VERSION 5.8 ;
BUSBITCHARS "[]" ;
DIVIDERCHAR "/" ;
UNITS
    DATABASE MICRONS 1000 ;
END UNITS

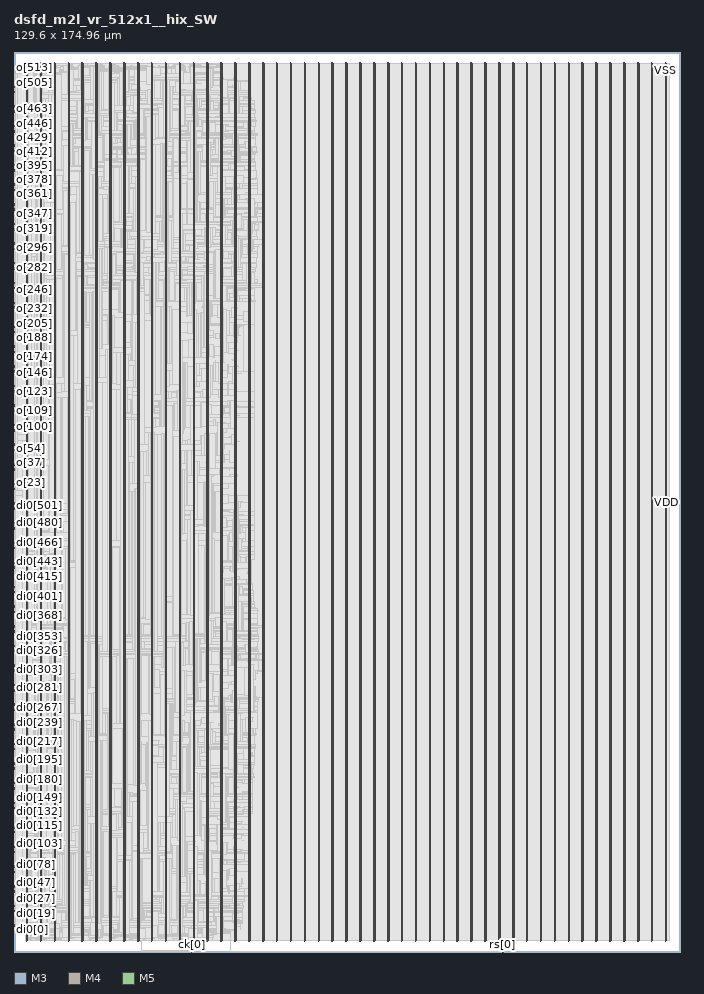
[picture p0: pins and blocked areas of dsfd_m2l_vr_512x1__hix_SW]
MACRO dsfd_m2l_vr_512x1__hix_SW
  FOREIGN dsfd_m2l_vr_512x1__hix_SW 0 0 ;
  CLASS BLOCK ;
  SIZE 129.6 BY 174.96 ;
  PIN ck[0]
    DIRECTION INPUT ;
    USE SIGNAL ;
    PORT
      LAYER M3 ;
        RECT  34.56 0 34.578 0.144 ;
    END
    PORT
      LAYER M3 ;
        RECT  34.56 0.108 34.578 0.221 ;
    END
  END ck[0]
  PIN di0[0]
    DIRECTION INPUT ;
    USE SIGNAL ;
    PORT
      LAYER M4 ;
        RECT  0 4.416 0.192 4.44 ;
    END
  END di0[0]
  PIN di0[100]
    DIRECTION INPUT ;
    USE SIGNAL ;
    PORT
      LAYER M4 ;
        RECT  0 20.544 0.192 20.568 ;
    END
  END di0[100]
  PIN di0[101]
    DIRECTION INPUT ;
    USE SIGNAL ;
    PORT
      LAYER M4 ;
        RECT  0 20.736 0.192 20.76 ;
    END
  END di0[101]
  PIN di0[102]
    DIRECTION INPUT ;
    USE SIGNAL ;
    PORT
      LAYER M4 ;
        RECT  0 20.88 0.192 20.904 ;
    END
  END di0[102]
  PIN di0[103]
    DIRECTION INPUT ;
    USE SIGNAL ;
    PORT
      LAYER M4 ;
        RECT  0 21.024 0.192 21.048 ;
    END
  END di0[103]
  PIN di0[104]
    DIRECTION INPUT ;
    USE SIGNAL ;
    PORT
      LAYER M4 ;
        RECT  0 21.216 0.192 21.24 ;
    END
  END di0[104]
  PIN di0[105]
    DIRECTION INPUT ;
    USE SIGNAL ;
    PORT
      LAYER M4 ;
        RECT  0 21.36 0.192 21.384 ;
    END
  END di0[105]
  PIN di0[106]
    DIRECTION INPUT ;
    USE SIGNAL ;
    PORT
      LAYER M4 ;
        RECT  0 21.552 0.192 21.576 ;
    END
  END di0[106]
  PIN di0[107]
    DIRECTION INPUT ;
    USE SIGNAL ;
    PORT
      LAYER M4 ;
        RECT  0 21.696 0.192 21.72 ;
    END
  END di0[107]
  PIN di0[108]
    DIRECTION INPUT ;
    USE SIGNAL ;
    PORT
      LAYER M4 ;
        RECT  0 21.84 0.192 21.864 ;
    END
  END di0[108]
  PIN di0[109]
    DIRECTION INPUT ;
    USE SIGNAL ;
    PORT
      LAYER M4 ;
        RECT  0 22.032 0.192 22.056 ;
    END
  END di0[109]
  PIN di0[10]
    DIRECTION INPUT ;
    USE SIGNAL ;
    PORT
      LAYER M4 ;
        RECT  0 6.048 0.192 6.072 ;
    END
  END di0[10]
  PIN di0[110]
    DIRECTION INPUT ;
    USE SIGNAL ;
    PORT
      LAYER M4 ;
        RECT  0 22.176 0.192 22.2 ;
    END
  END di0[110]
  PIN di0[111]
    DIRECTION INPUT ;
    USE SIGNAL ;
    PORT
      LAYER M4 ;
        RECT  0 22.32 0.192 22.344 ;
    END
  END di0[111]
  PIN di0[112]
    DIRECTION INPUT ;
    USE SIGNAL ;
    PORT
      LAYER M4 ;
        RECT  0 22.512 0.192 22.536 ;
    END
  END di0[112]
  PIN di0[113]
    DIRECTION INPUT ;
    USE SIGNAL ;
    PORT
      LAYER M4 ;
        RECT  0 22.656 0.192 22.68 ;
    END
  END di0[113]
  PIN di0[114]
    DIRECTION INPUT ;
    USE SIGNAL ;
    PORT
      LAYER M4 ;
        RECT  0 22.8 0.192 22.824 ;
    END
  END di0[114]
  PIN di0[115]
    DIRECTION INPUT ;
    USE SIGNAL ;
    PORT
      LAYER M4 ;
        RECT  0 22.992 0.192 23.016 ;
    END
  END di0[115]
  PIN di0[116]
    DIRECTION INPUT ;
    USE SIGNAL ;
    PORT
      LAYER M4 ;
        RECT  0 23.136 0.192 23.16 ;
    END
  END di0[116]
  PIN di0[117]
    DIRECTION INPUT ;
    USE SIGNAL ;
    PORT
      LAYER M4 ;
        RECT  0 23.328 0.192 23.352 ;
    END
  END di0[117]
  PIN di0[118]
    DIRECTION INPUT ;
    USE SIGNAL ;
    PORT
      LAYER M4 ;
        RECT  0 23.472 0.192 23.496 ;
    END
  END di0[118]
  PIN di0[119]
    DIRECTION INPUT ;
    USE SIGNAL ;
    PORT
      LAYER M4 ;
        RECT  0 23.616 0.192 23.64 ;
    END
  END di0[119]
  PIN di0[11]
    DIRECTION INPUT ;
    USE SIGNAL ;
    PORT
      LAYER M4 ;
        RECT  0 6.192 0.192 6.216 ;
    END
  END di0[11]
  PIN di0[120]
    DIRECTION INPUT ;
    USE SIGNAL ;
    PORT
      LAYER M4 ;
        RECT  0 23.808 0.192 23.832 ;
    END
  END di0[120]
  PIN di0[121]
    DIRECTION INPUT ;
    USE SIGNAL ;
    PORT
      LAYER M4 ;
        RECT  0 23.952 0.192 23.976 ;
    END
  END di0[121]
  PIN di0[122]
    DIRECTION INPUT ;
    USE SIGNAL ;
    PORT
      LAYER M4 ;
        RECT  0 24.096 0.192 24.12 ;
    END
  END di0[122]
  PIN di0[123]
    DIRECTION INPUT ;
    USE SIGNAL ;
    PORT
      LAYER M4 ;
        RECT  0 24.288 0.192 24.312 ;
    END
  END di0[123]
  PIN di0[124]
    DIRECTION INPUT ;
    USE SIGNAL ;
    PORT
      LAYER M4 ;
        RECT  0 24.432 0.192 24.456 ;
    END
  END di0[124]
  PIN di0[125]
    DIRECTION INPUT ;
    USE SIGNAL ;
    PORT
      LAYER M4 ;
        RECT  0 24.576 0.192 24.6 ;
    END
  END di0[125]
  PIN di0[126]
    DIRECTION INPUT ;
    USE SIGNAL ;
    PORT
      LAYER M4 ;
        RECT  0 24.768 0.192 24.792 ;
    END
  END di0[126]
  PIN di0[127]
    DIRECTION INPUT ;
    USE SIGNAL ;
    PORT
      LAYER M4 ;
        RECT  0 24.912 0.192 24.936 ;
    END
  END di0[127]
  PIN di0[128]
    DIRECTION INPUT ;
    USE SIGNAL ;
    PORT
      LAYER M4 ;
        RECT  0 25.104 0.192 25.128 ;
    END
  END di0[128]
  PIN di0[129]
    DIRECTION INPUT ;
    USE SIGNAL ;
    PORT
      LAYER M4 ;
        RECT  0 25.248 0.192 25.272 ;
    END
  END di0[129]
  PIN di0[12]
    DIRECTION INPUT ;
    USE SIGNAL ;
    PORT
      LAYER M4 ;
        RECT  0 6.336 0.192 6.36 ;
    END
  END di0[12]
  PIN di0[130]
    DIRECTION INPUT ;
    USE SIGNAL ;
    PORT
      LAYER M4 ;
        RECT  0 25.392 0.192 25.416 ;
    END
  END di0[130]
  PIN di0[131]
    DIRECTION INPUT ;
    USE SIGNAL ;
    PORT
      LAYER M4 ;
        RECT  0 25.584 0.192 25.608 ;
    END
  END di0[131]
  PIN di0[132]
    DIRECTION INPUT ;
    USE SIGNAL ;
    PORT
      LAYER M4 ;
        RECT  0 25.728 0.192 25.752 ;
    END
  END di0[132]
  PIN di0[133]
    DIRECTION INPUT ;
    USE SIGNAL ;
    PORT
      LAYER M4 ;
        RECT  0 25.872 0.192 25.896 ;
    END
  END di0[133]
  PIN di0[134]
    DIRECTION INPUT ;
    USE SIGNAL ;
    PORT
      LAYER M4 ;
        RECT  0 26.064 0.192 26.088 ;
    END
  END di0[134]
  PIN di0[135]
    DIRECTION INPUT ;
    USE SIGNAL ;
    PORT
      LAYER M4 ;
        RECT  0 26.208 0.192 26.232 ;
    END
  END di0[135]
  PIN di0[136]
    DIRECTION INPUT ;
    USE SIGNAL ;
    PORT
      LAYER M4 ;
        RECT  0 26.352 0.192 26.376 ;
    END
  END di0[136]
  PIN di0[137]
    DIRECTION INPUT ;
    USE SIGNAL ;
    PORT
      LAYER M4 ;
        RECT  0 26.544 0.192 26.568 ;
    END
  END di0[137]
  PIN di0[138]
    DIRECTION INPUT ;
    USE SIGNAL ;
    PORT
      LAYER M4 ;
        RECT  0 26.688 0.192 26.712 ;
    END
  END di0[138]
  PIN di0[139]
    DIRECTION INPUT ;
    USE SIGNAL ;
    PORT
      LAYER M4 ;
        RECT  0 26.88 0.192 26.904 ;
    END
  END di0[139]
  PIN di0[13]
    DIRECTION INPUT ;
    USE SIGNAL ;
    PORT
      LAYER M4 ;
        RECT  0 6.528 0.192 6.552 ;
    END
  END di0[13]
  PIN di0[140]
    DIRECTION INPUT ;
    USE SIGNAL ;
    PORT
      LAYER M4 ;
        RECT  0 27.024 0.192 27.048 ;
    END
  END di0[140]
  PIN di0[141]
    DIRECTION INPUT ;
    USE SIGNAL ;
    PORT
      LAYER M4 ;
        RECT  0 27.168 0.192 27.192 ;
    END
  END di0[141]
  PIN di0[142]
    DIRECTION INPUT ;
    USE SIGNAL ;
    PORT
      LAYER M4 ;
        RECT  0 27.36 0.192 27.384 ;
    END
  END di0[142]
  PIN di0[143]
    DIRECTION INPUT ;
    USE SIGNAL ;
    PORT
      LAYER M4 ;
        RECT  0 27.504 0.192 27.528 ;
    END
  END di0[143]
  PIN di0[144]
    DIRECTION INPUT ;
    USE SIGNAL ;
    PORT
      LAYER M4 ;
        RECT  0 27.648 0.192 27.672 ;
    END
  END di0[144]
  PIN di0[145]
    DIRECTION INPUT ;
    USE SIGNAL ;
    PORT
      LAYER M4 ;
        RECT  0 27.84 0.192 27.864 ;
    END
  END di0[145]
  PIN di0[146]
    DIRECTION INPUT ;
    USE SIGNAL ;
    PORT
      LAYER M4 ;
        RECT  0 27.984 0.192 28.008 ;
    END
  END di0[146]
  PIN di0[147]
    DIRECTION INPUT ;
    USE SIGNAL ;
    PORT
      LAYER M4 ;
        RECT  0 28.128 0.192 28.152 ;
    END
  END di0[147]
  PIN di0[148]
    DIRECTION INPUT ;
    USE SIGNAL ;
    PORT
      LAYER M4 ;
        RECT  0 28.32 0.192 28.344 ;
    END
  END di0[148]
  PIN di0[149]
    DIRECTION INPUT ;
    USE SIGNAL ;
    PORT
      LAYER M4 ;
        RECT  0 28.464 0.192 28.488 ;
    END
  END di0[149]
  PIN di0[14]
    DIRECTION INPUT ;
    USE SIGNAL ;
    PORT
      LAYER M4 ;
        RECT  0 6.672 0.192 6.696 ;
    END
  END di0[14]
  PIN di0[150]
    DIRECTION INPUT ;
    USE SIGNAL ;
    PORT
      LAYER M4 ;
        RECT  0 28.656 0.192 28.68 ;
    END
  END di0[150]
  PIN di0[151]
    DIRECTION INPUT ;
    USE SIGNAL ;
    PORT
      LAYER M4 ;
        RECT  0 28.8 0.192 28.824 ;
    END
  END di0[151]
  PIN di0[152]
    DIRECTION INPUT ;
    USE SIGNAL ;
    PORT
      LAYER M4 ;
        RECT  0 28.944 0.192 28.968 ;
    END
  END di0[152]
  PIN di0[153]
    DIRECTION INPUT ;
    USE SIGNAL ;
    PORT
      LAYER M4 ;
        RECT  0 29.136 0.192 29.16 ;
    END
  END di0[153]
  PIN di0[154]
    DIRECTION INPUT ;
    USE SIGNAL ;
    PORT
      LAYER M4 ;
        RECT  0 29.28 0.192 29.304 ;
    END
  END di0[154]
  PIN di0[155]
    DIRECTION INPUT ;
    USE SIGNAL ;
    PORT
      LAYER M4 ;
        RECT  0 29.424 0.192 29.448 ;
    END
  END di0[155]
  PIN di0[156]
    DIRECTION INPUT ;
    USE SIGNAL ;
    PORT
      LAYER M4 ;
        RECT  0 29.616 0.192 29.64 ;
    END
  END di0[156]
  PIN di0[157]
    DIRECTION INPUT ;
    USE SIGNAL ;
    PORT
      LAYER M4 ;
        RECT  0 29.76 0.192 29.784 ;
    END
  END di0[157]
  PIN di0[158]
    DIRECTION INPUT ;
    USE SIGNAL ;
    PORT
      LAYER M4 ;
        RECT  0 29.904 0.192 29.928 ;
    END
  END di0[158]
  PIN di0[159]
    DIRECTION INPUT ;
    USE SIGNAL ;
    PORT
      LAYER M4 ;
        RECT  0 30.096 0.192 30.12 ;
    END
  END di0[159]
  PIN di0[15]
    DIRECTION INPUT ;
    USE SIGNAL ;
    PORT
      LAYER M4 ;
        RECT  0 6.816 0.192 6.84 ;
    END
  END di0[15]
  PIN di0[160]
    DIRECTION INPUT ;
    USE SIGNAL ;
    PORT
      LAYER M4 ;
        RECT  0 30.24 0.192 30.264 ;
    END
  END di0[160]
  PIN di0[161]
    DIRECTION INPUT ;
    USE SIGNAL ;
    PORT
      LAYER M4 ;
        RECT  0 30.432 0.192 30.456 ;
    END
  END di0[161]
  PIN di0[162]
    DIRECTION INPUT ;
    USE SIGNAL ;
    PORT
      LAYER M4 ;
        RECT  0 30.576 0.192 30.6 ;
    END
  END di0[162]
  PIN di0[163]
    DIRECTION INPUT ;
    USE SIGNAL ;
    PORT
      LAYER M4 ;
        RECT  0 30.72 0.192 30.744 ;
    END
  END di0[163]
  PIN di0[164]
    DIRECTION INPUT ;
    USE SIGNAL ;
    PORT
      LAYER M4 ;
        RECT  0 30.912 0.192 30.936 ;
    END
  END di0[164]
  PIN di0[165]
    DIRECTION INPUT ;
    USE SIGNAL ;
    PORT
      LAYER M4 ;
        RECT  0 31.056 0.192 31.08 ;
    END
  END di0[165]
  PIN di0[166]
    DIRECTION INPUT ;
    USE SIGNAL ;
    PORT
      LAYER M4 ;
        RECT  0 31.2 0.192 31.224 ;
    END
  END di0[166]
  PIN di0[167]
    DIRECTION INPUT ;
    USE SIGNAL ;
    PORT
      LAYER M4 ;
        RECT  0 31.392 0.192 31.416 ;
    END
  END di0[167]
  PIN di0[168]
    DIRECTION INPUT ;
    USE SIGNAL ;
    PORT
      LAYER M4 ;
        RECT  0 31.536 0.192 31.56 ;
    END
  END di0[168]
  PIN di0[169]
    DIRECTION INPUT ;
    USE SIGNAL ;
    PORT
      LAYER M4 ;
        RECT  0 31.68 0.192 31.704 ;
    END
  END di0[169]
  PIN di0[16]
    DIRECTION INPUT ;
    USE SIGNAL ;
    PORT
      LAYER M4 ;
        RECT  0 7.008 0.192 7.032 ;
    END
  END di0[16]
  PIN di0[170]
    DIRECTION INPUT ;
    USE SIGNAL ;
    PORT
      LAYER M4 ;
        RECT  0 31.872 0.192 31.896 ;
    END
  END di0[170]
  PIN di0[171]
    DIRECTION INPUT ;
    USE SIGNAL ;
    PORT
      LAYER M4 ;
        RECT  0 32.016 0.192 32.04 ;
    END
  END di0[171]
  PIN di0[172]
    DIRECTION INPUT ;
    USE SIGNAL ;
    PORT
      LAYER M4 ;
        RECT  0 32.208 0.192 32.232 ;
    END
  END di0[172]
  PIN di0[173]
    DIRECTION INPUT ;
    USE SIGNAL ;
    PORT
      LAYER M4 ;
        RECT  0 32.352 0.192 32.376 ;
    END
  END di0[173]
  PIN di0[174]
    DIRECTION INPUT ;
    USE SIGNAL ;
    PORT
      LAYER M4 ;
        RECT  0 32.496 0.192 32.52 ;
    END
  END di0[174]
  PIN di0[175]
    DIRECTION INPUT ;
    USE SIGNAL ;
    PORT
      LAYER M4 ;
        RECT  0 32.688 0.192 32.712 ;
    END
  END di0[175]
  PIN di0[176]
    DIRECTION INPUT ;
    USE SIGNAL ;
    PORT
      LAYER M4 ;
        RECT  0 32.832 0.192 32.856 ;
    END
  END di0[176]
  PIN di0[177]
    DIRECTION INPUT ;
    USE SIGNAL ;
    PORT
      LAYER M4 ;
        RECT  0 32.976 0.192 33 ;
    END
  END di0[177]
  PIN di0[178]
    DIRECTION INPUT ;
    USE SIGNAL ;
    PORT
      LAYER M4 ;
        RECT  0 33.168 0.192 33.192 ;
    END
  END di0[178]
  PIN di0[179]
    DIRECTION INPUT ;
    USE SIGNAL ;
    PORT
      LAYER M4 ;
        RECT  0 33.312 0.192 33.336 ;
    END
  END di0[179]
  PIN di0[17]
    DIRECTION INPUT ;
    USE SIGNAL ;
    PORT
      LAYER M4 ;
        RECT  0 7.152 0.192 7.176 ;
    END
  END di0[17]
  PIN di0[180]
    DIRECTION INPUT ;
    USE SIGNAL ;
    PORT
      LAYER M4 ;
        RECT  0 33.456 0.192 33.48 ;
    END
  END di0[180]
  PIN di0[181]
    DIRECTION INPUT ;
    USE SIGNAL ;
    PORT
      LAYER M4 ;
        RECT  0 33.648 0.192 33.672 ;
    END
  END di0[181]
  PIN di0[182]
    DIRECTION INPUT ;
    USE SIGNAL ;
    PORT
      LAYER M4 ;
        RECT  0 33.792 0.192 33.816 ;
    END
  END di0[182]
  PIN di0[183]
    DIRECTION INPUT ;
    USE SIGNAL ;
    PORT
      LAYER M4 ;
        RECT  0 33.984 0.192 34.008 ;
    END
  END di0[183]
  PIN di0[184]
    DIRECTION INPUT ;
    USE SIGNAL ;
    PORT
      LAYER M4 ;
        RECT  0 34.128 0.192 34.152 ;
    END
  END di0[184]
  PIN di0[185]
    DIRECTION INPUT ;
    USE SIGNAL ;
    PORT
      LAYER M4 ;
        RECT  0 34.272 0.192 34.296 ;
    END
  END di0[185]
  PIN di0[186]
    DIRECTION INPUT ;
    USE SIGNAL ;
    PORT
      LAYER M4 ;
        RECT  0 34.464 0.192 34.488 ;
    END
  END di0[186]
  PIN di0[187]
    DIRECTION INPUT ;
    USE SIGNAL ;
    PORT
      LAYER M4 ;
        RECT  0 34.608 0.192 34.632 ;
    END
  END di0[187]
  PIN di0[188]
    DIRECTION INPUT ;
    USE SIGNAL ;
    PORT
      LAYER M4 ;
        RECT  0 34.752 0.192 34.776 ;
    END
  END di0[188]
  PIN di0[189]
    DIRECTION INPUT ;
    USE SIGNAL ;
    PORT
      LAYER M4 ;
        RECT  0 34.944 0.192 34.968 ;
    END
  END di0[189]
  PIN di0[18]
    DIRECTION INPUT ;
    USE SIGNAL ;
    PORT
      LAYER M4 ;
        RECT  0 7.296 0.192 7.32 ;
    END
  END di0[18]
  PIN di0[190]
    DIRECTION INPUT ;
    USE SIGNAL ;
    PORT
      LAYER M4 ;
        RECT  0 35.088 0.192 35.112 ;
    END
  END di0[190]
  PIN di0[191]
    DIRECTION INPUT ;
    USE SIGNAL ;
    PORT
      LAYER M4 ;
        RECT  0 35.232 0.192 35.256 ;
    END
  END di0[191]
  PIN di0[192]
    DIRECTION INPUT ;
    USE SIGNAL ;
    PORT
      LAYER M4 ;
        RECT  0 35.424 0.192 35.448 ;
    END
  END di0[192]
  PIN di0[193]
    DIRECTION INPUT ;
    USE SIGNAL ;
    PORT
      LAYER M4 ;
        RECT  0 35.568 0.192 35.592 ;
    END
  END di0[193]
  PIN di0[194]
    DIRECTION INPUT ;
    USE SIGNAL ;
    PORT
      LAYER M4 ;
        RECT  0 35.76 0.192 35.784 ;
    END
  END di0[194]
  PIN di0[195]
    DIRECTION INPUT ;
    USE SIGNAL ;
    PORT
      LAYER M4 ;
        RECT  0 35.904 0.192 35.928 ;
    END
  END di0[195]
  PIN di0[196]
    DIRECTION INPUT ;
    USE SIGNAL ;
    PORT
      LAYER M4 ;
        RECT  0 36.048 0.192 36.072 ;
    END
  END di0[196]
  PIN di0[197]
    DIRECTION INPUT ;
    USE SIGNAL ;
    PORT
      LAYER M4 ;
        RECT  0 36.24 0.192 36.264 ;
    END
  END di0[197]
  PIN di0[198]
    DIRECTION INPUT ;
    USE SIGNAL ;
    PORT
      LAYER M4 ;
        RECT  0 36.384 0.192 36.408 ;
    END
  END di0[198]
  PIN di0[199]
    DIRECTION INPUT ;
    USE SIGNAL ;
    PORT
      LAYER M4 ;
        RECT  0 36.528 0.192 36.552 ;
    END
  END di0[199]
  PIN di0[19]
    DIRECTION INPUT ;
    USE SIGNAL ;
    PORT
      LAYER M4 ;
        RECT  0 7.488 0.192 7.512 ;
    END
  END di0[19]
  PIN di0[1]
    DIRECTION INPUT ;
    USE SIGNAL ;
    PORT
      LAYER M4 ;
        RECT  0 4.56 0.192 4.584 ;
    END
  END di0[1]
  PIN di0[200]
    DIRECTION INPUT ;
    USE SIGNAL ;
    PORT
      LAYER M4 ;
        RECT  0 36.72 0.192 36.744 ;
    END
  END di0[200]
  PIN di0[201]
    DIRECTION INPUT ;
    USE SIGNAL ;
    PORT
      LAYER M4 ;
        RECT  0 36.864 0.192 36.888 ;
    END
  END di0[201]
  PIN di0[202]
    DIRECTION INPUT ;
    USE SIGNAL ;
    PORT
      LAYER M4 ;
        RECT  0 37.008 0.192 37.032 ;
    END
  END di0[202]
  PIN di0[203]
    DIRECTION INPUT ;
    USE SIGNAL ;
    PORT
      LAYER M4 ;
        RECT  0 37.2 0.192 37.224 ;
    END
  END di0[203]
  PIN di0[204]
    DIRECTION INPUT ;
    USE SIGNAL ;
    PORT
      LAYER M4 ;
        RECT  0 37.344 0.192 37.368 ;
    END
  END di0[204]
  PIN di0[205]
    DIRECTION INPUT ;
    USE SIGNAL ;
    PORT
      LAYER M4 ;
        RECT  0 37.536 0.192 37.56 ;
    END
  END di0[205]
  PIN di0[206]
    DIRECTION INPUT ;
    USE SIGNAL ;
    PORT
      LAYER M4 ;
        RECT  0 37.68 0.192 37.704 ;
    END
  END di0[206]
  PIN di0[207]
    DIRECTION INPUT ;
    USE SIGNAL ;
    PORT
      LAYER M4 ;
        RECT  0 37.824 0.192 37.848 ;
    END
  END di0[207]
  PIN di0[208]
    DIRECTION INPUT ;
    USE SIGNAL ;
    PORT
      LAYER M4 ;
        RECT  0 38.016 0.192 38.04 ;
    END
  END di0[208]
  PIN di0[209]
    DIRECTION INPUT ;
    USE SIGNAL ;
    PORT
      LAYER M4 ;
        RECT  0 38.16 0.192 38.184 ;
    END
  END di0[209]
  PIN di0[20]
    DIRECTION INPUT ;
    USE SIGNAL ;
    PORT
      LAYER M4 ;
        RECT  0 7.632 0.192 7.656 ;
    END
  END di0[20]
  PIN di0[210]
    DIRECTION INPUT ;
    USE SIGNAL ;
    PORT
      LAYER M4 ;
        RECT  0 38.304 0.192 38.328 ;
    END
  END di0[210]
  PIN di0[211]
    DIRECTION INPUT ;
    USE SIGNAL ;
    PORT
      LAYER M4 ;
        RECT  0 38.496 0.192 38.52 ;
    END
  END di0[211]
  PIN di0[212]
    DIRECTION INPUT ;
    USE SIGNAL ;
    PORT
      LAYER M4 ;
        RECT  0 38.64 0.192 38.664 ;
    END
  END di0[212]
  PIN di0[213]
    DIRECTION INPUT ;
    USE SIGNAL ;
    PORT
      LAYER M4 ;
        RECT  0 38.784 0.192 38.808 ;
    END
  END di0[213]
  PIN di0[214]
    DIRECTION INPUT ;
    USE SIGNAL ;
    PORT
      LAYER M4 ;
        RECT  0 38.976 0.192 39 ;
    END
  END di0[214]
  PIN di0[215]
    DIRECTION INPUT ;
    USE SIGNAL ;
    PORT
      LAYER M4 ;
        RECT  0 39.12 0.192 39.144 ;
    END
  END di0[215]
  PIN di0[216]
    DIRECTION INPUT ;
    USE SIGNAL ;
    PORT
      LAYER M4 ;
        RECT  0 39.312 0.192 39.336 ;
    END
  END di0[216]
  PIN di0[217]
    DIRECTION INPUT ;
    USE SIGNAL ;
    PORT
      LAYER M4 ;
        RECT  0 39.456 0.192 39.48 ;
    END
  END di0[217]
  PIN di0[218]
    DIRECTION INPUT ;
    USE SIGNAL ;
    PORT
      LAYER M4 ;
        RECT  0 39.6 0.192 39.624 ;
    END
  END di0[218]
  PIN di0[219]
    DIRECTION INPUT ;
    USE SIGNAL ;
    PORT
      LAYER M4 ;
        RECT  0 39.792 0.192 39.816 ;
    END
  END di0[219]
  PIN di0[21]
    DIRECTION INPUT ;
    USE SIGNAL ;
    PORT
      LAYER M4 ;
        RECT  0 7.824 0.192 7.848 ;
    END
  END di0[21]
  PIN di0[220]
    DIRECTION INPUT ;
    USE SIGNAL ;
    PORT
      LAYER M4 ;
        RECT  0 39.936 0.192 39.96 ;
    END
  END di0[220]
  PIN di0[221]
    DIRECTION INPUT ;
    USE SIGNAL ;
    PORT
      LAYER M4 ;
        RECT  0 40.08 0.192 40.104 ;
    END
  END di0[221]
  PIN di0[222]
    DIRECTION INPUT ;
    USE SIGNAL ;
    PORT
      LAYER M4 ;
        RECT  0 40.272 0.192 40.296 ;
    END
  END di0[222]
  PIN di0[223]
    DIRECTION INPUT ;
    USE SIGNAL ;
    PORT
      LAYER M4 ;
        RECT  0 40.416 0.192 40.44 ;
    END
  END di0[223]
  PIN di0[224]
    DIRECTION INPUT ;
    USE SIGNAL ;
    PORT
      LAYER M4 ;
        RECT  0 40.56 0.192 40.584 ;
    END
  END di0[224]
  PIN di0[225]
    DIRECTION INPUT ;
    USE SIGNAL ;
    PORT
      LAYER M4 ;
        RECT  0 40.752 0.192 40.776 ;
    END
  END di0[225]
  PIN di0[226]
    DIRECTION INPUT ;
    USE SIGNAL ;
    PORT
      LAYER M4 ;
        RECT  0 40.896 0.192 40.92 ;
    END
  END di0[226]
  PIN di0[227]
    DIRECTION INPUT ;
    USE SIGNAL ;
    PORT
      LAYER M4 ;
        RECT  0 41.088 0.192 41.112 ;
    END
  END di0[227]
  PIN di0[228]
    DIRECTION INPUT ;
    USE SIGNAL ;
    PORT
      LAYER M4 ;
        RECT  0 41.232 0.192 41.256 ;
    END
  END di0[228]
  PIN di0[229]
    DIRECTION INPUT ;
    USE SIGNAL ;
    PORT
      LAYER M4 ;
        RECT  0 41.376 0.192 41.4 ;
    END
  END di0[229]
  PIN di0[22]
    DIRECTION INPUT ;
    USE SIGNAL ;
    PORT
      LAYER M4 ;
        RECT  0 7.968 0.192 7.992 ;
    END
  END di0[22]
  PIN di0[230]
    DIRECTION INPUT ;
    USE SIGNAL ;
    PORT
      LAYER M4 ;
        RECT  0 41.568 0.192 41.592 ;
    END
  END di0[230]
  PIN di0[231]
    DIRECTION INPUT ;
    USE SIGNAL ;
    PORT
      LAYER M4 ;
        RECT  0 41.712 0.192 41.736 ;
    END
  END di0[231]
  PIN di0[232]
    DIRECTION INPUT ;
    USE SIGNAL ;
    PORT
      LAYER M4 ;
        RECT  0 41.856 0.192 41.88 ;
    END
  END di0[232]
  PIN di0[233]
    DIRECTION INPUT ;
    USE SIGNAL ;
    PORT
      LAYER M4 ;
        RECT  0 42.048 0.192 42.072 ;
    END
  END di0[233]
  PIN di0[234]
    DIRECTION INPUT ;
    USE SIGNAL ;
    PORT
      LAYER M4 ;
        RECT  0 42.192 0.192 42.216 ;
    END
  END di0[234]
  PIN di0[235]
    DIRECTION INPUT ;
    USE SIGNAL ;
    PORT
      LAYER M4 ;
        RECT  0 42.336 0.192 42.36 ;
    END
  END di0[235]
  PIN di0[236]
    DIRECTION INPUT ;
    USE SIGNAL ;
    PORT
      LAYER M4 ;
        RECT  0 42.528 0.192 42.552 ;
    END
  END di0[236]
  PIN di0[237]
    DIRECTION INPUT ;
    USE SIGNAL ;
    PORT
      LAYER M4 ;
        RECT  0 42.672 0.192 42.696 ;
    END
  END di0[237]
  PIN di0[238]
    DIRECTION INPUT ;
    USE SIGNAL ;
    PORT
      LAYER M4 ;
        RECT  0 42.864 0.192 42.888 ;
    END
  END di0[238]
  PIN di0[239]
    DIRECTION INPUT ;
    USE SIGNAL ;
    PORT
      LAYER M4 ;
        RECT  0 43.008 0.192 43.032 ;
    END
  END di0[239]
  PIN di0[23]
    DIRECTION INPUT ;
    USE SIGNAL ;
    PORT
      LAYER M4 ;
        RECT  0 8.112 0.192 8.136 ;
    END
  END di0[23]
  PIN di0[240]
    DIRECTION INPUT ;
    USE SIGNAL ;
    PORT
      LAYER M4 ;
        RECT  0 43.152 0.192 43.176 ;
    END
  END di0[240]
  PIN di0[241]
    DIRECTION INPUT ;
    USE SIGNAL ;
    PORT
      LAYER M4 ;
        RECT  0 43.344 0.192 43.368 ;
    END
  END di0[241]
  PIN di0[242]
    DIRECTION INPUT ;
    USE SIGNAL ;
    PORT
      LAYER M4 ;
        RECT  0 43.488 0.192 43.512 ;
    END
  END di0[242]
  PIN di0[243]
    DIRECTION INPUT ;
    USE SIGNAL ;
    PORT
      LAYER M4 ;
        RECT  0 43.632 0.192 43.656 ;
    END
  END di0[243]
  PIN di0[244]
    DIRECTION INPUT ;
    USE SIGNAL ;
    PORT
      LAYER M4 ;
        RECT  0 43.824 0.192 43.848 ;
    END
  END di0[244]
  PIN di0[245]
    DIRECTION INPUT ;
    USE SIGNAL ;
    PORT
      LAYER M4 ;
        RECT  0 43.968 0.192 43.992 ;
    END
  END di0[245]
  PIN di0[246]
    DIRECTION INPUT ;
    USE SIGNAL ;
    PORT
      LAYER M4 ;
        RECT  0 44.112 0.192 44.136 ;
    END
  END di0[246]
  PIN di0[247]
    DIRECTION INPUT ;
    USE SIGNAL ;
    PORT
      LAYER M4 ;
        RECT  0 44.304 0.192 44.328 ;
    END
  END di0[247]
  PIN di0[248]
    DIRECTION INPUT ;
    USE SIGNAL ;
    PORT
      LAYER M4 ;
        RECT  0 44.448 0.192 44.472 ;
    END
  END di0[248]
  PIN di0[249]
    DIRECTION INPUT ;
    USE SIGNAL ;
    PORT
      LAYER M4 ;
        RECT  0 44.64 0.192 44.664 ;
    END
  END di0[249]
  PIN di0[24]
    DIRECTION INPUT ;
    USE SIGNAL ;
    PORT
      LAYER M4 ;
        RECT  0 8.304 0.192 8.328 ;
    END
  END di0[24]
  PIN di0[250]
    DIRECTION INPUT ;
    USE SIGNAL ;
    PORT
      LAYER M4 ;
        RECT  0 44.784 0.192 44.808 ;
    END
  END di0[250]
  PIN di0[251]
    DIRECTION INPUT ;
    USE SIGNAL ;
    PORT
      LAYER M4 ;
        RECT  0 44.928 0.192 44.952 ;
    END
  END di0[251]
  PIN di0[252]
    DIRECTION INPUT ;
    USE SIGNAL ;
    PORT
      LAYER M4 ;
        RECT  0 45.12 0.192 45.144 ;
    END
  END di0[252]
  PIN di0[253]
    DIRECTION INPUT ;
    USE SIGNAL ;
    PORT
      LAYER M4 ;
        RECT  0 45.264 0.192 45.288 ;
    END
  END di0[253]
  PIN di0[254]
    DIRECTION INPUT ;
    USE SIGNAL ;
    PORT
      LAYER M4 ;
        RECT  0 45.408 0.192 45.432 ;
    END
  END di0[254]
  PIN di0[255]
    DIRECTION INPUT ;
    USE SIGNAL ;
    PORT
      LAYER M4 ;
        RECT  0 45.6 0.192 45.624 ;
    END
  END di0[255]
  PIN di0[256]
    DIRECTION INPUT ;
    USE SIGNAL ;
    PORT
      LAYER M4 ;
        RECT  0 45.744 0.192 45.768 ;
    END
  END di0[256]
  PIN di0[257]
    DIRECTION INPUT ;
    USE SIGNAL ;
    PORT
      LAYER M4 ;
        RECT  0 45.888 0.192 45.912 ;
    END
  END di0[257]
  PIN di0[258]
    DIRECTION INPUT ;
    USE SIGNAL ;
    PORT
      LAYER M4 ;
        RECT  0 46.08 0.192 46.104 ;
    END
  END di0[258]
  PIN di0[259]
    DIRECTION INPUT ;
    USE SIGNAL ;
    PORT
      LAYER M4 ;
        RECT  0 46.224 0.192 46.248 ;
    END
  END di0[259]
  PIN di0[25]
    DIRECTION INPUT ;
    USE SIGNAL ;
    PORT
      LAYER M4 ;
        RECT  0 8.448 0.192 8.472 ;
    END
  END di0[25]
  PIN di0[260]
    DIRECTION INPUT ;
    USE SIGNAL ;
    PORT
      LAYER M4 ;
        RECT  0 46.416 0.192 46.44 ;
    END
  END di0[260]
  PIN di0[261]
    DIRECTION INPUT ;
    USE SIGNAL ;
    PORT
      LAYER M4 ;
        RECT  0 46.56 0.192 46.584 ;
    END
  END di0[261]
  PIN di0[262]
    DIRECTION INPUT ;
    USE SIGNAL ;
    PORT
      LAYER M4 ;
        RECT  0 46.704 0.192 46.728 ;
    END
  END di0[262]
  PIN di0[263]
    DIRECTION INPUT ;
    USE SIGNAL ;
    PORT
      LAYER M4 ;
        RECT  0 46.896 0.192 46.92 ;
    END
  END di0[263]
  PIN di0[264]
    DIRECTION INPUT ;
    USE SIGNAL ;
    PORT
      LAYER M4 ;
        RECT  0 47.04 0.192 47.064 ;
    END
  END di0[264]
  PIN di0[265]
    DIRECTION INPUT ;
    USE SIGNAL ;
    PORT
      LAYER M4 ;
        RECT  0 47.184 0.192 47.208 ;
    END
  END di0[265]
  PIN di0[266]
    DIRECTION INPUT ;
    USE SIGNAL ;
    PORT
      LAYER M4 ;
        RECT  0 47.376 0.192 47.4 ;
    END
  END di0[266]
  PIN di0[267]
    DIRECTION INPUT ;
    USE SIGNAL ;
    PORT
      LAYER M4 ;
        RECT  0 47.52 0.192 47.544 ;
    END
  END di0[267]
  PIN di0[268]
    DIRECTION INPUT ;
    USE SIGNAL ;
    PORT
      LAYER M4 ;
        RECT  0 47.712 0.192 47.736 ;
    END
  END di0[268]
  PIN di0[269]
    DIRECTION INPUT ;
    USE SIGNAL ;
    PORT
      LAYER M4 ;
        RECT  0 47.856 0.192 47.88 ;
    END
  END di0[269]
  PIN di0[26]
    DIRECTION INPUT ;
    USE SIGNAL ;
    PORT
      LAYER M4 ;
        RECT  0 8.592 0.192 8.616 ;
    END
  END di0[26]
  PIN di0[270]
    DIRECTION INPUT ;
    USE SIGNAL ;
    PORT
      LAYER M4 ;
        RECT  0 48 0.192 48.024 ;
    END
  END di0[270]
  PIN di0[271]
    DIRECTION INPUT ;
    USE SIGNAL ;
    PORT
      LAYER M4 ;
        RECT  0 48.192 0.192 48.216 ;
    END
  END di0[271]
  PIN di0[272]
    DIRECTION INPUT ;
    USE SIGNAL ;
    PORT
      LAYER M4 ;
        RECT  0 48.336 0.192 48.36 ;
    END
  END di0[272]
  PIN di0[273]
    DIRECTION INPUT ;
    USE SIGNAL ;
    PORT
      LAYER M4 ;
        RECT  0 48.48 0.192 48.504 ;
    END
  END di0[273]
  PIN di0[274]
    DIRECTION INPUT ;
    USE SIGNAL ;
    PORT
      LAYER M4 ;
        RECT  0 48.672 0.192 48.696 ;
    END
  END di0[274]
  PIN di0[275]
    DIRECTION INPUT ;
    USE SIGNAL ;
    PORT
      LAYER M4 ;
        RECT  0 48.816 0.192 48.84 ;
    END
  END di0[275]
  PIN di0[276]
    DIRECTION INPUT ;
    USE SIGNAL ;
    PORT
      LAYER M4 ;
        RECT  0 48.96 0.192 48.984 ;
    END
  END di0[276]
  PIN di0[277]
    DIRECTION INPUT ;
    USE SIGNAL ;
    PORT
      LAYER M4 ;
        RECT  0 49.152 0.192 49.176 ;
    END
  END di0[277]
  PIN di0[278]
    DIRECTION INPUT ;
    USE SIGNAL ;
    PORT
      LAYER M4 ;
        RECT  0 49.296 0.192 49.32 ;
    END
  END di0[278]
  PIN di0[279]
    DIRECTION INPUT ;
    USE SIGNAL ;
    PORT
      LAYER M4 ;
        RECT  0 49.488 0.192 49.512 ;
    END
  END di0[279]
  PIN di0[27]
    DIRECTION INPUT ;
    USE SIGNAL ;
    PORT
      LAYER M4 ;
        RECT  0 8.784 0.192 8.808 ;
    END
  END di0[27]
  PIN di0[280]
    DIRECTION INPUT ;
    USE SIGNAL ;
    PORT
      LAYER M4 ;
        RECT  0 49.632 0.192 49.656 ;
    END
  END di0[280]
  PIN di0[281]
    DIRECTION INPUT ;
    USE SIGNAL ;
    PORT
      LAYER M4 ;
        RECT  0 49.776 0.192 49.8 ;
    END
  END di0[281]
  PIN di0[282]
    DIRECTION INPUT ;
    USE SIGNAL ;
    PORT
      LAYER M4 ;
        RECT  0 49.968 0.192 49.992 ;
    END
  END di0[282]
  PIN di0[283]
    DIRECTION INPUT ;
    USE SIGNAL ;
    PORT
      LAYER M4 ;
        RECT  0 50.112 0.192 50.136 ;
    END
  END di0[283]
  PIN di0[284]
    DIRECTION INPUT ;
    USE SIGNAL ;
    PORT
      LAYER M4 ;
        RECT  0 50.256 0.192 50.28 ;
    END
  END di0[284]
  PIN di0[285]
    DIRECTION INPUT ;
    USE SIGNAL ;
    PORT
      LAYER M4 ;
        RECT  0 50.448 0.192 50.472 ;
    END
  END di0[285]
  PIN di0[286]
    DIRECTION INPUT ;
    USE SIGNAL ;
    PORT
      LAYER M4 ;
        RECT  0 50.592 0.192 50.616 ;
    END
  END di0[286]
  PIN di0[287]
    DIRECTION INPUT ;
    USE SIGNAL ;
    PORT
      LAYER M4 ;
        RECT  0 50.736 0.192 50.76 ;
    END
  END di0[287]
  PIN di0[288]
    DIRECTION INPUT ;
    USE SIGNAL ;
    PORT
      LAYER M4 ;
        RECT  0 50.928 0.192 50.952 ;
    END
  END di0[288]
  PIN di0[289]
    DIRECTION INPUT ;
    USE SIGNAL ;
    PORT
      LAYER M4 ;
        RECT  0 51.072 0.192 51.096 ;
    END
  END di0[289]
  PIN di0[28]
    DIRECTION INPUT ;
    USE SIGNAL ;
    PORT
      LAYER M4 ;
        RECT  0 8.928 0.192 8.952 ;
    END
  END di0[28]
  PIN di0[290]
    DIRECTION INPUT ;
    USE SIGNAL ;
    PORT
      LAYER M4 ;
        RECT  0 51.264 0.192 51.288 ;
    END
  END di0[290]
  PIN di0[291]
    DIRECTION INPUT ;
    USE SIGNAL ;
    PORT
      LAYER M4 ;
        RECT  0 51.408 0.192 51.432 ;
    END
  END di0[291]
  PIN di0[292]
    DIRECTION INPUT ;
    USE SIGNAL ;
    PORT
      LAYER M4 ;
        RECT  0 51.552 0.192 51.576 ;
    END
  END di0[292]
  PIN di0[293]
    DIRECTION INPUT ;
    USE SIGNAL ;
    PORT
      LAYER M4 ;
        RECT  0 51.744 0.192 51.768 ;
    END
  END di0[293]
  PIN di0[294]
    DIRECTION INPUT ;
    USE SIGNAL ;
    PORT
      LAYER M4 ;
        RECT  0 51.888 0.192 51.912 ;
    END
  END di0[294]
  PIN di0[295]
    DIRECTION INPUT ;
    USE SIGNAL ;
    PORT
      LAYER M4 ;
        RECT  0 52.032 0.192 52.056 ;
    END
  END di0[295]
  PIN di0[296]
    DIRECTION INPUT ;
    USE SIGNAL ;
    PORT
      LAYER M4 ;
        RECT  0 52.224 0.192 52.248 ;
    END
  END di0[296]
  PIN di0[297]
    DIRECTION INPUT ;
    USE SIGNAL ;
    PORT
      LAYER M4 ;
        RECT  0 52.368 0.192 52.392 ;
    END
  END di0[297]
  PIN di0[298]
    DIRECTION INPUT ;
    USE SIGNAL ;
    PORT
      LAYER M4 ;
        RECT  0 52.512 0.192 52.536 ;
    END
  END di0[298]
  PIN di0[299]
    DIRECTION INPUT ;
    USE SIGNAL ;
    PORT
      LAYER M4 ;
        RECT  0 52.704 0.192 52.728 ;
    END
  END di0[299]
  PIN di0[29]
    DIRECTION INPUT ;
    USE SIGNAL ;
    PORT
      LAYER M4 ;
        RECT  0 9.072 0.192 9.096 ;
    END
  END di0[29]
  PIN di0[2]
    DIRECTION INPUT ;
    USE SIGNAL ;
    PORT
      LAYER M4 ;
        RECT  0 4.752 0.192 4.776 ;
    END
  END di0[2]
  PIN di0[300]
    DIRECTION INPUT ;
    USE SIGNAL ;
    PORT
      LAYER M4 ;
        RECT  0 52.848 0.192 52.872 ;
    END
  END di0[300]
  PIN di0[301]
    DIRECTION INPUT ;
    USE SIGNAL ;
    PORT
      LAYER M4 ;
        RECT  0 53.04 0.192 53.064 ;
    END
  END di0[301]
  PIN di0[302]
    DIRECTION INPUT ;
    USE SIGNAL ;
    PORT
      LAYER M4 ;
        RECT  0 53.184 0.192 53.208 ;
    END
  END di0[302]
  PIN di0[303]
    DIRECTION INPUT ;
    USE SIGNAL ;
    PORT
      LAYER M4 ;
        RECT  0 53.328 0.192 53.352 ;
    END
  END di0[303]
  PIN di0[304]
    DIRECTION INPUT ;
    USE SIGNAL ;
    PORT
      LAYER M4 ;
        RECT  0 53.52 0.192 53.544 ;
    END
  END di0[304]
  PIN di0[305]
    DIRECTION INPUT ;
    USE SIGNAL ;
    PORT
      LAYER M4 ;
        RECT  0 53.664 0.192 53.688 ;
    END
  END di0[305]
  PIN di0[306]
    DIRECTION INPUT ;
    USE SIGNAL ;
    PORT
      LAYER M4 ;
        RECT  0 53.808 0.192 53.832 ;
    END
  END di0[306]
  PIN di0[307]
    DIRECTION INPUT ;
    USE SIGNAL ;
    PORT
      LAYER M4 ;
        RECT  0 54 0.192 54.024 ;
    END
  END di0[307]
  PIN di0[308]
    DIRECTION INPUT ;
    USE SIGNAL ;
    PORT
      LAYER M4 ;
        RECT  0 54.144 0.192 54.168 ;
    END
  END di0[308]
  PIN di0[309]
    DIRECTION INPUT ;
    USE SIGNAL ;
    PORT
      LAYER M4 ;
        RECT  0 54.288 0.192 54.312 ;
    END
  END di0[309]
  PIN di0[30]
    DIRECTION INPUT ;
    USE SIGNAL ;
    PORT
      LAYER M4 ;
        RECT  0 9.264 0.192 9.288 ;
    END
  END di0[30]
  PIN di0[310]
    DIRECTION INPUT ;
    USE SIGNAL ;
    PORT
      LAYER M4 ;
        RECT  0 54.48 0.192 54.504 ;
    END
  END di0[310]
  PIN di0[311]
    DIRECTION INPUT ;
    USE SIGNAL ;
    PORT
      LAYER M4 ;
        RECT  0 54.624 0.192 54.648 ;
    END
  END di0[311]
  PIN di0[312]
    DIRECTION INPUT ;
    USE SIGNAL ;
    PORT
      LAYER M4 ;
        RECT  0 54.816 0.192 54.84 ;
    END
  END di0[312]
  PIN di0[313]
    DIRECTION INPUT ;
    USE SIGNAL ;
    PORT
      LAYER M4 ;
        RECT  0 54.96 0.192 54.984 ;
    END
  END di0[313]
  PIN di0[314]
    DIRECTION INPUT ;
    USE SIGNAL ;
    PORT
      LAYER M4 ;
        RECT  0 55.104 0.192 55.128 ;
    END
  END di0[314]
  PIN di0[315]
    DIRECTION INPUT ;
    USE SIGNAL ;
    PORT
      LAYER M4 ;
        RECT  0 55.296 0.192 55.32 ;
    END
  END di0[315]
  PIN di0[316]
    DIRECTION INPUT ;
    USE SIGNAL ;
    PORT
      LAYER M4 ;
        RECT  0 55.44 0.192 55.464 ;
    END
  END di0[316]
  PIN di0[317]
    DIRECTION INPUT ;
    USE SIGNAL ;
    PORT
      LAYER M4 ;
        RECT  0 55.584 0.192 55.608 ;
    END
  END di0[317]
  PIN di0[318]
    DIRECTION INPUT ;
    USE SIGNAL ;
    PORT
      LAYER M4 ;
        RECT  0 55.776 0.192 55.8 ;
    END
  END di0[318]
  PIN di0[319]
    DIRECTION INPUT ;
    USE SIGNAL ;
    PORT
      LAYER M4 ;
        RECT  0 55.92 0.192 55.944 ;
    END
  END di0[319]
  PIN di0[31]
    DIRECTION INPUT ;
    USE SIGNAL ;
    PORT
      LAYER M4 ;
        RECT  0 9.408 0.192 9.432 ;
    END
  END di0[31]
  PIN di0[320]
    DIRECTION INPUT ;
    USE SIGNAL ;
    PORT
      LAYER M4 ;
        RECT  0 56.064 0.192 56.088 ;
    END
  END di0[320]
  PIN di0[321]
    DIRECTION INPUT ;
    USE SIGNAL ;
    PORT
      LAYER M4 ;
        RECT  0 56.256 0.192 56.28 ;
    END
  END di0[321]
  PIN di0[322]
    DIRECTION INPUT ;
    USE SIGNAL ;
    PORT
      LAYER M4 ;
        RECT  0 56.4 0.192 56.424 ;
    END
  END di0[322]
  PIN di0[323]
    DIRECTION INPUT ;
    USE SIGNAL ;
    PORT
      LAYER M4 ;
        RECT  0 56.592 0.192 56.616 ;
    END
  END di0[323]
  PIN di0[324]
    DIRECTION INPUT ;
    USE SIGNAL ;
    PORT
      LAYER M4 ;
        RECT  0 56.736 0.192 56.76 ;
    END
  END di0[324]
  PIN di0[325]
    DIRECTION INPUT ;
    USE SIGNAL ;
    PORT
      LAYER M4 ;
        RECT  0 56.88 0.192 56.904 ;
    END
  END di0[325]
  PIN di0[326]
    DIRECTION INPUT ;
    USE SIGNAL ;
    PORT
      LAYER M4 ;
        RECT  0 57.072 0.192 57.096 ;
    END
  END di0[326]
  PIN di0[327]
    DIRECTION INPUT ;
    USE SIGNAL ;
    PORT
      LAYER M4 ;
        RECT  0 57.216 0.192 57.24 ;
    END
  END di0[327]
  PIN di0[328]
    DIRECTION INPUT ;
    USE SIGNAL ;
    PORT
      LAYER M4 ;
        RECT  0 57.36 0.192 57.384 ;
    END
  END di0[328]
  PIN di0[329]
    DIRECTION INPUT ;
    USE SIGNAL ;
    PORT
      LAYER M4 ;
        RECT  0 57.552 0.192 57.576 ;
    END
  END di0[329]
  PIN di0[32]
    DIRECTION INPUT ;
    USE SIGNAL ;
    PORT
      LAYER M4 ;
        RECT  0 9.6 0.192 9.624 ;
    END
  END di0[32]
  PIN di0[330]
    DIRECTION INPUT ;
    USE SIGNAL ;
    PORT
      LAYER M4 ;
        RECT  0 57.696 0.192 57.72 ;
    END
  END di0[330]
  PIN di0[331]
    DIRECTION INPUT ;
    USE SIGNAL ;
    PORT
      LAYER M4 ;
        RECT  0 57.84 0.192 57.864 ;
    END
  END di0[331]
  PIN di0[332]
    DIRECTION INPUT ;
    USE SIGNAL ;
    PORT
      LAYER M4 ;
        RECT  0 58.032 0.192 58.056 ;
    END
  END di0[332]
  PIN di0[333]
    DIRECTION INPUT ;
    USE SIGNAL ;
    PORT
      LAYER M4 ;
        RECT  0 58.176 0.192 58.2 ;
    END
  END di0[333]
  PIN di0[334]
    DIRECTION INPUT ;
    USE SIGNAL ;
    PORT
      LAYER M4 ;
        RECT  0 58.368 0.192 58.392 ;
    END
  END di0[334]
  PIN di0[335]
    DIRECTION INPUT ;
    USE SIGNAL ;
    PORT
      LAYER M4 ;
        RECT  0 58.512 0.192 58.536 ;
    END
  END di0[335]
  PIN di0[336]
    DIRECTION INPUT ;
    USE SIGNAL ;
    PORT
      LAYER M4 ;
        RECT  0 58.656 0.192 58.68 ;
    END
  END di0[336]
  PIN di0[337]
    DIRECTION INPUT ;
    USE SIGNAL ;
    PORT
      LAYER M4 ;
        RECT  0 58.848 0.192 58.872 ;
    END
  END di0[337]
  PIN di0[338]
    DIRECTION INPUT ;
    USE SIGNAL ;
    PORT
      LAYER M4 ;
        RECT  0 58.992 0.192 59.016 ;
    END
  END di0[338]
  PIN di0[339]
    DIRECTION INPUT ;
    USE SIGNAL ;
    PORT
      LAYER M4 ;
        RECT  0 59.136 0.192 59.16 ;
    END
  END di0[339]
  PIN di0[33]
    DIRECTION INPUT ;
    USE SIGNAL ;
    PORT
      LAYER M4 ;
        RECT  0 9.744 0.192 9.768 ;
    END
  END di0[33]
  PIN di0[340]
    DIRECTION INPUT ;
    USE SIGNAL ;
    PORT
      LAYER M4 ;
        RECT  0 59.328 0.192 59.352 ;
    END
  END di0[340]
  PIN di0[341]
    DIRECTION INPUT ;
    USE SIGNAL ;
    PORT
      LAYER M4 ;
        RECT  0 59.472 0.192 59.496 ;
    END
  END di0[341]
  PIN di0[342]
    DIRECTION INPUT ;
    USE SIGNAL ;
    PORT
      LAYER M4 ;
        RECT  0 59.616 0.192 59.64 ;
    END
  END di0[342]
  PIN di0[343]
    DIRECTION INPUT ;
    USE SIGNAL ;
    PORT
      LAYER M4 ;
        RECT  0 59.808 0.192 59.832 ;
    END
  END di0[343]
  PIN di0[344]
    DIRECTION INPUT ;
    USE SIGNAL ;
    PORT
      LAYER M4 ;
        RECT  0 59.952 0.192 59.976 ;
    END
  END di0[344]
  PIN di0[345]
    DIRECTION INPUT ;
    USE SIGNAL ;
    PORT
      LAYER M4 ;
        RECT  0 60.144 0.192 60.168 ;
    END
  END di0[345]
  PIN di0[346]
    DIRECTION INPUT ;
    USE SIGNAL ;
    PORT
      LAYER M4 ;
        RECT  0 60.288 0.192 60.312 ;
    END
  END di0[346]
  PIN di0[347]
    DIRECTION INPUT ;
    USE SIGNAL ;
    PORT
      LAYER M4 ;
        RECT  0 60.432 0.192 60.456 ;
    END
  END di0[347]
  PIN di0[348]
    DIRECTION INPUT ;
    USE SIGNAL ;
    PORT
      LAYER M4 ;
        RECT  0 60.624 0.192 60.648 ;
    END
  END di0[348]
  PIN di0[349]
    DIRECTION INPUT ;
    USE SIGNAL ;
    PORT
      LAYER M4 ;
        RECT  0 60.768 0.192 60.792 ;
    END
  END di0[349]
  PIN di0[34]
    DIRECTION INPUT ;
    USE SIGNAL ;
    PORT
      LAYER M4 ;
        RECT  0 9.888 0.192 9.912 ;
    END
  END di0[34]
  PIN di0[350]
    DIRECTION INPUT ;
    USE SIGNAL ;
    PORT
      LAYER M4 ;
        RECT  0 60.912 0.192 60.936 ;
    END
  END di0[350]
  PIN di0[351]
    DIRECTION INPUT ;
    USE SIGNAL ;
    PORT
      LAYER M4 ;
        RECT  0 61.104 0.192 61.128 ;
    END
  END di0[351]
  PIN di0[352]
    DIRECTION INPUT ;
    USE SIGNAL ;
    PORT
      LAYER M4 ;
        RECT  0 61.248 0.192 61.272 ;
    END
  END di0[352]
  PIN di0[353]
    DIRECTION INPUT ;
    USE SIGNAL ;
    PORT
      LAYER M4 ;
        RECT  0 61.392 0.192 61.416 ;
    END
  END di0[353]
  PIN di0[354]
    DIRECTION INPUT ;
    USE SIGNAL ;
    PORT
      LAYER M4 ;
        RECT  0 61.584 0.192 61.608 ;
    END
  END di0[354]
  PIN di0[355]
    DIRECTION INPUT ;
    USE SIGNAL ;
    PORT
      LAYER M4 ;
        RECT  0 61.728 0.192 61.752 ;
    END
  END di0[355]
  PIN di0[356]
    DIRECTION INPUT ;
    USE SIGNAL ;
    PORT
      LAYER M4 ;
        RECT  0 61.92 0.192 61.944 ;
    END
  END di0[356]
  PIN di0[357]
    DIRECTION INPUT ;
    USE SIGNAL ;
    PORT
      LAYER M4 ;
        RECT  0 62.064 0.192 62.088 ;
    END
  END di0[357]
  PIN di0[358]
    DIRECTION INPUT ;
    USE SIGNAL ;
    PORT
      LAYER M4 ;
        RECT  0 62.208 0.192 62.232 ;
    END
  END di0[358]
  PIN di0[359]
    DIRECTION INPUT ;
    USE SIGNAL ;
    PORT
      LAYER M4 ;
        RECT  0 62.4 0.192 62.424 ;
    END
  END di0[359]
  PIN di0[35]
    DIRECTION INPUT ;
    USE SIGNAL ;
    PORT
      LAYER M4 ;
        RECT  0 10.08 0.192 10.104 ;
    END
  END di0[35]
  PIN di0[360]
    DIRECTION INPUT ;
    USE SIGNAL ;
    PORT
      LAYER M4 ;
        RECT  0 62.544 0.192 62.568 ;
    END
  END di0[360]
  PIN di0[361]
    DIRECTION INPUT ;
    USE SIGNAL ;
    PORT
      LAYER M4 ;
        RECT  0 62.688 0.192 62.712 ;
    END
  END di0[361]
  PIN di0[362]
    DIRECTION INPUT ;
    USE SIGNAL ;
    PORT
      LAYER M4 ;
        RECT  0 62.88 0.192 62.904 ;
    END
  END di0[362]
  PIN di0[363]
    DIRECTION INPUT ;
    USE SIGNAL ;
    PORT
      LAYER M4 ;
        RECT  0 63.024 0.192 63.048 ;
    END
  END di0[363]
  PIN di0[364]
    DIRECTION INPUT ;
    USE SIGNAL ;
    PORT
      LAYER M4 ;
        RECT  0 63.168 0.192 63.192 ;
    END
  END di0[364]
  PIN di0[365]
    DIRECTION INPUT ;
    USE SIGNAL ;
    PORT
      LAYER M4 ;
        RECT  0 63.36 0.192 63.384 ;
    END
  END di0[365]
  PIN di0[366]
    DIRECTION INPUT ;
    USE SIGNAL ;
    PORT
      LAYER M4 ;
        RECT  0 63.504 0.192 63.528 ;
    END
  END di0[366]
  PIN di0[367]
    DIRECTION INPUT ;
    USE SIGNAL ;
    PORT
      LAYER M4 ;
        RECT  0 63.696 0.192 63.72 ;
    END
  END di0[367]
  PIN di0[368]
    DIRECTION INPUT ;
    USE SIGNAL ;
    PORT
      LAYER M4 ;
        RECT  0 63.84 0.192 63.864 ;
    END
  END di0[368]
  PIN di0[369]
    DIRECTION INPUT ;
    USE SIGNAL ;
    PORT
      LAYER M4 ;
        RECT  0 63.984 0.192 64.008 ;
    END
  END di0[369]
  PIN di0[36]
    DIRECTION INPUT ;
    USE SIGNAL ;
    PORT
      LAYER M4 ;
        RECT  0 10.224 0.192 10.248 ;
    END
  END di0[36]
  PIN di0[370]
    DIRECTION INPUT ;
    USE SIGNAL ;
    PORT
      LAYER M4 ;
        RECT  0 64.176 0.192 64.2 ;
    END
  END di0[370]
  PIN di0[371]
    DIRECTION INPUT ;
    USE SIGNAL ;
    PORT
      LAYER M4 ;
        RECT  0 64.32 0.192 64.344 ;
    END
  END di0[371]
  PIN di0[372]
    DIRECTION INPUT ;
    USE SIGNAL ;
    PORT
      LAYER M4 ;
        RECT  0 64.464 0.192 64.488 ;
    END
  END di0[372]
  PIN di0[373]
    DIRECTION INPUT ;
    USE SIGNAL ;
    PORT
      LAYER M4 ;
        RECT  0 64.656 0.192 64.68 ;
    END
  END di0[373]
  PIN di0[374]
    DIRECTION INPUT ;
    USE SIGNAL ;
    PORT
      LAYER M4 ;
        RECT  0 64.8 0.192 64.824 ;
    END
  END di0[374]
  PIN di0[375]
    DIRECTION INPUT ;
    USE SIGNAL ;
    PORT
      LAYER M4 ;
        RECT  0 64.944 0.192 64.968 ;
    END
  END di0[375]
  PIN di0[376]
    DIRECTION INPUT ;
    USE SIGNAL ;
    PORT
      LAYER M4 ;
        RECT  0 65.136 0.192 65.16 ;
    END
  END di0[376]
  PIN di0[377]
    DIRECTION INPUT ;
    USE SIGNAL ;
    PORT
      LAYER M4 ;
        RECT  0 65.28 0.192 65.304 ;
    END
  END di0[377]
  PIN di0[378]
    DIRECTION INPUT ;
    USE SIGNAL ;
    PORT
      LAYER M4 ;
        RECT  0 65.472 0.192 65.496 ;
    END
  END di0[378]
  PIN di0[379]
    DIRECTION INPUT ;
    USE SIGNAL ;
    PORT
      LAYER M4 ;
        RECT  0 65.616 0.192 65.64 ;
    END
  END di0[379]
  PIN di0[37]
    DIRECTION INPUT ;
    USE SIGNAL ;
    PORT
      LAYER M4 ;
        RECT  0 10.368 0.192 10.392 ;
    END
  END di0[37]
  PIN di0[380]
    DIRECTION INPUT ;
    USE SIGNAL ;
    PORT
      LAYER M4 ;
        RECT  0 65.76 0.192 65.784 ;
    END
  END di0[380]
  PIN di0[381]
    DIRECTION INPUT ;
    USE SIGNAL ;
    PORT
      LAYER M4 ;
        RECT  0 65.952 0.192 65.976 ;
    END
  END di0[381]
  PIN di0[382]
    DIRECTION INPUT ;
    USE SIGNAL ;
    PORT
      LAYER M4 ;
        RECT  0 66.096 0.192 66.12 ;
    END
  END di0[382]
  PIN di0[383]
    DIRECTION INPUT ;
    USE SIGNAL ;
    PORT
      LAYER M4 ;
        RECT  0 66.24 0.192 66.264 ;
    END
  END di0[383]
  PIN di0[384]
    DIRECTION INPUT ;
    USE SIGNAL ;
    PORT
      LAYER M4 ;
        RECT  0 66.432 0.192 66.456 ;
    END
  END di0[384]
  PIN di0[385]
    DIRECTION INPUT ;
    USE SIGNAL ;
    PORT
      LAYER M4 ;
        RECT  0 66.576 0.192 66.6 ;
    END
  END di0[385]
  PIN di0[386]
    DIRECTION INPUT ;
    USE SIGNAL ;
    PORT
      LAYER M4 ;
        RECT  0 66.72 0.192 66.744 ;
    END
  END di0[386]
  PIN di0[387]
    DIRECTION INPUT ;
    USE SIGNAL ;
    PORT
      LAYER M4 ;
        RECT  0 66.912 0.192 66.936 ;
    END
  END di0[387]
  PIN di0[388]
    DIRECTION INPUT ;
    USE SIGNAL ;
    PORT
      LAYER M4 ;
        RECT  0 67.056 0.192 67.08 ;
    END
  END di0[388]
  PIN di0[389]
    DIRECTION INPUT ;
    USE SIGNAL ;
    PORT
      LAYER M4 ;
        RECT  0 67.248 0.192 67.272 ;
    END
  END di0[389]
  PIN di0[38]
    DIRECTION INPUT ;
    USE SIGNAL ;
    PORT
      LAYER M4 ;
        RECT  0 10.56 0.192 10.584 ;
    END
  END di0[38]
  PIN di0[390]
    DIRECTION INPUT ;
    USE SIGNAL ;
    PORT
      LAYER M4 ;
        RECT  0 67.392 0.192 67.416 ;
    END
  END di0[390]
  PIN di0[391]
    DIRECTION INPUT ;
    USE SIGNAL ;
    PORT
      LAYER M4 ;
        RECT  0 67.536 0.192 67.56 ;
    END
  END di0[391]
  PIN di0[392]
    DIRECTION INPUT ;
    USE SIGNAL ;
    PORT
      LAYER M4 ;
        RECT  0 67.728 0.192 67.752 ;
    END
  END di0[392]
  PIN di0[393]
    DIRECTION INPUT ;
    USE SIGNAL ;
    PORT
      LAYER M4 ;
        RECT  0 67.872 0.192 67.896 ;
    END
  END di0[393]
  PIN di0[394]
    DIRECTION INPUT ;
    USE SIGNAL ;
    PORT
      LAYER M4 ;
        RECT  0 68.016 0.192 68.04 ;
    END
  END di0[394]
  PIN di0[395]
    DIRECTION INPUT ;
    USE SIGNAL ;
    PORT
      LAYER M4 ;
        RECT  0 68.208 0.192 68.232 ;
    END
  END di0[395]
  PIN di0[396]
    DIRECTION INPUT ;
    USE SIGNAL ;
    PORT
      LAYER M4 ;
        RECT  0 68.352 0.192 68.376 ;
    END
  END di0[396]
  PIN di0[397]
    DIRECTION INPUT ;
    USE SIGNAL ;
    PORT
      LAYER M4 ;
        RECT  0 68.496 0.192 68.52 ;
    END
  END di0[397]
  PIN di0[398]
    DIRECTION INPUT ;
    USE SIGNAL ;
    PORT
      LAYER M4 ;
        RECT  0 68.688 0.192 68.712 ;
    END
  END di0[398]
  PIN di0[399]
    DIRECTION INPUT ;
    USE SIGNAL ;
    PORT
      LAYER M4 ;
        RECT  0 68.832 0.192 68.856 ;
    END
  END di0[399]
  PIN di0[39]
    DIRECTION INPUT ;
    USE SIGNAL ;
    PORT
      LAYER M4 ;
        RECT  0 10.704 0.192 10.728 ;
    END
  END di0[39]
  PIN di0[3]
    DIRECTION INPUT ;
    USE SIGNAL ;
    PORT
      LAYER M4 ;
        RECT  0 4.896 0.192 4.92 ;
    END
  END di0[3]
  PIN di0[400]
    DIRECTION INPUT ;
    USE SIGNAL ;
    PORT
      LAYER M4 ;
        RECT  0 69.024 0.192 69.048 ;
    END
  END di0[400]
  PIN di0[401]
    DIRECTION INPUT ;
    USE SIGNAL ;
    PORT
      LAYER M4 ;
        RECT  0 69.168 0.192 69.192 ;
    END
  END di0[401]
  PIN di0[402]
    DIRECTION INPUT ;
    USE SIGNAL ;
    PORT
      LAYER M4 ;
        RECT  0 69.312 0.192 69.336 ;
    END
  END di0[402]
  PIN di0[403]
    DIRECTION INPUT ;
    USE SIGNAL ;
    PORT
      LAYER M4 ;
        RECT  0 69.504 0.192 69.528 ;
    END
  END di0[403]
  PIN di0[404]
    DIRECTION INPUT ;
    USE SIGNAL ;
    PORT
      LAYER M4 ;
        RECT  0 69.648 0.192 69.672 ;
    END
  END di0[404]
  PIN di0[405]
    DIRECTION INPUT ;
    USE SIGNAL ;
    PORT
      LAYER M4 ;
        RECT  0 69.792 0.192 69.816 ;
    END
  END di0[405]
  PIN di0[406]
    DIRECTION INPUT ;
    USE SIGNAL ;
    PORT
      LAYER M4 ;
        RECT  0 69.984 0.192 70.008 ;
    END
  END di0[406]
  PIN di0[407]
    DIRECTION INPUT ;
    USE SIGNAL ;
    PORT
      LAYER M4 ;
        RECT  0 70.128 0.192 70.152 ;
    END
  END di0[407]
  PIN di0[408]
    DIRECTION INPUT ;
    USE SIGNAL ;
    PORT
      LAYER M4 ;
        RECT  0 70.272 0.192 70.296 ;
    END
  END di0[408]
  PIN di0[409]
    DIRECTION INPUT ;
    USE SIGNAL ;
    PORT
      LAYER M4 ;
        RECT  0 70.464 0.192 70.488 ;
    END
  END di0[409]
  PIN di0[40]
    DIRECTION INPUT ;
    USE SIGNAL ;
    PORT
      LAYER M4 ;
        RECT  0 10.848 0.192 10.872 ;
    END
  END di0[40]
  PIN di0[410]
    DIRECTION INPUT ;
    USE SIGNAL ;
    PORT
      LAYER M4 ;
        RECT  0 70.608 0.192 70.632 ;
    END
  END di0[410]
  PIN di0[411]
    DIRECTION INPUT ;
    USE SIGNAL ;
    PORT
      LAYER M4 ;
        RECT  0 70.8 0.192 70.824 ;
    END
  END di0[411]
  PIN di0[412]
    DIRECTION INPUT ;
    USE SIGNAL ;
    PORT
      LAYER M4 ;
        RECT  0 70.944 0.192 70.968 ;
    END
  END di0[412]
  PIN di0[413]
    DIRECTION INPUT ;
    USE SIGNAL ;
    PORT
      LAYER M4 ;
        RECT  0 71.088 0.192 71.112 ;
    END
  END di0[413]
  PIN di0[414]
    DIRECTION INPUT ;
    USE SIGNAL ;
    PORT
      LAYER M4 ;
        RECT  0 71.28 0.192 71.304 ;
    END
  END di0[414]
  PIN di0[415]
    DIRECTION INPUT ;
    USE SIGNAL ;
    PORT
      LAYER M4 ;
        RECT  0 71.424 0.192 71.448 ;
    END
  END di0[415]
  PIN di0[416]
    DIRECTION INPUT ;
    USE SIGNAL ;
    PORT
      LAYER M4 ;
        RECT  0 71.568 0.192 71.592 ;
    END
  END di0[416]
  PIN di0[417]
    DIRECTION INPUT ;
    USE SIGNAL ;
    PORT
      LAYER M4 ;
        RECT  0 71.76 0.192 71.784 ;
    END
  END di0[417]
  PIN di0[418]
    DIRECTION INPUT ;
    USE SIGNAL ;
    PORT
      LAYER M4 ;
        RECT  0 71.904 0.192 71.928 ;
    END
  END di0[418]
  PIN di0[419]
    DIRECTION INPUT ;
    USE SIGNAL ;
    PORT
      LAYER M4 ;
        RECT  0 72.048 0.192 72.072 ;
    END
  END di0[419]
  PIN di0[41]
    DIRECTION INPUT ;
    USE SIGNAL ;
    PORT
      LAYER M4 ;
        RECT  0 11.04 0.192 11.064 ;
    END
  END di0[41]
  PIN di0[420]
    DIRECTION INPUT ;
    USE SIGNAL ;
    PORT
      LAYER M4 ;
        RECT  0 72.24 0.192 72.264 ;
    END
  END di0[420]
  PIN di0[421]
    DIRECTION INPUT ;
    USE SIGNAL ;
    PORT
      LAYER M4 ;
        RECT  0 72.384 0.192 72.408 ;
    END
  END di0[421]
  PIN di0[422]
    DIRECTION INPUT ;
    USE SIGNAL ;
    PORT
      LAYER M4 ;
        RECT  0 72.576 0.192 72.6 ;
    END
  END di0[422]
  PIN di0[423]
    DIRECTION INPUT ;
    USE SIGNAL ;
    PORT
      LAYER M4 ;
        RECT  0 72.72 0.192 72.744 ;
    END
  END di0[423]
  PIN di0[424]
    DIRECTION INPUT ;
    USE SIGNAL ;
    PORT
      LAYER M4 ;
        RECT  0 72.864 0.192 72.888 ;
    END
  END di0[424]
  PIN di0[425]
    DIRECTION INPUT ;
    USE SIGNAL ;
    PORT
      LAYER M4 ;
        RECT  0 73.056 0.192 73.08 ;
    END
  END di0[425]
  PIN di0[426]
    DIRECTION INPUT ;
    USE SIGNAL ;
    PORT
      LAYER M4 ;
        RECT  0 73.2 0.192 73.224 ;
    END
  END di0[426]
  PIN di0[427]
    DIRECTION INPUT ;
    USE SIGNAL ;
    PORT
      LAYER M4 ;
        RECT  0 73.344 0.192 73.368 ;
    END
  END di0[427]
  PIN di0[428]
    DIRECTION INPUT ;
    USE SIGNAL ;
    PORT
      LAYER M4 ;
        RECT  0 73.536 0.192 73.56 ;
    END
  END di0[428]
  PIN di0[429]
    DIRECTION INPUT ;
    USE SIGNAL ;
    PORT
      LAYER M4 ;
        RECT  0 73.68 0.192 73.704 ;
    END
  END di0[429]
  PIN di0[42]
    DIRECTION INPUT ;
    USE SIGNAL ;
    PORT
      LAYER M4 ;
        RECT  0 11.184 0.192 11.208 ;
    END
  END di0[42]
  PIN di0[430]
    DIRECTION INPUT ;
    USE SIGNAL ;
    PORT
      LAYER M4 ;
        RECT  0 73.824 0.192 73.848 ;
    END
  END di0[430]
  PIN di0[431]
    DIRECTION INPUT ;
    USE SIGNAL ;
    PORT
      LAYER M4 ;
        RECT  0 74.016 0.192 74.04 ;
    END
  END di0[431]
  PIN di0[432]
    DIRECTION INPUT ;
    USE SIGNAL ;
    PORT
      LAYER M4 ;
        RECT  0 74.16 0.192 74.184 ;
    END
  END di0[432]
  PIN di0[433]
    DIRECTION INPUT ;
    USE SIGNAL ;
    PORT
      LAYER M4 ;
        RECT  0 74.352 0.192 74.376 ;
    END
  END di0[433]
  PIN di0[434]
    DIRECTION INPUT ;
    USE SIGNAL ;
    PORT
      LAYER M4 ;
        RECT  0 74.496 0.192 74.52 ;
    END
  END di0[434]
  PIN di0[435]
    DIRECTION INPUT ;
    USE SIGNAL ;
    PORT
      LAYER M4 ;
        RECT  0 74.64 0.192 74.664 ;
    END
  END di0[435]
  PIN di0[436]
    DIRECTION INPUT ;
    USE SIGNAL ;
    PORT
      LAYER M4 ;
        RECT  0 74.832 0.192 74.856 ;
    END
  END di0[436]
  PIN di0[437]
    DIRECTION INPUT ;
    USE SIGNAL ;
    PORT
      LAYER M4 ;
        RECT  0 74.976 0.192 75 ;
    END
  END di0[437]
  PIN di0[438]
    DIRECTION INPUT ;
    USE SIGNAL ;
    PORT
      LAYER M4 ;
        RECT  0 75.12 0.192 75.144 ;
    END
  END di0[438]
  PIN di0[439]
    DIRECTION INPUT ;
    USE SIGNAL ;
    PORT
      LAYER M4 ;
        RECT  0 75.312 0.192 75.336 ;
    END
  END di0[439]
  PIN di0[43]
    DIRECTION INPUT ;
    USE SIGNAL ;
    PORT
      LAYER M4 ;
        RECT  0 11.376 0.192 11.4 ;
    END
  END di0[43]
  PIN di0[440]
    DIRECTION INPUT ;
    USE SIGNAL ;
    PORT
      LAYER M4 ;
        RECT  0 75.456 0.192 75.48 ;
    END
  END di0[440]
  PIN di0[441]
    DIRECTION INPUT ;
    USE SIGNAL ;
    PORT
      LAYER M4 ;
        RECT  0 75.6 0.192 75.624 ;
    END
  END di0[441]
  PIN di0[442]
    DIRECTION INPUT ;
    USE SIGNAL ;
    PORT
      LAYER M4 ;
        RECT  0 75.792 0.192 75.816 ;
    END
  END di0[442]
  PIN di0[443]
    DIRECTION INPUT ;
    USE SIGNAL ;
    PORT
      LAYER M4 ;
        RECT  0 75.936 0.192 75.96 ;
    END
  END di0[443]
  PIN di0[444]
    DIRECTION INPUT ;
    USE SIGNAL ;
    PORT
      LAYER M4 ;
        RECT  0 76.128 0.192 76.152 ;
    END
  END di0[444]
  PIN di0[445]
    DIRECTION INPUT ;
    USE SIGNAL ;
    PORT
      LAYER M4 ;
        RECT  0 76.272 0.192 76.296 ;
    END
  END di0[445]
  PIN di0[446]
    DIRECTION INPUT ;
    USE SIGNAL ;
    PORT
      LAYER M4 ;
        RECT  0 76.416 0.192 76.44 ;
    END
  END di0[446]
  PIN di0[447]
    DIRECTION INPUT ;
    USE SIGNAL ;
    PORT
      LAYER M4 ;
        RECT  0 76.608 0.192 76.632 ;
    END
  END di0[447]
  PIN di0[448]
    DIRECTION INPUT ;
    USE SIGNAL ;
    PORT
      LAYER M4 ;
        RECT  0 76.752 0.192 76.776 ;
    END
  END di0[448]
  PIN di0[449]
    DIRECTION INPUT ;
    USE SIGNAL ;
    PORT
      LAYER M4 ;
        RECT  0 76.896 0.192 76.92 ;
    END
  END di0[449]
  PIN di0[44]
    DIRECTION INPUT ;
    USE SIGNAL ;
    PORT
      LAYER M4 ;
        RECT  0 11.52 0.192 11.544 ;
    END
  END di0[44]
  PIN di0[450]
    DIRECTION INPUT ;
    USE SIGNAL ;
    PORT
      LAYER M4 ;
        RECT  0 77.088 0.192 77.112 ;
    END
  END di0[450]
  PIN di0[451]
    DIRECTION INPUT ;
    USE SIGNAL ;
    PORT
      LAYER M4 ;
        RECT  0 77.232 0.192 77.256 ;
    END
  END di0[451]
  PIN di0[452]
    DIRECTION INPUT ;
    USE SIGNAL ;
    PORT
      LAYER M4 ;
        RECT  0 77.376 0.192 77.4 ;
    END
  END di0[452]
  PIN di0[453]
    DIRECTION INPUT ;
    USE SIGNAL ;
    PORT
      LAYER M4 ;
        RECT  0 77.568 0.192 77.592 ;
    END
  END di0[453]
  PIN di0[454]
    DIRECTION INPUT ;
    USE SIGNAL ;
    PORT
      LAYER M4 ;
        RECT  0 77.712 0.192 77.736 ;
    END
  END di0[454]
  PIN di0[455]
    DIRECTION INPUT ;
    USE SIGNAL ;
    PORT
      LAYER M4 ;
        RECT  0 77.904 0.192 77.928 ;
    END
  END di0[455]
  PIN di0[456]
    DIRECTION INPUT ;
    USE SIGNAL ;
    PORT
      LAYER M4 ;
        RECT  0 78.048 0.192 78.072 ;
    END
  END di0[456]
  PIN di0[457]
    DIRECTION INPUT ;
    USE SIGNAL ;
    PORT
      LAYER M4 ;
        RECT  0 78.192 0.192 78.216 ;
    END
  END di0[457]
  PIN di0[458]
    DIRECTION INPUT ;
    USE SIGNAL ;
    PORT
      LAYER M4 ;
        RECT  0 78.384 0.192 78.408 ;
    END
  END di0[458]
  PIN di0[459]
    DIRECTION INPUT ;
    USE SIGNAL ;
    PORT
      LAYER M4 ;
        RECT  0 78.528 0.192 78.552 ;
    END
  END di0[459]
  PIN di0[45]
    DIRECTION INPUT ;
    USE SIGNAL ;
    PORT
      LAYER M4 ;
        RECT  0 11.664 0.192 11.688 ;
    END
  END di0[45]
  PIN di0[460]
    DIRECTION INPUT ;
    USE SIGNAL ;
    PORT
      LAYER M4 ;
        RECT  0 78.672 0.192 78.696 ;
    END
  END di0[460]
  PIN di0[461]
    DIRECTION INPUT ;
    USE SIGNAL ;
    PORT
      LAYER M4 ;
        RECT  0 78.864 0.192 78.888 ;
    END
  END di0[461]
  PIN di0[462]
    DIRECTION INPUT ;
    USE SIGNAL ;
    PORT
      LAYER M4 ;
        RECT  0 79.008 0.192 79.032 ;
    END
  END di0[462]
  PIN di0[463]
    DIRECTION INPUT ;
    USE SIGNAL ;
    PORT
      LAYER M4 ;
        RECT  0 79.2 0.192 79.224 ;
    END
  END di0[463]
  PIN di0[464]
    DIRECTION INPUT ;
    USE SIGNAL ;
    PORT
      LAYER M4 ;
        RECT  0 79.344 0.192 79.368 ;
    END
  END di0[464]
  PIN di0[465]
    DIRECTION INPUT ;
    USE SIGNAL ;
    PORT
      LAYER M4 ;
        RECT  0 79.488 0.192 79.512 ;
    END
  END di0[465]
  PIN di0[466]
    DIRECTION INPUT ;
    USE SIGNAL ;
    PORT
      LAYER M4 ;
        RECT  0 79.68 0.192 79.704 ;
    END
  END di0[466]
  PIN di0[467]
    DIRECTION INPUT ;
    USE SIGNAL ;
    PORT
      LAYER M4 ;
        RECT  0 79.824 0.192 79.848 ;
    END
  END di0[467]
  PIN di0[468]
    DIRECTION INPUT ;
    USE SIGNAL ;
    PORT
      LAYER M4 ;
        RECT  0 79.968 0.192 79.992 ;
    END
  END di0[468]
  PIN di0[469]
    DIRECTION INPUT ;
    USE SIGNAL ;
    PORT
      LAYER M4 ;
        RECT  0 80.16 0.192 80.184 ;
    END
  END di0[469]
  PIN di0[46]
    DIRECTION INPUT ;
    USE SIGNAL ;
    PORT
      LAYER M4 ;
        RECT  0 11.856 0.192 11.88 ;
    END
  END di0[46]
  PIN di0[470]
    DIRECTION INPUT ;
    USE SIGNAL ;
    PORT
      LAYER M4 ;
        RECT  0 80.304 0.192 80.328 ;
    END
  END di0[470]
  PIN di0[471]
    DIRECTION INPUT ;
    USE SIGNAL ;
    PORT
      LAYER M4 ;
        RECT  0 80.448 0.192 80.472 ;
    END
  END di0[471]
  PIN di0[472]
    DIRECTION INPUT ;
    USE SIGNAL ;
    PORT
      LAYER M4 ;
        RECT  0 80.64 0.192 80.664 ;
    END
  END di0[472]
  PIN di0[473]
    DIRECTION INPUT ;
    USE SIGNAL ;
    PORT
      LAYER M4 ;
        RECT  0 80.784 0.192 80.808 ;
    END
  END di0[473]
  PIN di0[474]
    DIRECTION INPUT ;
    USE SIGNAL ;
    PORT
      LAYER M4 ;
        RECT  0 80.976 0.192 81 ;
    END
  END di0[474]
  PIN di0[475]
    DIRECTION INPUT ;
    USE SIGNAL ;
    PORT
      LAYER M4 ;
        RECT  0 81.12 0.192 81.144 ;
    END
  END di0[475]
  PIN di0[476]
    DIRECTION INPUT ;
    USE SIGNAL ;
    PORT
      LAYER M4 ;
        RECT  0 81.264 0.192 81.288 ;
    END
  END di0[476]
  PIN di0[477]
    DIRECTION INPUT ;
    USE SIGNAL ;
    PORT
      LAYER M4 ;
        RECT  0 81.456 0.192 81.48 ;
    END
  END di0[477]
  PIN di0[478]
    DIRECTION INPUT ;
    USE SIGNAL ;
    PORT
      LAYER M4 ;
        RECT  0 81.6 0.192 81.624 ;
    END
  END di0[478]
  PIN di0[479]
    DIRECTION INPUT ;
    USE SIGNAL ;
    PORT
      LAYER M4 ;
        RECT  0 81.744 0.192 81.768 ;
    END
  END di0[479]
  PIN di0[47]
    DIRECTION INPUT ;
    USE SIGNAL ;
    PORT
      LAYER M4 ;
        RECT  0 12 0.192 12.024 ;
    END
  END di0[47]
  PIN di0[480]
    DIRECTION INPUT ;
    USE SIGNAL ;
    PORT
      LAYER M4 ;
        RECT  0 81.936 0.192 81.96 ;
    END
  END di0[480]
  PIN di0[481]
    DIRECTION INPUT ;
    USE SIGNAL ;
    PORT
      LAYER M4 ;
        RECT  0 82.08 0.192 82.104 ;
    END
  END di0[481]
  PIN di0[482]
    DIRECTION INPUT ;
    USE SIGNAL ;
    PORT
      LAYER M4 ;
        RECT  0 82.224 0.192 82.248 ;
    END
  END di0[482]
  PIN di0[483]
    DIRECTION INPUT ;
    USE SIGNAL ;
    PORT
      LAYER M4 ;
        RECT  0 82.416 0.192 82.44 ;
    END
  END di0[483]
  PIN di0[484]
    DIRECTION INPUT ;
    USE SIGNAL ;
    PORT
      LAYER M4 ;
        RECT  0 82.56 0.192 82.584 ;
    END
  END di0[484]
  PIN di0[485]
    DIRECTION INPUT ;
    USE SIGNAL ;
    PORT
      LAYER M4 ;
        RECT  0 82.752 0.192 82.776 ;
    END
  END di0[485]
  PIN di0[486]
    DIRECTION INPUT ;
    USE SIGNAL ;
    PORT
      LAYER M4 ;
        RECT  0 82.896 0.192 82.92 ;
    END
  END di0[486]
  PIN di0[487]
    DIRECTION INPUT ;
    USE SIGNAL ;
    PORT
      LAYER M4 ;
        RECT  0 83.04 0.192 83.064 ;
    END
  END di0[487]
  PIN di0[488]
    DIRECTION INPUT ;
    USE SIGNAL ;
    PORT
      LAYER M4 ;
        RECT  0 83.232 0.192 83.256 ;
    END
  END di0[488]
  PIN di0[489]
    DIRECTION INPUT ;
    USE SIGNAL ;
    PORT
      LAYER M4 ;
        RECT  0 83.376 0.192 83.4 ;
    END
  END di0[489]
  PIN di0[48]
    DIRECTION INPUT ;
    USE SIGNAL ;
    PORT
      LAYER M4 ;
        RECT  0 12.144 0.192 12.168 ;
    END
  END di0[48]
  PIN di0[490]
    DIRECTION INPUT ;
    USE SIGNAL ;
    PORT
      LAYER M4 ;
        RECT  0 83.52 0.192 83.544 ;
    END
  END di0[490]
  PIN di0[491]
    DIRECTION INPUT ;
    USE SIGNAL ;
    PORT
      LAYER M4 ;
        RECT  0 83.712 0.192 83.736 ;
    END
  END di0[491]
  PIN di0[492]
    DIRECTION INPUT ;
    USE SIGNAL ;
    PORT
      LAYER M4 ;
        RECT  0 83.856 0.192 83.88 ;
    END
  END di0[492]
  PIN di0[493]
    DIRECTION INPUT ;
    USE SIGNAL ;
    PORT
      LAYER M4 ;
        RECT  0 84 0.192 84.024 ;
    END
  END di0[493]
  PIN di0[494]
    DIRECTION INPUT ;
    USE SIGNAL ;
    PORT
      LAYER M4 ;
        RECT  0 84.192 0.192 84.216 ;
    END
  END di0[494]
  PIN di0[495]
    DIRECTION INPUT ;
    USE SIGNAL ;
    PORT
      LAYER M4 ;
        RECT  0 84.336 0.192 84.36 ;
    END
  END di0[495]
  PIN di0[496]
    DIRECTION INPUT ;
    USE SIGNAL ;
    PORT
      LAYER M4 ;
        RECT  0 84.528 0.192 84.552 ;
    END
  END di0[496]
  PIN di0[497]
    DIRECTION INPUT ;
    USE SIGNAL ;
    PORT
      LAYER M4 ;
        RECT  0 84.672 0.192 84.696 ;
    END
  END di0[497]
  PIN di0[498]
    DIRECTION INPUT ;
    USE SIGNAL ;
    PORT
      LAYER M4 ;
        RECT  0 84.816 0.192 84.84 ;
    END
  END di0[498]
  PIN di0[499]
    DIRECTION INPUT ;
    USE SIGNAL ;
    PORT
      LAYER M4 ;
        RECT  0 85.008 0.192 85.032 ;
    END
  END di0[499]
  PIN di0[49]
    DIRECTION INPUT ;
    USE SIGNAL ;
    PORT
      LAYER M4 ;
        RECT  0 12.336 0.192 12.36 ;
    END
  END di0[49]
  PIN di0[4]
    DIRECTION INPUT ;
    USE SIGNAL ;
    PORT
      LAYER M4 ;
        RECT  0 5.04 0.192 5.064 ;
    END
  END di0[4]
  PIN di0[500]
    DIRECTION INPUT ;
    USE SIGNAL ;
    PORT
      LAYER M4 ;
        RECT  0 85.152 0.192 85.176 ;
    END
  END di0[500]
  PIN di0[501]
    DIRECTION INPUT ;
    USE SIGNAL ;
    PORT
      LAYER M4 ;
        RECT  0 85.296 0.192 85.32 ;
    END
  END di0[501]
  PIN di0[502]
    DIRECTION INPUT ;
    USE SIGNAL ;
    PORT
      LAYER M4 ;
        RECT  0 85.488 0.192 85.512 ;
    END
  END di0[502]
  PIN di0[503]
    DIRECTION INPUT ;
    USE SIGNAL ;
    PORT
      LAYER M4 ;
        RECT  0 85.632 0.192 85.656 ;
    END
  END di0[503]
  PIN di0[504]
    DIRECTION INPUT ;
    USE SIGNAL ;
    PORT
      LAYER M4 ;
        RECT  0 85.776 0.192 85.8 ;
    END
  END di0[504]
  PIN di0[505]
    DIRECTION INPUT ;
    USE SIGNAL ;
    PORT
      LAYER M4 ;
        RECT  0 85.968 0.192 85.992 ;
    END
  END di0[505]
  PIN di0[506]
    DIRECTION INPUT ;
    USE SIGNAL ;
    PORT
      LAYER M4 ;
        RECT  0 86.112 0.192 86.136 ;
    END
  END di0[506]
  PIN di0[507]
    DIRECTION INPUT ;
    USE SIGNAL ;
    PORT
      LAYER M4 ;
        RECT  0 86.304 0.192 86.328 ;
    END
  END di0[507]
  PIN di0[508]
    DIRECTION INPUT ;
    USE SIGNAL ;
    PORT
      LAYER M4 ;
        RECT  0 86.448 0.192 86.472 ;
    END
  END di0[508]
  PIN di0[509]
    DIRECTION INPUT ;
    USE SIGNAL ;
    PORT
      LAYER M4 ;
        RECT  0 86.592 0.192 86.616 ;
    END
  END di0[509]
  PIN di0[50]
    DIRECTION INPUT ;
    USE SIGNAL ;
    PORT
      LAYER M4 ;
        RECT  0 12.48 0.192 12.504 ;
    END
  END di0[50]
  PIN di0[510]
    DIRECTION INPUT ;
    USE SIGNAL ;
    PORT
      LAYER M4 ;
        RECT  0 86.784 0.192 86.808 ;
    END
  END di0[510]
  PIN di0[511]
    DIRECTION INPUT ;
    USE SIGNAL ;
    PORT
      LAYER M4 ;
        RECT  0 86.928 0.192 86.952 ;
    END
  END di0[511]
  PIN di0[512]
    DIRECTION INPUT ;
    USE SIGNAL ;
    PORT
      LAYER M4 ;
        RECT  0 87.072 0.192 87.096 ;
    END
  END di0[512]
  PIN di0[513]
    DIRECTION INPUT ;
    USE SIGNAL ;
    PORT
      LAYER M4 ;
        RECT  0 87.264 0.192 87.288 ;
    END
  END di0[513]
  PIN di0[51]
    DIRECTION INPUT ;
    USE SIGNAL ;
    PORT
      LAYER M4 ;
        RECT  0 12.624 0.192 12.648 ;
    END
  END di0[51]
  PIN di0[52]
    DIRECTION INPUT ;
    USE SIGNAL ;
    PORT
      LAYER M4 ;
        RECT  0 12.816 0.192 12.84 ;
    END
  END di0[52]
  PIN di0[53]
    DIRECTION INPUT ;
    USE SIGNAL ;
    PORT
      LAYER M4 ;
        RECT  0 12.96 0.192 12.984 ;
    END
  END di0[53]
  PIN di0[54]
    DIRECTION INPUT ;
    USE SIGNAL ;
    PORT
      LAYER M4 ;
        RECT  0 13.152 0.192 13.176 ;
    END
  END di0[54]
  PIN di0[55]
    DIRECTION INPUT ;
    USE SIGNAL ;
    PORT
      LAYER M4 ;
        RECT  0 13.296 0.192 13.32 ;
    END
  END di0[55]
  PIN di0[56]
    DIRECTION INPUT ;
    USE SIGNAL ;
    PORT
      LAYER M4 ;
        RECT  0 13.44 0.192 13.464 ;
    END
  END di0[56]
  PIN di0[57]
    DIRECTION INPUT ;
    USE SIGNAL ;
    PORT
      LAYER M4 ;
        RECT  0 13.632 0.192 13.656 ;
    END
  END di0[57]
  PIN di0[58]
    DIRECTION INPUT ;
    USE SIGNAL ;
    PORT
      LAYER M4 ;
        RECT  0 13.776 0.192 13.8 ;
    END
  END di0[58]
  PIN di0[59]
    DIRECTION INPUT ;
    USE SIGNAL ;
    PORT
      LAYER M4 ;
        RECT  0 13.92 0.192 13.944 ;
    END
  END di0[59]
  PIN di0[5]
    DIRECTION INPUT ;
    USE SIGNAL ;
    PORT
      LAYER M4 ;
        RECT  0 5.232 0.192 5.256 ;
    END
  END di0[5]
  PIN di0[60]
    DIRECTION INPUT ;
    USE SIGNAL ;
    PORT
      LAYER M4 ;
        RECT  0 14.112 0.192 14.136 ;
    END
  END di0[60]
  PIN di0[61]
    DIRECTION INPUT ;
    USE SIGNAL ;
    PORT
      LAYER M4 ;
        RECT  0 14.256 0.192 14.28 ;
    END
  END di0[61]
  PIN di0[62]
    DIRECTION INPUT ;
    USE SIGNAL ;
    PORT
      LAYER M4 ;
        RECT  0 14.448 0.192 14.472 ;
    END
  END di0[62]
  PIN di0[63]
    DIRECTION INPUT ;
    USE SIGNAL ;
    PORT
      LAYER M4 ;
        RECT  0 14.592 0.192 14.616 ;
    END
  END di0[63]
  PIN di0[64]
    DIRECTION INPUT ;
    USE SIGNAL ;
    PORT
      LAYER M4 ;
        RECT  0 14.736 0.192 14.76 ;
    END
  END di0[64]
  PIN di0[65]
    DIRECTION INPUT ;
    USE SIGNAL ;
    PORT
      LAYER M4 ;
        RECT  0 14.928 0.192 14.952 ;
    END
  END di0[65]
  PIN di0[66]
    DIRECTION INPUT ;
    USE SIGNAL ;
    PORT
      LAYER M4 ;
        RECT  0 15.072 0.192 15.096 ;
    END
  END di0[66]
  PIN di0[67]
    DIRECTION INPUT ;
    USE SIGNAL ;
    PORT
      LAYER M4 ;
        RECT  0 15.216 0.192 15.24 ;
    END
  END di0[67]
  PIN di0[68]
    DIRECTION INPUT ;
    USE SIGNAL ;
    PORT
      LAYER M4 ;
        RECT  0 15.408 0.192 15.432 ;
    END
  END di0[68]
  PIN di0[69]
    DIRECTION INPUT ;
    USE SIGNAL ;
    PORT
      LAYER M4 ;
        RECT  0 15.552 0.192 15.576 ;
    END
  END di0[69]
  PIN di0[6]
    DIRECTION INPUT ;
    USE SIGNAL ;
    PORT
      LAYER M4 ;
        RECT  0 5.376 0.192 5.4 ;
    END
  END di0[6]
  PIN di0[70]
    DIRECTION INPUT ;
    USE SIGNAL ;
    PORT
      LAYER M4 ;
        RECT  0 15.696 0.192 15.72 ;
    END
  END di0[70]
  PIN di0[71]
    DIRECTION INPUT ;
    USE SIGNAL ;
    PORT
      LAYER M4 ;
        RECT  0 15.888 0.192 15.912 ;
    END
  END di0[71]
  PIN di0[72]
    DIRECTION INPUT ;
    USE SIGNAL ;
    PORT
      LAYER M4 ;
        RECT  0 16.032 0.192 16.056 ;
    END
  END di0[72]
  PIN di0[73]
    DIRECTION INPUT ;
    USE SIGNAL ;
    PORT
      LAYER M4 ;
        RECT  0 16.224 0.192 16.248 ;
    END
  END di0[73]
  PIN di0[74]
    DIRECTION INPUT ;
    USE SIGNAL ;
    PORT
      LAYER M4 ;
        RECT  0 16.368 0.192 16.392 ;
    END
  END di0[74]
  PIN di0[75]
    DIRECTION INPUT ;
    USE SIGNAL ;
    PORT
      LAYER M4 ;
        RECT  0 16.512 0.192 16.536 ;
    END
  END di0[75]
  PIN di0[76]
    DIRECTION INPUT ;
    USE SIGNAL ;
    PORT
      LAYER M4 ;
        RECT  0 16.704 0.192 16.728 ;
    END
  END di0[76]
  PIN di0[77]
    DIRECTION INPUT ;
    USE SIGNAL ;
    PORT
      LAYER M4 ;
        RECT  0 16.848 0.192 16.872 ;
    END
  END di0[77]
  PIN di0[78]
    DIRECTION INPUT ;
    USE SIGNAL ;
    PORT
      LAYER M4 ;
        RECT  0 16.992 0.192 17.016 ;
    END
  END di0[78]
  PIN di0[79]
    DIRECTION INPUT ;
    USE SIGNAL ;
    PORT
      LAYER M4 ;
        RECT  0 17.184 0.192 17.208 ;
    END
  END di0[79]
  PIN di0[7]
    DIRECTION INPUT ;
    USE SIGNAL ;
    PORT
      LAYER M4 ;
        RECT  0 5.52 0.192 5.544 ;
    END
  END di0[7]
  PIN di0[80]
    DIRECTION INPUT ;
    USE SIGNAL ;
    PORT
      LAYER M4 ;
        RECT  0 17.328 0.192 17.352 ;
    END
  END di0[80]
  PIN di0[81]
    DIRECTION INPUT ;
    USE SIGNAL ;
    PORT
      LAYER M4 ;
        RECT  0 17.472 0.192 17.496 ;
    END
  END di0[81]
  PIN di0[82]
    DIRECTION INPUT ;
    USE SIGNAL ;
    PORT
      LAYER M4 ;
        RECT  0 17.664 0.192 17.688 ;
    END
  END di0[82]
  PIN di0[83]
    DIRECTION INPUT ;
    USE SIGNAL ;
    PORT
      LAYER M4 ;
        RECT  0 17.808 0.192 17.832 ;
    END
  END di0[83]
  PIN di0[84]
    DIRECTION INPUT ;
    USE SIGNAL ;
    PORT
      LAYER M4 ;
        RECT  0 18 0.192 18.024 ;
    END
  END di0[84]
  PIN di0[85]
    DIRECTION INPUT ;
    USE SIGNAL ;
    PORT
      LAYER M4 ;
        RECT  0 18.144 0.192 18.168 ;
    END
  END di0[85]
  PIN di0[86]
    DIRECTION INPUT ;
    USE SIGNAL ;
    PORT
      LAYER M4 ;
        RECT  0 18.288 0.192 18.312 ;
    END
  END di0[86]
  PIN di0[87]
    DIRECTION INPUT ;
    USE SIGNAL ;
    PORT
      LAYER M4 ;
        RECT  0 18.48 0.192 18.504 ;
    END
  END di0[87]
  PIN di0[88]
    DIRECTION INPUT ;
    USE SIGNAL ;
    PORT
      LAYER M4 ;
        RECT  0 18.624 0.192 18.648 ;
    END
  END di0[88]
  PIN di0[89]
    DIRECTION INPUT ;
    USE SIGNAL ;
    PORT
      LAYER M4 ;
        RECT  0 18.768 0.192 18.792 ;
    END
  END di0[89]
  PIN di0[8]
    DIRECTION INPUT ;
    USE SIGNAL ;
    PORT
      LAYER M4 ;
        RECT  0 5.712 0.192 5.736 ;
    END
  END di0[8]
  PIN di0[90]
    DIRECTION INPUT ;
    USE SIGNAL ;
    PORT
      LAYER M4 ;
        RECT  0 18.96 0.192 18.984 ;
    END
  END di0[90]
  PIN di0[91]
    DIRECTION INPUT ;
    USE SIGNAL ;
    PORT
      LAYER M4 ;
        RECT  0 19.104 0.192 19.128 ;
    END
  END di0[91]
  PIN di0[92]
    DIRECTION INPUT ;
    USE SIGNAL ;
    PORT
      LAYER M4 ;
        RECT  0 19.248 0.192 19.272 ;
    END
  END di0[92]
  PIN di0[93]
    DIRECTION INPUT ;
    USE SIGNAL ;
    PORT
      LAYER M4 ;
        RECT  0 19.44 0.192 19.464 ;
    END
  END di0[93]
  PIN di0[94]
    DIRECTION INPUT ;
    USE SIGNAL ;
    PORT
      LAYER M4 ;
        RECT  0 19.584 0.192 19.608 ;
    END
  END di0[94]
  PIN di0[95]
    DIRECTION INPUT ;
    USE SIGNAL ;
    PORT
      LAYER M4 ;
        RECT  0 19.776 0.192 19.8 ;
    END
  END di0[95]
  PIN di0[96]
    DIRECTION INPUT ;
    USE SIGNAL ;
    PORT
      LAYER M4 ;
        RECT  0 19.92 0.192 19.944 ;
    END
  END di0[96]
  PIN di0[97]
    DIRECTION INPUT ;
    USE SIGNAL ;
    PORT
      LAYER M4 ;
        RECT  0 20.064 0.192 20.088 ;
    END
  END di0[97]
  PIN di0[98]
    DIRECTION INPUT ;
    USE SIGNAL ;
    PORT
      LAYER M4 ;
        RECT  0 20.256 0.192 20.28 ;
    END
  END di0[98]
  PIN di0[99]
    DIRECTION INPUT ;
    USE SIGNAL ;
    PORT
      LAYER M4 ;
        RECT  0 20.4 0.192 20.424 ;
    END
  END di0[99]
  PIN di0[9]
    DIRECTION INPUT ;
    USE SIGNAL ;
    PORT
      LAYER M4 ;
        RECT  0 5.856 0.192 5.88 ;
    END
  END di0[9]
  PIN fi0[0]
    DIRECTION INPUT ;
    USE SIGNAL ;
    PORT
      LAYER M4 ;
        RECT  0 87.408 0.192 87.432 ;
    END
  END fi0[0]
  PIN o[0]
    DIRECTION OUTPUT ;
    USE SIGNAL ;
    PORT
      LAYER M4 ;
        RECT  0 87.552 0.192 87.576 ;
    END
  END o[0]
  PIN o[100]
    DIRECTION OUTPUT ;
    USE SIGNAL ;
    PORT
      LAYER M4 ;
        RECT  0 103.728 0.192 103.752 ;
    END
  END o[100]
  PIN o[101]
    DIRECTION OUTPUT ;
    USE SIGNAL ;
    PORT
      LAYER M4 ;
        RECT  0 103.872 0.192 103.896 ;
    END
  END o[101]
  PIN o[102]
    DIRECTION OUTPUT ;
    USE SIGNAL ;
    PORT
      LAYER M4 ;
        RECT  0 104.064 0.192 104.088 ;
    END
  END o[102]
  PIN o[103]
    DIRECTION OUTPUT ;
    USE SIGNAL ;
    PORT
      LAYER M4 ;
        RECT  0 104.208 0.192 104.232 ;
    END
  END o[103]
  PIN o[104]
    DIRECTION OUTPUT ;
    USE SIGNAL ;
    PORT
      LAYER M4 ;
        RECT  0 104.352 0.192 104.376 ;
    END
  END o[104]
  PIN o[105]
    DIRECTION OUTPUT ;
    USE SIGNAL ;
    PORT
      LAYER M4 ;
        RECT  0 104.544 0.192 104.568 ;
    END
  END o[105]
  PIN o[106]
    DIRECTION OUTPUT ;
    USE SIGNAL ;
    PORT
      LAYER M4 ;
        RECT  0 104.688 0.192 104.712 ;
    END
  END o[106]
  PIN o[107]
    DIRECTION OUTPUT ;
    USE SIGNAL ;
    PORT
      LAYER M4 ;
        RECT  0 104.832 0.192 104.856 ;
    END
  END o[107]
  PIN o[108]
    DIRECTION OUTPUT ;
    USE SIGNAL ;
    PORT
      LAYER M4 ;
        RECT  0 105.024 0.192 105.048 ;
    END
  END o[108]
  PIN o[109]
    DIRECTION OUTPUT ;
    USE SIGNAL ;
    PORT
      LAYER M4 ;
        RECT  0 105.168 0.192 105.192 ;
    END
  END o[109]
  PIN o[10]
    DIRECTION OUTPUT ;
    USE SIGNAL ;
    PORT
      LAYER M4 ;
        RECT  0 89.184 0.192 89.208 ;
    END
  END o[10]
  PIN o[110]
    DIRECTION OUTPUT ;
    USE SIGNAL ;
    PORT
      LAYER M4 ;
        RECT  0 105.312 0.192 105.336 ;
    END
  END o[110]
  PIN o[111]
    DIRECTION OUTPUT ;
    USE SIGNAL ;
    PORT
      LAYER M4 ;
        RECT  0 105.504 0.192 105.528 ;
    END
  END o[111]
  PIN o[112]
    DIRECTION OUTPUT ;
    USE SIGNAL ;
    PORT
      LAYER M4 ;
        RECT  0 105.648 0.192 105.672 ;
    END
  END o[112]
  PIN o[113]
    DIRECTION OUTPUT ;
    USE SIGNAL ;
    PORT
      LAYER M4 ;
        RECT  0 105.84 0.192 105.864 ;
    END
  END o[113]
  PIN o[114]
    DIRECTION OUTPUT ;
    USE SIGNAL ;
    PORT
      LAYER M4 ;
        RECT  0 105.984 0.192 106.008 ;
    END
  END o[114]
  PIN o[115]
    DIRECTION OUTPUT ;
    USE SIGNAL ;
    PORT
      LAYER M4 ;
        RECT  0 106.128 0.192 106.152 ;
    END
  END o[115]
  PIN o[116]
    DIRECTION OUTPUT ;
    USE SIGNAL ;
    PORT
      LAYER M4 ;
        RECT  0 106.32 0.192 106.344 ;
    END
  END o[116]
  PIN o[117]
    DIRECTION OUTPUT ;
    USE SIGNAL ;
    PORT
      LAYER M4 ;
        RECT  0 106.464 0.192 106.488 ;
    END
  END o[117]
  PIN o[118]
    DIRECTION OUTPUT ;
    USE SIGNAL ;
    PORT
      LAYER M4 ;
        RECT  0 106.608 0.192 106.632 ;
    END
  END o[118]
  PIN o[119]
    DIRECTION OUTPUT ;
    USE SIGNAL ;
    PORT
      LAYER M4 ;
        RECT  0 106.8 0.192 106.824 ;
    END
  END o[119]
  PIN o[11]
    DIRECTION OUTPUT ;
    USE SIGNAL ;
    PORT
      LAYER M4 ;
        RECT  0 89.328 0.192 89.352 ;
    END
  END o[11]
  PIN o[120]
    DIRECTION OUTPUT ;
    USE SIGNAL ;
    PORT
      LAYER M4 ;
        RECT  0 106.944 0.192 106.968 ;
    END
  END o[120]
  PIN o[121]
    DIRECTION OUTPUT ;
    USE SIGNAL ;
    PORT
      LAYER M4 ;
        RECT  0 107.088 0.192 107.112 ;
    END
  END o[121]
  PIN o[122]
    DIRECTION OUTPUT ;
    USE SIGNAL ;
    PORT
      LAYER M4 ;
        RECT  0 107.28 0.192 107.304 ;
    END
  END o[122]
  PIN o[123]
    DIRECTION OUTPUT ;
    USE SIGNAL ;
    PORT
      LAYER M4 ;
        RECT  0 107.424 0.192 107.448 ;
    END
  END o[123]
  PIN o[124]
    DIRECTION OUTPUT ;
    USE SIGNAL ;
    PORT
      LAYER M4 ;
        RECT  0 107.616 0.192 107.64 ;
    END
  END o[124]
  PIN o[125]
    DIRECTION OUTPUT ;
    USE SIGNAL ;
    PORT
      LAYER M4 ;
        RECT  0 107.76 0.192 107.784 ;
    END
  END o[125]
  PIN o[126]
    DIRECTION OUTPUT ;
    USE SIGNAL ;
    PORT
      LAYER M4 ;
        RECT  0 107.904 0.192 107.928 ;
    END
  END o[126]
  PIN o[127]
    DIRECTION OUTPUT ;
    USE SIGNAL ;
    PORT
      LAYER M4 ;
        RECT  0 108.096 0.192 108.12 ;
    END
  END o[127]
  PIN o[128]
    DIRECTION OUTPUT ;
    USE SIGNAL ;
    PORT
      LAYER M4 ;
        RECT  0 108.24 0.192 108.264 ;
    END
  END o[128]
  PIN o[129]
    DIRECTION OUTPUT ;
    USE SIGNAL ;
    PORT
      LAYER M4 ;
        RECT  0 108.384 0.192 108.408 ;
    END
  END o[129]
  PIN o[12]
    DIRECTION OUTPUT ;
    USE SIGNAL ;
    PORT
      LAYER M4 ;
        RECT  0 89.52 0.192 89.544 ;
    END
  END o[12]
  PIN o[130]
    DIRECTION OUTPUT ;
    USE SIGNAL ;
    PORT
      LAYER M4 ;
        RECT  0 108.576 0.192 108.6 ;
    END
  END o[130]
  PIN o[131]
    DIRECTION OUTPUT ;
    USE SIGNAL ;
    PORT
      LAYER M4 ;
        RECT  0 108.72 0.192 108.744 ;
    END
  END o[131]
  PIN o[132]
    DIRECTION OUTPUT ;
    USE SIGNAL ;
    PORT
      LAYER M4 ;
        RECT  0 108.864 0.192 108.888 ;
    END
  END o[132]
  PIN o[133]
    DIRECTION OUTPUT ;
    USE SIGNAL ;
    PORT
      LAYER M4 ;
        RECT  0 109.056 0.192 109.08 ;
    END
  END o[133]
  PIN o[134]
    DIRECTION OUTPUT ;
    USE SIGNAL ;
    PORT
      LAYER M4 ;
        RECT  0 109.2 0.192 109.224 ;
    END
  END o[134]
  PIN o[135]
    DIRECTION OUTPUT ;
    USE SIGNAL ;
    PORT
      LAYER M4 ;
        RECT  0 109.392 0.192 109.416 ;
    END
  END o[135]
  PIN o[136]
    DIRECTION OUTPUT ;
    USE SIGNAL ;
    PORT
      LAYER M4 ;
        RECT  0 109.536 0.192 109.56 ;
    END
  END o[136]
  PIN o[137]
    DIRECTION OUTPUT ;
    USE SIGNAL ;
    PORT
      LAYER M4 ;
        RECT  0 109.68 0.192 109.704 ;
    END
  END o[137]
  PIN o[138]
    DIRECTION OUTPUT ;
    USE SIGNAL ;
    PORT
      LAYER M4 ;
        RECT  0 109.872 0.192 109.896 ;
    END
  END o[138]
  PIN o[139]
    DIRECTION OUTPUT ;
    USE SIGNAL ;
    PORT
      LAYER M4 ;
        RECT  0 110.016 0.192 110.04 ;
    END
  END o[139]
  PIN o[13]
    DIRECTION OUTPUT ;
    USE SIGNAL ;
    PORT
      LAYER M4 ;
        RECT  0 89.664 0.192 89.688 ;
    END
  END o[13]
  PIN o[140]
    DIRECTION OUTPUT ;
    USE SIGNAL ;
    PORT
      LAYER M4 ;
        RECT  0 110.16 0.192 110.184 ;
    END
  END o[140]
  PIN o[141]
    DIRECTION OUTPUT ;
    USE SIGNAL ;
    PORT
      LAYER M4 ;
        RECT  0 110.352 0.192 110.376 ;
    END
  END o[141]
  PIN o[142]
    DIRECTION OUTPUT ;
    USE SIGNAL ;
    PORT
      LAYER M4 ;
        RECT  0 110.496 0.192 110.52 ;
    END
  END o[142]
  PIN o[143]
    DIRECTION OUTPUT ;
    USE SIGNAL ;
    PORT
      LAYER M4 ;
        RECT  0 110.64 0.192 110.664 ;
    END
  END o[143]
  PIN o[144]
    DIRECTION OUTPUT ;
    USE SIGNAL ;
    PORT
      LAYER M4 ;
        RECT  0 110.832 0.192 110.856 ;
    END
  END o[144]
  PIN o[145]
    DIRECTION OUTPUT ;
    USE SIGNAL ;
    PORT
      LAYER M4 ;
        RECT  0 110.976 0.192 111 ;
    END
  END o[145]
  PIN o[146]
    DIRECTION OUTPUT ;
    USE SIGNAL ;
    PORT
      LAYER M4 ;
        RECT  0 111.168 0.192 111.192 ;
    END
  END o[146]
  PIN o[147]
    DIRECTION OUTPUT ;
    USE SIGNAL ;
    PORT
      LAYER M4 ;
        RECT  0 111.312 0.192 111.336 ;
    END
  END o[147]
  PIN o[148]
    DIRECTION OUTPUT ;
    USE SIGNAL ;
    PORT
      LAYER M4 ;
        RECT  0 111.456 0.192 111.48 ;
    END
  END o[148]
  PIN o[149]
    DIRECTION OUTPUT ;
    USE SIGNAL ;
    PORT
      LAYER M4 ;
        RECT  0 111.648 0.192 111.672 ;
    END
  END o[149]
  PIN o[14]
    DIRECTION OUTPUT ;
    USE SIGNAL ;
    PORT
      LAYER M4 ;
        RECT  0 89.856 0.192 89.88 ;
    END
  END o[14]
  PIN o[150]
    DIRECTION OUTPUT ;
    USE SIGNAL ;
    PORT
      LAYER M4 ;
        RECT  0 111.792 0.192 111.816 ;
    END
  END o[150]
  PIN o[151]
    DIRECTION OUTPUT ;
    USE SIGNAL ;
    PORT
      LAYER M4 ;
        RECT  0 111.936 0.192 111.96 ;
    END
  END o[151]
  PIN o[152]
    DIRECTION OUTPUT ;
    USE SIGNAL ;
    PORT
      LAYER M4 ;
        RECT  0 112.128 0.192 112.152 ;
    END
  END o[152]
  PIN o[153]
    DIRECTION OUTPUT ;
    USE SIGNAL ;
    PORT
      LAYER M4 ;
        RECT  0 112.272 0.192 112.296 ;
    END
  END o[153]
  PIN o[154]
    DIRECTION OUTPUT ;
    USE SIGNAL ;
    PORT
      LAYER M4 ;
        RECT  0 112.464 0.192 112.488 ;
    END
  END o[154]
  PIN o[155]
    DIRECTION OUTPUT ;
    USE SIGNAL ;
    PORT
      LAYER M4 ;
        RECT  0 112.608 0.192 112.632 ;
    END
  END o[155]
  PIN o[156]
    DIRECTION OUTPUT ;
    USE SIGNAL ;
    PORT
      LAYER M4 ;
        RECT  0 112.752 0.192 112.776 ;
    END
  END o[156]
  PIN o[157]
    DIRECTION OUTPUT ;
    USE SIGNAL ;
    PORT
      LAYER M4 ;
        RECT  0 112.944 0.192 112.968 ;
    END
  END o[157]
  PIN o[158]
    DIRECTION OUTPUT ;
    USE SIGNAL ;
    PORT
      LAYER M4 ;
        RECT  0 113.088 0.192 113.112 ;
    END
  END o[158]
  PIN o[159]
    DIRECTION OUTPUT ;
    USE SIGNAL ;
    PORT
      LAYER M4 ;
        RECT  0 113.232 0.192 113.256 ;
    END
  END o[159]
  PIN o[15]
    DIRECTION OUTPUT ;
    USE SIGNAL ;
    PORT
      LAYER M4 ;
        RECT  0 90 0.192 90.024 ;
    END
  END o[15]
  PIN o[160]
    DIRECTION OUTPUT ;
    USE SIGNAL ;
    PORT
      LAYER M4 ;
        RECT  0 113.424 0.192 113.448 ;
    END
  END o[160]
  PIN o[161]
    DIRECTION OUTPUT ;
    USE SIGNAL ;
    PORT
      LAYER M4 ;
        RECT  0 113.568 0.192 113.592 ;
    END
  END o[161]
  PIN o[162]
    DIRECTION OUTPUT ;
    USE SIGNAL ;
    PORT
      LAYER M4 ;
        RECT  0 113.712 0.192 113.736 ;
    END
  END o[162]
  PIN o[163]
    DIRECTION OUTPUT ;
    USE SIGNAL ;
    PORT
      LAYER M4 ;
        RECT  0 113.904 0.192 113.928 ;
    END
  END o[163]
  PIN o[164]
    DIRECTION OUTPUT ;
    USE SIGNAL ;
    PORT
      LAYER M4 ;
        RECT  0 114.048 0.192 114.072 ;
    END
  END o[164]
  PIN o[165]
    DIRECTION OUTPUT ;
    USE SIGNAL ;
    PORT
      LAYER M4 ;
        RECT  0 114.24 0.192 114.264 ;
    END
  END o[165]
  PIN o[166]
    DIRECTION OUTPUT ;
    USE SIGNAL ;
    PORT
      LAYER M4 ;
        RECT  0 114.384 0.192 114.408 ;
    END
  END o[166]
  PIN o[167]
    DIRECTION OUTPUT ;
    USE SIGNAL ;
    PORT
      LAYER M4 ;
        RECT  0 114.528 0.192 114.552 ;
    END
  END o[167]
  PIN o[168]
    DIRECTION OUTPUT ;
    USE SIGNAL ;
    PORT
      LAYER M4 ;
        RECT  0 114.72 0.192 114.744 ;
    END
  END o[168]
  PIN o[169]
    DIRECTION OUTPUT ;
    USE SIGNAL ;
    PORT
      LAYER M4 ;
        RECT  0 114.864 0.192 114.888 ;
    END
  END o[169]
  PIN o[16]
    DIRECTION OUTPUT ;
    USE SIGNAL ;
    PORT
      LAYER M4 ;
        RECT  0 90.144 0.192 90.168 ;
    END
  END o[16]
  PIN o[170]
    DIRECTION OUTPUT ;
    USE SIGNAL ;
    PORT
      LAYER M4 ;
        RECT  0 115.008 0.192 115.032 ;
    END
  END o[170]
  PIN o[171]
    DIRECTION OUTPUT ;
    USE SIGNAL ;
    PORT
      LAYER M4 ;
        RECT  0 115.2 0.192 115.224 ;
    END
  END o[171]
  PIN o[172]
    DIRECTION OUTPUT ;
    USE SIGNAL ;
    PORT
      LAYER M4 ;
        RECT  0 115.344 0.192 115.368 ;
    END
  END o[172]
  PIN o[173]
    DIRECTION OUTPUT ;
    USE SIGNAL ;
    PORT
      LAYER M4 ;
        RECT  0 115.488 0.192 115.512 ;
    END
  END o[173]
  PIN o[174]
    DIRECTION OUTPUT ;
    USE SIGNAL ;
    PORT
      LAYER M4 ;
        RECT  0 115.68 0.192 115.704 ;
    END
  END o[174]
  PIN o[175]
    DIRECTION OUTPUT ;
    USE SIGNAL ;
    PORT
      LAYER M4 ;
        RECT  0 115.824 0.192 115.848 ;
    END
  END o[175]
  PIN o[176]
    DIRECTION OUTPUT ;
    USE SIGNAL ;
    PORT
      LAYER M4 ;
        RECT  0 116.016 0.192 116.04 ;
    END
  END o[176]
  PIN o[177]
    DIRECTION OUTPUT ;
    USE SIGNAL ;
    PORT
      LAYER M4 ;
        RECT  0 116.16 0.192 116.184 ;
    END
  END o[177]
  PIN o[178]
    DIRECTION OUTPUT ;
    USE SIGNAL ;
    PORT
      LAYER M4 ;
        RECT  0 116.304 0.192 116.328 ;
    END
  END o[178]
  PIN o[179]
    DIRECTION OUTPUT ;
    USE SIGNAL ;
    PORT
      LAYER M4 ;
        RECT  0 116.496 0.192 116.52 ;
    END
  END o[179]
  PIN o[17]
    DIRECTION OUTPUT ;
    USE SIGNAL ;
    PORT
      LAYER M4 ;
        RECT  0 90.336 0.192 90.36 ;
    END
  END o[17]
  PIN o[180]
    DIRECTION OUTPUT ;
    USE SIGNAL ;
    PORT
      LAYER M4 ;
        RECT  0 116.64 0.192 116.664 ;
    END
  END o[180]
  PIN o[181]
    DIRECTION OUTPUT ;
    USE SIGNAL ;
    PORT
      LAYER M4 ;
        RECT  0 116.784 0.192 116.808 ;
    END
  END o[181]
  PIN o[182]
    DIRECTION OUTPUT ;
    USE SIGNAL ;
    PORT
      LAYER M4 ;
        RECT  0 116.976 0.192 117 ;
    END
  END o[182]
  PIN o[183]
    DIRECTION OUTPUT ;
    USE SIGNAL ;
    PORT
      LAYER M4 ;
        RECT  0 117.12 0.192 117.144 ;
    END
  END o[183]
  PIN o[184]
    DIRECTION OUTPUT ;
    USE SIGNAL ;
    PORT
      LAYER M4 ;
        RECT  0 117.264 0.192 117.288 ;
    END
  END o[184]
  PIN o[185]
    DIRECTION OUTPUT ;
    USE SIGNAL ;
    PORT
      LAYER M4 ;
        RECT  0 117.456 0.192 117.48 ;
    END
  END o[185]
  PIN o[186]
    DIRECTION OUTPUT ;
    USE SIGNAL ;
    PORT
      LAYER M4 ;
        RECT  0 117.6 0.192 117.624 ;
    END
  END o[186]
  PIN o[187]
    DIRECTION OUTPUT ;
    USE SIGNAL ;
    PORT
      LAYER M4 ;
        RECT  0 117.792 0.192 117.816 ;
    END
  END o[187]
  PIN o[188]
    DIRECTION OUTPUT ;
    USE SIGNAL ;
    PORT
      LAYER M4 ;
        RECT  0 117.936 0.192 117.96 ;
    END
  END o[188]
  PIN o[189]
    DIRECTION OUTPUT ;
    USE SIGNAL ;
    PORT
      LAYER M4 ;
        RECT  0 118.08 0.192 118.104 ;
    END
  END o[189]
  PIN o[18]
    DIRECTION OUTPUT ;
    USE SIGNAL ;
    PORT
      LAYER M4 ;
        RECT  0 90.48 0.192 90.504 ;
    END
  END o[18]
  PIN o[190]
    DIRECTION OUTPUT ;
    USE SIGNAL ;
    PORT
      LAYER M4 ;
        RECT  0 118.272 0.192 118.296 ;
    END
  END o[190]
  PIN o[191]
    DIRECTION OUTPUT ;
    USE SIGNAL ;
    PORT
      LAYER M4 ;
        RECT  0 118.416 0.192 118.44 ;
    END
  END o[191]
  PIN o[192]
    DIRECTION OUTPUT ;
    USE SIGNAL ;
    PORT
      LAYER M4 ;
        RECT  0 118.56 0.192 118.584 ;
    END
  END o[192]
  PIN o[193]
    DIRECTION OUTPUT ;
    USE SIGNAL ;
    PORT
      LAYER M4 ;
        RECT  0 118.752 0.192 118.776 ;
    END
  END o[193]
  PIN o[194]
    DIRECTION OUTPUT ;
    USE SIGNAL ;
    PORT
      LAYER M4 ;
        RECT  0 118.896 0.192 118.92 ;
    END
  END o[194]
  PIN o[195]
    DIRECTION OUTPUT ;
    USE SIGNAL ;
    PORT
      LAYER M4 ;
        RECT  0 119.04 0.192 119.064 ;
    END
  END o[195]
  PIN o[196]
    DIRECTION OUTPUT ;
    USE SIGNAL ;
    PORT
      LAYER M4 ;
        RECT  0 119.232 0.192 119.256 ;
    END
  END o[196]
  PIN o[197]
    DIRECTION OUTPUT ;
    USE SIGNAL ;
    PORT
      LAYER M4 ;
        RECT  0 119.376 0.192 119.4 ;
    END
  END o[197]
  PIN o[198]
    DIRECTION OUTPUT ;
    USE SIGNAL ;
    PORT
      LAYER M4 ;
        RECT  0 119.568 0.192 119.592 ;
    END
  END o[198]
  PIN o[199]
    DIRECTION OUTPUT ;
    USE SIGNAL ;
    PORT
      LAYER M4 ;
        RECT  0 119.712 0.192 119.736 ;
    END
  END o[199]
  PIN o[19]
    DIRECTION OUTPUT ;
    USE SIGNAL ;
    PORT
      LAYER M4 ;
        RECT  0 90.624 0.192 90.648 ;
    END
  END o[19]
  PIN o[1]
    DIRECTION OUTPUT ;
    USE SIGNAL ;
    PORT
      LAYER M4 ;
        RECT  0 87.744 0.192 87.768 ;
    END
  END o[1]
  PIN o[200]
    DIRECTION OUTPUT ;
    USE SIGNAL ;
    PORT
      LAYER M4 ;
        RECT  0 119.856 0.192 119.88 ;
    END
  END o[200]
  PIN o[201]
    DIRECTION OUTPUT ;
    USE SIGNAL ;
    PORT
      LAYER M4 ;
        RECT  0 120.048 0.192 120.072 ;
    END
  END o[201]
  PIN o[202]
    DIRECTION OUTPUT ;
    USE SIGNAL ;
    PORT
      LAYER M4 ;
        RECT  0 120.192 0.192 120.216 ;
    END
  END o[202]
  PIN o[203]
    DIRECTION OUTPUT ;
    USE SIGNAL ;
    PORT
      LAYER M4 ;
        RECT  0 120.336 0.192 120.36 ;
    END
  END o[203]
  PIN o[204]
    DIRECTION OUTPUT ;
    USE SIGNAL ;
    PORT
      LAYER M4 ;
        RECT  0 120.528 0.192 120.552 ;
    END
  END o[204]
  PIN o[205]
    DIRECTION OUTPUT ;
    USE SIGNAL ;
    PORT
      LAYER M4 ;
        RECT  0 120.672 0.192 120.696 ;
    END
  END o[205]
  PIN o[206]
    DIRECTION OUTPUT ;
    USE SIGNAL ;
    PORT
      LAYER M4 ;
        RECT  0 120.816 0.192 120.84 ;
    END
  END o[206]
  PIN o[207]
    DIRECTION OUTPUT ;
    USE SIGNAL ;
    PORT
      LAYER M4 ;
        RECT  0 121.008 0.192 121.032 ;
    END
  END o[207]
  PIN o[208]
    DIRECTION OUTPUT ;
    USE SIGNAL ;
    PORT
      LAYER M4 ;
        RECT  0 121.152 0.192 121.176 ;
    END
  END o[208]
  PIN o[209]
    DIRECTION OUTPUT ;
    USE SIGNAL ;
    PORT
      LAYER M4 ;
        RECT  0 121.344 0.192 121.368 ;
    END
  END o[209]
  PIN o[20]
    DIRECTION OUTPUT ;
    USE SIGNAL ;
    PORT
      LAYER M4 ;
        RECT  0 90.816 0.192 90.84 ;
    END
  END o[20]
  PIN o[210]
    DIRECTION OUTPUT ;
    USE SIGNAL ;
    PORT
      LAYER M4 ;
        RECT  0 121.488 0.192 121.512 ;
    END
  END o[210]
  PIN o[211]
    DIRECTION OUTPUT ;
    USE SIGNAL ;
    PORT
      LAYER M4 ;
        RECT  0 121.632 0.192 121.656 ;
    END
  END o[211]
  PIN o[212]
    DIRECTION OUTPUT ;
    USE SIGNAL ;
    PORT
      LAYER M4 ;
        RECT  0 121.824 0.192 121.848 ;
    END
  END o[212]
  PIN o[213]
    DIRECTION OUTPUT ;
    USE SIGNAL ;
    PORT
      LAYER M4 ;
        RECT  0 121.968 0.192 121.992 ;
    END
  END o[213]
  PIN o[214]
    DIRECTION OUTPUT ;
    USE SIGNAL ;
    PORT
      LAYER M4 ;
        RECT  0 122.112 0.192 122.136 ;
    END
  END o[214]
  PIN o[215]
    DIRECTION OUTPUT ;
    USE SIGNAL ;
    PORT
      LAYER M4 ;
        RECT  0 122.304 0.192 122.328 ;
    END
  END o[215]
  PIN o[216]
    DIRECTION OUTPUT ;
    USE SIGNAL ;
    PORT
      LAYER M4 ;
        RECT  0 122.448 0.192 122.472 ;
    END
  END o[216]
  PIN o[217]
    DIRECTION OUTPUT ;
    USE SIGNAL ;
    PORT
      LAYER M4 ;
        RECT  0 122.592 0.192 122.616 ;
    END
  END o[217]
  PIN o[218]
    DIRECTION OUTPUT ;
    USE SIGNAL ;
    PORT
      LAYER M4 ;
        RECT  0 122.784 0.192 122.808 ;
    END
  END o[218]
  PIN o[219]
    DIRECTION OUTPUT ;
    USE SIGNAL ;
    PORT
      LAYER M4 ;
        RECT  0 122.928 0.192 122.952 ;
    END
  END o[219]
  PIN o[21]
    DIRECTION OUTPUT ;
    USE SIGNAL ;
    PORT
      LAYER M4 ;
        RECT  0 90.96 0.192 90.984 ;
    END
  END o[21]
  PIN o[220]
    DIRECTION OUTPUT ;
    USE SIGNAL ;
    PORT
      LAYER M4 ;
        RECT  0 123.12 0.192 123.144 ;
    END
  END o[220]
  PIN o[221]
    DIRECTION OUTPUT ;
    USE SIGNAL ;
    PORT
      LAYER M4 ;
        RECT  0 123.264 0.192 123.288 ;
    END
  END o[221]
  PIN o[222]
    DIRECTION OUTPUT ;
    USE SIGNAL ;
    PORT
      LAYER M4 ;
        RECT  0 123.408 0.192 123.432 ;
    END
  END o[222]
  PIN o[223]
    DIRECTION OUTPUT ;
    USE SIGNAL ;
    PORT
      LAYER M4 ;
        RECT  0 123.6 0.192 123.624 ;
    END
  END o[223]
  PIN o[224]
    DIRECTION OUTPUT ;
    USE SIGNAL ;
    PORT
      LAYER M4 ;
        RECT  0 123.744 0.192 123.768 ;
    END
  END o[224]
  PIN o[225]
    DIRECTION OUTPUT ;
    USE SIGNAL ;
    PORT
      LAYER M4 ;
        RECT  0 123.888 0.192 123.912 ;
    END
  END o[225]
  PIN o[226]
    DIRECTION OUTPUT ;
    USE SIGNAL ;
    PORT
      LAYER M4 ;
        RECT  0 124.08 0.192 124.104 ;
    END
  END o[226]
  PIN o[227]
    DIRECTION OUTPUT ;
    USE SIGNAL ;
    PORT
      LAYER M4 ;
        RECT  0 124.224 0.192 124.248 ;
    END
  END o[227]
  PIN o[228]
    DIRECTION OUTPUT ;
    USE SIGNAL ;
    PORT
      LAYER M4 ;
        RECT  0 124.368 0.192 124.392 ;
    END
  END o[228]
  PIN o[229]
    DIRECTION OUTPUT ;
    USE SIGNAL ;
    PORT
      LAYER M4 ;
        RECT  0 124.56 0.192 124.584 ;
    END
  END o[229]
  PIN o[22]
    DIRECTION OUTPUT ;
    USE SIGNAL ;
    PORT
      LAYER M4 ;
        RECT  0 91.104 0.192 91.128 ;
    END
  END o[22]
  PIN o[230]
    DIRECTION OUTPUT ;
    USE SIGNAL ;
    PORT
      LAYER M4 ;
        RECT  0 124.704 0.192 124.728 ;
    END
  END o[230]
  PIN o[231]
    DIRECTION OUTPUT ;
    USE SIGNAL ;
    PORT
      LAYER M4 ;
        RECT  0 124.896 0.192 124.92 ;
    END
  END o[231]
  PIN o[232]
    DIRECTION OUTPUT ;
    USE SIGNAL ;
    PORT
      LAYER M4 ;
        RECT  0 125.04 0.192 125.064 ;
    END
  END o[232]
  PIN o[233]
    DIRECTION OUTPUT ;
    USE SIGNAL ;
    PORT
      LAYER M4 ;
        RECT  0 125.184 0.192 125.208 ;
    END
  END o[233]
  PIN o[234]
    DIRECTION OUTPUT ;
    USE SIGNAL ;
    PORT
      LAYER M4 ;
        RECT  0 125.376 0.192 125.4 ;
    END
  END o[234]
  PIN o[235]
    DIRECTION OUTPUT ;
    USE SIGNAL ;
    PORT
      LAYER M4 ;
        RECT  0 125.52 0.192 125.544 ;
    END
  END o[235]
  PIN o[236]
    DIRECTION OUTPUT ;
    USE SIGNAL ;
    PORT
      LAYER M4 ;
        RECT  0 125.664 0.192 125.688 ;
    END
  END o[236]
  PIN o[237]
    DIRECTION OUTPUT ;
    USE SIGNAL ;
    PORT
      LAYER M4 ;
        RECT  0 125.856 0.192 125.88 ;
    END
  END o[237]
  PIN o[238]
    DIRECTION OUTPUT ;
    USE SIGNAL ;
    PORT
      LAYER M4 ;
        RECT  0 126 0.192 126.024 ;
    END
  END o[238]
  PIN o[239]
    DIRECTION OUTPUT ;
    USE SIGNAL ;
    PORT
      LAYER M4 ;
        RECT  0 126.144 0.192 126.168 ;
    END
  END o[239]
  PIN o[23]
    DIRECTION OUTPUT ;
    USE SIGNAL ;
    PORT
      LAYER M4 ;
        RECT  0 91.296 0.192 91.32 ;
    END
  END o[23]
  PIN o[240]
    DIRECTION OUTPUT ;
    USE SIGNAL ;
    PORT
      LAYER M4 ;
        RECT  0 126.336 0.192 126.36 ;
    END
  END o[240]
  PIN o[241]
    DIRECTION OUTPUT ;
    USE SIGNAL ;
    PORT
      LAYER M4 ;
        RECT  0 126.48 0.192 126.504 ;
    END
  END o[241]
  PIN o[242]
    DIRECTION OUTPUT ;
    USE SIGNAL ;
    PORT
      LAYER M4 ;
        RECT  0 126.672 0.192 126.696 ;
    END
  END o[242]
  PIN o[243]
    DIRECTION OUTPUT ;
    USE SIGNAL ;
    PORT
      LAYER M4 ;
        RECT  0 126.816 0.192 126.84 ;
    END
  END o[243]
  PIN o[244]
    DIRECTION OUTPUT ;
    USE SIGNAL ;
    PORT
      LAYER M4 ;
        RECT  0 126.96 0.192 126.984 ;
    END
  END o[244]
  PIN o[245]
    DIRECTION OUTPUT ;
    USE SIGNAL ;
    PORT
      LAYER M4 ;
        RECT  0 127.152 0.192 127.176 ;
    END
  END o[245]
  PIN o[246]
    DIRECTION OUTPUT ;
    USE SIGNAL ;
    PORT
      LAYER M4 ;
        RECT  0 127.296 0.192 127.32 ;
    END
  END o[246]
  PIN o[247]
    DIRECTION OUTPUT ;
    USE SIGNAL ;
    PORT
      LAYER M4 ;
        RECT  0 127.44 0.192 127.464 ;
    END
  END o[247]
  PIN o[248]
    DIRECTION OUTPUT ;
    USE SIGNAL ;
    PORT
      LAYER M4 ;
        RECT  0 127.632 0.192 127.656 ;
    END
  END o[248]
  PIN o[249]
    DIRECTION OUTPUT ;
    USE SIGNAL ;
    PORT
      LAYER M4 ;
        RECT  0 127.776 0.192 127.8 ;
    END
  END o[249]
  PIN o[24]
    DIRECTION OUTPUT ;
    USE SIGNAL ;
    PORT
      LAYER M4 ;
        RECT  0 91.44 0.192 91.464 ;
    END
  END o[24]
  PIN o[250]
    DIRECTION OUTPUT ;
    USE SIGNAL ;
    PORT
      LAYER M4 ;
        RECT  0 127.92 0.192 127.944 ;
    END
  END o[250]
  PIN o[251]
    DIRECTION OUTPUT ;
    USE SIGNAL ;
    PORT
      LAYER M4 ;
        RECT  0 128.112 0.192 128.136 ;
    END
  END o[251]
  PIN o[252]
    DIRECTION OUTPUT ;
    USE SIGNAL ;
    PORT
      LAYER M4 ;
        RECT  0 128.256 0.192 128.28 ;
    END
  END o[252]
  PIN o[253]
    DIRECTION OUTPUT ;
    USE SIGNAL ;
    PORT
      LAYER M4 ;
        RECT  0 128.448 0.192 128.472 ;
    END
  END o[253]
  PIN o[254]
    DIRECTION OUTPUT ;
    USE SIGNAL ;
    PORT
      LAYER M4 ;
        RECT  0 128.592 0.192 128.616 ;
    END
  END o[254]
  PIN o[255]
    DIRECTION OUTPUT ;
    USE SIGNAL ;
    PORT
      LAYER M4 ;
        RECT  0 128.736 0.192 128.76 ;
    END
  END o[255]
  PIN o[256]
    DIRECTION OUTPUT ;
    USE SIGNAL ;
    PORT
      LAYER M4 ;
        RECT  0 128.928 0.192 128.952 ;
    END
  END o[256]
  PIN o[257]
    DIRECTION OUTPUT ;
    USE SIGNAL ;
    PORT
      LAYER M4 ;
        RECT  0 129.072 0.192 129.096 ;
    END
  END o[257]
  PIN o[258]
    DIRECTION OUTPUT ;
    USE SIGNAL ;
    PORT
      LAYER M4 ;
        RECT  0 129.216 0.192 129.24 ;
    END
  END o[258]
  PIN o[259]
    DIRECTION OUTPUT ;
    USE SIGNAL ;
    PORT
      LAYER M4 ;
        RECT  0 129.408 0.192 129.432 ;
    END
  END o[259]
  PIN o[25]
    DIRECTION OUTPUT ;
    USE SIGNAL ;
    PORT
      LAYER M4 ;
        RECT  0 91.632 0.192 91.656 ;
    END
  END o[25]
  PIN o[260]
    DIRECTION OUTPUT ;
    USE SIGNAL ;
    PORT
      LAYER M4 ;
        RECT  0 129.552 0.192 129.576 ;
    END
  END o[260]
  PIN o[261]
    DIRECTION OUTPUT ;
    USE SIGNAL ;
    PORT
      LAYER M4 ;
        RECT  0 129.696 0.192 129.72 ;
    END
  END o[261]
  PIN o[262]
    DIRECTION OUTPUT ;
    USE SIGNAL ;
    PORT
      LAYER M4 ;
        RECT  0 129.888 0.192 129.912 ;
    END
  END o[262]
  PIN o[263]
    DIRECTION OUTPUT ;
    USE SIGNAL ;
    PORT
      LAYER M4 ;
        RECT  0 130.032 0.192 130.056 ;
    END
  END o[263]
  PIN o[264]
    DIRECTION OUTPUT ;
    USE SIGNAL ;
    PORT
      LAYER M4 ;
        RECT  0 130.224 0.192 130.248 ;
    END
  END o[264]
  PIN o[265]
    DIRECTION OUTPUT ;
    USE SIGNAL ;
    PORT
      LAYER M4 ;
        RECT  0 130.368 0.192 130.392 ;
    END
  END o[265]
  PIN o[266]
    DIRECTION OUTPUT ;
    USE SIGNAL ;
    PORT
      LAYER M4 ;
        RECT  0 130.512 0.192 130.536 ;
    END
  END o[266]
  PIN o[267]
    DIRECTION OUTPUT ;
    USE SIGNAL ;
    PORT
      LAYER M4 ;
        RECT  0 130.704 0.192 130.728 ;
    END
  END o[267]
  PIN o[268]
    DIRECTION OUTPUT ;
    USE SIGNAL ;
    PORT
      LAYER M4 ;
        RECT  0 130.848 0.192 130.872 ;
    END
  END o[268]
  PIN o[269]
    DIRECTION OUTPUT ;
    USE SIGNAL ;
    PORT
      LAYER M4 ;
        RECT  0 130.992 0.192 131.016 ;
    END
  END o[269]
  PIN o[26]
    DIRECTION OUTPUT ;
    USE SIGNAL ;
    PORT
      LAYER M4 ;
        RECT  0 91.776 0.192 91.8 ;
    END
  END o[26]
  PIN o[270]
    DIRECTION OUTPUT ;
    USE SIGNAL ;
    PORT
      LAYER M4 ;
        RECT  0 131.184 0.192 131.208 ;
    END
  END o[270]
  PIN o[271]
    DIRECTION OUTPUT ;
    USE SIGNAL ;
    PORT
      LAYER M4 ;
        RECT  0 131.328 0.192 131.352 ;
    END
  END o[271]
  PIN o[272]
    DIRECTION OUTPUT ;
    USE SIGNAL ;
    PORT
      LAYER M4 ;
        RECT  0 131.472 0.192 131.496 ;
    END
  END o[272]
  PIN o[273]
    DIRECTION OUTPUT ;
    USE SIGNAL ;
    PORT
      LAYER M4 ;
        RECT  0 131.664 0.192 131.688 ;
    END
  END o[273]
  PIN o[274]
    DIRECTION OUTPUT ;
    USE SIGNAL ;
    PORT
      LAYER M4 ;
        RECT  0 131.808 0.192 131.832 ;
    END
  END o[274]
  PIN o[275]
    DIRECTION OUTPUT ;
    USE SIGNAL ;
    PORT
      LAYER M4 ;
        RECT  0 132 0.192 132.024 ;
    END
  END o[275]
  PIN o[276]
    DIRECTION OUTPUT ;
    USE SIGNAL ;
    PORT
      LAYER M4 ;
        RECT  0 132.144 0.192 132.168 ;
    END
  END o[276]
  PIN o[277]
    DIRECTION OUTPUT ;
    USE SIGNAL ;
    PORT
      LAYER M4 ;
        RECT  0 132.288 0.192 132.312 ;
    END
  END o[277]
  PIN o[278]
    DIRECTION OUTPUT ;
    USE SIGNAL ;
    PORT
      LAYER M4 ;
        RECT  0 132.48 0.192 132.504 ;
    END
  END o[278]
  PIN o[279]
    DIRECTION OUTPUT ;
    USE SIGNAL ;
    PORT
      LAYER M4 ;
        RECT  0 132.624 0.192 132.648 ;
    END
  END o[279]
  PIN o[27]
    DIRECTION OUTPUT ;
    USE SIGNAL ;
    PORT
      LAYER M4 ;
        RECT  0 91.92 0.192 91.944 ;
    END
  END o[27]
  PIN o[280]
    DIRECTION OUTPUT ;
    USE SIGNAL ;
    PORT
      LAYER M4 ;
        RECT  0 132.768 0.192 132.792 ;
    END
  END o[280]
  PIN o[281]
    DIRECTION OUTPUT ;
    USE SIGNAL ;
    PORT
      LAYER M4 ;
        RECT  0 132.96 0.192 132.984 ;
    END
  END o[281]
  PIN o[282]
    DIRECTION OUTPUT ;
    USE SIGNAL ;
    PORT
      LAYER M4 ;
        RECT  0 133.104 0.192 133.128 ;
    END
  END o[282]
  PIN o[283]
    DIRECTION OUTPUT ;
    USE SIGNAL ;
    PORT
      LAYER M4 ;
        RECT  0 133.248 0.192 133.272 ;
    END
  END o[283]
  PIN o[284]
    DIRECTION OUTPUT ;
    USE SIGNAL ;
    PORT
      LAYER M4 ;
        RECT  0 133.44 0.192 133.464 ;
    END
  END o[284]
  PIN o[285]
    DIRECTION OUTPUT ;
    USE SIGNAL ;
    PORT
      LAYER M4 ;
        RECT  0 133.584 0.192 133.608 ;
    END
  END o[285]
  PIN o[286]
    DIRECTION OUTPUT ;
    USE SIGNAL ;
    PORT
      LAYER M4 ;
        RECT  0 133.776 0.192 133.8 ;
    END
  END o[286]
  PIN o[287]
    DIRECTION OUTPUT ;
    USE SIGNAL ;
    PORT
      LAYER M4 ;
        RECT  0 133.92 0.192 133.944 ;
    END
  END o[287]
  PIN o[288]
    DIRECTION OUTPUT ;
    USE SIGNAL ;
    PORT
      LAYER M4 ;
        RECT  0 134.064 0.192 134.088 ;
    END
  END o[288]
  PIN o[289]
    DIRECTION OUTPUT ;
    USE SIGNAL ;
    PORT
      LAYER M4 ;
        RECT  0 134.256 0.192 134.28 ;
    END
  END o[289]
  PIN o[28]
    DIRECTION OUTPUT ;
    USE SIGNAL ;
    PORT
      LAYER M4 ;
        RECT  0 92.112 0.192 92.136 ;
    END
  END o[28]
  PIN o[290]
    DIRECTION OUTPUT ;
    USE SIGNAL ;
    PORT
      LAYER M4 ;
        RECT  0 134.4 0.192 134.424 ;
    END
  END o[290]
  PIN o[291]
    DIRECTION OUTPUT ;
    USE SIGNAL ;
    PORT
      LAYER M4 ;
        RECT  0 134.544 0.192 134.568 ;
    END
  END o[291]
  PIN o[292]
    DIRECTION OUTPUT ;
    USE SIGNAL ;
    PORT
      LAYER M4 ;
        RECT  0 134.736 0.192 134.76 ;
    END
  END o[292]
  PIN o[293]
    DIRECTION OUTPUT ;
    USE SIGNAL ;
    PORT
      LAYER M4 ;
        RECT  0 134.88 0.192 134.904 ;
    END
  END o[293]
  PIN o[294]
    DIRECTION OUTPUT ;
    USE SIGNAL ;
    PORT
      LAYER M4 ;
        RECT  0 135.024 0.192 135.048 ;
    END
  END o[294]
  PIN o[295]
    DIRECTION OUTPUT ;
    USE SIGNAL ;
    PORT
      LAYER M4 ;
        RECT  0 135.216 0.192 135.24 ;
    END
  END o[295]
  PIN o[296]
    DIRECTION OUTPUT ;
    USE SIGNAL ;
    PORT
      LAYER M4 ;
        RECT  0 135.36 0.192 135.384 ;
    END
  END o[296]
  PIN o[297]
    DIRECTION OUTPUT ;
    USE SIGNAL ;
    PORT
      LAYER M4 ;
        RECT  0 135.552 0.192 135.576 ;
    END
  END o[297]
  PIN o[298]
    DIRECTION OUTPUT ;
    USE SIGNAL ;
    PORT
      LAYER M4 ;
        RECT  0 135.696 0.192 135.72 ;
    END
  END o[298]
  PIN o[299]
    DIRECTION OUTPUT ;
    USE SIGNAL ;
    PORT
      LAYER M4 ;
        RECT  0 135.84 0.192 135.864 ;
    END
  END o[299]
  PIN o[29]
    DIRECTION OUTPUT ;
    USE SIGNAL ;
    PORT
      LAYER M4 ;
        RECT  0 92.256 0.192 92.28 ;
    END
  END o[29]
  PIN o[2]
    DIRECTION OUTPUT ;
    USE SIGNAL ;
    PORT
      LAYER M4 ;
        RECT  0 87.888 0.192 87.912 ;
    END
  END o[2]
  PIN o[300]
    DIRECTION OUTPUT ;
    USE SIGNAL ;
    PORT
      LAYER M4 ;
        RECT  0 136.032 0.192 136.056 ;
    END
  END o[300]
  PIN o[301]
    DIRECTION OUTPUT ;
    USE SIGNAL ;
    PORT
      LAYER M4 ;
        RECT  0 136.176 0.192 136.2 ;
    END
  END o[301]
  PIN o[302]
    DIRECTION OUTPUT ;
    USE SIGNAL ;
    PORT
      LAYER M4 ;
        RECT  0 136.32 0.192 136.344 ;
    END
  END o[302]
  PIN o[303]
    DIRECTION OUTPUT ;
    USE SIGNAL ;
    PORT
      LAYER M4 ;
        RECT  0 136.512 0.192 136.536 ;
    END
  END o[303]
  PIN o[304]
    DIRECTION OUTPUT ;
    USE SIGNAL ;
    PORT
      LAYER M4 ;
        RECT  0 136.656 0.192 136.68 ;
    END
  END o[304]
  PIN o[305]
    DIRECTION OUTPUT ;
    USE SIGNAL ;
    PORT
      LAYER M4 ;
        RECT  0 136.8 0.192 136.824 ;
    END
  END o[305]
  PIN o[306]
    DIRECTION OUTPUT ;
    USE SIGNAL ;
    PORT
      LAYER M4 ;
        RECT  0 136.992 0.192 137.016 ;
    END
  END o[306]
  PIN o[307]
    DIRECTION OUTPUT ;
    USE SIGNAL ;
    PORT
      LAYER M4 ;
        RECT  0 137.136 0.192 137.16 ;
    END
  END o[307]
  PIN o[308]
    DIRECTION OUTPUT ;
    USE SIGNAL ;
    PORT
      LAYER M4 ;
        RECT  0 137.328 0.192 137.352 ;
    END
  END o[308]
  PIN o[309]
    DIRECTION OUTPUT ;
    USE SIGNAL ;
    PORT
      LAYER M4 ;
        RECT  0 137.472 0.192 137.496 ;
    END
  END o[309]
  PIN o[30]
    DIRECTION OUTPUT ;
    USE SIGNAL ;
    PORT
      LAYER M4 ;
        RECT  0 92.4 0.192 92.424 ;
    END
  END o[30]
  PIN o[310]
    DIRECTION OUTPUT ;
    USE SIGNAL ;
    PORT
      LAYER M4 ;
        RECT  0 137.616 0.192 137.64 ;
    END
  END o[310]
  PIN o[311]
    DIRECTION OUTPUT ;
    USE SIGNAL ;
    PORT
      LAYER M4 ;
        RECT  0 137.808 0.192 137.832 ;
    END
  END o[311]
  PIN o[312]
    DIRECTION OUTPUT ;
    USE SIGNAL ;
    PORT
      LAYER M4 ;
        RECT  0 137.952 0.192 137.976 ;
    END
  END o[312]
  PIN o[313]
    DIRECTION OUTPUT ;
    USE SIGNAL ;
    PORT
      LAYER M4 ;
        RECT  0 138.096 0.192 138.12 ;
    END
  END o[313]
  PIN o[314]
    DIRECTION OUTPUT ;
    USE SIGNAL ;
    PORT
      LAYER M4 ;
        RECT  0 138.288 0.192 138.312 ;
    END
  END o[314]
  PIN o[315]
    DIRECTION OUTPUT ;
    USE SIGNAL ;
    PORT
      LAYER M4 ;
        RECT  0 138.432 0.192 138.456 ;
    END
  END o[315]
  PIN o[316]
    DIRECTION OUTPUT ;
    USE SIGNAL ;
    PORT
      LAYER M4 ;
        RECT  0 138.576 0.192 138.6 ;
    END
  END o[316]
  PIN o[317]
    DIRECTION OUTPUT ;
    USE SIGNAL ;
    PORT
      LAYER M4 ;
        RECT  0 138.768 0.192 138.792 ;
    END
  END o[317]
  PIN o[318]
    DIRECTION OUTPUT ;
    USE SIGNAL ;
    PORT
      LAYER M4 ;
        RECT  0 138.912 0.192 138.936 ;
    END
  END o[318]
  PIN o[319]
    DIRECTION OUTPUT ;
    USE SIGNAL ;
    PORT
      LAYER M4 ;
        RECT  0 139.104 0.192 139.128 ;
    END
  END o[319]
  PIN o[31]
    DIRECTION OUTPUT ;
    USE SIGNAL ;
    PORT
      LAYER M4 ;
        RECT  0 92.592 0.192 92.616 ;
    END
  END o[31]
  PIN o[320]
    DIRECTION OUTPUT ;
    USE SIGNAL ;
    PORT
      LAYER M4 ;
        RECT  0 139.248 0.192 139.272 ;
    END
  END o[320]
  PIN o[321]
    DIRECTION OUTPUT ;
    USE SIGNAL ;
    PORT
      LAYER M4 ;
        RECT  0 139.392 0.192 139.416 ;
    END
  END o[321]
  PIN o[322]
    DIRECTION OUTPUT ;
    USE SIGNAL ;
    PORT
      LAYER M4 ;
        RECT  0 139.584 0.192 139.608 ;
    END
  END o[322]
  PIN o[323]
    DIRECTION OUTPUT ;
    USE SIGNAL ;
    PORT
      LAYER M4 ;
        RECT  0 139.728 0.192 139.752 ;
    END
  END o[323]
  PIN o[324]
    DIRECTION OUTPUT ;
    USE SIGNAL ;
    PORT
      LAYER M4 ;
        RECT  0 139.872 0.192 139.896 ;
    END
  END o[324]
  PIN o[325]
    DIRECTION OUTPUT ;
    USE SIGNAL ;
    PORT
      LAYER M4 ;
        RECT  0 140.064 0.192 140.088 ;
    END
  END o[325]
  PIN o[326]
    DIRECTION OUTPUT ;
    USE SIGNAL ;
    PORT
      LAYER M4 ;
        RECT  0 140.208 0.192 140.232 ;
    END
  END o[326]
  PIN o[327]
    DIRECTION OUTPUT ;
    USE SIGNAL ;
    PORT
      LAYER M4 ;
        RECT  0 140.352 0.192 140.376 ;
    END
  END o[327]
  PIN o[328]
    DIRECTION OUTPUT ;
    USE SIGNAL ;
    PORT
      LAYER M4 ;
        RECT  0 140.544 0.192 140.568 ;
    END
  END o[328]
  PIN o[329]
    DIRECTION OUTPUT ;
    USE SIGNAL ;
    PORT
      LAYER M4 ;
        RECT  0 140.688 0.192 140.712 ;
    END
  END o[329]
  PIN o[32]
    DIRECTION OUTPUT ;
    USE SIGNAL ;
    PORT
      LAYER M4 ;
        RECT  0 92.736 0.192 92.76 ;
    END
  END o[32]
  PIN o[330]
    DIRECTION OUTPUT ;
    USE SIGNAL ;
    PORT
      LAYER M4 ;
        RECT  0 140.88 0.192 140.904 ;
    END
  END o[330]
  PIN o[331]
    DIRECTION OUTPUT ;
    USE SIGNAL ;
    PORT
      LAYER M4 ;
        RECT  0 141.024 0.192 141.048 ;
    END
  END o[331]
  PIN o[332]
    DIRECTION OUTPUT ;
    USE SIGNAL ;
    PORT
      LAYER M4 ;
        RECT  0 141.168 0.192 141.192 ;
    END
  END o[332]
  PIN o[333]
    DIRECTION OUTPUT ;
    USE SIGNAL ;
    PORT
      LAYER M4 ;
        RECT  0 141.36 0.192 141.384 ;
    END
  END o[333]
  PIN o[334]
    DIRECTION OUTPUT ;
    USE SIGNAL ;
    PORT
      LAYER M4 ;
        RECT  0 141.504 0.192 141.528 ;
    END
  END o[334]
  PIN o[335]
    DIRECTION OUTPUT ;
    USE SIGNAL ;
    PORT
      LAYER M4 ;
        RECT  0 141.648 0.192 141.672 ;
    END
  END o[335]
  PIN o[336]
    DIRECTION OUTPUT ;
    USE SIGNAL ;
    PORT
      LAYER M4 ;
        RECT  0 141.84 0.192 141.864 ;
    END
  END o[336]
  PIN o[337]
    DIRECTION OUTPUT ;
    USE SIGNAL ;
    PORT
      LAYER M4 ;
        RECT  0 141.984 0.192 142.008 ;
    END
  END o[337]
  PIN o[338]
    DIRECTION OUTPUT ;
    USE SIGNAL ;
    PORT
      LAYER M4 ;
        RECT  0 142.128 0.192 142.152 ;
    END
  END o[338]
  PIN o[339]
    DIRECTION OUTPUT ;
    USE SIGNAL ;
    PORT
      LAYER M4 ;
        RECT  0 142.32 0.192 142.344 ;
    END
  END o[339]
  PIN o[33]
    DIRECTION OUTPUT ;
    USE SIGNAL ;
    PORT
      LAYER M4 ;
        RECT  0 92.88 0.192 92.904 ;
    END
  END o[33]
  PIN o[340]
    DIRECTION OUTPUT ;
    USE SIGNAL ;
    PORT
      LAYER M4 ;
        RECT  0 142.464 0.192 142.488 ;
    END
  END o[340]
  PIN o[341]
    DIRECTION OUTPUT ;
    USE SIGNAL ;
    PORT
      LAYER M4 ;
        RECT  0 142.656 0.192 142.68 ;
    END
  END o[341]
  PIN o[342]
    DIRECTION OUTPUT ;
    USE SIGNAL ;
    PORT
      LAYER M4 ;
        RECT  0 142.8 0.192 142.824 ;
    END
  END o[342]
  PIN o[343]
    DIRECTION OUTPUT ;
    USE SIGNAL ;
    PORT
      LAYER M4 ;
        RECT  0 142.944 0.192 142.968 ;
    END
  END o[343]
  PIN o[344]
    DIRECTION OUTPUT ;
    USE SIGNAL ;
    PORT
      LAYER M4 ;
        RECT  0 143.136 0.192 143.16 ;
    END
  END o[344]
  PIN o[345]
    DIRECTION OUTPUT ;
    USE SIGNAL ;
    PORT
      LAYER M4 ;
        RECT  0 143.28 0.192 143.304 ;
    END
  END o[345]
  PIN o[346]
    DIRECTION OUTPUT ;
    USE SIGNAL ;
    PORT
      LAYER M4 ;
        RECT  0 143.424 0.192 143.448 ;
    END
  END o[346]
  PIN o[347]
    DIRECTION OUTPUT ;
    USE SIGNAL ;
    PORT
      LAYER M4 ;
        RECT  0 143.616 0.192 143.64 ;
    END
  END o[347]
  PIN o[348]
    DIRECTION OUTPUT ;
    USE SIGNAL ;
    PORT
      LAYER M4 ;
        RECT  0 143.76 0.192 143.784 ;
    END
  END o[348]
  PIN o[349]
    DIRECTION OUTPUT ;
    USE SIGNAL ;
    PORT
      LAYER M4 ;
        RECT  0 143.904 0.192 143.928 ;
    END
  END o[349]
  PIN o[34]
    DIRECTION OUTPUT ;
    USE SIGNAL ;
    PORT
      LAYER M4 ;
        RECT  0 93.072 0.192 93.096 ;
    END
  END o[34]
  PIN o[350]
    DIRECTION OUTPUT ;
    USE SIGNAL ;
    PORT
      LAYER M4 ;
        RECT  0 144.096 0.192 144.12 ;
    END
  END o[350]
  PIN o[351]
    DIRECTION OUTPUT ;
    USE SIGNAL ;
    PORT
      LAYER M4 ;
        RECT  0 144.24 0.192 144.264 ;
    END
  END o[351]
  PIN o[352]
    DIRECTION OUTPUT ;
    USE SIGNAL ;
    PORT
      LAYER M4 ;
        RECT  0 144.432 0.192 144.456 ;
    END
  END o[352]
  PIN o[353]
    DIRECTION OUTPUT ;
    USE SIGNAL ;
    PORT
      LAYER M4 ;
        RECT  0 144.576 0.192 144.6 ;
    END
  END o[353]
  PIN o[354]
    DIRECTION OUTPUT ;
    USE SIGNAL ;
    PORT
      LAYER M4 ;
        RECT  0 144.72 0.192 144.744 ;
    END
  END o[354]
  PIN o[355]
    DIRECTION OUTPUT ;
    USE SIGNAL ;
    PORT
      LAYER M4 ;
        RECT  0 144.912 0.192 144.936 ;
    END
  END o[355]
  PIN o[356]
    DIRECTION OUTPUT ;
    USE SIGNAL ;
    PORT
      LAYER M4 ;
        RECT  0 145.056 0.192 145.08 ;
    END
  END o[356]
  PIN o[357]
    DIRECTION OUTPUT ;
    USE SIGNAL ;
    PORT
      LAYER M4 ;
        RECT  0 145.2 0.192 145.224 ;
    END
  END o[357]
  PIN o[358]
    DIRECTION OUTPUT ;
    USE SIGNAL ;
    PORT
      LAYER M4 ;
        RECT  0 145.392 0.192 145.416 ;
    END
  END o[358]
  PIN o[359]
    DIRECTION OUTPUT ;
    USE SIGNAL ;
    PORT
      LAYER M4 ;
        RECT  0 145.536 0.192 145.56 ;
    END
  END o[359]
  PIN o[35]
    DIRECTION OUTPUT ;
    USE SIGNAL ;
    PORT
      LAYER M4 ;
        RECT  0 93.216 0.192 93.24 ;
    END
  END o[35]
  PIN o[360]
    DIRECTION OUTPUT ;
    USE SIGNAL ;
    PORT
      LAYER M4 ;
        RECT  0 145.68 0.192 145.704 ;
    END
  END o[360]
  PIN o[361]
    DIRECTION OUTPUT ;
    USE SIGNAL ;
    PORT
      LAYER M4 ;
        RECT  0 145.872 0.192 145.896 ;
    END
  END o[361]
  PIN o[362]
    DIRECTION OUTPUT ;
    USE SIGNAL ;
    PORT
      LAYER M4 ;
        RECT  0 146.016 0.192 146.04 ;
    END
  END o[362]
  PIN o[363]
    DIRECTION OUTPUT ;
    USE SIGNAL ;
    PORT
      LAYER M4 ;
        RECT  0 146.208 0.192 146.232 ;
    END
  END o[363]
  PIN o[364]
    DIRECTION OUTPUT ;
    USE SIGNAL ;
    PORT
      LAYER M4 ;
        RECT  0 146.352 0.192 146.376 ;
    END
  END o[364]
  PIN o[365]
    DIRECTION OUTPUT ;
    USE SIGNAL ;
    PORT
      LAYER M4 ;
        RECT  0 146.496 0.192 146.52 ;
    END
  END o[365]
  PIN o[366]
    DIRECTION OUTPUT ;
    USE SIGNAL ;
    PORT
      LAYER M4 ;
        RECT  0 146.688 0.192 146.712 ;
    END
  END o[366]
  PIN o[367]
    DIRECTION OUTPUT ;
    USE SIGNAL ;
    PORT
      LAYER M4 ;
        RECT  0 146.832 0.192 146.856 ;
    END
  END o[367]
  PIN o[368]
    DIRECTION OUTPUT ;
    USE SIGNAL ;
    PORT
      LAYER M4 ;
        RECT  0 146.976 0.192 147 ;
    END
  END o[368]
  PIN o[369]
    DIRECTION OUTPUT ;
    USE SIGNAL ;
    PORT
      LAYER M4 ;
        RECT  0 147.168 0.192 147.192 ;
    END
  END o[369]
  PIN o[36]
    DIRECTION OUTPUT ;
    USE SIGNAL ;
    PORT
      LAYER M4 ;
        RECT  0 93.408 0.192 93.432 ;
    END
  END o[36]
  PIN o[370]
    DIRECTION OUTPUT ;
    USE SIGNAL ;
    PORT
      LAYER M4 ;
        RECT  0 147.312 0.192 147.336 ;
    END
  END o[370]
  PIN o[371]
    DIRECTION OUTPUT ;
    USE SIGNAL ;
    PORT
      LAYER M4 ;
        RECT  0 147.504 0.192 147.528 ;
    END
  END o[371]
  PIN o[372]
    DIRECTION OUTPUT ;
    USE SIGNAL ;
    PORT
      LAYER M4 ;
        RECT  0 147.648 0.192 147.672 ;
    END
  END o[372]
  PIN o[373]
    DIRECTION OUTPUT ;
    USE SIGNAL ;
    PORT
      LAYER M4 ;
        RECT  0 147.792 0.192 147.816 ;
    END
  END o[373]
  PIN o[374]
    DIRECTION OUTPUT ;
    USE SIGNAL ;
    PORT
      LAYER M4 ;
        RECT  0 147.984 0.192 148.008 ;
    END
  END o[374]
  PIN o[375]
    DIRECTION OUTPUT ;
    USE SIGNAL ;
    PORT
      LAYER M4 ;
        RECT  0 148.128 0.192 148.152 ;
    END
  END o[375]
  PIN o[376]
    DIRECTION OUTPUT ;
    USE SIGNAL ;
    PORT
      LAYER M4 ;
        RECT  0 148.272 0.192 148.296 ;
    END
  END o[376]
  PIN o[377]
    DIRECTION OUTPUT ;
    USE SIGNAL ;
    PORT
      LAYER M4 ;
        RECT  0 148.464 0.192 148.488 ;
    END
  END o[377]
  PIN o[378]
    DIRECTION OUTPUT ;
    USE SIGNAL ;
    PORT
      LAYER M4 ;
        RECT  0 148.608 0.192 148.632 ;
    END
  END o[378]
  PIN o[379]
    DIRECTION OUTPUT ;
    USE SIGNAL ;
    PORT
      LAYER M4 ;
        RECT  0 148.752 0.192 148.776 ;
    END
  END o[379]
  PIN o[37]
    DIRECTION OUTPUT ;
    USE SIGNAL ;
    PORT
      LAYER M4 ;
        RECT  0 93.552 0.192 93.576 ;
    END
  END o[37]
  PIN o[380]
    DIRECTION OUTPUT ;
    USE SIGNAL ;
    PORT
      LAYER M4 ;
        RECT  0 148.944 0.192 148.968 ;
    END
  END o[380]
  PIN o[381]
    DIRECTION OUTPUT ;
    USE SIGNAL ;
    PORT
      LAYER M4 ;
        RECT  0 149.088 0.192 149.112 ;
    END
  END o[381]
  PIN o[382]
    DIRECTION OUTPUT ;
    USE SIGNAL ;
    PORT
      LAYER M4 ;
        RECT  0 149.28 0.192 149.304 ;
    END
  END o[382]
  PIN o[383]
    DIRECTION OUTPUT ;
    USE SIGNAL ;
    PORT
      LAYER M4 ;
        RECT  0 149.424 0.192 149.448 ;
    END
  END o[383]
  PIN o[384]
    DIRECTION OUTPUT ;
    USE SIGNAL ;
    PORT
      LAYER M4 ;
        RECT  0 149.568 0.192 149.592 ;
    END
  END o[384]
  PIN o[385]
    DIRECTION OUTPUT ;
    USE SIGNAL ;
    PORT
      LAYER M4 ;
        RECT  0 149.76 0.192 149.784 ;
    END
  END o[385]
  PIN o[386]
    DIRECTION OUTPUT ;
    USE SIGNAL ;
    PORT
      LAYER M4 ;
        RECT  0 149.904 0.192 149.928 ;
    END
  END o[386]
  PIN o[387]
    DIRECTION OUTPUT ;
    USE SIGNAL ;
    PORT
      LAYER M4 ;
        RECT  0 150.048 0.192 150.072 ;
    END
  END o[387]
  PIN o[388]
    DIRECTION OUTPUT ;
    USE SIGNAL ;
    PORT
      LAYER M4 ;
        RECT  0 150.24 0.192 150.264 ;
    END
  END o[388]
  PIN o[389]
    DIRECTION OUTPUT ;
    USE SIGNAL ;
    PORT
      LAYER M4 ;
        RECT  0 150.384 0.192 150.408 ;
    END
  END o[389]
  PIN o[38]
    DIRECTION OUTPUT ;
    USE SIGNAL ;
    PORT
      LAYER M4 ;
        RECT  0 93.696 0.192 93.72 ;
    END
  END o[38]
  PIN o[390]
    DIRECTION OUTPUT ;
    USE SIGNAL ;
    PORT
      LAYER M4 ;
        RECT  0 150.528 0.192 150.552 ;
    END
  END o[390]
  PIN o[391]
    DIRECTION OUTPUT ;
    USE SIGNAL ;
    PORT
      LAYER M4 ;
        RECT  0 150.72 0.192 150.744 ;
    END
  END o[391]
  PIN o[392]
    DIRECTION OUTPUT ;
    USE SIGNAL ;
    PORT
      LAYER M4 ;
        RECT  0 150.864 0.192 150.888 ;
    END
  END o[392]
  PIN o[393]
    DIRECTION OUTPUT ;
    USE SIGNAL ;
    PORT
      LAYER M4 ;
        RECT  0 151.056 0.192 151.08 ;
    END
  END o[393]
  PIN o[394]
    DIRECTION OUTPUT ;
    USE SIGNAL ;
    PORT
      LAYER M4 ;
        RECT  0 151.2 0.192 151.224 ;
    END
  END o[394]
  PIN o[395]
    DIRECTION OUTPUT ;
    USE SIGNAL ;
    PORT
      LAYER M4 ;
        RECT  0 151.344 0.192 151.368 ;
    END
  END o[395]
  PIN o[396]
    DIRECTION OUTPUT ;
    USE SIGNAL ;
    PORT
      LAYER M4 ;
        RECT  0 151.536 0.192 151.56 ;
    END
  END o[396]
  PIN o[397]
    DIRECTION OUTPUT ;
    USE SIGNAL ;
    PORT
      LAYER M4 ;
        RECT  0 151.68 0.192 151.704 ;
    END
  END o[397]
  PIN o[398]
    DIRECTION OUTPUT ;
    USE SIGNAL ;
    PORT
      LAYER M4 ;
        RECT  0 151.824 0.192 151.848 ;
    END
  END o[398]
  PIN o[399]
    DIRECTION OUTPUT ;
    USE SIGNAL ;
    PORT
      LAYER M4 ;
        RECT  0 152.016 0.192 152.04 ;
    END
  END o[399]
  PIN o[39]
    DIRECTION OUTPUT ;
    USE SIGNAL ;
    PORT
      LAYER M4 ;
        RECT  0 93.888 0.192 93.912 ;
    END
  END o[39]
  PIN o[3]
    DIRECTION OUTPUT ;
    USE SIGNAL ;
    PORT
      LAYER M4 ;
        RECT  0 88.08 0.192 88.104 ;
    END
  END o[3]
  PIN o[400]
    DIRECTION OUTPUT ;
    USE SIGNAL ;
    PORT
      LAYER M4 ;
        RECT  0 152.16 0.192 152.184 ;
    END
  END o[400]
  PIN o[401]
    DIRECTION OUTPUT ;
    USE SIGNAL ;
    PORT
      LAYER M4 ;
        RECT  0 152.304 0.192 152.328 ;
    END
  END o[401]
  PIN o[402]
    DIRECTION OUTPUT ;
    USE SIGNAL ;
    PORT
      LAYER M4 ;
        RECT  0 152.496 0.192 152.52 ;
    END
  END o[402]
  PIN o[403]
    DIRECTION OUTPUT ;
    USE SIGNAL ;
    PORT
      LAYER M4 ;
        RECT  0 152.64 0.192 152.664 ;
    END
  END o[403]
  PIN o[404]
    DIRECTION OUTPUT ;
    USE SIGNAL ;
    PORT
      LAYER M4 ;
        RECT  0 152.832 0.192 152.856 ;
    END
  END o[404]
  PIN o[405]
    DIRECTION OUTPUT ;
    USE SIGNAL ;
    PORT
      LAYER M4 ;
        RECT  0 152.976 0.192 153 ;
    END
  END o[405]
  PIN o[406]
    DIRECTION OUTPUT ;
    USE SIGNAL ;
    PORT
      LAYER M4 ;
        RECT  0 153.12 0.192 153.144 ;
    END
  END o[406]
  PIN o[407]
    DIRECTION OUTPUT ;
    USE SIGNAL ;
    PORT
      LAYER M4 ;
        RECT  0 153.312 0.192 153.336 ;
    END
  END o[407]
  PIN o[408]
    DIRECTION OUTPUT ;
    USE SIGNAL ;
    PORT
      LAYER M4 ;
        RECT  0 153.456 0.192 153.48 ;
    END
  END o[408]
  PIN o[409]
    DIRECTION OUTPUT ;
    USE SIGNAL ;
    PORT
      LAYER M4 ;
        RECT  0 153.6 0.192 153.624 ;
    END
  END o[409]
  PIN o[40]
    DIRECTION OUTPUT ;
    USE SIGNAL ;
    PORT
      LAYER M4 ;
        RECT  0 94.032 0.192 94.056 ;
    END
  END o[40]
  PIN o[410]
    DIRECTION OUTPUT ;
    USE SIGNAL ;
    PORT
      LAYER M4 ;
        RECT  0 153.792 0.192 153.816 ;
    END
  END o[410]
  PIN o[411]
    DIRECTION OUTPUT ;
    USE SIGNAL ;
    PORT
      LAYER M4 ;
        RECT  0 153.936 0.192 153.96 ;
    END
  END o[411]
  PIN o[412]
    DIRECTION OUTPUT ;
    USE SIGNAL ;
    PORT
      LAYER M4 ;
        RECT  0 154.08 0.192 154.104 ;
    END
  END o[412]
  PIN o[413]
    DIRECTION OUTPUT ;
    USE SIGNAL ;
    PORT
      LAYER M4 ;
        RECT  0 154.272 0.192 154.296 ;
    END
  END o[413]
  PIN o[414]
    DIRECTION OUTPUT ;
    USE SIGNAL ;
    PORT
      LAYER M4 ;
        RECT  0 154.416 0.192 154.44 ;
    END
  END o[414]
  PIN o[415]
    DIRECTION OUTPUT ;
    USE SIGNAL ;
    PORT
      LAYER M4 ;
        RECT  0 154.608 0.192 154.632 ;
    END
  END o[415]
  PIN o[416]
    DIRECTION OUTPUT ;
    USE SIGNAL ;
    PORT
      LAYER M4 ;
        RECT  0 154.752 0.192 154.776 ;
    END
  END o[416]
  PIN o[417]
    DIRECTION OUTPUT ;
    USE SIGNAL ;
    PORT
      LAYER M4 ;
        RECT  0 154.896 0.192 154.92 ;
    END
  END o[417]
  PIN o[418]
    DIRECTION OUTPUT ;
    USE SIGNAL ;
    PORT
      LAYER M4 ;
        RECT  0 155.088 0.192 155.112 ;
    END
  END o[418]
  PIN o[419]
    DIRECTION OUTPUT ;
    USE SIGNAL ;
    PORT
      LAYER M4 ;
        RECT  0 155.232 0.192 155.256 ;
    END
  END o[419]
  PIN o[41]
    DIRECTION OUTPUT ;
    USE SIGNAL ;
    PORT
      LAYER M4 ;
        RECT  0 94.176 0.192 94.2 ;
    END
  END o[41]
  PIN o[420]
    DIRECTION OUTPUT ;
    USE SIGNAL ;
    PORT
      LAYER M4 ;
        RECT  0 155.376 0.192 155.4 ;
    END
  END o[420]
  PIN o[421]
    DIRECTION OUTPUT ;
    USE SIGNAL ;
    PORT
      LAYER M4 ;
        RECT  0 155.568 0.192 155.592 ;
    END
  END o[421]
  PIN o[422]
    DIRECTION OUTPUT ;
    USE SIGNAL ;
    PORT
      LAYER M4 ;
        RECT  0 155.712 0.192 155.736 ;
    END
  END o[422]
  PIN o[423]
    DIRECTION OUTPUT ;
    USE SIGNAL ;
    PORT
      LAYER M4 ;
        RECT  0 155.856 0.192 155.88 ;
    END
  END o[423]
  PIN o[424]
    DIRECTION OUTPUT ;
    USE SIGNAL ;
    PORT
      LAYER M4 ;
        RECT  0 156.048 0.192 156.072 ;
    END
  END o[424]
  PIN o[425]
    DIRECTION OUTPUT ;
    USE SIGNAL ;
    PORT
      LAYER M4 ;
        RECT  0 156.192 0.192 156.216 ;
    END
  END o[425]
  PIN o[426]
    DIRECTION OUTPUT ;
    USE SIGNAL ;
    PORT
      LAYER M4 ;
        RECT  0 156.384 0.192 156.408 ;
    END
  END o[426]
  PIN o[427]
    DIRECTION OUTPUT ;
    USE SIGNAL ;
    PORT
      LAYER M4 ;
        RECT  0 156.528 0.192 156.552 ;
    END
  END o[427]
  PIN o[428]
    DIRECTION OUTPUT ;
    USE SIGNAL ;
    PORT
      LAYER M4 ;
        RECT  0 156.672 0.192 156.696 ;
    END
  END o[428]
  PIN o[429]
    DIRECTION OUTPUT ;
    USE SIGNAL ;
    PORT
      LAYER M4 ;
        RECT  0 156.864 0.192 156.888 ;
    END
  END o[429]
  PIN o[42]
    DIRECTION OUTPUT ;
    USE SIGNAL ;
    PORT
      LAYER M4 ;
        RECT  0 94.368 0.192 94.392 ;
    END
  END o[42]
  PIN o[430]
    DIRECTION OUTPUT ;
    USE SIGNAL ;
    PORT
      LAYER M4 ;
        RECT  0 157.008 0.192 157.032 ;
    END
  END o[430]
  PIN o[431]
    DIRECTION OUTPUT ;
    USE SIGNAL ;
    PORT
      LAYER M4 ;
        RECT  0 157.152 0.192 157.176 ;
    END
  END o[431]
  PIN o[432]
    DIRECTION OUTPUT ;
    USE SIGNAL ;
    PORT
      LAYER M4 ;
        RECT  0 157.344 0.192 157.368 ;
    END
  END o[432]
  PIN o[433]
    DIRECTION OUTPUT ;
    USE SIGNAL ;
    PORT
      LAYER M4 ;
        RECT  0 157.488 0.192 157.512 ;
    END
  END o[433]
  PIN o[434]
    DIRECTION OUTPUT ;
    USE SIGNAL ;
    PORT
      LAYER M4 ;
        RECT  0 157.632 0.192 157.656 ;
    END
  END o[434]
  PIN o[435]
    DIRECTION OUTPUT ;
    USE SIGNAL ;
    PORT
      LAYER M4 ;
        RECT  0 157.824 0.192 157.848 ;
    END
  END o[435]
  PIN o[436]
    DIRECTION OUTPUT ;
    USE SIGNAL ;
    PORT
      LAYER M4 ;
        RECT  0 157.968 0.192 157.992 ;
    END
  END o[436]
  PIN o[437]
    DIRECTION OUTPUT ;
    USE SIGNAL ;
    PORT
      LAYER M4 ;
        RECT  0 158.16 0.192 158.184 ;
    END
  END o[437]
  PIN o[438]
    DIRECTION OUTPUT ;
    USE SIGNAL ;
    PORT
      LAYER M4 ;
        RECT  0 158.304 0.192 158.328 ;
    END
  END o[438]
  PIN o[439]
    DIRECTION OUTPUT ;
    USE SIGNAL ;
    PORT
      LAYER M4 ;
        RECT  0 158.448 0.192 158.472 ;
    END
  END o[439]
  PIN o[43]
    DIRECTION OUTPUT ;
    USE SIGNAL ;
    PORT
      LAYER M4 ;
        RECT  0 94.512 0.192 94.536 ;
    END
  END o[43]
  PIN o[440]
    DIRECTION OUTPUT ;
    USE SIGNAL ;
    PORT
      LAYER M4 ;
        RECT  0 158.64 0.192 158.664 ;
    END
  END o[440]
  PIN o[441]
    DIRECTION OUTPUT ;
    USE SIGNAL ;
    PORT
      LAYER M4 ;
        RECT  0 158.784 0.192 158.808 ;
    END
  END o[441]
  PIN o[442]
    DIRECTION OUTPUT ;
    USE SIGNAL ;
    PORT
      LAYER M4 ;
        RECT  0 158.928 0.192 158.952 ;
    END
  END o[442]
  PIN o[443]
    DIRECTION OUTPUT ;
    USE SIGNAL ;
    PORT
      LAYER M4 ;
        RECT  0 159.12 0.192 159.144 ;
    END
  END o[443]
  PIN o[444]
    DIRECTION OUTPUT ;
    USE SIGNAL ;
    PORT
      LAYER M4 ;
        RECT  0 159.264 0.192 159.288 ;
    END
  END o[444]
  PIN o[445]
    DIRECTION OUTPUT ;
    USE SIGNAL ;
    PORT
      LAYER M4 ;
        RECT  0 159.408 0.192 159.432 ;
    END
  END o[445]
  PIN o[446]
    DIRECTION OUTPUT ;
    USE SIGNAL ;
    PORT
      LAYER M4 ;
        RECT  0 159.6 0.192 159.624 ;
    END
  END o[446]
  PIN o[447]
    DIRECTION OUTPUT ;
    USE SIGNAL ;
    PORT
      LAYER M4 ;
        RECT  0 159.744 0.192 159.768 ;
    END
  END o[447]
  PIN o[448]
    DIRECTION OUTPUT ;
    USE SIGNAL ;
    PORT
      LAYER M4 ;
        RECT  0 159.936 0.192 159.96 ;
    END
  END o[448]
  PIN o[449]
    DIRECTION OUTPUT ;
    USE SIGNAL ;
    PORT
      LAYER M4 ;
        RECT  0 160.08 0.192 160.104 ;
    END
  END o[449]
  PIN o[44]
    DIRECTION OUTPUT ;
    USE SIGNAL ;
    PORT
      LAYER M4 ;
        RECT  0 94.656 0.192 94.68 ;
    END
  END o[44]
  PIN o[450]
    DIRECTION OUTPUT ;
    USE SIGNAL ;
    PORT
      LAYER M4 ;
        RECT  0 160.224 0.192 160.248 ;
    END
  END o[450]
  PIN o[451]
    DIRECTION OUTPUT ;
    USE SIGNAL ;
    PORT
      LAYER M4 ;
        RECT  0 160.416 0.192 160.44 ;
    END
  END o[451]
  PIN o[452]
    DIRECTION OUTPUT ;
    USE SIGNAL ;
    PORT
      LAYER M4 ;
        RECT  0 160.56 0.192 160.584 ;
    END
  END o[452]
  PIN o[453]
    DIRECTION OUTPUT ;
    USE SIGNAL ;
    PORT
      LAYER M4 ;
        RECT  0 160.704 0.192 160.728 ;
    END
  END o[453]
  PIN o[454]
    DIRECTION OUTPUT ;
    USE SIGNAL ;
    PORT
      LAYER M4 ;
        RECT  0 160.896 0.192 160.92 ;
    END
  END o[454]
  PIN o[455]
    DIRECTION OUTPUT ;
    USE SIGNAL ;
    PORT
      LAYER M4 ;
        RECT  0 161.04 0.192 161.064 ;
    END
  END o[455]
  PIN o[456]
    DIRECTION OUTPUT ;
    USE SIGNAL ;
    PORT
      LAYER M4 ;
        RECT  0 161.184 0.192 161.208 ;
    END
  END o[456]
  PIN o[457]
    DIRECTION OUTPUT ;
    USE SIGNAL ;
    PORT
      LAYER M4 ;
        RECT  0 161.376 0.192 161.4 ;
    END
  END o[457]
  PIN o[458]
    DIRECTION OUTPUT ;
    USE SIGNAL ;
    PORT
      LAYER M4 ;
        RECT  0 161.52 0.192 161.544 ;
    END
  END o[458]
  PIN o[459]
    DIRECTION OUTPUT ;
    USE SIGNAL ;
    PORT
      LAYER M4 ;
        RECT  0 161.712 0.192 161.736 ;
    END
  END o[459]
  PIN o[45]
    DIRECTION OUTPUT ;
    USE SIGNAL ;
    PORT
      LAYER M4 ;
        RECT  0 94.848 0.192 94.872 ;
    END
  END o[45]
  PIN o[460]
    DIRECTION OUTPUT ;
    USE SIGNAL ;
    PORT
      LAYER M4 ;
        RECT  0 161.856 0.192 161.88 ;
    END
  END o[460]
  PIN o[461]
    DIRECTION OUTPUT ;
    USE SIGNAL ;
    PORT
      LAYER M4 ;
        RECT  0 162 0.192 162.024 ;
    END
  END o[461]
  PIN o[462]
    DIRECTION OUTPUT ;
    USE SIGNAL ;
    PORT
      LAYER M4 ;
        RECT  0 162.192 0.192 162.216 ;
    END
  END o[462]
  PIN o[463]
    DIRECTION OUTPUT ;
    USE SIGNAL ;
    PORT
      LAYER M4 ;
        RECT  0 162.336 0.192 162.36 ;
    END
  END o[463]
  PIN o[464]
    DIRECTION OUTPUT ;
    USE SIGNAL ;
    PORT
      LAYER M4 ;
        RECT  0 162.48 0.192 162.504 ;
    END
  END o[464]
  PIN o[465]
    DIRECTION OUTPUT ;
    USE SIGNAL ;
    PORT
      LAYER M4 ;
        RECT  0 162.672 0.192 162.696 ;
    END
  END o[465]
  PIN o[466]
    DIRECTION OUTPUT ;
    USE SIGNAL ;
    PORT
      LAYER M4 ;
        RECT  0 162.816 0.192 162.84 ;
    END
  END o[466]
  PIN o[467]
    DIRECTION OUTPUT ;
    USE SIGNAL ;
    PORT
      LAYER M4 ;
        RECT  0 162.96 0.192 162.984 ;
    END
  END o[467]
  PIN o[468]
    DIRECTION OUTPUT ;
    USE SIGNAL ;
    PORT
      LAYER M4 ;
        RECT  0 163.152 0.192 163.176 ;
    END
  END o[468]
  PIN o[469]
    DIRECTION OUTPUT ;
    USE SIGNAL ;
    PORT
      LAYER M4 ;
        RECT  0 163.296 0.192 163.32 ;
    END
  END o[469]
  PIN o[46]
    DIRECTION OUTPUT ;
    USE SIGNAL ;
    PORT
      LAYER M4 ;
        RECT  0 94.992 0.192 95.016 ;
    END
  END o[46]
  PIN o[470]
    DIRECTION OUTPUT ;
    USE SIGNAL ;
    PORT
      LAYER M4 ;
        RECT  0 163.488 0.192 163.512 ;
    END
  END o[470]
  PIN o[471]
    DIRECTION OUTPUT ;
    USE SIGNAL ;
    PORT
      LAYER M4 ;
        RECT  0 163.632 0.192 163.656 ;
    END
  END o[471]
  PIN o[472]
    DIRECTION OUTPUT ;
    USE SIGNAL ;
    PORT
      LAYER M4 ;
        RECT  0 163.776 0.192 163.8 ;
    END
  END o[472]
  PIN o[473]
    DIRECTION OUTPUT ;
    USE SIGNAL ;
    PORT
      LAYER M4 ;
        RECT  0 163.968 0.192 163.992 ;
    END
  END o[473]
  PIN o[474]
    DIRECTION OUTPUT ;
    USE SIGNAL ;
    PORT
      LAYER M4 ;
        RECT  0 164.112 0.192 164.136 ;
    END
  END o[474]
  PIN o[475]
    DIRECTION OUTPUT ;
    USE SIGNAL ;
    PORT
      LAYER M4 ;
        RECT  0 164.256 0.192 164.28 ;
    END
  END o[475]
  PIN o[476]
    DIRECTION OUTPUT ;
    USE SIGNAL ;
    PORT
      LAYER M4 ;
        RECT  0 164.448 0.192 164.472 ;
    END
  END o[476]
  PIN o[477]
    DIRECTION OUTPUT ;
    USE SIGNAL ;
    PORT
      LAYER M4 ;
        RECT  0 164.592 0.192 164.616 ;
    END
  END o[477]
  PIN o[478]
    DIRECTION OUTPUT ;
    USE SIGNAL ;
    PORT
      LAYER M4 ;
        RECT  0 164.736 0.192 164.76 ;
    END
  END o[478]
  PIN o[479]
    DIRECTION OUTPUT ;
    USE SIGNAL ;
    PORT
      LAYER M4 ;
        RECT  0 164.928 0.192 164.952 ;
    END
  END o[479]
  PIN o[47]
    DIRECTION OUTPUT ;
    USE SIGNAL ;
    PORT
      LAYER M4 ;
        RECT  0 95.184 0.192 95.208 ;
    END
  END o[47]
  PIN o[480]
    DIRECTION OUTPUT ;
    USE SIGNAL ;
    PORT
      LAYER M4 ;
        RECT  0 165.072 0.192 165.096 ;
    END
  END o[480]
  PIN o[481]
    DIRECTION OUTPUT ;
    USE SIGNAL ;
    PORT
      LAYER M4 ;
        RECT  0 165.264 0.192 165.288 ;
    END
  END o[481]
  PIN o[482]
    DIRECTION OUTPUT ;
    USE SIGNAL ;
    PORT
      LAYER M4 ;
        RECT  0 165.408 0.192 165.432 ;
    END
  END o[482]
  PIN o[483]
    DIRECTION OUTPUT ;
    USE SIGNAL ;
    PORT
      LAYER M4 ;
        RECT  0 165.552 0.192 165.576 ;
    END
  END o[483]
  PIN o[484]
    DIRECTION OUTPUT ;
    USE SIGNAL ;
    PORT
      LAYER M4 ;
        RECT  0 165.744 0.192 165.768 ;
    END
  END o[484]
  PIN o[485]
    DIRECTION OUTPUT ;
    USE SIGNAL ;
    PORT
      LAYER M4 ;
        RECT  0 165.888 0.192 165.912 ;
    END
  END o[485]
  PIN o[486]
    DIRECTION OUTPUT ;
    USE SIGNAL ;
    PORT
      LAYER M4 ;
        RECT  0 166.032 0.192 166.056 ;
    END
  END o[486]
  PIN o[487]
    DIRECTION OUTPUT ;
    USE SIGNAL ;
    PORT
      LAYER M4 ;
        RECT  0 166.224 0.192 166.248 ;
    END
  END o[487]
  PIN o[488]
    DIRECTION OUTPUT ;
    USE SIGNAL ;
    PORT
      LAYER M4 ;
        RECT  0 166.368 0.192 166.392 ;
    END
  END o[488]
  PIN o[489]
    DIRECTION OUTPUT ;
    USE SIGNAL ;
    PORT
      LAYER M4 ;
        RECT  0 166.512 0.192 166.536 ;
    END
  END o[489]
  PIN o[48]
    DIRECTION OUTPUT ;
    USE SIGNAL ;
    PORT
      LAYER M4 ;
        RECT  0 95.328 0.192 95.352 ;
    END
  END o[48]
  PIN o[490]
    DIRECTION OUTPUT ;
    USE SIGNAL ;
    PORT
      LAYER M4 ;
        RECT  0 166.704 0.192 166.728 ;
    END
  END o[490]
  PIN o[491]
    DIRECTION OUTPUT ;
    USE SIGNAL ;
    PORT
      LAYER M4 ;
        RECT  0 166.848 0.192 166.872 ;
    END
  END o[491]
  PIN o[492]
    DIRECTION OUTPUT ;
    USE SIGNAL ;
    PORT
      LAYER M4 ;
        RECT  0 167.04 0.192 167.064 ;
    END
  END o[492]
  PIN o[493]
    DIRECTION OUTPUT ;
    USE SIGNAL ;
    PORT
      LAYER M4 ;
        RECT  0 167.184 0.192 167.208 ;
    END
  END o[493]
  PIN o[494]
    DIRECTION OUTPUT ;
    USE SIGNAL ;
    PORT
      LAYER M4 ;
        RECT  0 167.328 0.192 167.352 ;
    END
  END o[494]
  PIN o[495]
    DIRECTION OUTPUT ;
    USE SIGNAL ;
    PORT
      LAYER M4 ;
        RECT  0 167.52 0.192 167.544 ;
    END
  END o[495]
  PIN o[496]
    DIRECTION OUTPUT ;
    USE SIGNAL ;
    PORT
      LAYER M4 ;
        RECT  0 167.664 0.192 167.688 ;
    END
  END o[496]
  PIN o[497]
    DIRECTION OUTPUT ;
    USE SIGNAL ;
    PORT
      LAYER M4 ;
        RECT  0 167.808 0.192 167.832 ;
    END
  END o[497]
  PIN o[498]
    DIRECTION OUTPUT ;
    USE SIGNAL ;
    PORT
      LAYER M4 ;
        RECT  0 168 0.192 168.024 ;
    END
  END o[498]
  PIN o[499]
    DIRECTION OUTPUT ;
    USE SIGNAL ;
    PORT
      LAYER M4 ;
        RECT  0 168.144 0.192 168.168 ;
    END
  END o[499]
  PIN o[49]
    DIRECTION OUTPUT ;
    USE SIGNAL ;
    PORT
      LAYER M4 ;
        RECT  0 95.472 0.192 95.496 ;
    END
  END o[49]
  PIN o[4]
    DIRECTION OUTPUT ;
    USE SIGNAL ;
    PORT
      LAYER M4 ;
        RECT  0 88.224 0.192 88.248 ;
    END
  END o[4]
  PIN o[500]
    DIRECTION OUTPUT ;
    USE SIGNAL ;
    PORT
      LAYER M4 ;
        RECT  0 168.288 0.192 168.312 ;
    END
  END o[500]
  PIN o[501]
    DIRECTION OUTPUT ;
    USE SIGNAL ;
    PORT
      LAYER M4 ;
        RECT  0 168.48 0.192 168.504 ;
    END
  END o[501]
  PIN o[502]
    DIRECTION OUTPUT ;
    USE SIGNAL ;
    PORT
      LAYER M4 ;
        RECT  0 168.624 0.192 168.648 ;
    END
  END o[502]
  PIN o[503]
    DIRECTION OUTPUT ;
    USE SIGNAL ;
    PORT
      LAYER M4 ;
        RECT  0 168.816 0.192 168.84 ;
    END
  END o[503]
  PIN o[504]
    DIRECTION OUTPUT ;
    USE SIGNAL ;
    PORT
      LAYER M4 ;
        RECT  0 168.96 0.192 168.984 ;
    END
  END o[504]
  PIN o[505]
    DIRECTION OUTPUT ;
    USE SIGNAL ;
    PORT
      LAYER M4 ;
        RECT  0 169.104 0.192 169.128 ;
    END
  END o[505]
  PIN o[506]
    DIRECTION OUTPUT ;
    USE SIGNAL ;
    PORT
      LAYER M4 ;
        RECT  0 169.296 0.192 169.32 ;
    END
  END o[506]
  PIN o[507]
    DIRECTION OUTPUT ;
    USE SIGNAL ;
    PORT
      LAYER M4 ;
        RECT  0 169.44 0.192 169.464 ;
    END
  END o[507]
  PIN o[508]
    DIRECTION OUTPUT ;
    USE SIGNAL ;
    PORT
      LAYER M4 ;
        RECT  0 169.584 0.192 169.608 ;
    END
  END o[508]
  PIN o[509]
    DIRECTION OUTPUT ;
    USE SIGNAL ;
    PORT
      LAYER M4 ;
        RECT  0 169.776 0.192 169.8 ;
    END
  END o[509]
  PIN o[50]
    DIRECTION OUTPUT ;
    USE SIGNAL ;
    PORT
      LAYER M4 ;
        RECT  0 95.664 0.192 95.688 ;
    END
  END o[50]
  PIN o[510]
    DIRECTION OUTPUT ;
    USE SIGNAL ;
    PORT
      LAYER M4 ;
        RECT  0 169.92 0.192 169.944 ;
    END
  END o[510]
  PIN o[511]
    DIRECTION OUTPUT ;
    USE SIGNAL ;
    PORT
      LAYER M4 ;
        RECT  0 170.064 0.192 170.088 ;
    END
  END o[511]
  PIN o[512]
    DIRECTION OUTPUT ;
    USE SIGNAL ;
    PORT
      LAYER M4 ;
        RECT  0 170.256 0.192 170.28 ;
    END
  END o[512]
  PIN o[513]
    DIRECTION OUTPUT ;
    USE SIGNAL ;
    PORT
      LAYER M4 ;
        RECT  0 170.4 0.192 170.424 ;
    END
  END o[513]
  PIN o[514]
    DIRECTION OUTPUT ;
    USE SIGNAL ;
    PORT
      LAYER M4 ;
        RECT  0 170.592 0.192 170.616 ;
    END
  END o[514]
  PIN o[51]
    DIRECTION OUTPUT ;
    USE SIGNAL ;
    PORT
      LAYER M4 ;
        RECT  0 95.808 0.192 95.832 ;
    END
  END o[51]
  PIN o[52]
    DIRECTION OUTPUT ;
    USE SIGNAL ;
    PORT
      LAYER M4 ;
        RECT  0 95.952 0.192 95.976 ;
    END
  END o[52]
  PIN o[53]
    DIRECTION OUTPUT ;
    USE SIGNAL ;
    PORT
      LAYER M4 ;
        RECT  0 96.144 0.192 96.168 ;
    END
  END o[53]
  PIN o[54]
    DIRECTION OUTPUT ;
    USE SIGNAL ;
    PORT
      LAYER M4 ;
        RECT  0 96.288 0.192 96.312 ;
    END
  END o[54]
  PIN o[55]
    DIRECTION OUTPUT ;
    USE SIGNAL ;
    PORT
      LAYER M4 ;
        RECT  0 96.432 0.192 96.456 ;
    END
  END o[55]
  PIN o[56]
    DIRECTION OUTPUT ;
    USE SIGNAL ;
    PORT
      LAYER M4 ;
        RECT  0 96.624 0.192 96.648 ;
    END
  END o[56]
  PIN o[57]
    DIRECTION OUTPUT ;
    USE SIGNAL ;
    PORT
      LAYER M4 ;
        RECT  0 96.768 0.192 96.792 ;
    END
  END o[57]
  PIN o[58]
    DIRECTION OUTPUT ;
    USE SIGNAL ;
    PORT
      LAYER M4 ;
        RECT  0 96.96 0.192 96.984 ;
    END
  END o[58]
  PIN o[59]
    DIRECTION OUTPUT ;
    USE SIGNAL ;
    PORT
      LAYER M4 ;
        RECT  0 97.104 0.192 97.128 ;
    END
  END o[59]
  PIN o[5]
    DIRECTION OUTPUT ;
    USE SIGNAL ;
    PORT
      LAYER M4 ;
        RECT  0 88.368 0.192 88.392 ;
    END
  END o[5]
  PIN o[60]
    DIRECTION OUTPUT ;
    USE SIGNAL ;
    PORT
      LAYER M4 ;
        RECT  0 97.248 0.192 97.272 ;
    END
  END o[60]
  PIN o[61]
    DIRECTION OUTPUT ;
    USE SIGNAL ;
    PORT
      LAYER M4 ;
        RECT  0 97.44 0.192 97.464 ;
    END
  END o[61]
  PIN o[62]
    DIRECTION OUTPUT ;
    USE SIGNAL ;
    PORT
      LAYER M4 ;
        RECT  0 97.584 0.192 97.608 ;
    END
  END o[62]
  PIN o[63]
    DIRECTION OUTPUT ;
    USE SIGNAL ;
    PORT
      LAYER M4 ;
        RECT  0 97.728 0.192 97.752 ;
    END
  END o[63]
  PIN o[64]
    DIRECTION OUTPUT ;
    USE SIGNAL ;
    PORT
      LAYER M4 ;
        RECT  0 97.92 0.192 97.944 ;
    END
  END o[64]
  PIN o[65]
    DIRECTION OUTPUT ;
    USE SIGNAL ;
    PORT
      LAYER M4 ;
        RECT  0 98.064 0.192 98.088 ;
    END
  END o[65]
  PIN o[66]
    DIRECTION OUTPUT ;
    USE SIGNAL ;
    PORT
      LAYER M4 ;
        RECT  0 98.208 0.192 98.232 ;
    END
  END o[66]
  PIN o[67]
    DIRECTION OUTPUT ;
    USE SIGNAL ;
    PORT
      LAYER M4 ;
        RECT  0 98.4 0.192 98.424 ;
    END
  END o[67]
  PIN o[68]
    DIRECTION OUTPUT ;
    USE SIGNAL ;
    PORT
      LAYER M4 ;
        RECT  0 98.544 0.192 98.568 ;
    END
  END o[68]
  PIN o[69]
    DIRECTION OUTPUT ;
    USE SIGNAL ;
    PORT
      LAYER M4 ;
        RECT  0 98.736 0.192 98.76 ;
    END
  END o[69]
  PIN o[6]
    DIRECTION OUTPUT ;
    USE SIGNAL ;
    PORT
      LAYER M4 ;
        RECT  0 88.56 0.192 88.584 ;
    END
  END o[6]
  PIN o[70]
    DIRECTION OUTPUT ;
    USE SIGNAL ;
    PORT
      LAYER M4 ;
        RECT  0 98.88 0.192 98.904 ;
    END
  END o[70]
  PIN o[71]
    DIRECTION OUTPUT ;
    USE SIGNAL ;
    PORT
      LAYER M4 ;
        RECT  0 99.024 0.192 99.048 ;
    END
  END o[71]
  PIN o[72]
    DIRECTION OUTPUT ;
    USE SIGNAL ;
    PORT
      LAYER M4 ;
        RECT  0 99.216 0.192 99.24 ;
    END
  END o[72]
  PIN o[73]
    DIRECTION OUTPUT ;
    USE SIGNAL ;
    PORT
      LAYER M4 ;
        RECT  0 99.36 0.192 99.384 ;
    END
  END o[73]
  PIN o[74]
    DIRECTION OUTPUT ;
    USE SIGNAL ;
    PORT
      LAYER M4 ;
        RECT  0 99.504 0.192 99.528 ;
    END
  END o[74]
  PIN o[75]
    DIRECTION OUTPUT ;
    USE SIGNAL ;
    PORT
      LAYER M4 ;
        RECT  0 99.696 0.192 99.72 ;
    END
  END o[75]
  PIN o[76]
    DIRECTION OUTPUT ;
    USE SIGNAL ;
    PORT
      LAYER M4 ;
        RECT  0 99.84 0.192 99.864 ;
    END
  END o[76]
  PIN o[77]
    DIRECTION OUTPUT ;
    USE SIGNAL ;
    PORT
      LAYER M4 ;
        RECT  0 99.984 0.192 100.008 ;
    END
  END o[77]
  PIN o[78]
    DIRECTION OUTPUT ;
    USE SIGNAL ;
    PORT
      LAYER M4 ;
        RECT  0 100.176 0.192 100.2 ;
    END
  END o[78]
  PIN o[79]
    DIRECTION OUTPUT ;
    USE SIGNAL ;
    PORT
      LAYER M4 ;
        RECT  0 100.32 0.192 100.344 ;
    END
  END o[79]
  PIN o[7]
    DIRECTION OUTPUT ;
    USE SIGNAL ;
    PORT
      LAYER M4 ;
        RECT  0 88.704 0.192 88.728 ;
    END
  END o[7]
  PIN o[80]
    DIRECTION OUTPUT ;
    USE SIGNAL ;
    PORT
      LAYER M4 ;
        RECT  0 100.512 0.192 100.536 ;
    END
  END o[80]
  PIN o[81]
    DIRECTION OUTPUT ;
    USE SIGNAL ;
    PORT
      LAYER M4 ;
        RECT  0 100.656 0.192 100.68 ;
    END
  END o[81]
  PIN o[82]
    DIRECTION OUTPUT ;
    USE SIGNAL ;
    PORT
      LAYER M4 ;
        RECT  0 100.8 0.192 100.824 ;
    END
  END o[82]
  PIN o[83]
    DIRECTION OUTPUT ;
    USE SIGNAL ;
    PORT
      LAYER M4 ;
        RECT  0 100.992 0.192 101.016 ;
    END
  END o[83]
  PIN o[84]
    DIRECTION OUTPUT ;
    USE SIGNAL ;
    PORT
      LAYER M4 ;
        RECT  0 101.136 0.192 101.16 ;
    END
  END o[84]
  PIN o[85]
    DIRECTION OUTPUT ;
    USE SIGNAL ;
    PORT
      LAYER M4 ;
        RECT  0 101.28 0.192 101.304 ;
    END
  END o[85]
  PIN o[86]
    DIRECTION OUTPUT ;
    USE SIGNAL ;
    PORT
      LAYER M4 ;
        RECT  0 101.472 0.192 101.496 ;
    END
  END o[86]
  PIN o[87]
    DIRECTION OUTPUT ;
    USE SIGNAL ;
    PORT
      LAYER M4 ;
        RECT  0 101.616 0.192 101.64 ;
    END
  END o[87]
  PIN o[88]
    DIRECTION OUTPUT ;
    USE SIGNAL ;
    PORT
      LAYER M4 ;
        RECT  0 101.76 0.192 101.784 ;
    END
  END o[88]
  PIN o[89]
    DIRECTION OUTPUT ;
    USE SIGNAL ;
    PORT
      LAYER M4 ;
        RECT  0 101.952 0.192 101.976 ;
    END
  END o[89]
  PIN o[8]
    DIRECTION OUTPUT ;
    USE SIGNAL ;
    PORT
      LAYER M4 ;
        RECT  0 88.848 0.192 88.872 ;
    END
  END o[8]
  PIN o[90]
    DIRECTION OUTPUT ;
    USE SIGNAL ;
    PORT
      LAYER M4 ;
        RECT  0 102.096 0.192 102.12 ;
    END
  END o[90]
  PIN o[91]
    DIRECTION OUTPUT ;
    USE SIGNAL ;
    PORT
      LAYER M4 ;
        RECT  0 102.288 0.192 102.312 ;
    END
  END o[91]
  PIN o[92]
    DIRECTION OUTPUT ;
    USE SIGNAL ;
    PORT
      LAYER M4 ;
        RECT  0 102.432 0.192 102.456 ;
    END
  END o[92]
  PIN o[93]
    DIRECTION OUTPUT ;
    USE SIGNAL ;
    PORT
      LAYER M4 ;
        RECT  0 102.576 0.192 102.6 ;
    END
  END o[93]
  PIN o[94]
    DIRECTION OUTPUT ;
    USE SIGNAL ;
    PORT
      LAYER M4 ;
        RECT  0 102.768 0.192 102.792 ;
    END
  END o[94]
  PIN o[95]
    DIRECTION OUTPUT ;
    USE SIGNAL ;
    PORT
      LAYER M4 ;
        RECT  0 102.912 0.192 102.936 ;
    END
  END o[95]
  PIN o[96]
    DIRECTION OUTPUT ;
    USE SIGNAL ;
    PORT
      LAYER M4 ;
        RECT  0 103.056 0.192 103.08 ;
    END
  END o[96]
  PIN o[97]
    DIRECTION OUTPUT ;
    USE SIGNAL ;
    PORT
      LAYER M4 ;
        RECT  0 103.248 0.192 103.272 ;
    END
  END o[97]
  PIN o[98]
    DIRECTION OUTPUT ;
    USE SIGNAL ;
    PORT
      LAYER M4 ;
        RECT  0 103.392 0.192 103.416 ;
    END
  END o[98]
  PIN o[99]
    DIRECTION OUTPUT ;
    USE SIGNAL ;
    PORT
      LAYER M4 ;
        RECT  0 103.536 0.192 103.56 ;
    END
  END o[99]
  PIN o[9]
    DIRECTION OUTPUT ;
    USE SIGNAL ;
    PORT
      LAYER M4 ;
        RECT  0 89.04 0.192 89.064 ;
    END
  END o[9]
  PIN rs[0]
    DIRECTION INPUT ;
    USE SIGNAL ;
    PORT
      LAYER M5 ;
        RECT  95.04 0 95.064 0.192 ;
    END
    PORT
      LAYER M5 ;
        RECT  94.8 0.144 95.064 0.227 ;
    END
  END rs[0]
  PIN VDD
    DIRECTION INOUT ;
    USE POWER ;
    PORT
      LAYER M5 ;
        RECT  126.792 2.151 126.912 172.809 ;
        RECT  124.092 2.151 124.212 172.809 ;
        RECT  121.392 2.151 121.512 172.809 ;
        RECT  118.692 2.151 118.812 172.809 ;
        RECT  115.992 2.151 116.112 172.809 ;
        RECT  113.292 2.151 113.412 172.809 ;
        RECT  110.592 2.151 110.712 172.809 ;
        RECT  107.892 2.151 108.012 172.809 ;
        RECT  105.192 2.151 105.312 172.809 ;
        RECT  102.492 2.151 102.612 172.809 ;
        RECT  99.792 2.151 99.912 172.809 ;
        RECT  97.092 2.151 97.212 172.809 ;
        RECT  94.392 2.151 94.512 172.809 ;
        RECT  91.692 2.151 91.812 172.809 ;
        RECT  88.992 2.151 89.112 172.809 ;
        RECT  86.292 2.151 86.412 172.809 ;
        RECT  83.592 2.151 83.712 172.809 ;
        RECT  80.892 2.151 81.012 172.809 ;
        RECT  78.192 2.151 78.312 172.809 ;
        RECT  75.492 2.151 75.612 172.809 ;
        RECT  72.792 2.151 72.912 172.809 ;
        RECT  70.092 2.151 70.212 172.809 ;
        RECT  67.392 2.151 67.512 172.809 ;
        RECT  64.692 2.151 64.812 172.809 ;
        RECT  61.992 2.151 62.112 172.809 ;
        RECT  59.292 2.151 59.412 172.809 ;
        RECT  56.592 2.151 56.712 172.809 ;
        RECT  53.892 2.151 54.012 172.809 ;
        RECT  51.192 2.151 51.312 172.809 ;
        RECT  48.492 2.151 48.612 172.809 ;
        RECT  45.792 2.151 45.912 172.809 ;
        RECT  43.092 2.151 43.212 172.809 ;
        RECT  40.392 2.151 40.512 172.809 ;
        RECT  37.692 2.151 37.812 172.809 ;
        RECT  34.992 2.151 35.112 172.809 ;
        RECT  32.292 2.151 32.412 172.809 ;
        RECT  29.592 2.151 29.712 172.809 ;
        RECT  26.892 2.151 27.012 172.809 ;
        RECT  24.192 2.151 24.312 172.809 ;
        RECT  21.492 2.151 21.612 172.809 ;
        RECT  18.792 2.151 18.912 172.809 ;
        RECT  16.092 2.151 16.212 172.809 ;
        RECT  13.392 2.151 13.512 172.809 ;
        RECT  10.692 2.151 10.812 172.809 ;
        RECT  7.992 2.151 8.112 172.809 ;
        RECT  5.292 2.151 5.412 172.809 ;
        RECT  2.592 2.151 2.712 172.809 ;
    END
  END VDD
  PIN VSS
    DIRECTION INOUT ;
    USE GROUND ;
    PORT
      LAYER M5 ;
        RECT  126.6 2.137 126.72 172.823 ;
        RECT  123.9 2.137 124.02 172.823 ;
        RECT  121.2 2.137 121.32 172.823 ;
        RECT  118.5 2.137 118.62 172.823 ;
        RECT  115.8 2.137 115.92 172.823 ;
        RECT  113.1 2.137 113.22 172.823 ;
        RECT  110.4 2.137 110.52 172.823 ;
        RECT  107.7 2.137 107.82 172.823 ;
        RECT  105 2.137 105.12 172.823 ;
        RECT  102.3 2.137 102.42 172.823 ;
        RECT  99.6 2.137 99.72 172.823 ;
        RECT  96.9 2.137 97.02 172.823 ;
        RECT  94.2 2.137 94.32 172.823 ;
        RECT  91.5 2.137 91.62 172.823 ;
        RECT  88.8 2.137 88.92 172.823 ;
        RECT  86.1 2.137 86.22 172.823 ;
        RECT  83.4 2.137 83.52 172.823 ;
        RECT  80.7 2.137 80.82 172.823 ;
        RECT  78 2.137 78.12 172.823 ;
        RECT  75.3 2.137 75.42 172.823 ;
        RECT  72.6 2.137 72.72 172.823 ;
        RECT  69.9 2.137 70.02 172.823 ;
        RECT  67.2 2.137 67.32 172.823 ;
        RECT  64.5 2.137 64.62 172.823 ;
        RECT  61.8 2.137 61.92 172.823 ;
        RECT  59.1 2.137 59.22 172.823 ;
        RECT  56.4 2.137 56.52 172.823 ;
        RECT  53.7 2.137 53.82 172.823 ;
        RECT  51 2.137 51.12 172.823 ;
        RECT  48.3 2.137 48.42 172.823 ;
        RECT  45.6 2.137 45.72 172.823 ;
        RECT  42.9 2.137 43.02 172.823 ;
        RECT  40.2 2.137 40.32 172.823 ;
        RECT  37.5 2.137 37.62 172.823 ;
        RECT  34.8 2.137 34.92 172.823 ;
        RECT  32.1 2.137 32.22 172.823 ;
        RECT  29.4 2.137 29.52 172.823 ;
        RECT  26.7 2.137 26.82 172.823 ;
        RECT  24 2.137 24.12 172.823 ;
        RECT  21.3 2.137 21.42 172.823 ;
        RECT  18.6 2.137 18.72 172.823 ;
        RECT  15.9 2.137 16.02 172.823 ;
        RECT  13.2 2.137 13.32 172.823 ;
        RECT  10.5 2.137 10.62 172.823 ;
        RECT  7.8 2.137 7.92 172.823 ;
        RECT  5.1 2.137 5.22 172.823 ;
        RECT  2.4 2.137 2.52 172.823 ;
    END
  END VSS
  # OT_OBS_CLOSED layer=M5 d_um=1.536 added=448
  OBS
    LAYER RVTN ;
     RECT  2.16 2.16 127.44 2.295 ;
     RECT  2.16 2.565 127.44 2.835 ;
     RECT  2.16 3.105 127.44 3.375 ;
     RECT  2.16 3.645 127.44 3.915 ;
     RECT  2.16 4.185 127.44 4.455 ;
     RECT  2.16 4.725 127.44 4.995 ;
     RECT  2.16 5.265 127.44 5.535 ;
     RECT  2.16 5.805 127.44 6.075 ;
     RECT  2.16 6.345 127.44 6.615 ;
     RECT  2.16 6.885 127.44 7.155 ;
     RECT  2.16 7.425 127.44 7.695 ;
     RECT  2.16 7.965 127.44 8.235 ;
     RECT  2.16 8.505 127.44 8.775 ;
     RECT  2.16 9.045 127.44 9.315 ;
     RECT  2.16 9.585 127.44 9.855 ;
     RECT  2.16 10.125 127.44 10.395 ;
     RECT  2.16 10.665 127.44 10.935 ;
     RECT  2.16 11.205 127.44 11.475 ;
     RECT  2.16 11.745 127.44 12.015 ;
     RECT  2.16 12.285 127.44 12.555 ;
     RECT  2.16 12.825 127.44 13.095 ;
     RECT  2.16 13.365 127.44 13.635 ;
     RECT  2.16 13.905 127.44 14.175 ;
     RECT  2.16 14.445 127.44 14.715 ;
     RECT  2.16 14.985 127.44 15.255 ;
     RECT  2.16 15.525 127.44 15.795 ;
     RECT  2.16 16.065 127.44 16.335 ;
     RECT  2.16 16.605 127.44 16.875 ;
     RECT  2.16 17.145 127.44 17.415 ;
     RECT  2.16 17.685 127.44 17.955 ;
     RECT  2.16 18.225 127.44 18.495 ;
     RECT  2.16 18.765 127.44 19.035 ;
     RECT  2.16 19.305 127.44 19.575 ;
     RECT  2.16 19.845 127.44 20.115 ;
     RECT  2.16 20.385 127.44 20.655 ;
     RECT  2.16 20.925 127.44 21.195 ;
     RECT  2.16 21.465 127.44 21.735 ;
     RECT  2.16 22.005 127.44 22.275 ;
     RECT  2.16 22.545 127.44 22.815 ;
     RECT  2.16 23.085 127.44 23.355 ;
     RECT  2.16 23.625 127.44 23.895 ;
     RECT  2.16 24.165 127.44 24.435 ;
     RECT  2.16 24.705 127.44 24.975 ;
     RECT  2.16 25.245 127.44 25.515 ;
     RECT  2.16 25.785 127.44 26.055 ;
     RECT  2.16 26.325 127.44 26.595 ;
     RECT  2.16 26.865 127.44 27.135 ;
     RECT  2.16 27.405 127.44 27.675 ;
     RECT  2.16 27.945 127.44 28.215 ;
     RECT  2.16 28.485 127.44 28.755 ;
     RECT  2.16 29.025 127.44 29.295 ;
     RECT  2.16 29.565 127.44 29.835 ;
     RECT  2.16 30.105 127.44 30.375 ;
     RECT  2.16 30.645 127.44 30.915 ;
     RECT  2.16 31.185 127.44 31.455 ;
     RECT  2.16 31.725 127.44 31.995 ;
     RECT  2.16 32.265 127.44 32.535 ;
     RECT  2.16 32.805 127.44 33.075 ;
     RECT  2.16 33.345 127.44 33.615 ;
     RECT  2.16 33.885 127.44 34.155 ;
     RECT  2.16 34.425 127.44 34.695 ;
     RECT  2.16 34.965 127.44 35.235 ;
     RECT  2.16 35.505 127.44 35.775 ;
     RECT  2.16 36.045 127.44 36.315 ;
     RECT  2.16 36.585 127.44 36.855 ;
     RECT  2.16 37.125 127.44 37.395 ;
     RECT  2.16 37.665 127.44 37.935 ;
     RECT  2.16 38.205 127.44 38.475 ;
     RECT  2.16 38.745 127.44 39.015 ;
     RECT  2.16 39.285 127.44 39.555 ;
     RECT  2.16 39.825 127.44 40.095 ;
     RECT  2.16 40.365 127.44 40.635 ;
     RECT  2.16 40.905 127.44 41.175 ;
     RECT  2.16 41.445 127.44 41.715 ;
     RECT  2.16 41.985 127.44 42.255 ;
     RECT  2.16 42.525 127.44 42.795 ;
     RECT  2.16 43.065 127.44 43.335 ;
     RECT  2.16 43.605 127.44 43.875 ;
     RECT  2.16 44.145 127.44 44.415 ;
     RECT  2.16 44.685 127.44 44.955 ;
     RECT  2.16 45.225 127.44 45.495 ;
     RECT  2.16 45.765 127.44 46.035 ;
     RECT  2.16 46.305 127.44 46.575 ;
     RECT  2.16 46.845 127.44 47.115 ;
     RECT  2.16 47.385 127.44 47.655 ;
     RECT  2.16 47.925 127.44 48.195 ;
     RECT  2.16 48.465 127.44 48.735 ;
     RECT  2.16 49.005 127.44 49.275 ;
     RECT  2.16 49.545 127.44 49.815 ;
     RECT  2.16 50.085 127.44 50.355 ;
     RECT  2.16 50.625 127.44 50.895 ;
     RECT  2.16 51.165 127.44 51.435 ;
     RECT  2.16 51.705 127.44 51.975 ;
     RECT  2.16 52.245 127.44 52.515 ;
     RECT  2.16 52.785 127.44 53.055 ;
     RECT  2.16 53.325 127.44 53.595 ;
     RECT  2.16 53.865 127.44 54.135 ;
     RECT  2.16 54.405 127.44 54.675 ;
     RECT  2.16 54.945 127.44 55.215 ;
     RECT  2.16 55.485 127.44 55.755 ;
     RECT  2.16 56.025 127.44 56.295 ;
     RECT  2.16 56.565 127.44 56.835 ;
     RECT  2.16 57.105 127.44 57.375 ;
     RECT  2.16 57.645 127.44 57.915 ;
     RECT  2.16 58.185 127.44 58.455 ;
     RECT  2.16 58.725 127.44 58.995 ;
     RECT  2.16 59.265 127.44 59.535 ;
     RECT  2.16 59.805 127.44 60.075 ;
     RECT  2.16 60.345 127.44 60.615 ;
     RECT  2.16 60.885 127.44 61.155 ;
     RECT  2.16 61.425 127.44 61.695 ;
     RECT  2.16 61.965 127.44 62.235 ;
     RECT  2.16 62.505 127.44 62.775 ;
     RECT  2.16 63.045 127.44 63.315 ;
     RECT  2.16 63.585 127.44 63.855 ;
     RECT  2.16 64.125 127.44 64.395 ;
     RECT  2.16 64.665 127.44 64.935 ;
     RECT  2.16 65.205 127.44 65.475 ;
     RECT  2.16 65.745 127.44 66.015 ;
     RECT  2.16 66.285 127.44 66.555 ;
     RECT  2.16 66.825 127.44 67.095 ;
     RECT  2.16 67.365 127.44 67.635 ;
     RECT  2.16 67.905 127.44 68.175 ;
     RECT  2.16 68.445 127.44 68.715 ;
     RECT  2.16 68.985 127.44 69.255 ;
     RECT  2.16 69.525 127.44 69.795 ;
     RECT  2.16 70.065 127.44 70.335 ;
     RECT  2.16 70.605 127.44 70.875 ;
     RECT  2.16 71.145 127.44 71.415 ;
     RECT  2.16 71.685 127.44 71.955 ;
     RECT  2.16 72.225 127.44 72.495 ;
     RECT  2.16 72.765 127.44 73.035 ;
     RECT  2.16 73.305 127.44 73.575 ;
     RECT  2.16 73.845 127.44 74.115 ;
     RECT  2.16 74.385 127.44 74.655 ;
     RECT  2.16 74.925 127.44 75.195 ;
     RECT  2.16 75.465 127.44 75.735 ;
     RECT  2.16 76.005 127.44 76.275 ;
     RECT  2.16 76.545 127.44 76.815 ;
     RECT  2.16 77.085 127.44 77.355 ;
     RECT  2.16 77.625 127.44 77.895 ;
     RECT  2.16 78.165 127.44 78.435 ;
     RECT  2.16 78.705 127.44 78.975 ;
     RECT  2.16 79.245 127.44 79.515 ;
     RECT  2.16 79.785 127.44 80.055 ;
     RECT  2.16 80.325 127.44 80.595 ;
     RECT  2.16 80.865 127.44 81.135 ;
     RECT  2.16 81.405 127.44 81.675 ;
     RECT  2.16 81.945 127.44 82.215 ;
     RECT  2.16 82.485 127.44 82.755 ;
     RECT  2.16 83.025 127.44 83.295 ;
     RECT  2.16 83.565 127.44 83.835 ;
     RECT  2.16 84.105 127.44 84.375 ;
     RECT  2.16 84.645 127.44 84.915 ;
     RECT  2.16 85.185 127.44 85.455 ;
     RECT  2.16 85.725 127.44 85.995 ;
     RECT  2.16 86.265 127.44 86.535 ;
     RECT  2.16 86.805 127.44 87.075 ;
     RECT  2.16 87.345 127.44 87.615 ;
     RECT  2.16 87.885 127.44 88.155 ;
     RECT  2.16 88.425 127.44 88.695 ;
     RECT  2.16 88.965 127.44 89.235 ;
     RECT  2.16 89.505 127.44 89.775 ;
     RECT  2.16 90.045 127.44 90.315 ;
     RECT  2.16 90.585 127.44 90.855 ;
     RECT  2.16 91.125 127.44 91.395 ;
     RECT  2.16 91.665 127.44 91.935 ;
     RECT  2.16 92.205 127.44 92.475 ;
     RECT  2.16 92.745 127.44 93.015 ;
     RECT  2.16 93.285 127.44 93.555 ;
     RECT  2.16 93.825 127.44 94.095 ;
     RECT  2.16 94.365 127.44 94.635 ;
     RECT  2.16 94.905 127.44 95.175 ;
     RECT  2.16 95.445 127.44 95.715 ;
     RECT  2.16 95.985 127.44 96.255 ;
     RECT  2.16 96.525 127.44 96.795 ;
     RECT  2.16 97.065 127.44 97.335 ;
     RECT  2.16 97.605 127.44 97.875 ;
     RECT  2.16 98.145 127.44 98.415 ;
     RECT  2.16 98.685 127.44 98.955 ;
     RECT  2.16 99.225 127.44 99.495 ;
     RECT  2.16 99.765 127.44 100.035 ;
     RECT  2.16 100.305 127.44 100.575 ;
     RECT  2.16 100.845 127.44 101.115 ;
     RECT  2.16 101.385 127.44 101.655 ;
     RECT  2.16 101.925 127.44 102.195 ;
     RECT  2.16 102.465 127.44 102.735 ;
     RECT  2.16 103.005 127.44 103.275 ;
     RECT  2.16 103.545 127.44 103.815 ;
     RECT  2.16 104.085 127.44 104.355 ;
     RECT  2.16 104.625 127.44 104.895 ;
     RECT  2.16 105.165 127.44 105.435 ;
     RECT  2.16 105.705 127.44 105.975 ;
     RECT  2.16 106.245 127.44 106.515 ;
     RECT  2.16 106.785 127.44 107.055 ;
     RECT  2.16 107.325 127.44 107.595 ;
     RECT  2.16 107.865 127.44 108.135 ;
     RECT  2.16 108.405 127.44 108.675 ;
     RECT  2.16 108.945 127.44 109.215 ;
     RECT  2.16 109.485 127.44 109.755 ;
     RECT  2.16 110.025 127.44 110.295 ;
     RECT  2.16 110.565 127.44 110.835 ;
     RECT  2.16 111.105 127.44 111.375 ;
     RECT  2.16 111.645 127.44 111.915 ;
     RECT  2.16 112.185 127.44 112.455 ;
     RECT  2.16 112.725 127.44 112.995 ;
     RECT  2.16 113.265 127.44 113.535 ;
     RECT  2.16 113.805 127.44 114.075 ;
     RECT  2.16 114.345 127.44 114.615 ;
     RECT  2.16 114.885 127.44 115.155 ;
     RECT  2.16 115.425 127.44 115.695 ;
     RECT  2.16 115.965 127.44 116.235 ;
     RECT  2.16 116.505 127.44 116.775 ;
     RECT  2.16 117.045 127.44 117.315 ;
     RECT  2.16 117.585 127.44 117.855 ;
     RECT  2.16 118.125 127.44 118.395 ;
     RECT  2.16 118.665 127.44 118.935 ;
     RECT  2.16 119.205 127.44 119.475 ;
     RECT  2.16 119.745 127.44 120.015 ;
     RECT  2.16 120.285 127.44 120.555 ;
     RECT  2.16 120.825 127.44 121.095 ;
     RECT  2.16 121.365 127.44 121.635 ;
     RECT  2.16 121.905 127.44 122.175 ;
     RECT  2.16 122.445 127.44 122.715 ;
     RECT  2.16 122.985 127.44 123.255 ;
     RECT  2.16 123.525 127.44 123.795 ;
     RECT  2.16 124.065 127.44 124.335 ;
     RECT  2.16 124.605 127.44 124.875 ;
     RECT  2.16 125.145 127.44 125.415 ;
     RECT  2.16 125.685 127.44 125.955 ;
     RECT  2.16 126.225 127.44 126.495 ;
     RECT  2.16 126.765 127.44 127.035 ;
     RECT  2.16 127.305 127.44 127.575 ;
     RECT  2.16 127.845 127.44 128.115 ;
     RECT  2.16 128.385 127.44 128.655 ;
     RECT  2.16 128.925 127.44 129.195 ;
     RECT  2.16 129.465 127.44 129.735 ;
     RECT  2.16 130.005 127.44 130.275 ;
     RECT  2.16 130.545 127.44 130.815 ;
     RECT  2.16 131.085 127.44 131.355 ;
     RECT  2.16 131.625 127.44 131.895 ;
     RECT  2.16 132.165 127.44 132.435 ;
     RECT  2.16 132.705 127.44 132.975 ;
     RECT  2.16 133.245 127.44 133.515 ;
     RECT  2.16 133.785 127.44 134.055 ;
     RECT  2.16 134.325 127.44 134.595 ;
     RECT  2.16 134.865 127.44 135.135 ;
     RECT  2.16 135.405 127.44 135.675 ;
     RECT  2.16 135.945 127.44 136.215 ;
     RECT  2.16 136.485 127.44 136.755 ;
     RECT  2.16 137.025 127.44 137.295 ;
     RECT  2.16 137.565 127.44 137.835 ;
     RECT  2.16 138.105 127.44 138.375 ;
     RECT  2.16 138.645 127.44 138.915 ;
     RECT  2.16 139.185 127.44 139.455 ;
     RECT  2.16 139.725 127.44 139.995 ;
     RECT  2.16 140.265 127.44 140.535 ;
     RECT  2.16 140.805 127.44 141.075 ;
     RECT  2.16 141.345 127.44 141.615 ;
     RECT  2.16 141.885 127.44 142.155 ;
     RECT  2.16 142.425 127.44 142.695 ;
     RECT  2.16 142.965 127.44 143.235 ;
     RECT  2.16 143.505 127.44 143.775 ;
     RECT  2.16 144.045 127.44 144.315 ;
     RECT  2.16 144.585 127.44 144.855 ;
     RECT  2.16 145.125 127.44 145.395 ;
     RECT  2.16 145.665 127.44 145.935 ;
     RECT  2.16 146.205 127.44 146.475 ;
     RECT  2.16 146.745 127.44 147.015 ;
     RECT  2.16 147.285 127.44 147.555 ;
     RECT  2.16 147.825 127.44 148.095 ;
     RECT  2.16 148.365 127.44 148.635 ;
     RECT  2.16 148.905 127.44 149.175 ;
     RECT  2.16 149.445 127.44 149.715 ;
     RECT  2.16 149.985 127.44 150.255 ;
     RECT  2.16 150.525 127.44 150.795 ;
     RECT  2.16 151.065 127.44 151.335 ;
     RECT  2.16 151.605 127.44 151.875 ;
     RECT  2.16 152.145 127.44 152.415 ;
     RECT  2.16 152.685 127.44 152.955 ;
     RECT  2.16 153.225 127.44 153.495 ;
     RECT  2.16 153.765 127.44 154.035 ;
     RECT  2.16 154.305 127.44 154.575 ;
     RECT  2.16 154.845 127.44 155.115 ;
     RECT  2.16 155.385 127.44 155.655 ;
     RECT  2.16 155.925 127.44 156.195 ;
     RECT  2.16 156.465 127.44 156.735 ;
     RECT  2.16 157.005 127.44 157.275 ;
     RECT  2.16 157.545 127.44 157.815 ;
     RECT  2.16 158.085 127.44 158.355 ;
     RECT  2.16 158.625 127.44 158.895 ;
     RECT  2.16 159.165 127.44 159.435 ;
     RECT  2.16 159.705 127.44 159.975 ;
     RECT  2.16 160.245 127.44 160.515 ;
     RECT  2.16 160.785 127.44 161.055 ;
     RECT  2.16 161.325 127.44 161.595 ;
     RECT  2.16 161.865 127.44 162.135 ;
     RECT  2.16 162.405 127.44 162.675 ;
     RECT  2.16 162.945 127.44 163.215 ;
     RECT  2.16 163.485 127.44 163.755 ;
     RECT  2.16 164.025 127.44 164.295 ;
     RECT  2.16 164.565 127.44 164.835 ;
     RECT  2.16 165.105 127.44 165.375 ;
     RECT  2.16 165.645 127.44 165.915 ;
     RECT  2.16 166.185 127.44 166.455 ;
     RECT  2.16 166.725 127.44 166.995 ;
     RECT  2.16 167.265 127.44 167.535 ;
     RECT  2.16 167.805 127.44 168.075 ;
     RECT  2.16 168.345 127.44 168.615 ;
     RECT  2.16 168.885 127.44 169.155 ;
     RECT  2.16 169.425 127.44 169.695 ;
     RECT  2.16 169.965 127.44 170.235 ;
     RECT  2.16 170.505 127.44 170.775 ;
     RECT  2.16 171.045 127.44 171.315 ;
     RECT  2.16 171.585 127.44 171.855 ;
     RECT  2.16 172.125 127.44 172.395 ;
     RECT  2.16 172.665 127.44 172.8 ;
    LAYER RVTP ;
     RECT  2.16 2.295 127.44 2.565 ;
     RECT  2.16 2.835 127.44 3.105 ;
     RECT  2.16 3.375 127.44 3.645 ;
     RECT  2.16 3.915 127.44 4.185 ;
     RECT  2.16 4.455 127.44 4.725 ;
     RECT  2.16 4.995 127.44 5.265 ;
     RECT  2.16 5.535 127.44 5.805 ;
     RECT  2.16 6.075 127.44 6.345 ;
     RECT  2.16 6.615 127.44 6.885 ;
     RECT  2.16 7.155 127.44 7.425 ;
     RECT  2.16 7.695 127.44 7.965 ;
     RECT  2.16 8.235 127.44 8.505 ;
     RECT  2.16 8.775 127.44 9.045 ;
     RECT  2.16 9.315 127.44 9.585 ;
     RECT  2.16 9.855 127.44 10.125 ;
     RECT  2.16 10.395 127.44 10.665 ;
     RECT  2.16 10.935 127.44 11.205 ;
     RECT  2.16 11.475 127.44 11.745 ;
     RECT  2.16 12.015 127.44 12.285 ;
     RECT  2.16 12.555 127.44 12.825 ;
     RECT  2.16 13.095 127.44 13.365 ;
     RECT  2.16 13.635 127.44 13.905 ;
     RECT  2.16 14.175 127.44 14.445 ;
     RECT  2.16 14.715 127.44 14.985 ;
     RECT  2.16 15.255 127.44 15.525 ;
     RECT  2.16 15.795 127.44 16.065 ;
     RECT  2.16 16.335 127.44 16.605 ;
     RECT  2.16 16.875 127.44 17.145 ;
     RECT  2.16 17.415 127.44 17.685 ;
     RECT  2.16 17.955 127.44 18.225 ;
     RECT  2.16 18.495 127.44 18.765 ;
     RECT  2.16 19.035 127.44 19.305 ;
     RECT  2.16 19.575 127.44 19.845 ;
     RECT  2.16 20.115 127.44 20.385 ;
     RECT  2.16 20.655 127.44 20.925 ;
     RECT  2.16 21.195 127.44 21.465 ;
     RECT  2.16 21.735 127.44 22.005 ;
     RECT  2.16 22.275 127.44 22.545 ;
     RECT  2.16 22.815 127.44 23.085 ;
     RECT  2.16 23.355 127.44 23.625 ;
     RECT  2.16 23.895 127.44 24.165 ;
     RECT  2.16 24.435 127.44 24.705 ;
     RECT  2.16 24.975 127.44 25.245 ;
     RECT  2.16 25.515 127.44 25.785 ;
     RECT  2.16 26.055 127.44 26.325 ;
     RECT  2.16 26.595 127.44 26.865 ;
     RECT  2.16 27.135 127.44 27.405 ;
     RECT  2.16 27.675 127.44 27.945 ;
     RECT  2.16 28.215 127.44 28.485 ;
     RECT  2.16 28.755 127.44 29.025 ;
     RECT  2.16 29.295 127.44 29.565 ;
     RECT  2.16 29.835 127.44 30.105 ;
     RECT  2.16 30.375 127.44 30.645 ;
     RECT  2.16 30.915 127.44 31.185 ;
     RECT  2.16 31.455 127.44 31.725 ;
     RECT  2.16 31.995 127.44 32.265 ;
     RECT  2.16 32.535 127.44 32.805 ;
     RECT  2.16 33.075 127.44 33.345 ;
     RECT  2.16 33.615 127.44 33.885 ;
     RECT  2.16 34.155 127.44 34.425 ;
     RECT  2.16 34.695 127.44 34.965 ;
     RECT  2.16 35.235 127.44 35.505 ;
     RECT  2.16 35.775 127.44 36.045 ;
     RECT  2.16 36.315 127.44 36.585 ;
     RECT  2.16 36.855 127.44 37.125 ;
     RECT  2.16 37.395 127.44 37.665 ;
     RECT  2.16 37.935 127.44 38.205 ;
     RECT  2.16 38.475 127.44 38.745 ;
     RECT  2.16 39.015 127.44 39.285 ;
     RECT  2.16 39.555 127.44 39.825 ;
     RECT  2.16 40.095 127.44 40.365 ;
     RECT  2.16 40.635 127.44 40.905 ;
     RECT  2.16 41.175 127.44 41.445 ;
     RECT  2.16 41.715 127.44 41.985 ;
     RECT  2.16 42.255 127.44 42.525 ;
     RECT  2.16 42.795 127.44 43.065 ;
     RECT  2.16 43.335 127.44 43.605 ;
     RECT  2.16 43.875 127.44 44.145 ;
     RECT  2.16 44.415 127.44 44.685 ;
     RECT  2.16 44.955 127.44 45.225 ;
     RECT  2.16 45.495 127.44 45.765 ;
     RECT  2.16 46.035 127.44 46.305 ;
     RECT  2.16 46.575 127.44 46.845 ;
     RECT  2.16 47.115 127.44 47.385 ;
     RECT  2.16 47.655 127.44 47.925 ;
     RECT  2.16 48.195 127.44 48.465 ;
     RECT  2.16 48.735 127.44 49.005 ;
     RECT  2.16 49.275 127.44 49.545 ;
     RECT  2.16 49.815 127.44 50.085 ;
     RECT  2.16 50.355 127.44 50.625 ;
     RECT  2.16 50.895 127.44 51.165 ;
     RECT  2.16 51.435 127.44 51.705 ;
     RECT  2.16 51.975 127.44 52.245 ;
     RECT  2.16 52.515 127.44 52.785 ;
     RECT  2.16 53.055 127.44 53.325 ;
     RECT  2.16 53.595 127.44 53.865 ;
     RECT  2.16 54.135 127.44 54.405 ;
     RECT  2.16 54.675 127.44 54.945 ;
     RECT  2.16 55.215 127.44 55.485 ;
     RECT  2.16 55.755 127.44 56.025 ;
     RECT  2.16 56.295 127.44 56.565 ;
     RECT  2.16 56.835 127.44 57.105 ;
     RECT  2.16 57.375 127.44 57.645 ;
     RECT  2.16 57.915 127.44 58.185 ;
     RECT  2.16 58.455 127.44 58.725 ;
     RECT  2.16 58.995 127.44 59.265 ;
     RECT  2.16 59.535 127.44 59.805 ;
     RECT  2.16 60.075 127.44 60.345 ;
     RECT  2.16 60.615 127.44 60.885 ;
     RECT  2.16 61.155 127.44 61.425 ;
     RECT  2.16 61.695 127.44 61.965 ;
     RECT  2.16 62.235 127.44 62.505 ;
     RECT  2.16 62.775 127.44 63.045 ;
     RECT  2.16 63.315 127.44 63.585 ;
     RECT  2.16 63.855 127.44 64.125 ;
     RECT  2.16 64.395 127.44 64.665 ;
     RECT  2.16 64.935 127.44 65.205 ;
     RECT  2.16 65.475 127.44 65.745 ;
     RECT  2.16 66.015 127.44 66.285 ;
     RECT  2.16 66.555 127.44 66.825 ;
     RECT  2.16 67.095 127.44 67.365 ;
     RECT  2.16 67.635 127.44 67.905 ;
     RECT  2.16 68.175 127.44 68.445 ;
     RECT  2.16 68.715 127.44 68.985 ;
     RECT  2.16 69.255 127.44 69.525 ;
     RECT  2.16 69.795 127.44 70.065 ;
     RECT  2.16 70.335 127.44 70.605 ;
     RECT  2.16 70.875 127.44 71.145 ;
     RECT  2.16 71.415 127.44 71.685 ;
     RECT  2.16 71.955 127.44 72.225 ;
     RECT  2.16 72.495 127.44 72.765 ;
     RECT  2.16 73.035 127.44 73.305 ;
     RECT  2.16 73.575 127.44 73.845 ;
     RECT  2.16 74.115 127.44 74.385 ;
     RECT  2.16 74.655 127.44 74.925 ;
     RECT  2.16 75.195 127.44 75.465 ;
     RECT  2.16 75.735 127.44 76.005 ;
     RECT  2.16 76.275 127.44 76.545 ;
     RECT  2.16 76.815 127.44 77.085 ;
     RECT  2.16 77.355 127.44 77.625 ;
     RECT  2.16 77.895 127.44 78.165 ;
     RECT  2.16 78.435 127.44 78.705 ;
     RECT  2.16 78.975 127.44 79.245 ;
     RECT  2.16 79.515 127.44 79.785 ;
     RECT  2.16 80.055 127.44 80.325 ;
     RECT  2.16 80.595 127.44 80.865 ;
     RECT  2.16 81.135 127.44 81.405 ;
     RECT  2.16 81.675 127.44 81.945 ;
     RECT  2.16 82.215 127.44 82.485 ;
     RECT  2.16 82.755 127.44 83.025 ;
     RECT  2.16 83.295 127.44 83.565 ;
     RECT  2.16 83.835 127.44 84.105 ;
     RECT  2.16 84.375 127.44 84.645 ;
     RECT  2.16 84.915 127.44 85.185 ;
     RECT  2.16 85.455 127.44 85.725 ;
     RECT  2.16 85.995 127.44 86.265 ;
     RECT  2.16 86.535 127.44 86.805 ;
     RECT  2.16 87.075 127.44 87.345 ;
     RECT  2.16 87.615 127.44 87.885 ;
     RECT  2.16 88.155 127.44 88.425 ;
     RECT  2.16 88.695 127.44 88.965 ;
     RECT  2.16 89.235 127.44 89.505 ;
     RECT  2.16 89.775 127.44 90.045 ;
     RECT  2.16 90.315 127.44 90.585 ;
     RECT  2.16 90.855 127.44 91.125 ;
     RECT  2.16 91.395 127.44 91.665 ;
     RECT  2.16 91.935 127.44 92.205 ;
     RECT  2.16 92.475 127.44 92.745 ;
     RECT  2.16 93.015 127.44 93.285 ;
     RECT  2.16 93.555 127.44 93.825 ;
     RECT  2.16 94.095 127.44 94.365 ;
     RECT  2.16 94.635 127.44 94.905 ;
     RECT  2.16 95.175 127.44 95.445 ;
     RECT  2.16 95.715 127.44 95.985 ;
     RECT  2.16 96.255 127.44 96.525 ;
     RECT  2.16 96.795 127.44 97.065 ;
     RECT  2.16 97.335 127.44 97.605 ;
     RECT  2.16 97.875 127.44 98.145 ;
     RECT  2.16 98.415 127.44 98.685 ;
     RECT  2.16 98.955 127.44 99.225 ;
     RECT  2.16 99.495 127.44 99.765 ;
     RECT  2.16 100.035 127.44 100.305 ;
     RECT  2.16 100.575 127.44 100.845 ;
     RECT  2.16 101.115 127.44 101.385 ;
     RECT  2.16 101.655 127.44 101.925 ;
     RECT  2.16 102.195 127.44 102.465 ;
     RECT  2.16 102.735 127.44 103.005 ;
     RECT  2.16 103.275 127.44 103.545 ;
     RECT  2.16 103.815 127.44 104.085 ;
     RECT  2.16 104.355 127.44 104.625 ;
     RECT  2.16 104.895 127.44 105.165 ;
     RECT  2.16 105.435 127.44 105.705 ;
     RECT  2.16 105.975 127.44 106.245 ;
     RECT  2.16 106.515 127.44 106.785 ;
     RECT  2.16 107.055 127.44 107.325 ;
     RECT  2.16 107.595 127.44 107.865 ;
     RECT  2.16 108.135 127.44 108.405 ;
     RECT  2.16 108.675 127.44 108.945 ;
     RECT  2.16 109.215 127.44 109.485 ;
     RECT  2.16 109.755 127.44 110.025 ;
     RECT  2.16 110.295 127.44 110.565 ;
     RECT  2.16 110.835 127.44 111.105 ;
     RECT  2.16 111.375 127.44 111.645 ;
     RECT  2.16 111.915 127.44 112.185 ;
     RECT  2.16 112.455 127.44 112.725 ;
     RECT  2.16 112.995 127.44 113.265 ;
     RECT  2.16 113.535 127.44 113.805 ;
     RECT  2.16 114.075 127.44 114.345 ;
     RECT  2.16 114.615 127.44 114.885 ;
     RECT  2.16 115.155 127.44 115.425 ;
     RECT  2.16 115.695 127.44 115.965 ;
     RECT  2.16 116.235 127.44 116.505 ;
     RECT  2.16 116.775 127.44 117.045 ;
     RECT  2.16 117.315 127.44 117.585 ;
     RECT  2.16 117.855 127.44 118.125 ;
     RECT  2.16 118.395 127.44 118.665 ;
     RECT  2.16 118.935 127.44 119.205 ;
     RECT  2.16 119.475 127.44 119.745 ;
     RECT  2.16 120.015 127.44 120.285 ;
     RECT  2.16 120.555 127.44 120.825 ;
     RECT  2.16 121.095 127.44 121.365 ;
     RECT  2.16 121.635 127.44 121.905 ;
     RECT  2.16 122.175 127.44 122.445 ;
     RECT  2.16 122.715 127.44 122.985 ;
     RECT  2.16 123.255 127.44 123.525 ;
     RECT  2.16 123.795 127.44 124.065 ;
     RECT  2.16 124.335 127.44 124.605 ;
     RECT  2.16 124.875 127.44 125.145 ;
     RECT  2.16 125.415 127.44 125.685 ;
     RECT  2.16 125.955 127.44 126.225 ;
     RECT  2.16 126.495 127.44 126.765 ;
     RECT  2.16 127.035 127.44 127.305 ;
     RECT  2.16 127.575 127.44 127.845 ;
     RECT  2.16 128.115 127.44 128.385 ;
     RECT  2.16 128.655 127.44 128.925 ;
     RECT  2.16 129.195 127.44 129.465 ;
     RECT  2.16 129.735 127.44 130.005 ;
     RECT  2.16 130.275 127.44 130.545 ;
     RECT  2.16 130.815 127.44 131.085 ;
     RECT  2.16 131.355 127.44 131.625 ;
     RECT  2.16 131.895 127.44 132.165 ;
     RECT  2.16 132.435 127.44 132.705 ;
     RECT  2.16 132.975 127.44 133.245 ;
     RECT  2.16 133.515 127.44 133.785 ;
     RECT  2.16 134.055 127.44 134.325 ;
     RECT  2.16 134.595 127.44 134.865 ;
     RECT  2.16 135.135 127.44 135.405 ;
     RECT  2.16 135.675 127.44 135.945 ;
     RECT  2.16 136.215 127.44 136.485 ;
     RECT  2.16 136.755 127.44 137.025 ;
     RECT  2.16 137.295 127.44 137.565 ;
     RECT  2.16 137.835 127.44 138.105 ;
     RECT  2.16 138.375 127.44 138.645 ;
     RECT  2.16 138.915 127.44 139.185 ;
     RECT  2.16 139.455 127.44 139.725 ;
     RECT  2.16 139.995 127.44 140.265 ;
     RECT  2.16 140.535 127.44 140.805 ;
     RECT  2.16 141.075 127.44 141.345 ;
     RECT  2.16 141.615 127.44 141.885 ;
     RECT  2.16 142.155 127.44 142.425 ;
     RECT  2.16 142.695 127.44 142.965 ;
     RECT  2.16 143.235 127.44 143.505 ;
     RECT  2.16 143.775 127.44 144.045 ;
     RECT  2.16 144.315 127.44 144.585 ;
     RECT  2.16 144.855 127.44 145.125 ;
     RECT  2.16 145.395 127.44 145.665 ;
     RECT  2.16 145.935 127.44 146.205 ;
     RECT  2.16 146.475 127.44 146.745 ;
     RECT  2.16 147.015 127.44 147.285 ;
     RECT  2.16 147.555 127.44 147.825 ;
     RECT  2.16 148.095 127.44 148.365 ;
     RECT  2.16 148.635 127.44 148.905 ;
     RECT  2.16 149.175 127.44 149.445 ;
     RECT  2.16 149.715 127.44 149.985 ;
     RECT  2.16 150.255 127.44 150.525 ;
     RECT  2.16 150.795 127.44 151.065 ;
     RECT  2.16 151.335 127.44 151.605 ;
     RECT  2.16 151.875 127.44 152.145 ;
     RECT  2.16 152.415 127.44 152.685 ;
     RECT  2.16 152.955 127.44 153.225 ;
     RECT  2.16 153.495 127.44 153.765 ;
     RECT  2.16 154.035 127.44 154.305 ;
     RECT  2.16 154.575 127.44 154.845 ;
     RECT  2.16 155.115 127.44 155.385 ;
     RECT  2.16 155.655 127.44 155.925 ;
     RECT  2.16 156.195 127.44 156.465 ;
     RECT  2.16 156.735 127.44 157.005 ;
     RECT  2.16 157.275 127.44 157.545 ;
     RECT  2.16 157.815 127.44 158.085 ;
     RECT  2.16 158.355 127.44 158.625 ;
     RECT  2.16 158.895 127.44 159.165 ;
     RECT  2.16 159.435 127.44 159.705 ;
     RECT  2.16 159.975 127.44 160.245 ;
     RECT  2.16 160.515 127.44 160.785 ;
     RECT  2.16 161.055 127.44 161.325 ;
     RECT  2.16 161.595 127.44 161.865 ;
     RECT  2.16 162.135 127.44 162.405 ;
     RECT  2.16 162.675 127.44 162.945 ;
     RECT  2.16 163.215 127.44 163.485 ;
     RECT  2.16 163.755 127.44 164.025 ;
     RECT  2.16 164.295 127.44 164.565 ;
     RECT  2.16 164.835 127.44 165.105 ;
     RECT  2.16 165.375 127.44 165.645 ;
     RECT  2.16 165.915 127.44 166.185 ;
     RECT  2.16 166.455 127.44 166.725 ;
     RECT  2.16 166.995 127.44 167.265 ;
     RECT  2.16 167.535 127.44 167.805 ;
     RECT  2.16 168.075 127.44 168.345 ;
     RECT  2.16 168.615 127.44 168.885 ;
     RECT  2.16 169.155 127.44 169.425 ;
     RECT  2.16 169.695 127.44 169.965 ;
     RECT  2.16 170.235 127.44 170.505 ;
     RECT  2.16 170.775 127.44 171.045 ;
     RECT  2.16 171.315 127.44 171.585 ;
     RECT  2.16 171.855 127.44 172.125 ;
     RECT  2.16 172.395 127.44 172.665 ;
    LAYER M1 ;
     RECT  2.16 2.151 127.44 172.809 ;
    LAYER M2 ;
     RECT  0.211 88.74 0.247 88.884 ;
     RECT  0.211 115.056 0.247 116.154 ;
     RECT  0.211 121.302 0.247 121.32 ;
     RECT  0.211 122.076 0.247 122.094 ;
     RECT  0.211 122.958 0.247 122.976 ;
     RECT  0.211 126.468 0.247 127.026 ;
     RECT  0.211 128.196 0.247 128.34 ;
     RECT  0.211 135.342 0.247 135.504 ;
     RECT  0.211 150.426 0.247 151.524 ;
     RECT  0.211 109.386 0.283 109.404 ;
     RECT  0.211 134.496 0.283 134.514 ;
     RECT  0.247 135.342 0.283 136.206 ;
     RECT  0.175 85.662 0.319 85.68 ;
     RECT  0.283 109.386 0.319 109.818 ;
     RECT  0.211 119.106 0.319 119.7 ;
     RECT  0.247 122.886 0.319 122.976 ;
     RECT  0.211 132.408 0.319 132.426 ;
     RECT  0.319 85.662 0.347 85.752 ;
     RECT  0.247 90.594 0.347 90.612 ;
     RECT  0.211 145.296 0.347 147.042 ;
     RECT  0.211 99.234 0.355 99.954 ;
     RECT  0.211 100.746 0.355 100.764 ;
     RECT  0.319 109.296 0.355 109.818 ;
     RECT  0.211 113.166 0.355 113.184 ;
     RECT  0.247 114.858 0.355 116.154 ;
     RECT  0.211 117.324 0.355 117.342 ;
     RECT  0.211 118.206 0.355 118.224 ;
     RECT  0.247 121.302 0.355 122.094 ;
     RECT  0.319 122.886 0.355 123.516 ;
     RECT  0.211 125.388 0.355 125.406 ;
     RECT  0.211 144.216 0.355 144.234 ;
     RECT  0.211 149.616 0.355 149.634 ;
     RECT  0.211 142.668 0.391 142.686 ;
     RECT  0.355 144.018 0.391 144.234 ;
     RECT  0.347 145.296 0.391 146.394 ;
     RECT  0.211 154.314 0.391 155.574 ;
     RECT  0.355 148.914 0.427 149.634 ;
     RECT  0.247 150.426 0.427 151.794 ;
     RECT  0.391 154.314 0.427 155.754 ;
     RECT  0.211 87.516 0.463 87.534 ;
     RECT  0.211 80.64 0.499 80.658 ;
     RECT  0.247 161.226 0.499 161.244 ;
     RECT  0.499 80.334 0.535 80.658 ;
     RECT  0.211 163.386 0.535 163.404 ;
     RECT  0.463 165.996 0.535 166.014 ;
     RECT  0.211 166.968 0.535 167.454 ;
     RECT  0.463 86.616 0.563 86.634 ;
     RECT  0.463 87.516 0.563 87.714 ;
     RECT  0.355 114.858 0.571 118.224 ;
     RECT  0.175 103.788 0.859 103.806 ;
     RECT  0.391 70.344 0.931 70.362 ;
     RECT  0.571 114.624 0.931 118.224 ;
     RECT  0.319 119.106 0.931 120.276 ;
     RECT  0.931 114.624 0.967 120.276 ;
     RECT  0.355 124.812 1.003 125.406 ;
     RECT  0.247 104.598 1.039 104.616 ;
     RECT  0.247 88.632 1.075 89.46 ;
     RECT  0.823 106.866 1.075 106.884 ;
     RECT  0.563 87.516 1.147 87.642 ;
     RECT  0.319 93.456 1.147 93.474 ;
     RECT  0.355 94.41 1.147 94.428 ;
     RECT  0.355 95.418 1.147 95.436 ;
     RECT  0.895 102.276 1.147 102.294 ;
     RECT  0.859 103.356 1.147 103.806 ;
     RECT  1.039 104.598 1.147 104.652 ;
     RECT  1.075 106.866 1.147 107.316 ;
     RECT  0.355 108.216 1.147 110.016 ;
     RECT  0.391 142.668 1.147 142.956 ;
     RECT  0.427 154.314 1.147 155.952 ;
     RECT  1.147 93.456 1.175 94.428 ;
     RECT  1.147 95.22 1.175 95.436 ;
     RECT  1.147 102.276 1.175 104.652 ;
     RECT  0.347 85.734 1.183 85.752 ;
     RECT  1.175 102.51 1.183 104.652 ;
     RECT  0.247 126.396 1.183 128.34 ;
     RECT  1.183 85.734 1.211 85.824 ;
     RECT  1.003 124.812 1.211 125.514 ;
     RECT  1.003 76.014 1.579 76.032 ;
     RECT  1.175 95.22 1.579 95.238 ;
     RECT  1.147 87.282 1.615 87.642 ;
     RECT  1.075 88.632 1.615 89.496 ;
     RECT  0.859 57.726 1.651 57.744 ;
     RECT  1.651 96.876 1.723 96.894 ;
     RECT  1.147 106.146 1.867 107.316 ;
     RECT  1.147 108.108 1.867 110.016 ;
     RECT  1.579 94.986 1.939 95.238 ;
     RECT  1.211 85.806 2.011 85.824 ;
     RECT  1.723 96.876 2.011 97.524 ;
     RECT  1.183 126.306 2.011 128.34 ;
     RECT  0.355 129.276 2.011 129.726 ;
     RECT  1.111 59.004 2.047 59.022 ;
     RECT  0.823 68.256 2.083 68.274 ;
     RECT  1.211 124.812 2.155 125.442 ;
     RECT  2.011 126.306 2.155 129.726 ;
     RECT  0.535 5.31 2.16 5.328 ;
     RECT  0.211 35.82 2.16 35.838 ;
     RECT  2.011 36.9 2.16 36.918 ;
     RECT  0.211 42.57 2.16 42.588 ;
     RECT  1.867 49.356 2.16 49.374 ;
     RECT  1.975 51.786 2.16 51.804 ;
     RECT  0.283 52.758 2.16 52.776 ;
     RECT  1.039 53.946 2.16 53.964 ;
     RECT  0.895 55.296 2.16 55.314 ;
     RECT  0.355 56.646 2.16 56.664 ;
     RECT  1.651 57.726 2.16 58.014 ;
     RECT  2.047 59.004 2.16 59.562 ;
     RECT  1.687 61.434 2.16 61.452 ;
     RECT  2.155 66.834 2.16 66.852 ;
     RECT  2.083 68.256 2.16 68.976 ;
     RECT  0.931 69.804 2.16 70.362 ;
     RECT  0.967 71.694 2.16 71.712 ;
     RECT  1.939 72.774 2.16 72.792 ;
     RECT  0.319 74.7 2.16 74.718 ;
     RECT  1.579 75.546 2.16 76.032 ;
     RECT  0.427 77.094 2.16 77.112 ;
     RECT  0.211 77.94 2.16 77.958 ;
     RECT  1.939 78.984 2.16 79.002 ;
     RECT  0.535 80.334 2.16 80.694 ;
     RECT  2.011 85.266 2.16 85.824 ;
     RECT  1.615 87.282 2.16 89.496 ;
     RECT  0.211 91.746 2.16 91.764 ;
     RECT  1.175 93.456 2.16 94.194 ;
     RECT  1.939 94.986 2.16 95.544 ;
     RECT  2.011 96.498 2.16 97.794 ;
     RECT  0.355 99.234 2.16 100.764 ;
     RECT  1.183 102.51 2.16 104.724 ;
     RECT  1.867 106.146 2.16 110.016 ;
     RECT  0.355 112.266 2.16 112.284 ;
     RECT  0.355 113.166 2.16 113.832 ;
     RECT  0.967 114.624 2.16 120.384 ;
     RECT  0.355 121.302 2.16 123.588 ;
     RECT  2.155 124.812 2.16 129.726 ;
     RECT  0.355 131.13 2.16 131.148 ;
     RECT  0.319 131.976 2.16 132.426 ;
     RECT  0.283 134.496 2.16 136.206 ;
     RECT  0.391 137.376 2.16 137.394 ;
     RECT  0.211 138.276 2.16 138.294 ;
     RECT  0.391 139.392 2.16 139.41 ;
     RECT  0.211 140.166 2.16 140.724 ;
     RECT  0.319 141.66 2.16 141.678 ;
     RECT  1.147 142.596 2.16 142.956 ;
     RECT  0.391 143.946 2.16 146.394 ;
     RECT  0.427 148.914 2.16 151.794 ;
     RECT  1.147 154.314 2.16 156.024 ;
     RECT  0.427 157.086 2.16 157.104 ;
     RECT  0.427 160.056 2.16 160.074 ;
     RECT  0.499 160.866 2.16 161.244 ;
     RECT  0.211 162.036 2.16 162.054 ;
     RECT  0.535 162.99 2.16 163.404 ;
     RECT  0.535 165.042 2.16 165.06 ;
     RECT  0.535 165.816 2.16 166.014 ;
     RECT  0.535 166.968 2.16 168.336 ;
     RECT  2.16 2.151 127.44 172.809 ;
    LAYER M3 ;
     RECT  24.015 2.143 24.105 2.191 ;
     RECT  37.515 2.143 37.605 2.191 ;
     RECT  7.815 2.143 7.905 2.227 ;
     RECT  32.115 2.143 32.205 2.227 ;
     RECT  7.815 2.227 8.262 2.263 ;
     RECT  22.932 2.191 22.95 2.263 ;
     RECT  31.896 2.227 32.205 2.263 ;
     RECT  37.515 2.191 38.286 2.263 ;
     RECT  14.76 2.263 14.994 2.299 ;
     RECT  5.115 2.143 5.205 2.335 ;
     RECT  6.336 2.263 6.354 2.335 ;
     RECT  22.68 2.263 22.95 2.335 ;
     RECT  4.14 2.191 4.158 2.371 ;
     RECT  5.115 2.335 6.354 2.371 ;
     RECT  7.815 2.263 8.514 2.371 ;
     RECT  14.76 2.299 15.03 2.371 ;
     RECT  26.715 2.143 26.805 2.371 ;
     RECT  31.896 2.263 32.454 2.371 ;
     RECT  33.66 2.251 33.678 2.371 ;
     RECT  34.815 2.143 34.905 2.371 ;
     RECT  2.415 2.143 2.505 2.413 ;
     RECT  3.384 2.227 3.402 2.413 ;
     RECT  10.515 2.143 10.605 2.413 ;
     RECT  13.215 2.143 13.305 2.413 ;
     RECT  15.915 2.143 16.005 2.413 ;
     RECT  18.615 2.143 18.705 2.413 ;
     RECT  21.315 2.143 21.405 2.413 ;
     RECT  26.715 2.371 26.874 2.413 ;
     RECT  29.415 2.143 29.505 2.413 ;
     RECT  33.66 2.371 34.905 2.413 ;
     RECT  40.215 2.143 40.305 2.413 ;
     RECT  42.915 2.143 43.005 2.413 ;
     RECT  45.615 2.143 45.705 2.413 ;
     RECT  48.315 2.143 48.405 2.413 ;
     RECT  51.015 2.143 51.105 2.413 ;
     RECT  53.715 2.143 53.805 2.413 ;
     RECT  56.415 2.143 56.505 2.413 ;
     RECT  59.115 2.143 59.205 2.413 ;
     RECT  61.815 2.143 61.905 2.413 ;
     RECT  64.515 2.143 64.605 2.413 ;
     RECT  67.215 2.143 67.305 2.413 ;
     RECT  69.915 2.143 70.005 2.413 ;
     RECT  72.615 2.143 72.705 2.413 ;
     RECT  75.315 2.143 75.405 2.413 ;
     RECT  78.015 2.143 78.105 2.413 ;
     RECT  80.715 2.143 80.805 2.413 ;
     RECT  83.415 2.143 83.505 2.413 ;
     RECT  86.115 2.143 86.205 2.413 ;
     RECT  88.815 2.143 88.905 2.413 ;
     RECT  91.515 2.143 91.605 2.413 ;
     RECT  94.215 2.143 94.305 2.413 ;
     RECT  96.915 2.143 97.005 2.413 ;
     RECT  99.615 2.143 99.705 2.413 ;
     RECT  102.315 2.143 102.405 2.413 ;
     RECT  105.015 2.143 105.105 2.413 ;
     RECT  107.715 2.143 107.805 2.413 ;
     RECT  110.415 2.143 110.505 2.413 ;
     RECT  113.115 2.143 113.205 2.413 ;
     RECT  115.815 2.143 115.905 2.413 ;
     RECT  118.515 2.143 118.605 2.413 ;
     RECT  121.215 2.143 121.305 2.413 ;
     RECT  123.915 2.143 124.005 2.413 ;
     RECT  126.615 2.143 126.705 2.413 ;
     RECT  22.392 2.335 22.95 2.461 ;
     RECT  24.015 2.191 24.57 2.461 ;
     RECT  25.596 2.263 25.614 2.461 ;
     RECT  2.415 2.413 3.402 2.533 ;
     RECT  4.14 2.371 6.354 2.533 ;
     RECT  14.724 2.371 15.03 2.533 ;
     RECT  15.915 2.413 16.197 2.533 ;
     RECT  30.996 2.461 31.014 2.533 ;
     RECT  31.896 2.371 32.67 2.569 ;
     RECT  33.66 2.413 35.097 2.569 ;
     RECT  2.415 2.533 6.354 2.605 ;
     RECT  10.515 2.413 10.797 2.605 ;
     RECT  14.724 2.533 16.197 2.605 ;
     RECT  28.548 2.371 28.566 2.605 ;
     RECT  30.924 2.533 31.014 2.605 ;
     RECT  31.896 2.569 35.097 2.605 ;
     RECT  2.415 2.605 6.426 2.641 ;
     RECT  7.815 2.371 9.162 2.641 ;
     RECT  10.515 2.605 10.998 2.641 ;
     RECT  14.724 2.605 16.542 2.641 ;
     RECT  18.615 2.413 18.897 2.641 ;
     RECT  22.392 2.461 23.13 2.641 ;
     RECT  24.015 2.461 25.614 2.641 ;
     RECT  26.715 2.413 26.997 2.641 ;
     RECT  28.152 2.605 28.566 2.641 ;
     RECT  29.415 2.413 29.697 2.641 ;
     RECT  2.415 2.641 9.162 2.731 ;
     RECT  10.515 2.641 11.646 2.731 ;
     RECT  22.392 2.641 25.614 2.731 ;
     RECT  37.515 2.263 38.646 2.731 ;
     RECT  18.615 2.641 19.674 2.767 ;
     RECT  22.392 2.731 25.65 2.767 ;
     RECT  37.404 2.731 38.718 2.767 ;
     RECT  13.215 2.413 13.497 2.803 ;
     RECT  14.724 2.641 16.83 2.803 ;
     RECT  21.315 2.413 21.597 2.803 ;
     RECT  22.392 2.767 25.722 2.803 ;
     RECT  28.152 2.641 29.697 2.803 ;
     RECT  12.708 2.803 13.497 2.858 ;
     RECT  2.415 2.731 11.718 2.875 ;
     RECT  12.672 2.858 13.497 2.875 ;
     RECT  14.652 2.803 17.046 2.875 ;
     RECT  21.315 2.803 25.722 2.875 ;
     RECT  26.568 2.641 27.27 2.875 ;
     RECT  14.508 2.875 17.118 2.911 ;
     RECT  18.504 2.767 19.674 2.911 ;
     RECT  36.54 2.767 38.718 2.911 ;
     RECT  28.044 2.803 29.697 3.037 ;
     RECT  30.744 2.605 35.097 3.037 ;
     RECT  18.504 2.911 20.178 3.073 ;
     RECT  21.315 2.875 27.27 3.073 ;
     RECT  14.436 2.911 17.118 3.115 ;
     RECT  18.36 3.073 27.27 3.145 ;
     RECT  28.044 3.037 35.097 3.145 ;
     RECT  36.072 2.911 38.718 3.145 ;
     RECT  14.436 3.115 17.154 3.181 ;
     RECT  18.108 3.145 27.27 3.181 ;
     RECT  2.415 2.875 13.497 3.271 ;
     RECT  28.044 3.145 38.718 3.343 ;
     RECT  2.415 3.271 13.554 3.403 ;
     RECT  14.436 3.181 27.27 3.451 ;
     RECT  28.044 3.343 39.402 3.451 ;
     RECT  40.215 2.413 40.497 3.577 ;
     RECT  42.084 0.043 42.102 3.577 ;
     RECT  40.215 3.577 42.102 3.649 ;
     RECT  40.215 3.649 42.138 3.721 ;
     RECT  2.415 3.403 13.698 3.811 ;
     RECT  14.436 3.451 39.402 3.811 ;
     RECT  2.415 3.811 39.402 3.955 ;
     RECT  40.215 3.721 42.174 3.955 ;
     RECT  2.415 3.955 42.174 4.261 ;
     RECT  42.915 2.413 43.197 4.261 ;
     RECT  2.415 4.261 43.197 4.379 ;
     RECT  2.415 4.379 42.174 4.415 ;
     RECT  2.415 4.415 41.094 4.555 ;
     RECT  2.304 4.555 41.094 4.559 ;
     RECT  42.915 4.379 43.197 4.963 ;
     RECT  44.028 4.459 44.046 4.963 ;
     RECT  2.304 4.559 40.662 5.099 ;
     RECT  42.915 4.963 44.046 5.503 ;
     RECT  2.304 5.099 38.322 5.645 ;
     RECT  42.915 5.503 44.442 5.809 ;
     RECT  39.204 5.099 40.662 5.845 ;
     RECT  39.204 5.845 41.13 5.881 ;
     RECT  42.408 5.809 44.442 5.881 ;
     RECT  15.915 5.645 38.322 6.151 ;
     RECT  39.204 5.881 44.442 6.151 ;
     RECT  0.54 5.305 0.558 6.221 ;
     RECT  2.304 5.645 15.138 6.523 ;
     RECT  2.268 6.523 15.138 6.619 ;
     RECT  15.915 6.151 44.442 6.619 ;
     RECT  2.268 6.619 44.442 6.647 ;
     RECT  2.304 6.647 44.442 7.771 ;
     RECT  2.304 7.771 44.514 7.961 ;
     RECT  2.304 7.961 44.442 8.107 ;
     RECT  0.216 8.203 0.234 8.299 ;
     RECT  2.268 8.107 44.442 8.465 ;
     RECT  0.216 8.299 0.414 8.477 ;
     RECT  2.304 8.465 44.442 8.707 ;
     RECT  2.304 8.707 44.55 8.969 ;
     RECT  2.304 8.969 44.442 9.419 ;
     RECT  2.304 9.419 2.862 9.739 ;
     RECT  2.268 9.739 2.862 9.815 ;
     RECT  3.672 9.419 44.442 9.823 ;
     RECT  3.672 9.823 44.514 9.895 ;
     RECT  0.252 10.123 0.27 10.253 ;
     RECT  2.304 9.815 2.862 10.267 ;
     RECT  3.672 9.895 44.802 10.267 ;
     RECT  2.304 10.267 44.802 10.741 ;
     RECT  45.615 2.413 45.897 10.741 ;
     RECT  2.304 10.741 45.897 10.843 ;
     RECT  2.268 10.843 45.897 10.967 ;
     RECT  2.304 10.967 45.897 11.003 ;
     RECT  2.304 11.003 44.73 11.821 ;
     RECT  2.304 11.821 44.802 12.325 ;
     RECT  45.615 11.003 45.897 12.325 ;
     RECT  0.252 13.435 0.27 13.613 ;
     RECT  0.252 14.587 0.27 14.717 ;
     RECT  2.304 12.325 45.897 15.691 ;
     RECT  0.252 15.739 0.27 15.917 ;
     RECT  2.268 15.691 45.897 17.105 ;
     RECT  2.304 17.105 45.897 17.609 ;
     RECT  2.304 17.609 44.802 17.915 ;
     RECT  2.304 17.915 44.73 19.111 ;
     RECT  45.615 17.609 45.897 19.111 ;
     RECT  2.304 19.111 45.897 19.435 ;
     RECT  2.268 19.435 45.897 19.643 ;
     RECT  0.432 20.731 0.45 20.875 ;
     RECT  0.288 20.875 0.45 20.909 ;
     RECT  0.288 20.909 0.378 21.005 ;
     RECT  0.36 21.005 0.378 21.053 ;
     RECT  2.304 19.643 45.897 22.651 ;
     RECT  2.268 22.651 45.897 23.045 ;
     RECT  2.304 23.045 45.897 23.803 ;
     RECT  2.268 23.803 45.897 23.855 ;
     RECT  2.304 23.855 45.897 24.763 ;
     RECT  2.268 24.763 45.897 26.285 ;
     RECT  2.304 26.285 45.897 26.941 ;
     RECT  2.304 26.941 46.278 27.019 ;
     RECT  2.268 27.019 46.278 27.365 ;
     RECT  0.252 27.499 0.27 27.629 ;
     RECT  2.304 27.365 46.278 28.123 ;
     RECT  2.268 28.123 46.278 28.985 ;
     RECT  2.304 28.985 46.278 30.235 ;
     RECT  2.268 30.235 46.278 30.605 ;
     RECT  0.252 29.899 0.27 30.749 ;
     RECT  2.304 30.605 46.278 30.811 ;
     RECT  0.216 31.771 0.234 31.901 ;
     RECT  2.304 30.811 46.386 32.881 ;
     RECT  2.268 32.881 46.386 33.005 ;
     RECT  2.304 33.005 46.386 33.853 ;
     RECT  2.304 33.853 46.782 34.079 ;
     RECT  2.304 34.079 46.638 34.603 ;
     RECT  2.268 34.603 46.638 34.619 ;
     RECT  2.268 34.619 46.422 35.581 ;
     RECT  2.268 35.581 46.494 35.597 ;
     RECT  2.304 35.597 46.494 35.671 ;
     RECT  0.216 35.815 0.234 35.933 ;
     RECT  2.304 35.671 46.638 36.391 ;
     RECT  2.304 36.391 46.746 36.509 ;
     RECT  2.304 36.509 46.71 36.895 ;
     RECT  2.016 36.895 46.71 38.011 ;
     RECT  0.216 38.299 0.234 39.245 ;
     RECT  2.016 38.011 46.782 39.595 ;
     RECT  2.016 39.595 46.854 39.793 ;
     RECT  2.016 39.793 46.998 40.019 ;
     RECT  2.016 40.019 46.854 40.289 ;
     RECT  2.016 40.289 46.818 42.061 ;
     RECT  2.016 42.061 46.962 42.223 ;
     RECT  2.016 42.223 47.106 42.449 ;
     RECT  0.216 41.467 0.234 42.893 ;
     RECT  2.016 42.449 46.962 43.411 ;
     RECT  0.252 44.299 0.27 44.429 ;
     RECT  0.216 45.883 0.234 46.013 ;
     RECT  2.016 43.411 47.286 46.615 ;
     RECT  2.016 46.615 47.358 46.949 ;
     RECT  2.016 46.949 47.286 47.821 ;
     RECT  0.252 48.187 0.81 48.317 ;
     RECT  2.016 47.821 47.358 48.739 ;
     RECT  2.016 48.739 47.466 49.081 ;
     RECT  2.016 49.081 47.502 49.243 ;
     RECT  2.016 49.243 47.538 49.351 ;
     RECT  1.872 49.351 47.538 49.549 ;
     RECT  48.315 2.413 48.597 49.549 ;
     RECT  0.792 48.317 0.81 52.267 ;
     RECT  0.252 52.267 0.81 52.397 ;
     RECT  0.288 52.397 0.81 53.941 ;
     RECT  1.872 49.549 48.597 54.599 ;
     RECT  0.288 53.941 1.062 55.579 ;
     RECT  0.216 55.579 1.062 55.709 ;
     RECT  1.872 54.599 47.538 56.641 ;
     RECT  48.315 54.599 48.597 56.641 ;
     RECT  1.872 56.641 48.597 56.939 ;
     RECT  0.288 55.709 1.062 57.211 ;
     RECT  0.252 57.211 1.062 57.341 ;
     RECT  1.872 56.939 47.574 57.847 ;
     RECT  48.315 56.939 48.597 57.847 ;
     RECT  0.288 57.341 1.062 57.991 ;
     RECT  1.872 57.847 48.597 57.991 ;
     RECT  0.288 57.991 48.597 58.109 ;
     RECT  0.288 58.109 47.574 58.451 ;
     RECT  0.288 58.451 47.502 58.793 ;
     RECT  0.288 58.793 47.43 58.987 ;
     RECT  0.216 58.987 47.43 59.261 ;
     RECT  0.288 59.261 47.43 60.385 ;
     RECT  0.288 60.385 47.466 60.925 ;
     RECT  0.288 60.925 47.502 61.429 ;
     RECT  0.288 61.429 47.574 61.619 ;
     RECT  0.288 61.619 47.466 61.655 ;
     RECT  0.288 61.655 47.322 62.395 ;
     RECT  0.252 62.395 47.322 62.525 ;
     RECT  0.288 62.525 47.322 62.815 ;
     RECT  0.288 62.815 47.358 63.085 ;
     RECT  48.315 58.109 48.597 63.085 ;
     RECT  0.288 63.085 48.597 63.509 ;
     RECT  0.288 63.509 47.358 63.691 ;
     RECT  0.252 63.691 47.358 63.821 ;
     RECT  0.288 63.821 47.358 64.795 ;
     RECT  0.252 64.795 47.358 64.925 ;
     RECT  0.288 64.925 47.358 65.785 ;
     RECT  0.288 65.785 47.394 66.325 ;
     RECT  0.288 66.325 47.538 66.479 ;
     RECT  0.288 66.479 47.394 66.749 ;
     RECT  0.288 66.749 47.034 66.797 ;
     RECT  0.288 66.797 46.854 66.899 ;
     RECT  0.288 66.899 46.71 67.531 ;
     RECT  0.216 67.531 46.71 67.661 ;
     RECT  0.288 67.661 46.71 68.171 ;
     RECT  0.288 68.171 46.494 69.259 ;
     RECT  0.288 69.259 46.53 69.727 ;
     RECT  0.288 69.727 46.566 70.259 ;
     RECT  0.288 70.259 46.422 70.529 ;
     RECT  0.288 70.529 46.278 71.419 ;
     RECT  0.252 71.419 46.278 71.549 ;
     RECT  0.288 71.549 46.278 71.609 ;
     RECT  0.288 71.609 46.17 74.491 ;
     RECT  0.252 74.491 46.17 75.691 ;
     RECT  0.216 75.691 46.17 75.821 ;
     RECT  0.288 75.821 46.17 76.243 ;
     RECT  0.288 76.243 46.71 77.227 ;
     RECT  0.252 77.227 46.71 77.935 ;
     RECT  0.216 77.935 46.71 78.797 ;
     RECT  0.288 78.797 46.71 79.963 ;
     RECT  0.216 79.963 46.71 81.869 ;
     RECT  0.288 81.869 46.71 82.891 ;
     RECT  0.252 82.891 46.71 83.021 ;
     RECT  0.288 83.021 46.71 84.811 ;
     RECT  0.216 84.811 46.71 85.657 ;
     RECT  0.18 85.657 46.71 103.811 ;
     RECT  0.252 103.811 46.71 104.621 ;
     RECT  0.288 104.621 46.71 105.835 ;
     RECT  0.252 105.835 46.71 105.965 ;
     RECT  0.288 105.965 46.71 106.939 ;
     RECT  0.252 106.939 46.71 107.069 ;
     RECT  0.288 107.069 46.71 109.049 ;
     RECT  0.288 109.049 1.134 109.381 ;
     RECT  0.216 109.381 1.134 109.709 ;
     RECT  0.288 109.709 1.134 110.189 ;
     RECT  0.396 110.189 1.134 112.261 ;
     RECT  2.016 109.049 46.71 112.757 ;
     RECT  0.36 112.261 1.134 113.161 ;
     RECT  0.216 113.161 1.134 114.269 ;
     RECT  0.252 114.269 1.134 115.051 ;
     RECT  0.216 115.051 1.134 116.333 ;
     RECT  0.324 116.333 1.134 116.525 ;
     RECT  0.36 116.525 1.134 117.319 ;
     RECT  0.216 117.319 1.134 118.499 ;
     RECT  0.216 118.499 1.026 119.981 ;
     RECT  0.324 119.981 1.026 121.003 ;
     RECT  0.252 121.003 1.026 121.297 ;
     RECT  2.016 112.757 44.622 121.711 ;
     RECT  2.016 121.711 44.802 121.945 ;
     RECT  45.615 112.757 46.71 121.945 ;
     RECT  0.216 121.297 1.026 123.629 ;
     RECT  0.252 123.629 1.026 123.773 ;
     RECT  0.324 123.773 1.026 124.589 ;
     RECT  0.36 124.589 1.026 125.383 ;
     RECT  0.216 125.383 1.026 125.419 ;
     RECT  0.216 125.419 1.206 125.519 ;
     RECT  0.216 125.519 1.17 126.301 ;
     RECT  2.016 121.945 46.71 126.427 ;
     RECT  0.216 126.301 1.206 126.491 ;
     RECT  2.016 126.427 46.89 126.689 ;
     RECT  0.216 126.491 1.17 127.325 ;
     RECT  2.016 126.689 46.746 127.651 ;
     RECT  0.252 127.325 1.17 127.769 ;
     RECT  0.252 127.769 0.558 128.191 ;
     RECT  0.216 128.191 0.558 128.635 ;
     RECT  0.216 128.635 1.17 128.765 ;
     RECT  2.016 127.651 46.782 129.029 ;
     RECT  2.16 129.029 46.782 129.235 ;
     RECT  2.16 129.235 47.25 129.271 ;
     RECT  48.315 63.509 48.597 129.271 ;
     RECT  2.16 129.271 48.597 129.659 ;
     RECT  0.216 128.765 0.558 129.725 ;
     RECT  2.232 129.659 48.597 129.965 ;
     RECT  2.232 129.965 47.358 130.199 ;
     RECT  0.36 129.725 0.558 130.699 ;
     RECT  2.232 130.199 47.25 130.739 ;
     RECT  0.252 130.699 0.558 130.987 ;
     RECT  0.216 130.987 0.558 131.117 ;
     RECT  2.232 130.739 46.746 131.459 ;
     RECT  0.36 131.117 0.558 131.971 ;
     RECT  2.268 131.459 46.746 132.241 ;
     RECT  0.324 131.971 0.558 132.403 ;
     RECT  2.268 132.241 46.998 132.763 ;
     RECT  2.232 132.763 46.998 133.051 ;
     RECT  2.232 133.051 47.106 133.079 ;
     RECT  2.268 133.079 47.106 133.781 ;
     RECT  2.268 133.781 47.07 133.861 ;
     RECT  2.232 133.861 47.07 133.949 ;
     RECT  2.268 133.949 47.07 135.031 ;
     RECT  0.216 132.403 0.558 135.211 ;
     RECT  0.216 135.211 0.594 135.389 ;
     RECT  2.268 135.031 47.286 135.841 ;
     RECT  2.232 135.841 47.286 136.205 ;
     RECT  2.268 136.205 47.286 137.227 ;
     RECT  0.216 135.389 0.558 137.261 ;
     RECT  0.396 137.261 0.558 137.399 ;
     RECT  2.268 137.227 47.574 137.605 ;
     RECT  48.315 129.965 48.597 137.605 ;
     RECT  0.432 137.399 0.558 138.271 ;
     RECT  2.268 137.605 48.597 138.569 ;
     RECT  0.216 138.271 0.558 138.797 ;
     RECT  2.268 138.569 47.25 139.109 ;
     RECT  0.396 138.797 0.558 140.161 ;
     RECT  2.268 139.109 47.214 140.341 ;
     RECT  2.268 140.341 47.466 140.539 ;
     RECT  0.216 140.161 0.558 140.909 ;
     RECT  0.252 140.909 0.558 141.067 ;
     RECT  0.252 141.067 1.17 141.197 ;
     RECT  2.232 140.539 47.466 141.385 ;
     RECT  2.232 141.385 47.574 141.719 ;
     RECT  2.268 141.719 47.574 141.781 ;
     RECT  48.315 138.569 48.597 141.781 ;
     RECT  2.268 141.781 48.597 141.917 ;
     RECT  2.268 141.917 47.394 141.953 ;
     RECT  0.252 141.197 0.558 142.591 ;
     RECT  0.252 142.591 1.17 142.663 ;
     RECT  0.216 142.663 1.17 142.691 ;
     RECT  2.268 141.953 47.322 142.771 ;
     RECT  2.268 142.771 47.43 143.041 ;
     RECT  48.315 141.917 48.597 143.041 ;
     RECT  0.216 142.691 0.558 143.453 ;
     RECT  2.268 143.041 48.597 143.501 ;
     RECT  0.36 143.453 0.558 144.211 ;
     RECT  2.268 143.501 47.43 144.391 ;
     RECT  48.315 143.501 48.597 144.391 ;
     RECT  2.268 144.391 48.597 144.553 ;
     RECT  2.232 144.553 48.597 144.653 ;
     RECT  2.232 144.653 47.286 144.749 ;
     RECT  2.268 144.749 47.286 145.741 ;
     RECT  48.315 144.653 48.597 145.741 ;
     RECT  0.216 144.211 0.558 147.047 ;
     RECT  0.324 147.047 0.558 147.056 ;
     RECT  2.268 145.741 48.597 147.353 ;
     RECT  2.268 147.353 47.286 148.361 ;
     RECT  2.268 148.361 43.758 148.459 ;
     RECT  2.232 148.459 43.758 148.559 ;
     RECT  0.432 147.056 0.558 148.651 ;
     RECT  0.252 148.651 0.558 148.781 ;
     RECT  44.496 148.361 47.286 148.937 ;
     RECT  2.268 148.559 43.758 149.419 ;
     RECT  44.496 148.937 47.25 149.419 ;
     RECT  0.36 148.781 0.558 149.611 ;
     RECT  2.268 149.419 47.25 150.449 ;
     RECT  2.268 150.449 47.142 151.871 ;
     RECT  0.216 149.611 0.558 152.045 ;
     RECT  0.252 152.045 0.558 152.333 ;
     RECT  2.268 151.871 47.034 152.609 ;
     RECT  2.268 152.609 46.998 152.753 ;
     RECT  2.268 152.753 46.962 152.789 ;
     RECT  2.268 152.789 46.926 152.879 ;
     RECT  2.268 152.879 46.89 153.491 ;
     RECT  2.268 153.491 46.854 153.725 ;
     RECT  2.268 153.725 46.782 154.027 ;
     RECT  0.468 152.333 0.558 154.309 ;
     RECT  0.216 154.309 0.558 154.315 ;
     RECT  2.232 154.027 46.782 154.337 ;
     RECT  0.216 154.315 1.17 154.741 ;
     RECT  0.216 154.741 1.206 154.777 ;
     RECT  0.216 154.777 1.278 154.913 ;
     RECT  2.268 154.337 46.782 155.039 ;
     RECT  23.688 155.039 46.782 155.047 ;
     RECT  23.688 155.047 46.818 155.119 ;
     RECT  23.688 155.119 46.89 155.309 ;
     RECT  23.796 155.309 46.89 155.345 ;
     RECT  23.868 155.345 46.89 155.353 ;
     RECT  23.868 155.353 47.286 155.579 ;
     RECT  0.216 154.913 0.558 155.741 ;
     RECT  0.396 155.741 0.558 155.929 ;
     RECT  0.396 155.929 1.17 156.029 ;
     RECT  2.268 155.039 22.878 156.271 ;
     RECT  2.268 156.271 23.058 156.331 ;
     RECT  23.868 155.579 47.214 156.331 ;
     RECT  2.268 156.331 47.214 156.533 ;
     RECT  0.396 156.029 0.558 156.893 ;
     RECT  0.432 156.893 0.558 157.373 ;
     RECT  2.268 156.533 46.854 158.125 ;
     RECT  2.268 158.125 46.89 158.152 ;
     RECT  2.232 158.152 46.89 158.359 ;
     RECT  2.232 158.359 46.998 158.665 ;
     RECT  2.232 158.665 47.322 158.891 ;
     RECT  2.268 158.891 47.322 159.089 ;
     RECT  2.268 159.089 46.818 159.701 ;
     RECT  0.468 157.373 0.558 160.051 ;
     RECT  0.432 160.051 0.558 160.253 ;
     RECT  2.268 159.701 46.674 160.555 ;
     RECT  0.468 160.253 0.558 161.179 ;
     RECT  0.216 161.179 0.558 161.309 ;
     RECT  2.268 160.555 46.854 161.401 ;
     RECT  2.268 161.401 47.178 161.663 ;
     RECT  0.252 161.309 0.558 162.031 ;
     RECT  2.268 161.663 46.962 162.167 ;
     RECT  2.268 162.167 46.818 162.985 ;
     RECT  0.216 162.031 0.558 163.013 ;
     RECT  2.268 162.985 46.998 163.553 ;
     RECT  23.184 163.553 46.998 163.823 ;
     RECT  23.184 163.823 46.782 164.045 ;
     RECT  0.216 163.013 0.486 164.141 ;
     RECT  2.268 163.553 22.446 164.731 ;
     RECT  23.292 164.045 46.782 164.731 ;
     RECT  2.232 164.731 22.446 164.779 ;
     RECT  2.232 164.779 22.554 164.861 ;
     RECT  0.468 164.141 0.486 164.923 ;
     RECT  2.268 164.861 22.554 165.001 ;
     RECT  23.292 164.731 46.818 165.001 ;
     RECT  2.268 165.001 46.818 165.029 ;
     RECT  0.252 164.923 0.486 165.037 ;
     RECT  23.796 165.029 46.818 165.443 ;
     RECT  23.796 165.443 46.71 165.569 ;
     RECT  0.252 165.037 0.558 165.725 ;
     RECT  23.796 165.569 46.134 165.911 ;
     RECT  0.468 165.725 0.558 165.917 ;
     RECT  2.268 165.029 23.058 165.991 ;
     RECT  23.796 165.911 40.878 165.991 ;
     RECT  0.468 165.917 0.486 166.019 ;
     RECT  41.616 165.911 46.134 166.019 ;
     RECT  2.268 165.991 40.878 166.765 ;
     RECT  41.616 166.019 45.897 166.765 ;
     RECT  2.268 166.765 45.954 167.099 ;
     RECT  0.216 166.963 0.234 167.323 ;
     RECT  2.304 167.099 45.954 167.459 ;
     RECT  0.216 167.323 0.27 167.693 ;
     RECT  0.54 168.043 0.558 168.475 ;
     RECT  0.252 168.475 0.558 168.605 ;
     RECT  0.54 168.605 0.558 168.845 ;
     RECT  2.304 167.459 45.897 169.385 ;
     RECT  2.304 169.385 43.197 169.493 ;
     RECT  44.46 169.385 44.478 169.493 ;
     RECT  2.304 169.493 41.202 169.619 ;
     RECT  41.976 169.493 43.197 169.661 ;
     RECT  0.252 169.627 0.27 169.805 ;
     RECT  2.304 169.619 40.662 170.033 ;
     RECT  42.696 169.661 43.197 170.069 ;
     RECT  2.304 170.033 40.497 170.699 ;
     RECT  0.216 170.587 0.234 170.765 ;
     RECT  2.415 170.699 40.497 170.969 ;
     RECT  8.856 170.969 40.497 171.011 ;
     RECT  8.856 171.011 33.462 171.113 ;
     RECT  8.856 171.113 33.318 171.149 ;
     RECT  8.856 171.149 9.558 171.275 ;
     RECT  10.404 171.149 33.318 171.275 ;
     RECT  8.892 171.275 9.558 171.509 ;
     RECT  10.44 171.275 33.318 171.509 ;
     RECT  2.415 170.969 8.097 171.581 ;
     RECT  10.44 171.509 33.246 171.779 ;
     RECT  6.372 171.581 8.097 171.887 ;
     RECT  18.432 171.779 33.246 171.887 ;
     RECT  10.44 171.779 17.658 171.923 ;
     RECT  21.315 171.887 33.246 171.968 ;
     RECT  34.2 171.011 40.497 172.027 ;
     RECT  10.44 171.923 11.61 172.049 ;
     RECT  12.384 171.923 17.658 172.049 ;
     RECT  21.315 171.968 27.342 172.049 ;
     RECT  28.116 171.968 33.246 172.049 ;
     RECT  34.02 172.027 40.497 172.061 ;
     RECT  8.964 171.509 9.558 172.085 ;
     RECT  12.492 172.049 17.658 172.085 ;
     RECT  21.315 172.049 23.022 172.085 ;
     RECT  30.888 172.049 33.246 172.085 ;
     RECT  18.432 171.887 20.574 172.121 ;
     RECT  24.015 172.049 26.997 172.121 ;
     RECT  9.396 172.085 9.558 172.165 ;
     RECT  28.116 172.049 28.638 172.193 ;
     RECT  6.84 171.887 8.097 172.291 ;
     RECT  10.44 172.049 11.466 172.315 ;
     RECT  6.84 172.291 8.658 172.319 ;
     RECT  9.396 172.165 9.594 172.319 ;
     RECT  12.78 172.085 17.658 172.319 ;
     RECT  18.432 172.121 20.322 172.319 ;
     RECT  24.015 172.121 25.866 172.319 ;
     RECT  26.64 172.121 26.997 172.319 ;
     RECT  28.116 172.193 28.206 172.319 ;
     RECT  30.888 172.085 33.21 172.319 ;
     RECT  7.815 172.319 8.658 172.349 ;
     RECT  10.404 172.315 11.466 172.355 ;
     RECT  22.644 172.085 23.022 172.355 ;
     RECT  24.015 172.319 24.354 172.355 ;
     RECT  28.116 172.319 28.134 172.355 ;
     RECT  30.888 172.319 32.886 172.355 ;
     RECT  34.02 172.061 36.522 172.355 ;
     RECT  18.432 172.319 19.674 172.391 ;
     RECT  22.824 172.355 22.842 172.427 ;
     RECT  7.815 172.349 8.097 172.547 ;
     RECT  12.78 172.319 13.497 172.547 ;
     RECT  21.315 172.085 21.597 172.547 ;
     RECT  24.015 172.355 24.297 172.547 ;
     RECT  26.715 172.319 26.997 172.547 ;
     RECT  37.515 172.061 40.497 172.547 ;
     RECT  42.915 170.069 43.197 172.547 ;
     RECT  45.615 169.385 45.897 172.547 ;
     RECT  48.315 147.353 48.597 172.547 ;
     RECT  51.015 2.413 51.297 172.547 ;
     RECT  53.715 2.413 53.997 172.547 ;
     RECT  56.415 2.413 56.697 172.547 ;
     RECT  59.115 2.413 59.397 172.547 ;
     RECT  61.815 2.413 62.097 172.547 ;
     RECT  64.515 2.413 64.797 172.547 ;
     RECT  67.215 2.413 67.497 172.547 ;
     RECT  69.915 2.413 70.197 172.547 ;
     RECT  72.615 2.413 72.897 172.547 ;
     RECT  75.315 2.413 75.597 172.547 ;
     RECT  78.015 2.413 78.297 172.547 ;
     RECT  80.715 2.413 80.997 172.547 ;
     RECT  83.415 2.413 83.697 172.547 ;
     RECT  86.115 2.413 86.397 172.547 ;
     RECT  88.815 2.413 89.097 172.547 ;
     RECT  91.515 2.413 91.797 172.547 ;
     RECT  94.215 2.413 94.497 172.547 ;
     RECT  96.915 2.413 97.197 172.547 ;
     RECT  99.615 2.413 99.897 172.547 ;
     RECT  102.315 2.413 102.597 172.547 ;
     RECT  105.015 2.413 105.297 172.547 ;
     RECT  107.715 2.413 107.997 172.547 ;
     RECT  110.415 2.413 110.697 172.547 ;
     RECT  113.115 2.413 113.397 172.547 ;
     RECT  115.815 2.413 116.097 172.547 ;
     RECT  118.515 2.413 118.797 172.547 ;
     RECT  121.215 2.413 121.497 172.547 ;
     RECT  123.915 2.413 124.197 172.547 ;
     RECT  126.615 2.413 126.897 172.547 ;
     RECT  2.415 171.581 5.454 172.589 ;
     RECT  7.815 172.547 7.938 172.589 ;
     RECT  10.476 172.355 11.466 172.589 ;
     RECT  12.78 172.547 13.374 172.589 ;
     RECT  14.22 172.319 14.238 172.589 ;
     RECT  18.615 172.391 19.674 172.589 ;
     RECT  29.415 172.049 30.078 172.589 ;
     RECT  31.032 172.355 32.886 172.589 ;
     RECT  34.02 172.355 36.162 172.589 ;
     RECT  38.412 172.547 40.305 172.589 ;
     RECT  3.348 172.589 5.205 172.625 ;
     RECT  10.476 172.589 10.605 172.625 ;
     RECT  15.915 172.319 17.154 172.625 ;
     RECT  18.615 172.589 18.738 172.625 ;
     RECT  29.415 172.589 29.97 172.625 ;
     RECT  31.032 172.589 31.05 172.625 ;
     RECT  32.115 172.589 32.814 172.625 ;
     RECT  34.815 172.589 36.162 172.625 ;
     RECT  38.952 172.589 39.366 172.625 ;
     RECT  3.42 172.625 3.438 172.661 ;
     RECT  4.176 172.625 5.205 172.661 ;
     RECT  17.136 172.625 17.154 172.661 ;
     RECT  38.952 172.625 38.97 172.661 ;
     RECT  2.415 172.589 2.505 172.817 ;
     RECT  5.115 172.661 5.205 172.817 ;
     RECT  7.815 172.589 7.905 172.817 ;
     RECT  10.515 172.625 10.605 172.817 ;
     RECT  13.215 172.589 13.305 172.817 ;
     RECT  15.915 172.625 16.005 172.817 ;
     RECT  18.615 172.625 18.705 172.817 ;
     RECT  21.315 172.547 21.405 172.817 ;
     RECT  24.015 172.547 24.105 172.817 ;
     RECT  26.715 172.547 26.805 172.817 ;
     RECT  29.415 172.625 29.505 172.817 ;
     RECT  32.115 172.625 32.205 172.817 ;
     RECT  34.815 172.625 34.905 172.817 ;
     RECT  37.515 172.547 37.605 172.817 ;
     RECT  40.215 172.589 40.305 172.817 ;
     RECT  42.915 172.547 43.005 172.817 ;
     RECT  45.615 172.547 45.705 172.817 ;
     RECT  48.315 172.547 48.405 172.817 ;
     RECT  51.015 172.547 51.105 172.817 ;
     RECT  53.715 172.547 53.805 172.817 ;
     RECT  56.415 172.547 56.505 172.817 ;
     RECT  59.115 172.547 59.205 172.817 ;
     RECT  61.815 172.547 61.905 172.817 ;
     RECT  64.515 172.547 64.605 172.817 ;
     RECT  67.215 172.547 67.305 172.817 ;
     RECT  69.915 172.547 70.005 172.817 ;
     RECT  72.615 172.547 72.705 172.817 ;
     RECT  75.315 172.547 75.405 172.817 ;
     RECT  78.015 172.547 78.105 172.817 ;
     RECT  80.715 172.547 80.805 172.817 ;
     RECT  83.415 172.547 83.505 172.817 ;
     RECT  86.115 172.547 86.205 172.817 ;
     RECT  88.815 172.547 88.905 172.817 ;
     RECT  91.515 172.547 91.605 172.817 ;
     RECT  94.215 172.547 94.305 172.817 ;
     RECT  96.915 172.547 97.005 172.817 ;
     RECT  99.615 172.547 99.705 172.817 ;
     RECT  102.315 172.547 102.405 172.817 ;
     RECT  105.015 172.547 105.105 172.817 ;
     RECT  107.715 172.547 107.805 172.817 ;
     RECT  110.415 172.547 110.505 172.817 ;
     RECT  113.115 172.547 113.205 172.817 ;
     RECT  115.815 172.547 115.905 172.817 ;
     RECT  118.515 172.547 118.605 172.817 ;
     RECT  121.215 172.547 121.305 172.817 ;
     RECT  123.915 172.547 124.005 172.817 ;
     RECT  126.615 172.547 126.705 172.817 ;
    LAYER M4 ;
     RECT  0.156 4.416 0.205 170.616 ;
     RECT  0.205 4.416 0.281 170.76 ;
     RECT  0.281 89.76 0.605 170.76 ;
     RECT  0.281 4.416 1.669 88.776 ;
     RECT  0.605 89.76 1.669 99.528 ;
     RECT  1.669 4.416 2.408 99.528 ;
     RECT  0.605 100.512 2.408 170.76 ;
     RECT  2.408 2.148 2.512 172.812 ;
     RECT  2.512 2.418 2.704 172.632 ;
     RECT  2.704 31.776 2.765 32.04 ;
     RECT  2.704 39.216 2.765 52.728 ;
     RECT  2.704 60.384 2.765 171 ;
     RECT  2.765 39.216 2.801 52.584 ;
     RECT  2.704 7.632 2.837 9.096 ;
     RECT  2.765 60.384 2.837 150.696 ;
     RECT  2.765 151.824 2.837 171 ;
     RECT  2.837 8.208 2.873 9.096 ;
     RECT  2.704 10.128 2.873 11.736 ;
     RECT  2.704 12.816 2.873 20.952 ;
     RECT  2.704 29.472 2.873 30.648 ;
     RECT  2.765 31.776 2.873 31.896 ;
     RECT  2.837 60.384 2.873 111.72 ;
     RECT  2.873 12.864 3.017 20.952 ;
     RECT  2.873 29.472 3.017 30.072 ;
     RECT  3.017 12.864 3.125 20.904 ;
     RECT  3.125 12.864 3.197 19.896 ;
     RECT  2.704 2.88 3.299 2.904 ;
     RECT  2.837 112.8 3.305 150.696 ;
     RECT  2.704 24.48 3.341 28.488 ;
     RECT  2.873 60.384 3.347 64.392 ;
     RECT  2.704 4.368 3.377 5.832 ;
     RECT  3.305 112.8 3.413 135.384 ;
     RECT  3.197 12.864 3.449 18.456 ;
     RECT  2.704 53.76 3.665 59.256 ;
     RECT  2.873 10.128 3.697 10.296 ;
     RECT  3.665 53.76 3.737 55.992 ;
     RECT  2.801 39.216 3.769 44.472 ;
     RECT  3.665 57.216 3.779 59.256 ;
     RECT  2.704 34.8 3.805 36.36 ;
     RECT  2.837 162.96 3.805 168.12 ;
     RECT  2.837 169.152 3.805 171 ;
     RECT  2.873 8.208 3.841 8.472 ;
     RECT  3.017 29.472 3.841 29.544 ;
     RECT  3.805 34.656 3.841 36.36 ;
     RECT  2.704 172.128 3.881 172.632 ;
     RECT  3.841 34.224 3.913 36.408 ;
     RECT  3.347 64.128 3.913 64.392 ;
     RECT  2.873 65.376 3.913 77.064 ;
     RECT  2.873 78.096 3.913 111.72 ;
     RECT  3.413 112.8 3.913 135.144 ;
     RECT  2.873 31.872 3.949 31.896 ;
     RECT  3.913 33.84 3.949 36.408 ;
     RECT  3.805 162.96 3.949 171 ;
     RECT  3.125 20.88 3.985 20.904 ;
     RECT  2.704 22.224 3.985 22.344 ;
     RECT  3.341 24.48 3.985 27.912 ;
     RECT  2.704 37.44 3.985 37.512 ;
     RECT  3.913 64.128 3.985 77.064 ;
     RECT  3.913 78.096 3.985 135.144 ;
     RECT  3.985 64.128 4.019 135.144 ;
     RECT  3.769 39.12 4.021 44.472 ;
     RECT  2.801 45.648 4.021 52.584 ;
     RECT  3.377 4.368 4.025 4.392 ;
     RECT  3.949 162.96 4.097 171.048 ;
     RECT  4.021 30.672 4.129 30.696 ;
     RECT  3.949 31.872 4.129 31.944 ;
     RECT  4.097 162.96 4.129 163.224 ;
     RECT  3.449 12.864 4.165 14.664 ;
     RECT  3.841 29.232 4.165 29.544 ;
     RECT  4.129 30.672 4.165 31.944 ;
     RECT  4.021 39.12 4.165 52.584 ;
     RECT  3.841 8.208 4.201 8.808 ;
     RECT  3.697 9.936 4.201 10.296 ;
     RECT  2.873 11.712 4.201 11.736 ;
     RECT  3.197 19.872 4.201 19.896 ;
     RECT  3.985 20.88 4.201 21.144 ;
     RECT  4.201 19.824 4.237 21.144 ;
     RECT  3.985 22.224 4.237 27.912 ;
     RECT  3.985 37.44 4.237 37.656 ;
     RECT  3.305 136.56 4.273 150.696 ;
     RECT  3.377 5.808 4.345 5.832 ;
     RECT  4.019 65.376 4.381 135.144 ;
     RECT  4.273 136.56 4.381 150.84 ;
     RECT  4.381 65.376 4.405 150.84 ;
     RECT  2.837 152.112 4.405 161.832 ;
     RECT  4.201 8.208 4.417 11.736 ;
     RECT  4.165 12.768 4.417 14.664 ;
     RECT  4.237 19.824 4.417 27.912 ;
     RECT  4.165 29.232 4.417 31.944 ;
     RECT  3.949 33.552 4.417 36.408 ;
     RECT  3.779 57.312 4.417 59.256 ;
     RECT  3.347 60.384 4.417 63.144 ;
     RECT  4.097 164.256 4.417 171.048 ;
     RECT  4.345 5.76 4.453 5.832 ;
     RECT  4.417 57.312 4.453 63.144 ;
     RECT  4.019 64.128 4.453 64.344 ;
     RECT  3.449 15.792 4.489 18.456 ;
     RECT  4.417 19.632 4.489 27.912 ;
     RECT  4.453 5.76 4.525 6.312 ;
     RECT  4.417 8.208 4.525 14.664 ;
     RECT  4.417 29.232 4.525 36.408 ;
     RECT  4.165 39.024 4.525 52.584 ;
     RECT  4.525 7.344 4.561 14.664 ;
     RECT  4.489 15.792 4.561 27.912 ;
     RECT  4.345 3.408 4.597 3.432 ;
     RECT  4.405 65.376 4.597 161.832 ;
     RECT  4.129 162.912 4.597 163.224 ;
     RECT  4.561 7.344 4.669 27.912 ;
     RECT  4.525 28.944 4.669 36.408 ;
     RECT  4.669 7.344 4.741 36.408 ;
     RECT  4.237 37.392 4.741 37.656 ;
     RECT  4.525 38.736 4.741 52.584 ;
     RECT  4.417 164.256 4.885 171.096 ;
     RECT  3.881 172.608 4.885 172.632 ;
     RECT  4.525 5.28 5.065 6.312 ;
     RECT  4.741 7.344 5.065 52.584 ;
     RECT  4.597 3.024 5.108 3.432 ;
     RECT  5.065 5.28 5.108 52.584 ;
     RECT  3.737 53.76 5.108 55.272 ;
     RECT  4.7 56.304 5.108 56.328 ;
     RECT  4.453 57.312 5.108 64.344 ;
     RECT  4.597 65.376 5.108 163.224 ;
     RECT  4.885 164.256 5.108 172.632 ;
     RECT  5.108 2.148 5.212 172.812 ;
     RECT  5.212 2.418 5.404 172.542 ;
     RECT  5.404 166.944 5.465 171.432 ;
     RECT  5.465 166.944 5.501 170.424 ;
     RECT  5.404 74.688 5.537 80.376 ;
     RECT  5.404 4.752 5.555 18.456 ;
     RECT  5.404 53.904 5.555 62.184 ;
     RECT  5.555 53.904 5.573 61.944 ;
     RECT  5.404 2.832 5.603 3.288 ;
     RECT  5.404 153.312 5.609 165.96 ;
     RECT  5.404 82.656 5.717 152.328 ;
     RECT  5.537 74.688 5.753 80.088 ;
     RECT  5.717 82.656 5.753 112.2 ;
     RECT  5.753 95.712 5.789 112.2 ;
     RECT  5.717 113.424 5.795 152.328 ;
     RECT  5.555 8.736 5.969 18.456 ;
     RECT  5.795 113.424 6.005 145.752 ;
     RECT  5.603 2.832 6.041 2.856 ;
     RECT  5.969 8.832 6.041 18.456 ;
     RECT  5.753 74.688 6.077 77.352 ;
     RECT  5.609 153.408 6.077 165.96 ;
     RECT  6.041 8.832 6.113 18.024 ;
     RECT  6.077 153.408 6.113 158.04 ;
     RECT  6.113 10.752 6.149 18.024 ;
     RECT  5.555 4.752 6.221 7.752 ;
     RECT  6.149 14.688 6.257 18.024 ;
     RECT  5.404 19.824 6.293 52.632 ;
     RECT  6.005 113.424 6.329 131.016 ;
     RECT  6.293 21.936 6.365 52.632 ;
     RECT  5.404 63.6 6.433 73.512 ;
     RECT  6.077 74.688 6.433 76.392 ;
     RECT  5.753 78.912 6.437 80.088 ;
     RECT  6.221 4.752 6.577 7.704 ;
     RECT  6.365 28.272 6.581 52.632 ;
     RECT  5.795 147.072 6.611 152.328 ;
     RECT  6.581 39.744 6.613 52.632 ;
     RECT  5.404 81.648 6.613 81.672 ;
     RECT  5.753 82.656 6.613 94.632 ;
     RECT  6.293 19.824 6.649 20.952 ;
     RECT  6.113 8.832 6.653 9.144 ;
     RECT  5.501 167.04 6.653 170.424 ;
     RECT  6.077 159.072 6.685 165.96 ;
     RECT  6.611 147.216 6.689 152.328 ;
     RECT  5.789 95.712 6.748 112.152 ;
     RECT  6.257 14.736 6.797 18.024 ;
     RECT  6.748 105.36 6.803 112.152 ;
     RECT  5.573 54.048 6.829 61.944 ;
     RECT  6.653 168.048 6.829 170.424 ;
     RECT  5.465 171.408 6.829 171.432 ;
     RECT  6.149 10.752 6.833 13.704 ;
     RECT  6.803 105.456 6.833 112.152 ;
     RECT  6.613 81.648 6.853 94.632 ;
     RECT  6.748 95.712 6.853 103.896 ;
     RECT  6.793 77.472 6.865 77.496 ;
     RECT  6.437 78.912 6.865 79.224 ;
     RECT  6.833 111.648 6.973 112.152 ;
     RECT  6.329 113.424 6.973 130.776 ;
     RECT  6.829 53.904 7.081 61.944 ;
     RECT  6.005 132.144 7.1 145.752 ;
     RECT  6.433 63.6 7.117 76.392 ;
     RECT  6.829 168.048 7.117 171.864 ;
     RECT  6.613 39.744 7.196 52.728 ;
     RECT  7.081 53.904 7.196 62.136 ;
     RECT  6.577 4.656 7.225 7.704 ;
     RECT  6.113 153.552 7.333 158.04 ;
     RECT  6.685 159.072 7.333 166.728 ;
     RECT  6.797 14.976 7.405 18.024 ;
     RECT  6.649 19.344 7.405 20.952 ;
     RECT  7.196 39.744 7.669 62.136 ;
     RECT  7.117 63.6 7.669 76.488 ;
     RECT  7.405 14.976 7.693 20.952 ;
     RECT  6.365 21.936 7.693 27.192 ;
     RECT  7.225 4.512 7.729 7.704 ;
     RECT  6.653 8.928 7.729 9.144 ;
     RECT  7.729 4.512 7.808 9.144 ;
     RECT  7.189 10.128 7.808 10.152 ;
     RECT  6.833 11.712 7.808 13.704 ;
     RECT  7.693 14.976 7.808 27.192 ;
     RECT  6.581 28.272 7.808 38.616 ;
     RECT  7.669 39.744 7.808 76.488 ;
     RECT  6.865 77.472 7.808 79.224 ;
     RECT  6.853 81.648 7.808 103.896 ;
     RECT  6.833 105.456 7.808 110.376 ;
     RECT  6.973 111.648 7.808 130.776 ;
     RECT  7.1 132 7.808 145.752 ;
     RECT  6.689 147.216 7.808 151.032 ;
     RECT  6.937 152.352 7.808 152.376 ;
     RECT  7.333 153.552 7.808 166.728 ;
     RECT  7.117 168.048 7.808 171.912 ;
     RECT  7.808 2.148 7.912 172.812 ;
     RECT  7.912 2.256 8.104 172.542 ;
     RECT  8.104 2.256 8.201 9.144 ;
     RECT  8.104 81.648 8.243 110.52 ;
     RECT  8.104 111.648 8.243 131.16 ;
     RECT  8.104 132.624 8.243 151.032 ;
     RECT  8.104 171.744 8.243 172.344 ;
     RECT  8.201 2.256 8.291 7.704 ;
     RECT  8.243 81.648 8.291 110.472 ;
     RECT  8.291 2.256 8.317 3.72 ;
     RECT  8.104 10.128 8.381 54.984 ;
     RECT  8.201 8.688 8.387 9.144 ;
     RECT  8.381 20.064 8.579 54.984 ;
     RECT  8.104 58.608 8.723 62.76 ;
     RECT  8.579 20.064 8.741 45.288 ;
     RECT  8.381 10.128 8.777 19.032 ;
     RECT  8.723 58.608 8.777 61.464 ;
     RECT  8.291 81.648 8.957 107.784 ;
     RECT  8.243 171.888 9.065 172.344 ;
     RECT  8.104 56.544 9.097 57.384 ;
     RECT  8.579 46.272 9.133 54.984 ;
     RECT  9.097 56.016 9.133 57.384 ;
     RECT  8.104 152.16 9.155 170.568 ;
     RECT  9.155 157.728 9.165 170.568 ;
     RECT  8.243 132.624 9.173 143.304 ;
     RECT  9.155 152.16 9.173 156.744 ;
     RECT  8.104 64.992 9.205 78.648 ;
     RECT  8.291 4.752 9.209 7.704 ;
     RECT  9.165 160.512 9.241 170.568 ;
     RECT  8.741 20.064 9.245 45 ;
     RECT  8.777 59.232 9.245 61.464 ;
     RECT  9.241 160.512 9.245 170.904 ;
     RECT  9.205 64.944 9.269 78.648 ;
     RECT  8.957 81.648 9.317 84.12 ;
     RECT  8.957 85.2 9.317 107.784 ;
     RECT  8.291 108.864 9.317 110.472 ;
     RECT  9.269 64.944 9.353 79.272 ;
     RECT  9.173 132.624 9.353 136.056 ;
     RECT  8.317 2.736 9.385 3.72 ;
     RECT  9.209 4.752 9.385 4.776 ;
     RECT  9.165 157.728 9.389 159.528 ;
     RECT  8.243 144.336 9.395 150.888 ;
     RECT  8.243 111.648 9.404 130.92 ;
     RECT  8.387 9.072 9.421 9.144 ;
     RECT  8.777 10.128 9.421 18.984 ;
     RECT  9.317 87.12 9.445 107.784 ;
     RECT  8.723 62.496 9.457 62.76 ;
     RECT  9.404 111.648 9.529 131.544 ;
     RECT  9.353 132.624 9.529 135.672 ;
     RECT  9.173 137.328 9.565 143.304 ;
     RECT  9.395 144.336 9.565 148.104 ;
     RECT  9.457 62.496 9.637 63.288 ;
     RECT  9.317 81.648 9.637 83.64 ;
     RECT  9.395 149.76 9.685 150.888 ;
     RECT  9.173 152.16 9.685 156.696 ;
     RECT  9.245 61.056 9.709 61.464 ;
     RECT  9.637 62.496 9.709 63.528 ;
     RECT  9.245 59.232 9.817 60.072 ;
     RECT  9.421 9.072 9.853 18.984 ;
     RECT  9.245 20.064 9.853 20.712 ;
     RECT  9.317 108.912 9.853 110.472 ;
     RECT  9.529 111.648 9.853 135.672 ;
     RECT  9.245 21.696 9.877 45 ;
     RECT  9.133 46.272 9.877 57.384 ;
     RECT  9.817 59.04 9.925 60.072 ;
     RECT  9.209 6.096 9.961 7.704 ;
     RECT  9.353 64.944 10.069 78.408 ;
     RECT  9.961 6.096 10.141 7.944 ;
     RECT  9.853 9.072 10.261 20.712 ;
     RECT  9.877 21.696 10.261 57.384 ;
     RECT  9.925 58.56 10.309 60.072 ;
     RECT  9.709 61.056 10.309 63.528 ;
     RECT  9.317 85.2 10.321 86.088 ;
     RECT  9.445 87.12 10.321 107.88 ;
     RECT  10.141 6.096 10.357 8.04 ;
     RECT  10.261 9.024 10.357 57.384 ;
     RECT  10.309 58.56 10.357 63.528 ;
     RECT  10.069 64.608 10.357 78.408 ;
     RECT  9.565 137.328 10.357 148.104 ;
     RECT  9.245 166.608 10.357 170.904 ;
     RECT  9.065 172.32 10.357 172.344 ;
     RECT  10.321 85.2 10.501 107.88 ;
     RECT  9.853 108.912 10.501 135.672 ;
     RECT  9.385 2.736 10.508 4.776 ;
     RECT  10.357 6.096 10.508 57.384 ;
     RECT  10.357 58.56 10.508 78.936 ;
     RECT  8.104 80.352 10.508 80.376 ;
     RECT  9.637 81.456 10.508 83.64 ;
     RECT  10.501 85.2 10.508 135.672 ;
     RECT  10.357 137.328 10.508 148.68 ;
     RECT  9.685 149.76 10.508 156.696 ;
     RECT  9.389 158.016 10.508 159.528 ;
     RECT  9.245 160.512 10.508 165.576 ;
     RECT  10.357 166.608 10.508 172.344 ;
     RECT  10.508 2.148 10.612 172.812 ;
     RECT  10.612 2.418 10.804 172.542 ;
     RECT  10.804 2.88 10.901 19.272 ;
     RECT  10.804 76.032 10.901 145.752 ;
     RECT  10.804 49.2 10.945 74.76 ;
     RECT  10.804 147.024 11.009 148.776 ;
     RECT  10.804 152.64 11.009 161.112 ;
     RECT  10.804 21.696 11.081 45.192 ;
     RECT  10.901 2.88 11.117 19.032 ;
     RECT  11.009 152.784 11.404 161.112 ;
     RECT  11.081 24.432 11.477 45.192 ;
     RECT  10.901 76.032 11.507 119.832 ;
     RECT  11.117 3.648 11.621 19.032 ;
     RECT  11.477 24.576 11.621 45.192 ;
     RECT  11.404 152.784 11.621 158.136 ;
     RECT  11.404 159.408 11.621 161.112 ;
     RECT  10.804 167.28 11.657 171.624 ;
     RECT  10.804 46.272 11.797 48.216 ;
     RECT  10.945 49.2 11.797 53.064 ;
     RECT  11.621 152.784 11.837 155.688 ;
     RECT  11.621 157.2 11.873 158.136 ;
     RECT  11.621 5.808 11.941 19.032 ;
     RECT  10.901 120.864 11.941 145.752 ;
     RECT  11.941 120.864 11.945 145.896 ;
     RECT  11.941 5.808 11.977 19.08 ;
     RECT  11.797 46.272 11.977 53.064 ;
     RECT  10.945 54.048 11.977 74.76 ;
     RECT  10.804 20.4 12.013 20.712 ;
     RECT  11.081 21.696 12.013 23.304 ;
     RECT  11.621 160.176 12.013 161.112 ;
     RECT  12.013 20.4 12.049 23.304 ;
     RECT  11.977 46.272 12.049 74.76 ;
     RECT  11.507 76.032 12.049 109.272 ;
     RECT  11.657 167.28 12.053 168.456 ;
     RECT  11.945 135.456 12.085 145.896 ;
     RECT  12.013 160.176 12.085 161.352 ;
     RECT  10.804 162.816 12.121 162.84 ;
     RECT  10.804 164.304 12.121 165.576 ;
     RECT  12.085 135.456 12.157 146.328 ;
     RECT  11.009 147.312 12.157 148.776 ;
     RECT  11.945 120.864 12.197 134.28 ;
     RECT  12.157 135.456 12.197 148.776 ;
     RECT  11.621 24.576 12.233 44.952 ;
     RECT  11.507 110.544 12.301 119.832 ;
     RECT  12.197 120.864 12.301 131.4 ;
     RECT  12.085 160.176 12.337 161.784 ;
     RECT  12.121 162.816 12.337 165.576 ;
     RECT  11.977 5.808 12.553 19.368 ;
     RECT  12.049 20.4 12.553 23.4 ;
     RECT  11.657 169.728 12.565 171.624 ;
     RECT  11.837 152.88 12.613 155.688 ;
     RECT  12.197 135.936 12.769 148.776 ;
     RECT  10.804 149.76 12.769 151.656 ;
     RECT  12.553 5.808 12.805 23.4 ;
     RECT  12.233 24.576 12.805 44.76 ;
     RECT  12.053 167.472 12.949 168.456 ;
     RECT  12.565 169.728 12.949 172.344 ;
     RECT  11.621 3.648 12.956 4.776 ;
     RECT  12.956 3.456 12.959 4.776 ;
     RECT  12.805 5.808 12.959 44.76 ;
     RECT  12.049 46.272 12.985 109.272 ;
     RECT  11.873 158.112 13.013 158.136 ;
     RECT  12.613 152.88 13.057 156.408 ;
     RECT  12.985 46.272 13.093 109.464 ;
     RECT  12.301 110.544 13.093 131.4 ;
     RECT  12.197 132.672 13.093 134.28 ;
     RECT  13.013 158.112 13.093 158.424 ;
     RECT  12.337 160.176 13.093 165.576 ;
     RECT  12.949 167.472 13.093 172.344 ;
     RECT  13.093 46.08 13.129 131.4 ;
     RECT  12.769 135.936 13.129 151.656 ;
     RECT  13.057 152.64 13.129 156.408 ;
     RECT  13.129 135.936 13.165 156.408 ;
     RECT  13.093 157.824 13.165 158.424 ;
     RECT  12.959 3.456 13.208 44.76 ;
     RECT  13.129 46.032 13.208 131.4 ;
     RECT  13.093 132.672 13.208 134.664 ;
     RECT  13.165 135.936 13.208 158.424 ;
     RECT  13.093 160.176 13.208 165.672 ;
     RECT  13.093 166.656 13.208 172.344 ;
     RECT  13.208 2.148 13.312 172.812 ;
     RECT  13.312 2.418 13.504 172.542 ;
     RECT  13.504 10.128 13.529 44.952 ;
     RECT  13.504 135.312 13.601 162.12 ;
     RECT  13.504 105.36 13.619 128.376 ;
     RECT  13.619 105.36 13.637 121.32 ;
     RECT  13.504 129.504 13.66 133.56 ;
     RECT  13.504 3.12 13.673 4.776 ;
     RECT  13.504 163.152 13.673 168.936 ;
     RECT  13.637 111.072 13.709 121.32 ;
     RECT  13.619 122.4 13.709 128.376 ;
     RECT  13.529 12.864 13.781 44.952 ;
     RECT  13.601 135.312 13.781 156.264 ;
     RECT  13.504 61.584 13.817 104.088 ;
     RECT  13.781 12.864 13.853 33.96 ;
     RECT  13.673 163.152 13.889 164.616 ;
     RECT  13.504 5.76 13.925 5.832 ;
     RECT  13.709 122.448 13.955 128.376 ;
     RECT  13.853 19.632 13.961 33.96 ;
     RECT  13.601 157.824 13.961 162.12 ;
     RECT  13.781 35.328 13.997 44.952 ;
     RECT  13.853 12.864 14.033 18.504 ;
     RECT  13.955 122.448 14.033 128.28 ;
     RECT  13.961 157.92 14.069 162.12 ;
     RECT  13.66 129.504 14.105 131.4 ;
     RECT  13.637 105.36 14.141 110.088 ;
     RECT  14.141 105.36 14.195 106.056 ;
     RECT  14.105 129.744 14.213 131.4 ;
     RECT  14.069 158.016 14.213 162.12 ;
     RECT  14.033 12.864 14.249 15.24 ;
     RECT  13.66 132.672 14.249 133.56 ;
     RECT  14.249 132.672 14.321 133.512 ;
     RECT  13.961 19.632 14.357 27.672 ;
     RECT  13.504 46.032 14.357 60.408 ;
     RECT  13.925 5.808 14.393 5.832 ;
     RECT  13.997 35.328 14.429 43.128 ;
     RECT  14.321 132.672 14.429 133.32 ;
     RECT  13.889 163.44 14.429 164.616 ;
     RECT  13.817 61.584 14.497 104.04 ;
     RECT  14.357 51.312 14.533 60.408 ;
     RECT  14.497 61.536 14.533 104.04 ;
     RECT  13.529 10.128 14.605 11.784 ;
     RECT  14.249 12.864 14.605 13.896 ;
     RECT  13.673 3.12 14.641 3.432 ;
     RECT  13.673 4.416 14.641 4.776 ;
     RECT  13.504 170.448 14.677 171.864 ;
     RECT  13.504 6.864 14.713 9.096 ;
     RECT  14.605 10.128 14.713 13.896 ;
     RECT  14.141 107.136 14.713 110.088 ;
     RECT  14.533 51.312 14.717 104.04 ;
     RECT  13.709 111.648 14.725 121.32 ;
     RECT  14.033 122.448 14.725 128.232 ;
     RECT  14.713 107.136 14.749 110.568 ;
     RECT  14.725 111.648 14.749 128.232 ;
     RECT  14.677 170.448 14.749 172.152 ;
     RECT  14.717 51.312 14.753 60.36 ;
     RECT  13.781 135.312 14.753 155.88 ;
     RECT  13.673 165.648 14.785 168.936 ;
     RECT  14.749 170.352 14.785 172.152 ;
     RECT  14.033 16.224 14.821 18.504 ;
     RECT  14.357 19.632 14.821 25.032 ;
     RECT  14.717 61.44 14.821 104.04 ;
     RECT  14.195 105.36 14.821 105.672 ;
     RECT  14.753 51.408 14.825 60.36 ;
     RECT  14.429 41.904 14.861 43.128 ;
     RECT  14.825 51.408 14.861 60.12 ;
     RECT  14.429 35.328 14.893 40.92 ;
     RECT  14.713 6.864 14.924 13.896 ;
     RECT  14.357 26.304 14.929 27.672 ;
     RECT  13.961 28.752 14.929 33.96 ;
     RECT  14.641 3.12 14.965 4.776 ;
     RECT  14.753 152.352 14.965 155.88 ;
     RECT  14.861 41.952 15.001 43.128 ;
     RECT  13.997 44.16 15.001 44.952 ;
     RECT  14.357 46.032 15.001 50.328 ;
     RECT  14.965 152.352 15.037 156.648 ;
     RECT  14.213 158.016 15.037 161.4 ;
     RECT  14.749 107.136 15.068 128.232 ;
     RECT  14.429 132.672 15.109 132.936 ;
     RECT  14.249 14.928 15.145 15.24 ;
     RECT  14.821 16.224 15.145 25.032 ;
     RECT  15.001 41.952 15.157 43.176 ;
     RECT  15.001 44.16 15.157 50.328 ;
     RECT  15.068 107.136 15.217 128.28 ;
     RECT  14.753 135.312 15.217 151.08 ;
     RECT  14.929 26.304 15.253 33.96 ;
     RECT  14.893 35.088 15.253 40.92 ;
     RECT  15.217 107.136 15.289 128.424 ;
     RECT  14.821 61.44 15.361 105.672 ;
     RECT  15.289 106.752 15.361 128.424 ;
     RECT  15.217 134.88 15.397 151.08 ;
     RECT  14.924 6.816 15.433 13.896 ;
     RECT  15.145 14.928 15.433 25.032 ;
     RECT  14.429 163.536 15.433 164.616 ;
     RECT  15.157 41.952 15.505 50.328 ;
     RECT  15.433 162.912 15.505 164.616 ;
     RECT  14.785 165.648 15.505 172.152 ;
     RECT  15.505 41.952 15.829 50.424 ;
     RECT  14.861 51.408 15.829 59.928 ;
     RECT  14.965 3.12 15.908 5.64 ;
     RECT  15.433 6.816 15.908 25.032 ;
     RECT  15.253 26.304 15.908 40.92 ;
     RECT  15.829 41.952 15.908 59.928 ;
     RECT  15.361 61.44 15.908 128.424 ;
     RECT  14.213 129.744 15.908 131.112 ;
     RECT  15.109 132.624 15.908 132.936 ;
     RECT  15.397 134.64 15.908 151.08 ;
     RECT  15.037 152.352 15.908 161.4 ;
     RECT  15.505 162.912 15.908 172.152 ;
     RECT  15.908 2.148 16.012 172.812 ;
     RECT  16.012 2.418 16.204 172.542 ;
     RECT  16.204 138.144 16.355 150.84 ;
     RECT  16.204 159.408 16.373 172.152 ;
     RECT  16.373 159.408 16.396 171.768 ;
     RECT  16.204 2.88 16.481 59.832 ;
     RECT  16.481 42.432 16.697 59.832 ;
     RECT  16.204 111.648 16.697 136.728 ;
     RECT  16.396 159.408 16.697 171.24 ;
     RECT  16.481 2.88 16.805 41.16 ;
     RECT  16.697 159.408 16.979 162.696 ;
     RECT  16.805 2.88 17.021 41.064 ;
     RECT  16.697 117.36 17.021 136.728 ;
     RECT  16.979 160.176 17.021 162.696 ;
     RECT  17.021 160.368 17.057 162.696 ;
     RECT  17.021 6.624 17.093 41.064 ;
     RECT  16.355 148.56 17.093 150.84 ;
     RECT  16.697 163.68 17.093 171.24 ;
     RECT  17.021 117.36 17.123 128.424 ;
     RECT  17.021 2.88 17.129 5.064 ;
     RECT  17.129 3.12 17.165 5.064 ;
     RECT  16.697 42.432 17.171 57.432 ;
     RECT  17.021 129.504 17.173 136.728 ;
     RECT  16.355 138.144 17.201 147.336 ;
     RECT  16.204 153.744 17.233 158.424 ;
     RECT  17.093 24.432 17.237 41.064 ;
     RECT  17.123 117.36 17.237 123.864 ;
     RECT  17.173 129.504 17.237 130.776 ;
     RECT  16.697 58.464 17.269 59.832 ;
     RECT  16.204 61.248 17.269 110.616 ;
     RECT  17.093 6.624 17.273 23.4 ;
     RECT  17.237 118.176 17.273 123.864 ;
     RECT  17.201 138.144 17.273 147.24 ;
     RECT  17.273 6.864 17.309 23.4 ;
     RECT  17.093 148.56 17.341 148.776 ;
     RECT  17.237 129.648 17.345 130.776 ;
     RECT  17.093 149.856 17.377 150.84 ;
     RECT  16.204 151.824 17.377 152.424 ;
     RECT  17.233 153.744 17.377 159.192 ;
     RECT  17.165 3.552 17.381 5.064 ;
     RECT  17.093 163.728 17.381 171.24 ;
     RECT  17.057 160.464 17.453 162.696 ;
     RECT  17.273 138.144 17.489 146.424 ;
     RECT  17.489 138.144 17.516 138.696 ;
     RECT  17.173 131.808 17.521 136.728 ;
     RECT  17.516 137.76 17.521 138.696 ;
     RECT  17.377 153.504 17.561 159.192 ;
     RECT  17.521 131.808 17.603 138.696 ;
     RECT  17.377 149.856 17.605 152.424 ;
     RECT  17.561 153.504 17.605 153.912 ;
     RECT  17.171 42.432 17.773 46.296 ;
     RECT  16.697 111.648 17.773 116.04 ;
     RECT  17.737 117.12 17.773 117.144 ;
     RECT  17.269 58.464 18.097 110.616 ;
     RECT  17.773 111.648 18.097 117.144 ;
     RECT  17.237 27.648 18.133 41.064 ;
     RECT  17.773 42.192 18.133 46.296 ;
     RECT  17.345 130.416 18.229 130.776 ;
     RECT  17.603 131.808 18.229 136.92 ;
     RECT  17.273 118.176 18.241 122.712 ;
     RECT  17.273 123.744 18.241 123.864 ;
     RECT  17.489 139.68 18.269 146.424 ;
     RECT  17.309 7.104 18.277 23.4 ;
     RECT  17.237 24.432 18.277 26.664 ;
     RECT  18.133 27.648 18.277 46.296 ;
     RECT  17.123 124.848 18.313 128.424 ;
     RECT  17.453 162.672 18.313 162.696 ;
     RECT  17.381 163.728 18.313 171.096 ;
     RECT  18.241 118.176 18.413 123.864 ;
     RECT  18.313 124.848 18.413 129.24 ;
     RECT  18.277 24.432 18.421 46.296 ;
     RECT  18.269 139.68 18.421 147.048 ;
     RECT  17.341 148.224 18.421 148.776 ;
     RECT  18.421 24.384 18.469 46.296 ;
     RECT  17.171 47.28 18.469 57.432 ;
     RECT  17.381 3.6 18.493 5.064 ;
     RECT  17.603 138.24 18.493 138.696 ;
     RECT  18.421 139.68 18.493 148.776 ;
     RECT  18.493 2.832 18.608 5.064 ;
     RECT  18.277 6.816 18.608 23.4 ;
     RECT  18.469 24.384 18.608 57.432 ;
     RECT  18.097 58.464 18.608 117.144 ;
     RECT  18.413 118.176 18.608 129.24 ;
     RECT  18.229 130.416 18.608 136.92 ;
     RECT  18.493 138.24 18.608 148.776 ;
     RECT  17.605 149.856 18.608 153.912 ;
     RECT  17.561 155.088 18.608 159.192 ;
     RECT  17.453 160.464 18.608 161.448 ;
     RECT  18.313 162.672 18.608 171.096 ;
     RECT  18.421 172.128 18.608 172.152 ;
     RECT  18.608 2.148 18.712 172.812 ;
     RECT  18.712 2.418 18.904 172.542 ;
     RECT  18.904 2.832 18.929 5.304 ;
     RECT  18.904 136.752 19.043 152.472 ;
     RECT  18.904 159.36 19.043 168.936 ;
     RECT  18.904 129.696 19.073 135.624 ;
     RECT  18.904 155.136 19.073 158.376 ;
     RECT  18.904 6.816 19.091 11.784 ;
     RECT  19.043 136.752 19.109 136.968 ;
     RECT  18.904 58.752 19.145 78.744 ;
     RECT  18.904 32.736 19.187 57.384 ;
     RECT  19.109 136.944 19.187 136.968 ;
     RECT  18.904 110.496 19.217 123.816 ;
     RECT  19.043 138.048 19.361 152.472 ;
     RECT  18.904 153.456 19.361 153.912 ;
     RECT  18.929 2.832 19.433 3.384 ;
     RECT  19.433 3.36 19.468 3.384 ;
     RECT  19.217 117.504 19.469 123.816 ;
     RECT  19.073 129.696 19.505 129.768 ;
     RECT  18.904 170.832 19.577 171.096 ;
     RECT  18.904 28.128 19.613 31.752 ;
     RECT  19.361 138.048 19.613 140.856 ;
     RECT  19.043 159.696 19.613 168.936 ;
     RECT  19.073 131.424 19.649 135.624 ;
     RECT  19.073 157.104 19.685 158.376 ;
     RECT  19.091 6.96 19.865 11.784 ;
     RECT  18.904 23.664 19.897 26.664 ;
     RECT  19.361 153.744 19.897 153.912 ;
     RECT  19.073 155.136 19.897 156.024 ;
     RECT  19.649 131.856 19.901 135.624 ;
     RECT  19.865 11.76 19.933 11.784 ;
     RECT  18.904 12.768 19.933 22.296 ;
     RECT  19.187 44.4 19.933 57.384 ;
     RECT  19.901 133.44 19.933 135.624 ;
     RECT  19.217 110.496 19.957 116.472 ;
     RECT  19.933 44.4 19.969 57.48 ;
     RECT  19.613 159.696 20.003 163.176 ;
     RECT  18.904 80.016 20.005 109.416 ;
     RECT  19.685 157.104 20.051 158.184 ;
     RECT  19.613 164.592 20.077 168.936 ;
     RECT  19.933 11.76 20.081 22.296 ;
     RECT  18.929 4.464 20.113 5.304 ;
     RECT  19.897 153.744 20.153 156.024 ;
     RECT  20.003 159.696 20.153 163.128 ;
     RECT  20.113 3.84 20.185 5.304 ;
     RECT  20.077 164.592 20.197 169.704 ;
     RECT  19.897 23.664 20.225 27 ;
     RECT  20.185 3.84 20.293 5.784 ;
     RECT  18.904 124.848 20.396 128.712 ;
     RECT  20.293 3.84 20.473 5.832 ;
     RECT  19.865 6.96 20.473 10.584 ;
     RECT  19.969 44.4 20.509 57.576 ;
     RECT  19.145 58.752 20.509 78.696 ;
     RECT  20.396 124.416 20.545 128.712 ;
     RECT  19.505 129.744 20.545 129.768 ;
     RECT  20.197 164.592 20.545 169.8 ;
     RECT  19.577 170.976 20.545 171.096 ;
     RECT  19.361 142.08 20.581 152.472 ;
     RECT  20.545 124.416 20.617 129.768 ;
     RECT  19.613 138.048 20.617 140.568 ;
     RECT  20.005 79.92 20.689 109.416 ;
     RECT  19.957 110.4 20.689 116.472 ;
     RECT  20.051 157.392 20.689 158.184 ;
     RECT  20.509 44.4 20.773 78.696 ;
     RECT  20.689 79.92 20.773 116.472 ;
     RECT  20.617 137.808 20.78 140.568 ;
     RECT  20.581 141.792 20.905 152.472 ;
     RECT  20.905 141.792 20.917 152.76 ;
     RECT  20.153 153.744 20.917 153.768 ;
     RECT  20.225 24.144 20.941 27 ;
     RECT  19.613 28.272 20.941 31.752 ;
     RECT  20.153 155.04 20.941 156.024 ;
     RECT  20.78 137.04 20.977 140.568 ;
     RECT  20.473 3.84 21.013 10.584 ;
     RECT  20.081 11.76 21.013 17.688 ;
     RECT  20.689 157.392 21.013 158.328 ;
     RECT  20.545 164.592 21.049 171.096 ;
     RECT  21.013 3.84 21.061 17.688 ;
     RECT  20.977 136.992 21.085 140.568 ;
     RECT  20.153 159.696 21.085 160.776 ;
     RECT  19.901 131.856 21.109 132.408 ;
     RECT  20.941 155.04 21.109 156.072 ;
     RECT  21.013 157.392 21.109 158.664 ;
     RECT  20.941 24.144 21.121 31.752 ;
     RECT  19.187 32.736 21.121 43.416 ;
     RECT  21.109 155.04 21.149 158.664 ;
     RECT  21.085 159.648 21.149 160.776 ;
     RECT  21.121 24.144 21.229 43.416 ;
     RECT  20.773 44.4 21.229 116.472 ;
     RECT  21.049 164.496 21.229 171.096 ;
     RECT  21.061 3.408 21.308 17.688 ;
     RECT  20.081 18.672 21.308 22.296 ;
     RECT  21.229 24.144 21.308 116.472 ;
     RECT  19.469 117.504 21.308 123.384 ;
     RECT  20.617 124.416 21.308 130.536 ;
     RECT  21.109 131.76 21.308 132.408 ;
     RECT  19.933 133.44 21.308 135.912 ;
     RECT  21.085 136.944 21.308 140.568 ;
     RECT  20.917 141.792 21.308 153.768 ;
     RECT  21.149 155.04 21.308 160.776 ;
     RECT  20.153 161.76 21.308 163.128 ;
     RECT  21.229 164.496 21.308 171.528 ;
     RECT  21.308 2.148 21.412 172.812 ;
     RECT  21.412 2.418 21.604 172.542 ;
     RECT  21.604 111.024 21.665 116.472 ;
     RECT  21.604 133.824 21.731 135.624 ;
     RECT  21.604 61.344 21.737 103.608 ;
     RECT  21.604 132.384 21.737 132.408 ;
     RECT  21.737 61.44 21.772 103.608 ;
     RECT  21.604 164.496 21.773 166.296 ;
     RECT  21.604 162.384 21.779 163.464 ;
     RECT  21.604 153.936 21.809 160.776 ;
     RECT  21.604 18.768 21.881 57.096 ;
     RECT  21.604 141.264 21.917 142.488 ;
     RECT  21.779 162.384 21.953 162.648 ;
     RECT  21.604 104.784 21.989 109.752 ;
     RECT  21.604 136.704 22.025 140.04 ;
     RECT  21.809 155.136 22.097 160.776 ;
     RECT  21.881 26.304 22.133 57.096 ;
     RECT  21.772 61.632 22.241 103.608 ;
     RECT  21.604 167.28 22.241 171.624 ;
     RECT  21.665 111.024 22.252 116.088 ;
     RECT  21.604 143.52 22.313 152.904 ;
     RECT  21.953 162.384 22.313 162.408 ;
     RECT  22.097 155.136 22.349 155.352 ;
     RECT  21.604 3.408 22.385 17.784 ;
     RECT  22.241 61.632 22.385 95.16 ;
     RECT  22.133 26.304 22.421 30.984 ;
     RECT  22.025 138.528 22.449 140.04 ;
     RECT  22.313 143.52 22.493 152.664 ;
     RECT  22.241 167.568 22.499 171.624 ;
     RECT  22.385 3.648 22.529 17.784 ;
     RECT  22.421 30.336 22.601 30.984 ;
     RECT  21.604 117.504 22.633 117.576 ;
     RECT  21.604 118.56 22.633 122.568 ;
     RECT  22.097 156.336 22.637 160.776 ;
     RECT  21.989 104.784 22.705 107.4 ;
     RECT  22.252 115.056 22.705 116.088 ;
     RECT  21.773 164.592 22.705 166.296 ;
     RECT  22.637 156.336 22.709 156.84 ;
     RECT  22.529 6.24 22.777 17.784 ;
     RECT  21.881 18.768 22.777 25.128 ;
     RECT  22.241 96.24 22.777 103.608 ;
     RECT  22.705 104.64 22.777 107.4 ;
     RECT  22.705 115.056 22.777 116.328 ;
     RECT  22.449 138.528 22.781 139.176 ;
     RECT  22.633 117.504 22.789 122.568 ;
     RECT  21.604 123.84 22.789 130.536 ;
     RECT  22.777 115.056 22.796 116.472 ;
     RECT  22.789 117.504 22.796 130.536 ;
     RECT  22.637 157.872 22.813 160.776 ;
     RECT  22.493 149.472 22.817 152.664 ;
     RECT  22.499 167.568 22.817 168.792 ;
     RECT  22.817 149.472 22.853 151.176 ;
     RECT  22.385 61.632 22.885 89.544 ;
     RECT  22.781 138.528 22.889 138.936 ;
     RECT  22.777 96.24 22.925 107.4 ;
     RECT  22.921 133.152 22.957 133.176 ;
     RECT  22.669 140.16 22.957 140.184 ;
     RECT  21.917 141.264 22.957 141.96 ;
     RECT  22.777 6.24 22.961 25.128 ;
     RECT  22.601 30.336 22.961 30.936 ;
     RECT  22.385 91.056 22.961 95.16 ;
     RECT  22.796 115.056 22.997 130.536 ;
     RECT  21.989 108.432 23.005 109.752 ;
     RECT  22.957 140.16 23.029 141.96 ;
     RECT  21.809 153.936 23.029 154.008 ;
     RECT  22.961 6.576 23.033 25.128 ;
     RECT  23.033 20.64 23.065 25.128 ;
     RECT  22.421 26.304 23.065 29.352 ;
     RECT  22.925 104.496 23.065 107.4 ;
     RECT  21.604 58.752 23.077 60.168 ;
     RECT  22.885 61.584 23.077 89.544 ;
     RECT  22.957 132.912 23.125 133.176 ;
     RECT  22.133 32.496 23.137 57.096 ;
     RECT  22.813 157.872 23.173 160.824 ;
     RECT  23.101 163.296 23.173 163.32 ;
     RECT  22.705 164.592 23.173 166.488 ;
     RECT  22.997 123.84 23.209 130.536 ;
     RECT  23.125 132.816 23.221 133.176 ;
     RECT  21.731 134.352 23.221 135.624 ;
     RECT  23.005 109.68 23.269 109.752 ;
     RECT  22.252 111.024 23.269 114.072 ;
     RECT  23.029 140.16 23.317 142.488 ;
     RECT  22.493 143.52 23.317 148.44 ;
     RECT  22.961 91.104 23.353 95.16 ;
     RECT  22.925 96.24 23.353 103.512 ;
     RECT  23.221 132.816 23.353 135.624 ;
     RECT  23.173 157.872 23.353 161.4 ;
     RECT  23.077 58.752 23.389 89.544 ;
     RECT  23.389 58.704 23.461 89.544 ;
     RECT  22.817 168.576 23.461 168.792 ;
     RECT  22.499 170.256 23.461 171.624 ;
     RECT  23.353 157.872 23.533 161.544 ;
     RECT  23.137 32.448 23.557 57.096 ;
     RECT  23.461 58.704 23.557 90.024 ;
     RECT  23.353 132.096 23.564 135.624 ;
     RECT  22.025 136.704 23.564 137.544 ;
     RECT  23.564 132.096 23.605 137.544 ;
     RECT  22.889 138.528 23.605 138.744 ;
     RECT  23.269 109.68 23.641 114.072 ;
     RECT  22.997 115.056 23.641 122.472 ;
     RECT  23.317 140.16 23.677 148.44 ;
     RECT  22.853 149.472 23.677 150.744 ;
     RECT  22.709 156.336 23.804 156.792 ;
     RECT  23.533 157.872 23.804 161.832 ;
     RECT  22.817 152.64 23.821 152.664 ;
     RECT  23.029 153.792 23.821 154.008 ;
     RECT  23.209 123.84 23.845 130.584 ;
     RECT  22.988 154.992 23.857 155.016 ;
     RECT  23.804 156.336 23.857 161.832 ;
     RECT  23.065 20.64 23.929 29.352 ;
     RECT  22.961 30.336 23.929 30.408 ;
     RECT  23.173 163.296 23.929 166.488 ;
     RECT  22.817 167.568 23.929 167.592 ;
     RECT  23.461 168.576 23.929 171.624 ;
     RECT  23.557 32.448 24.001 90.024 ;
     RECT  22.529 3.648 24.008 4.776 ;
     RECT  23.033 6.576 24.008 19.608 ;
     RECT  23.929 20.64 24.008 30.408 ;
     RECT  24.001 31.488 24.008 90.024 ;
     RECT  23.353 91.104 24.008 103.512 ;
     RECT  23.065 104.496 24.008 108.216 ;
     RECT  23.641 109.68 24.008 122.472 ;
     RECT  23.845 123.84 24.008 131.064 ;
     RECT  23.605 132.096 24.008 138.744 ;
     RECT  23.677 140.16 24.008 150.744 ;
     RECT  23.821 152.64 24.008 154.008 ;
     RECT  23.857 154.992 24.008 161.832 ;
     RECT  23.929 163.296 24.008 171.624 ;
     RECT  24.008 2.148 24.112 172.812 ;
     RECT  24.112 2.256 24.304 172.542 ;
     RECT  24.304 169.2 24.365 171.624 ;
     RECT  24.304 2.256 24.419 23.304 ;
     RECT  24.304 32.496 24.419 128.424 ;
     RECT  24.304 165.6 24.437 168.12 ;
     RECT  24.304 159.12 24.46 164.328 ;
     RECT  24.419 2.256 24.508 18.264 ;
     RECT  24.304 24.672 24.509 31.512 ;
     RECT  24.508 5.808 24.515 18.264 ;
     RECT  24.419 32.496 24.515 97.32 ;
     RECT  24.515 32.496 24.517 63.816 ;
     RECT  24.517 32.832 24.545 63.816 ;
     RECT  24.304 129.504 24.563 154.104 ;
     RECT  24.437 165.6 24.581 166.296 ;
     RECT  24.563 129.504 24.604 138.984 ;
     RECT  24.604 129.504 24.611 138.504 ;
     RECT  24.545 41.952 24.645 63.816 ;
     RECT  24.645 41.952 24.653 57.576 ;
     RECT  24.437 167.472 24.653 168.12 ;
     RECT  24.515 5.808 24.689 18.168 ;
     RECT  24.545 32.832 24.689 40.968 ;
     RECT  24.581 165.6 24.689 165.96 ;
     RECT  24.653 46.224 24.725 57.576 ;
     RECT  24.645 58.944 24.725 63.816 ;
     RECT  24.653 41.952 24.869 45.048 ;
     RECT  24.689 6.048 24.977 18.168 ;
     RECT  24.611 135.984 25.085 138.504 ;
     RECT  24.611 129.504 25.091 134.136 ;
     RECT  24.419 19.248 25.121 23.304 ;
     RECT  24.515 64.944 25.121 97.32 ;
     RECT  24.977 6.048 25.157 8.568 ;
     RECT  25.121 19.344 25.157 23.304 ;
     RECT  24.508 2.256 25.187 4.776 ;
     RECT  25.121 64.944 25.187 91.608 ;
     RECT  24.46 159.12 25.187 163.944 ;
     RECT  25.157 6.384 25.229 8.568 ;
     RECT  24.725 61.68 25.229 63.816 ;
     RECT  25.091 132.192 25.229 134.136 ;
     RECT  25.187 159.12 25.273 163.608 ;
     RECT  24.419 98.592 25.301 128.424 ;
     RECT  24.725 58.944 25.337 60.408 ;
     RECT  25.301 102 25.337 126.744 ;
     RECT  25.085 136.752 25.337 138.504 ;
     RECT  24.304 158.112 25.369 158.136 ;
     RECT  25.273 159.12 25.369 162.648 ;
     RECT  25.229 6.384 25.373 7.992 ;
     RECT  25.091 129.504 25.373 131.064 ;
     RECT  25.301 127.776 25.441 128.424 ;
     RECT  25.373 129.504 25.441 130.68 ;
     RECT  25.337 102 25.445 123.096 ;
     RECT  25.369 158.112 25.445 162.648 ;
     RECT  24.563 140.304 25.477 154.104 ;
     RECT  24.304 155.328 25.477 155.928 ;
     RECT  25.187 64.944 25.513 91.368 ;
     RECT  25.477 140.304 25.513 155.928 ;
     RECT  25.445 158.112 25.525 162.456 ;
     RECT  24.689 165.888 25.549 165.96 ;
     RECT  24.689 32.832 25.621 40.392 ;
     RECT  25.513 140.304 25.621 156.216 ;
     RECT  25.525 157.872 25.621 162.456 ;
     RECT  25.549 165.888 25.621 166.152 ;
     RECT  24.653 167.472 25.621 167.496 ;
     RECT  25.373 6.864 25.667 7.992 ;
     RECT  24.509 24.672 25.676 31.416 ;
     RECT  25.621 32.448 25.676 40.392 ;
     RECT  25.121 92.64 25.693 97.32 ;
     RECT  24.365 169.2 25.693 171.384 ;
     RECT  25.585 134.352 25.729 134.376 ;
     RECT  25.621 140.304 25.729 162.456 ;
     RECT  25.676 24.672 25.765 40.392 ;
     RECT  25.621 165.888 25.873 167.496 ;
     RECT  25.157 20.064 26.012 23.304 ;
     RECT  25.765 24.672 26.012 40.824 ;
     RECT  25.477 164.688 26.017 164.712 ;
     RECT  25.873 165.888 26.017 167.736 ;
     RECT  24.725 46.272 26.053 57.576 ;
     RECT  25.693 92.64 26.053 97.416 ;
     RECT  25.301 98.592 26.053 100.92 ;
     RECT  26.012 20.064 26.125 40.824 ;
     RECT  24.869 41.952 26.125 44.952 ;
     RECT  26.125 20.064 26.149 44.952 ;
     RECT  25.229 132.192 26.197 132.984 ;
     RECT  26.053 46.272 26.245 57.72 ;
     RECT  25.337 124.08 26.341 126.744 ;
     RECT  25.441 127.776 26.341 130.68 ;
     RECT  25.729 134.352 26.449 135.144 ;
     RECT  26.017 164.688 26.449 167.736 ;
     RECT  25.729 139.968 26.485 162.456 ;
     RECT  26.449 164.592 26.485 167.736 ;
     RECT  25.229 61.68 26.492 63.624 ;
     RECT  26.485 139.968 26.533 163.416 ;
     RECT  26.485 164.496 26.533 167.736 ;
     RECT  26.492 61.248 26.581 63.624 ;
     RECT  25.513 64.656 26.581 91.368 ;
     RECT  26.581 61.248 26.593 91.368 ;
     RECT  26.053 92.64 26.593 100.92 ;
     RECT  26.341 124.08 26.629 130.68 ;
     RECT  26.533 139.968 26.701 167.736 ;
     RECT  25.693 168.72 26.701 172.152 ;
     RECT  25.187 2.688 26.708 4.776 ;
     RECT  25.667 6.864 26.708 7.752 ;
     RECT  24.977 9.648 26.708 18.168 ;
     RECT  26.149 19.824 26.708 44.952 ;
     RECT  26.245 46.224 26.708 57.72 ;
     RECT  25.337 58.944 26.708 59.832 ;
     RECT  26.593 61.248 26.708 100.92 ;
     RECT  25.445 102 26.708 122.76 ;
     RECT  26.629 123.744 26.708 130.68 ;
     RECT  26.197 131.904 26.708 132.984 ;
     RECT  26.449 134.352 26.708 135.192 ;
     RECT  25.337 136.992 26.708 138.504 ;
     RECT  26.701 139.968 26.708 172.152 ;
     RECT  26.708 2.148 26.812 172.812 ;
     RECT  26.812 2.418 27.004 172.542 ;
     RECT  27.004 58.512 27.065 103.8 ;
     RECT  27.004 104.832 27.137 133.992 ;
     RECT  27.004 42.192 27.209 57.384 ;
     RECT  27.137 104.832 27.209 107.304 ;
     RECT  27.209 104.832 27.317 106.248 ;
     RECT  27.065 58.512 27.353 100.968 ;
     RECT  27.004 135.168 27.353 135.672 ;
     RECT  27.004 165.888 27.353 169.464 ;
     RECT  27.209 51.408 27.395 57.384 ;
     RECT  27.137 108.288 27.425 133.992 ;
     RECT  27.065 102 27.433 103.8 ;
     RECT  27.004 158.016 27.539 162.744 ;
     RECT  27.004 139.632 27.569 157.032 ;
     RECT  27.004 10.128 27.605 10.68 ;
     RECT  27.425 126.912 27.605 133.992 ;
     RECT  27.004 11.76 27.857 36.936 ;
     RECT  27.857 26.256 27.929 36.936 ;
     RECT  27.353 58.512 27.929 100.68 ;
     RECT  27.004 136.656 27.964 138.456 ;
     RECT  27.857 11.76 27.965 25.176 ;
     RECT  27.004 164.064 27.965 164.616 ;
     RECT  27.004 38.256 27.997 40.056 ;
     RECT  27.004 41.04 27.997 41.16 ;
     RECT  27.539 158.256 28.028 162.744 ;
     RECT  27.965 164.064 28.028 164.136 ;
     RECT  27.004 2.832 28.037 7.944 ;
     RECT  27.965 19.824 28.037 25.176 ;
     RECT  27.997 38.256 28.081 41.16 ;
     RECT  27.605 127.104 28.109 133.992 ;
     RECT  28.037 19.824 28.115 25.128 ;
     RECT  28.081 38.256 28.141 39.768 ;
     RECT  27.317 106.224 28.172 106.248 ;
     RECT  27.209 107.232 28.172 107.304 ;
     RECT  27.964 138.048 28.177 138.456 ;
     RECT  28.037 2.832 28.181 5.304 ;
     RECT  27.965 11.76 28.181 18.792 ;
     RECT  27.433 102.192 28.213 103.8 ;
     RECT  27.317 104.832 28.213 105.192 ;
     RECT  28.177 138.048 28.213 138.552 ;
     RECT  27.569 139.632 28.213 142.104 ;
     RECT  28.081 41.136 28.217 41.16 ;
     RECT  27.395 51.408 28.217 54.936 ;
     RECT  28.109 132.144 28.217 133.992 ;
     RECT  28.213 102.192 28.285 105.192 ;
     RECT  28.172 106.224 28.285 107.304 ;
     RECT  28.181 11.76 28.307 18.696 ;
     RECT  27.605 10.128 28.357 10.632 ;
     RECT  27.004 170.448 28.397 171.96 ;
     RECT  28.115 20.544 28.403 25.128 ;
     RECT  28.037 7.44 28.429 7.944 ;
     RECT  28.285 102.192 28.429 107.304 ;
     RECT  27.353 165.936 28.429 169.464 ;
     RECT  27.569 143.232 28.46 157.032 ;
     RECT  27.425 108.288 28.465 125.4 ;
     RECT  27.209 42.192 28.501 50.328 ;
     RECT  28.217 51.408 28.501 53.976 ;
     RECT  27.353 135.648 28.537 135.672 ;
     RECT  28.429 7.44 28.609 8.424 ;
     RECT  28.357 9.648 28.609 10.632 ;
     RECT  27.395 55.968 28.645 57.384 ;
     RECT  28.429 102.144 28.681 107.304 ;
     RECT  28.465 108.288 28.681 125.448 ;
     RECT  28.213 138.048 28.717 142.104 ;
     RECT  27.929 61.248 28.741 100.68 ;
     RECT  28.429 165.936 28.789 169.512 ;
     RECT  28.717 138.048 28.933 142.152 ;
     RECT  28.46 143.232 28.933 157.224 ;
     RECT  28.933 138.048 28.969 157.224 ;
     RECT  27.929 58.512 28.981 59.496 ;
     RECT  28.741 61.248 28.981 100.776 ;
     RECT  28.645 55.392 29.005 57.384 ;
     RECT  27.929 36.864 29.041 36.936 ;
     RECT  28.141 38.064 29.041 39.768 ;
     RECT  29.005 55.392 29.041 57.432 ;
     RECT  28.981 58.512 29.041 100.776 ;
     RECT  28.109 127.104 29.041 130.632 ;
     RECT  28.403 23.088 29.077 25.128 ;
     RECT  28.681 102.144 29.077 125.448 ;
     RECT  29.041 126.72 29.077 130.632 ;
     RECT  28.028 158.256 29.077 164.136 ;
     RECT  28.789 165.264 29.077 169.512 ;
     RECT  28.609 7.44 29.149 10.632 ;
     RECT  28.307 11.76 29.149 17.688 ;
     RECT  28.537 135.648 29.149 136.008 ;
     RECT  28.307 18.672 29.18 18.696 ;
     RECT  28.501 42.192 29.269 53.976 ;
     RECT  29.041 55.392 29.269 100.776 ;
     RECT  29.149 135.648 29.269 136.2 ;
     RECT  28.969 137.856 29.269 157.224 ;
     RECT  29.269 42.192 29.293 100.776 ;
     RECT  29.077 102.144 29.329 130.776 ;
     RECT  28.217 132.24 29.329 133.992 ;
     RECT  29.269 135.648 29.365 157.224 ;
     RECT  29.077 158.256 29.365 169.512 ;
     RECT  29.329 132.24 29.401 134.376 ;
     RECT  29.365 135.648 29.401 169.512 ;
     RECT  28.181 3.312 29.408 5.304 ;
     RECT  29.257 6.384 29.408 6.408 ;
     RECT  29.149 7.44 29.408 17.688 ;
     RECT  29.18 18.672 29.408 19.368 ;
     RECT  28.403 20.544 29.408 22.056 ;
     RECT  29.077 23.088 29.408 25.224 ;
     RECT  27.929 26.256 29.408 35.832 ;
     RECT  29.041 36.864 29.408 39.768 ;
     RECT  29.293 41.904 29.408 100.776 ;
     RECT  29.329 102.144 29.408 131.112 ;
     RECT  29.401 132.24 29.408 169.512 ;
     RECT  28.397 170.736 29.408 171.96 ;
     RECT  29.408 2.148 29.512 172.812 ;
     RECT  29.512 2.418 29.704 172.542 ;
     RECT  29.704 155.568 29.765 169.608 ;
     RECT  29.704 170.688 29.765 171.912 ;
     RECT  29.704 114.336 29.801 149.88 ;
     RECT  29.704 152.688 29.801 154.296 ;
     RECT  29.801 126.72 29.843 149.88 ;
     RECT  29.843 126.72 29.981 132.936 ;
     RECT  29.704 107.52 29.987 108.888 ;
     RECT  29.843 134.112 30.061 149.88 ;
     RECT  29.765 157.488 30.161 169.608 ;
     RECT  30.161 159.6 30.197 169.608 ;
     RECT  29.981 126.72 30.233 132.792 ;
     RECT  29.704 3.312 30.275 18.216 ;
     RECT  29.704 26.304 30.275 48.216 ;
     RECT  30.275 26.304 30.305 34.392 ;
     RECT  29.704 109.968 30.305 113.112 ;
     RECT  29.801 114.336 30.305 125.448 ;
     RECT  30.275 35.424 30.341 48.216 ;
     RECT  29.704 19.632 30.377 25.224 ;
     RECT  30.197 159.6 30.508 168.312 ;
     RECT  30.275 3.312 30.521 5.208 ;
     RECT  30.305 32.832 30.521 34.392 ;
     RECT  30.275 6.336 30.556 18.216 ;
     RECT  30.061 134.112 30.593 142.152 ;
     RECT  29.765 170.688 30.611 171.768 ;
     RECT  29.987 107.568 30.629 108.888 ;
     RECT  30.305 114.336 30.629 125.4 ;
     RECT  30.377 19.632 30.665 21.096 ;
     RECT  29.704 151.008 30.697 151.656 ;
     RECT  29.801 152.688 30.697 154.248 ;
     RECT  30.665 19.632 30.701 21 ;
     RECT  30.341 35.52 30.701 48.216 ;
     RECT  30.377 22.224 30.733 25.224 ;
     RECT  30.305 26.304 30.733 26.664 ;
     RECT  29.704 61.344 30.733 67.944 ;
     RECT  29.704 69.024 30.733 106.248 ;
     RECT  30.305 110.256 30.733 113.112 ;
     RECT  30.629 114.336 30.733 124.872 ;
     RECT  30.556 16.32 30.757 18.216 ;
     RECT  30.701 19.632 30.757 20.616 ;
     RECT  29.704 49.248 30.769 50.184 ;
     RECT  29.704 51.168 30.769 59.256 ;
     RECT  30.061 143.136 30.769 149.88 ;
     RECT  30.697 151.008 30.769 154.248 ;
     RECT  29.765 155.568 30.769 156.504 ;
     RECT  30.161 157.488 30.769 158.376 ;
     RECT  30.593 134.112 30.773 134.52 ;
     RECT  30.769 143.136 30.805 154.248 ;
     RECT  30.769 155.232 30.805 158.376 ;
     RECT  30.733 61.344 30.809 106.248 ;
     RECT  30.805 143.136 30.809 158.376 ;
     RECT  30.508 160.08 30.809 168.312 ;
     RECT  30.809 164.736 30.845 168.312 ;
     RECT  30.773 134.112 30.877 134.472 ;
     RECT  30.701 38.256 30.899 48.216 ;
     RECT  30.809 61.344 30.899 100.296 ;
     RECT  30.845 166.752 30.917 168.312 ;
     RECT  30.809 101.424 30.949 106.248 ;
     RECT  30.593 136.752 30.953 142.152 ;
     RECT  30.899 61.344 30.989 100.248 ;
     RECT  30.809 143.136 30.989 158.136 ;
     RECT  30.305 27.888 31.025 31.848 ;
     RECT  30.989 143.136 31.061 150.504 ;
     RECT  30.953 138.96 31.093 142.152 ;
     RECT  31.061 143.136 31.093 150.312 ;
     RECT  31.025 30.72 31.097 31.848 ;
     RECT  30.899 42.192 31.097 48.216 ;
     RECT  30.197 169.584 31.097 169.608 ;
     RECT  31.097 46.608 31.129 48.216 ;
     RECT  30.769 49.248 31.129 59.256 ;
     RECT  30.233 126.72 31.133 132.36 ;
     RECT  31.133 131.04 31.139 132.36 ;
     RECT  30.949 101.424 31.165 106.584 ;
     RECT  30.733 22.224 31.301 26.664 ;
     RECT  31.025 27.888 31.301 29.64 ;
     RECT  31.133 126.72 31.345 129.96 ;
     RECT  31.129 46.608 31.381 59.256 ;
     RECT  31.345 60.384 31.381 60.408 ;
     RECT  30.917 166.992 31.417 168.312 ;
     RECT  30.611 170.736 31.417 171.768 ;
     RECT  31.139 131.568 31.525 132.36 ;
     RECT  30.877 134.064 31.561 134.472 ;
     RECT  30.521 32.832 31.573 33.912 ;
     RECT  30.556 6.336 31.597 15.24 ;
     RECT  31.597 6.336 31.669 15.336 ;
     RECT  30.757 16.32 31.669 20.616 ;
     RECT  30.701 35.52 31.669 37.176 ;
     RECT  30.899 38.256 31.669 41.016 ;
     RECT  30.629 107.76 31.669 108.84 ;
     RECT  31.525 131.568 31.669 132.984 ;
     RECT  31.561 134.016 31.669 134.472 ;
     RECT  31.301 22.224 31.741 29.64 ;
     RECT  31.165 101.424 31.741 106.632 ;
     RECT  31.669 107.76 31.741 109.176 ;
     RECT  31.669 6.336 31.777 20.616 ;
     RECT  30.521 3.552 31.82 5.208 ;
     RECT  30.809 160.08 31.909 163.56 ;
     RECT  30.845 164.736 31.909 165.672 ;
     RECT  31.909 160.08 31.916 163.608 ;
     RECT  30.989 151.584 31.957 152.76 ;
     RECT  30.989 153.744 31.957 158.136 ;
     RECT  31.097 30.864 31.993 31.848 ;
     RECT  31.573 32.832 31.993 34.2 ;
     RECT  31.82 3.36 32.029 5.208 ;
     RECT  31.777 6.288 32.029 20.616 ;
     RECT  31.993 30.864 32.065 34.2 ;
     RECT  31.861 2.256 32.108 2.28 ;
     RECT  32.029 3.36 32.108 20.616 ;
     RECT  31.741 21.744 32.108 29.64 ;
     RECT  32.065 30.864 32.108 34.392 ;
     RECT  31.669 35.52 32.108 41.016 ;
     RECT  31.097 42.192 32.108 45.576 ;
     RECT  31.381 46.608 32.108 60.408 ;
     RECT  30.989 61.68 32.108 100.248 ;
     RECT  31.741 101.424 32.108 109.176 ;
     RECT  30.733 110.256 32.108 124.872 ;
     RECT  31.345 126.432 32.108 129.96 ;
     RECT  31.669 131.568 32.108 134.472 ;
     RECT  30.953 136.752 32.108 137.928 ;
     RECT  31.093 138.96 32.108 150.312 ;
     RECT  31.957 151.584 32.108 158.136 ;
     RECT  31.916 159.696 32.108 163.608 ;
     RECT  31.909 164.64 32.108 165.96 ;
     RECT  31.417 166.992 32.108 169.224 ;
     RECT  31.417 170.736 32.108 172.44 ;
     RECT  32.108 2.148 32.212 172.812 ;
     RECT  32.212 2.418 32.404 172.542 ;
     RECT  32.404 120.48 32.429 123.24 ;
     RECT  32.404 30.72 32.465 60.12 ;
     RECT  32.404 61.488 32.465 97.512 ;
     RECT  32.404 130.56 32.465 135.192 ;
     RECT  32.404 144.576 32.465 152.712 ;
     RECT  32.465 30.72 32.531 44.952 ;
     RECT  32.465 46.032 32.537 60.12 ;
     RECT  32.465 130.56 32.537 132.984 ;
     RECT  32.465 134.016 32.537 135.192 ;
     RECT  32.465 61.488 32.573 80.088 ;
     RECT  32.573 61.488 32.609 64.392 ;
     RECT  32.404 172.416 32.609 172.44 ;
     RECT  32.465 81.12 32.645 97.512 ;
     RECT  32.404 14.64 32.675 29.352 ;
     RECT  32.531 30.72 32.675 39.768 ;
     RECT  32.404 136.176 32.675 143.544 ;
     RECT  32.404 3.6 32.681 8.856 ;
     RECT  32.531 40.992 32.717 44.952 ;
     RECT  32.404 98.592 32.717 118.92 ;
     RECT  32.717 41.664 32.753 44.952 ;
     RECT  32.645 81.12 32.753 93.864 ;
     RECT  32.717 100.752 32.753 118.92 ;
     RECT  32.675 136.464 32.771 143.544 ;
     RECT  32.681 6.384 32.789 8.856 ;
     RECT  32.537 130.56 32.825 132.408 ;
     RECT  32.537 55.728 32.861 60.12 ;
     RECT  32.753 100.752 32.897 114.552 ;
     RECT  32.771 136.464 32.963 140.28 ;
     RECT  32.861 60.096 32.969 60.12 ;
     RECT  32.789 6.432 33.005 8.856 ;
     RECT  32.963 136.464 33.005 139.8 ;
     RECT  32.404 168.768 33.005 171.288 ;
     RECT  32.897 101.616 33.077 114.552 ;
     RECT  32.681 3.6 33.113 5.016 ;
     RECT  32.537 46.032 33.113 54.696 ;
     RECT  32.753 81.408 33.113 93.864 ;
     RECT  32.675 14.64 33.148 27.864 ;
     RECT  32.753 42.672 33.149 44.952 ;
     RECT  33.113 81.408 33.185 85.752 ;
     RECT  32.404 126.432 33.185 129.24 ;
     RECT  32.404 160.704 33.185 166.536 ;
     RECT  32.645 94.896 33.203 97.512 ;
     RECT  33.149 42.672 33.221 44.904 ;
     RECT  32.717 98.592 33.244 99.528 ;
     RECT  33.077 101.904 33.257 114.552 ;
     RECT  32.861 55.728 33.329 59.016 ;
     RECT  33.257 101.904 33.329 106.536 ;
     RECT  33.005 136.464 33.329 139.704 ;
     RECT  33.185 165.408 33.329 166.536 ;
     RECT  33.185 160.704 33.365 164.328 ;
     RECT  32.404 167.568 33.365 167.592 ;
     RECT  33.365 162.72 33.388 164.328 ;
     RECT  33.005 6.864 33.397 8.856 ;
     RECT  32.537 134.208 33.397 135.192 ;
     RECT  32.404 159.552 33.397 159.576 ;
     RECT  32.609 61.488 33.433 63.768 ;
     RECT  33.148 14.64 33.436 27.336 ;
     RECT  33.397 6.864 33.437 9.384 ;
     RECT  32.404 11.472 33.469 13.464 ;
     RECT  33.436 14.64 33.469 21.528 ;
     RECT  33.113 46.656 33.473 54.696 ;
     RECT  32.825 130.56 33.473 130.584 ;
     RECT  32.465 144.576 33.505 149.4 ;
     RECT  32.404 153.696 33.505 155.16 ;
     RECT  32.404 156.384 33.505 157.848 ;
     RECT  33.397 134.208 33.539 135.24 ;
     RECT  33.473 46.656 33.545 53.928 ;
     RECT  32.675 28.848 33.577 29.352 ;
     RECT  32.675 30.96 33.577 39.768 ;
     RECT  32.573 65.52 33.577 80.088 ;
     RECT  32.404 124.608 33.589 125.448 ;
     RECT  33.185 126.432 33.589 129.096 ;
     RECT  33.433 60.624 33.613 63.768 ;
     RECT  33.113 86.736 33.613 93.864 ;
     RECT  33.203 94.896 33.613 97.416 ;
     RECT  33.505 123.6 33.613 123.624 ;
     RECT  33.589 124.608 33.613 129.096 ;
     RECT  32.771 141.36 33.613 143.544 ;
     RECT  33.505 144.576 33.613 149.784 ;
     RECT  33.545 48.096 33.617 53.832 ;
     RECT  33.613 141.36 33.637 149.784 ;
     RECT  32.465 150.912 33.637 152.712 ;
     RECT  33.469 11.472 33.653 21.528 ;
     RECT  33.613 86.736 33.653 97.416 ;
     RECT  33.577 30.96 33.683 39.96 ;
     RECT  33.257 107.52 33.683 114.552 ;
     RECT  33.613 123.6 33.683 129.096 ;
     RECT  33.637 141.36 33.683 152.712 ;
     RECT  32.429 120.48 33.685 122.472 ;
     RECT  33.397 159.408 33.685 159.576 ;
     RECT  33.365 160.704 33.685 161.592 ;
     RECT  33.653 16.32 33.689 21.528 ;
     RECT  33.577 65.52 33.721 80.28 ;
     RECT  33.185 81.408 33.721 84.072 ;
     RECT  33.244 98.64 33.721 99.528 ;
     RECT  33.683 151.584 33.721 152.712 ;
     RECT  33.505 153.696 33.721 157.848 ;
     RECT  33.721 98.64 33.725 99.72 ;
     RECT  33.683 141.36 33.731 150.216 ;
     RECT  33.437 7.68 33.761 9.384 ;
     RECT  33.761 9.36 33.781 9.384 ;
     RECT  32.825 131.664 33.781 132.408 ;
     RECT  33.683 31.152 33.793 39.96 ;
     RECT  33.781 131.664 33.797 133.176 ;
     RECT  33.781 9.36 33.827 9.672 ;
     RECT  33.539 134.208 33.827 135.144 ;
     RECT  33.685 159.408 33.833 161.592 ;
     RECT  33.649 2.256 33.884 2.28 ;
     RECT  33.113 3.6 33.884 4.776 ;
     RECT  33.793 31.152 33.901 40.104 ;
     RECT  32.753 41.664 33.901 41.688 ;
     RECT  33.221 42.672 33.901 44.568 ;
     RECT  33.329 55.968 33.937 59.016 ;
     RECT  33.613 60.624 33.937 64.152 ;
     RECT  32.753 115.632 33.937 118.92 ;
     RECT  33.653 11.472 34.076 15.336 ;
     RECT  33.827 9.648 34.117 9.672 ;
     RECT  33.937 55.968 34.153 64.152 ;
     RECT  33.683 123.744 34.153 129.096 ;
     RECT  33.901 31.152 34.165 40.44 ;
     RECT  33.901 41.664 34.165 44.568 ;
     RECT  33.329 136.464 34.165 137.352 ;
     RECT  34.165 31.152 34.22 44.568 ;
     RECT  33.721 65.52 34.22 84.072 ;
     RECT  34.22 31.152 34.261 45.336 ;
     RECT  33.545 46.656 34.261 46.968 ;
     RECT  34.22 65.328 34.261 84.072 ;
     RECT  33.185 85.056 34.261 85.752 ;
     RECT  33.925 172.032 34.261 172.056 ;
     RECT  33.329 101.904 34.297 106.248 ;
     RECT  33.721 151.584 34.297 157.848 ;
     RECT  33.833 159.408 34.297 161.4 ;
     RECT  33.725 98.736 34.357 99.72 ;
     RECT  34.117 9.648 34.369 9.96 ;
     RECT  34.076 11.04 34.369 15.336 ;
     RECT  34.357 98.736 34.405 100.008 ;
     RECT  34.297 101.136 34.405 106.248 ;
     RECT  33.005 168.768 34.405 171 ;
     RECT  34.261 172.032 34.405 172.152 ;
     RECT  33.653 92.544 34.477 97.416 ;
     RECT  33.884 2.256 34.549 4.776 ;
     RECT  34.153 123.744 34.549 130.056 ;
     RECT  33.329 165.552 34.549 166.536 ;
     RECT  24.757 0.192 34.589 0.216 ;
     RECT  34.549 165.36 34.621 166.536 ;
     RECT  33.685 120.144 34.657 122.472 ;
     RECT  34.549 123.744 34.657 130.104 ;
     RECT  33.388 162.816 34.657 164.328 ;
     RECT  33.617 50.064 34.729 53.832 ;
     RECT  34.153 55.968 34.729 64.344 ;
     RECT  34.729 50.064 34.765 54.648 ;
     RECT  33.617 48.096 34.801 49.08 ;
     RECT  34.765 50.064 34.801 54.744 ;
     RECT  34.729 55.776 34.801 64.344 ;
     RECT  34.549 2.256 34.808 5.064 ;
     RECT  33.761 7.68 34.808 7.8 ;
     RECT  34.369 9.648 34.808 15.336 ;
     RECT  33.689 16.32 34.808 19.8 ;
     RECT  33.689 20.88 34.808 21.528 ;
     RECT  33.436 22.512 34.808 27.336 ;
     RECT  33.577 28.848 34.808 29.832 ;
     RECT  34.261 31.152 34.808 46.968 ;
     RECT  34.801 48.096 34.808 64.344 ;
     RECT  34.261 65.328 34.808 85.752 ;
     RECT  33.653 86.736 34.808 91.224 ;
     RECT  34.477 92.544 34.808 97.56 ;
     RECT  34.405 98.736 34.808 106.248 ;
     RECT  33.683 107.52 34.808 113.784 ;
     RECT  33.937 115.632 34.808 119.016 ;
     RECT  34.657 120.144 34.808 130.104 ;
     RECT  33.797 131.664 34.808 131.688 ;
     RECT  33.797 132.72 34.808 133.176 ;
     RECT  33.827 135.072 34.808 135.144 ;
     RECT  34.165 136.176 34.808 137.352 ;
     RECT  33.329 138.336 34.808 139.704 ;
     RECT  33.731 141.36 34.808 143.544 ;
     RECT  33.731 144.528 34.808 150.216 ;
     RECT  34.297 151.584 34.808 161.4 ;
     RECT  34.657 162.624 34.808 164.328 ;
     RECT  34.621 165.36 34.808 167.304 ;
     RECT  34.405 168.768 34.808 172.152 ;
     RECT  34.808 2.148 34.912 172.812 ;
     RECT  34.912 2.418 35.104 172.542 ;
     RECT  35.104 107.52 35.165 108.84 ;
     RECT  35.104 134.544 35.201 140.472 ;
     RECT  35.104 170.448 35.201 170.808 ;
     RECT  35.104 126 35.219 131.592 ;
     RECT  35.104 141.888 35.219 169.224 ;
     RECT  35.104 48.144 35.237 60.936 ;
     RECT  35.201 136.704 35.267 140.472 ;
     RECT  35.104 36 35.273 45.048 ;
     RECT  35.219 141.888 35.273 166.488 ;
     RECT  35.201 170.448 35.273 170.76 ;
     RECT  35.273 142.08 35.308 166.488 ;
     RECT  35.219 126.528 35.345 131.592 ;
     RECT  35.104 21.504 35.363 21.528 ;
     RECT  35.104 115.536 35.381 124.872 ;
     RECT  35.308 142.08 35.381 159.528 ;
     RECT  35.381 115.536 35.389 124.152 ;
     RECT  35.237 48.48 35.417 60.936 ;
     RECT  35.381 156.72 35.417 159.528 ;
     RECT  35.417 156.72 35.453 157.272 ;
     RECT  35.273 170.448 35.453 170.52 ;
     RECT  35.104 132.72 35.507 133.176 ;
     RECT  35.104 109.968 35.525 114.456 ;
     RECT  35.219 168.816 35.525 169.224 ;
     RECT  35.308 160.56 35.561 166.488 ;
     RECT  35.345 126.528 35.569 130.056 ;
     RECT  35.104 11.136 35.597 20.472 ;
     RECT  35.273 36 35.597 43.128 ;
     RECT  35.417 48.816 35.597 60.936 ;
     RECT  35.104 172.032 35.597 172.152 ;
     RECT  35.104 4.752 35.603 10.104 ;
     RECT  35.597 11.136 35.603 19.8 ;
     RECT  35.201 134.544 35.603 135.624 ;
     RECT  35.267 136.704 35.633 138.024 ;
     RECT  35.104 82.704 35.669 83.064 ;
     RECT  35.104 84.048 35.699 95.352 ;
     RECT  35.104 22.704 35.705 34.872 ;
     RECT  35.507 132.72 35.705 132.744 ;
     RECT  35.603 14.976 35.741 19.8 ;
     RECT  35.561 160.56 35.741 165.864 ;
     RECT  35.381 142.08 35.747 155.688 ;
     RECT  35.597 40.8 35.777 43.128 ;
     RECT  35.597 48.816 35.777 51.48 ;
     RECT  35.669 82.752 35.777 83.064 ;
     RECT  35.633 136.704 35.777 136.728 ;
     RECT  35.603 6 35.813 10.104 ;
     RECT  35.104 61.968 35.813 81.432 ;
     RECT  35.747 147.024 35.885 155.688 ;
     RECT  35.219 167.568 35.885 167.736 ;
     RECT  35.813 8.976 35.891 10.104 ;
     RECT  35.885 147.264 35.891 155.688 ;
     RECT  35.891 9.648 35.921 10.104 ;
     RECT  35.603 134.544 35.921 134.616 ;
     RECT  35.389 115.584 35.939 124.152 ;
     RECT  35.741 160.56 35.939 162.648 ;
     RECT  35.777 82.752 35.957 83.016 ;
     RECT  35.597 52.464 35.98 60.936 ;
     RECT  35.741 163.92 35.98 165.864 ;
     RECT  35.603 11.136 35.993 13.848 ;
     RECT  35.597 36 35.993 39.768 ;
     RECT  35.525 112.128 36.029 114.456 ;
     RECT  35.921 134.544 36.029 134.568 ;
     RECT  35.747 142.08 36.029 145.992 ;
     RECT  35.705 22.704 36.035 34.776 ;
     RECT  35.699 92.688 36.035 95.352 ;
     RECT  36.035 92.688 36.073 94.152 ;
     RECT  35.993 11.184 36.101 13.848 ;
     RECT  35.993 36.144 36.137 39.768 ;
     RECT  35.525 109.968 36.137 110.856 ;
     RECT  35.104 98.592 36.169 99.528 ;
     RECT  35.98 59.808 36.205 60.936 ;
     RECT  36.169 98.592 36.205 99.96 ;
     RECT  35.104 102 36.205 106.248 ;
     RECT  35.98 52.464 36.209 58.68 ;
     RECT  36.205 59.808 36.209 60.984 ;
     RECT  35.891 147.408 36.209 155.688 ;
     RECT  35.165 107.808 36.241 108.84 ;
     RECT  35.273 44.112 36.245 45.048 ;
     RECT  36.029 142.08 36.245 145.704 ;
     RECT  36.101 11.232 36.281 13.848 ;
     RECT  36.137 36.144 36.281 37.416 ;
     RECT  36.209 147.744 36.281 155.688 ;
     RECT  36.245 44.448 36.313 45.048 ;
     RECT  35.777 48.96 36.323 51.48 ;
     RECT  36.035 22.704 36.349 29.4 ;
     RECT  35.939 115.632 36.349 124.152 ;
     RECT  35.417 158.4 36.353 159.528 ;
     RECT  35.525 168.816 36.353 168.84 ;
     RECT  36.349 22.464 36.371 29.4 ;
     RECT  35.569 126.624 36.373 130.056 ;
     RECT  35.345 131.328 36.373 131.592 ;
     RECT  36.371 26.064 36.417 29.4 ;
     RECT  36.313 44.448 36.421 45.24 ;
     RECT  35.104 96.528 36.421 97.56 ;
     RECT  36.205 98.592 36.421 100.344 ;
     RECT  35.939 160.56 36.461 161.88 ;
     RECT  35.98 164.304 36.461 165.864 ;
     RECT  36.38 47.856 36.467 47.88 ;
     RECT  36.209 52.464 36.467 58.152 ;
     RECT  36.371 22.464 36.493 24.552 ;
     RECT  36.137 110.832 36.493 110.856 ;
     RECT  36.029 112.128 36.493 113.4 ;
     RECT  36.137 38.592 36.497 39.768 ;
     RECT  36.421 44.448 36.497 45.576 ;
     RECT  36.349 115.632 36.497 124.248 ;
     RECT  36.461 164.688 36.497 165.384 ;
     RECT  35.267 139.2 36.517 140.472 ;
     RECT  36.035 30.864 36.533 34.776 ;
     RECT  36.205 102 36.533 106.728 ;
     RECT  36.353 158.544 36.533 159.528 ;
     RECT  36.529 125.232 36.565 125.256 ;
     RECT  36.241 107.808 36.601 108.936 ;
     RECT  36.533 159.408 36.637 159.528 ;
     RECT  36.461 160.56 36.637 161.352 ;
     RECT  35.104 2.832 36.709 3.624 ;
     RECT  35.603 4.752 36.709 4.776 ;
     RECT  36.281 153.792 36.709 155.688 ;
     RECT  35.453 156.72 36.709 157.032 ;
     RECT  35.957 82.992 36.745 83.016 ;
     RECT  35.699 84.048 36.745 91.224 ;
     RECT  36.497 117.6 36.805 124.248 ;
     RECT  36.565 125.232 36.805 125.64 ;
     RECT  36.373 126.624 36.805 131.592 ;
     RECT  35.813 6 36.889 7.992 ;
     RECT  35.741 14.976 36.925 16.44 ;
     RECT  35.741 17.904 36.925 19.032 ;
     RECT  35.777 40.8 36.961 40.824 ;
     RECT  35.777 41.952 36.961 43.128 ;
     RECT  36.745 82.992 36.997 91.224 ;
     RECT  35.603 135.6 36.997 135.624 ;
     RECT  36.805 117.6 37.004 131.592 ;
     RECT  36.493 21.648 37.033 24.552 ;
     RECT  36.997 82.992 37.033 91.464 ;
     RECT  36.421 96.528 37.033 100.344 ;
     RECT  36.517 139.104 37.033 140.472 ;
     RECT  36.925 14.976 37.045 19.032 ;
     RECT  37.033 20.736 37.045 24.552 ;
     RECT  36.497 38.688 37.045 39.768 ;
     RECT  36.961 40.8 37.045 43.32 ;
     RECT  36.209 59.904 37.045 60.984 ;
     RECT  35.813 61.968 37.045 78.984 ;
     RECT  37.033 82.896 37.069 91.464 ;
     RECT  36.997 134.544 37.069 135.624 ;
     RECT  35.633 137.76 37.069 138.024 ;
     RECT  37.033 139.104 37.069 140.76 ;
     RECT  37.069 137.76 37.148 140.76 ;
     RECT  36.467 52.8 37.177 58.152 ;
     RECT  35.885 167.568 37.177 167.592 ;
     RECT  37.069 82.752 37.237 91.464 ;
     RECT  37.045 14.976 37.244 24.552 ;
     RECT  36.245 142.08 37.244 143.544 ;
     RECT  36.281 11.232 37.249 13.32 ;
     RECT  37.249 10.992 37.285 13.32 ;
     RECT  37.045 59.904 37.32 78.984 ;
     RECT  35.813 80.064 37.32 81.432 ;
     RECT  37.069 134.544 37.333 136.056 ;
     RECT  37.148 137.184 37.333 140.76 ;
     RECT  36.889 6 37.349 8.52 ;
     RECT  36.493 110.832 37.357 113.4 ;
     RECT  36.029 114.432 37.357 114.456 ;
     RECT  36.281 36.144 37.381 37.224 ;
     RECT  37.32 59.904 37.381 81.432 ;
     RECT  37.141 163.68 37.429 163.704 ;
     RECT  36.709 2.832 37.508 4.776 ;
     RECT  37.349 6 37.508 8.568 ;
     RECT  35.921 9.648 37.508 9.672 ;
     RECT  37.285 10.992 37.508 13.656 ;
     RECT  37.244 14.64 37.508 24.552 ;
     RECT  36.417 26.064 37.508 29.352 ;
     RECT  36.533 30.864 37.508 33.912 ;
     RECT  37.381 36 37.508 37.464 ;
     RECT  37.045 38.688 37.508 43.32 ;
     RECT  36.497 44.448 37.508 44.472 ;
     RECT  36.497 45.552 37.508 45.576 ;
     RECT  36.781 47.28 37.508 47.304 ;
     RECT  36.323 48.96 37.508 51.432 ;
     RECT  37.177 52.8 37.508 58.68 ;
     RECT  37.381 59.904 37.508 81.624 ;
     RECT  37.237 82.656 37.508 91.464 ;
     RECT  36.073 92.688 37.508 92.712 ;
     RECT  36.073 93.792 37.508 94.152 ;
     RECT  37.285 95.136 37.508 95.16 ;
     RECT  37.033 96.528 37.508 100.776 ;
     RECT  36.533 102.096 37.508 106.728 ;
     RECT  36.601 107.808 37.508 109.272 ;
     RECT  37.357 110.832 37.508 114.456 ;
     RECT  36.497 115.632 37.508 116.52 ;
     RECT  37.004 117.6 37.508 132.216 ;
     RECT  36.817 133.344 37.508 133.368 ;
     RECT  37.333 134.544 37.508 140.76 ;
     RECT  37.244 141.792 37.508 143.544 ;
     RECT  36.245 144.528 37.508 145.704 ;
     RECT  36.281 147.744 37.508 152.712 ;
     RECT  36.709 153.792 37.508 157.032 ;
     RECT  36.637 159.408 37.508 161.352 ;
     RECT  37.429 163.44 37.508 163.704 ;
     RECT  36.497 164.784 37.508 165.384 ;
     RECT  37.177 167.568 37.508 167.784 ;
     RECT  35.453 170.496 37.508 170.52 ;
     RECT  35.597 172.032 37.508 172.056 ;
     RECT  37.508 2.148 37.612 172.812 ;
     RECT  37.612 2.418 37.804 172.542 ;
     RECT  37.804 59.808 37.865 100.824 ;
     RECT  37.804 21.456 37.937 23.976 ;
     RECT  37.804 144.768 37.955 149.784 ;
     RECT  37.804 158.4 37.955 161.16 ;
     RECT  37.804 26.064 37.973 26.616 ;
     RECT  37.804 120.864 37.973 126.504 ;
     RECT  37.865 65.424 37.996 100.824 ;
     RECT  37.804 163.44 38.009 166.44 ;
     RECT  37.973 26.256 38.045 26.616 ;
     RECT  37.804 115.776 38.045 118.104 ;
     RECT  38.009 163.68 38.045 166.44 ;
     RECT  38.045 26.256 38.081 26.568 ;
     RECT  37.996 65.424 38.081 92.904 ;
     RECT  37.804 107.856 38.153 114.024 ;
     RECT  37.804 27.84 38.189 39.336 ;
     RECT  37.804 136.944 38.189 140.76 ;
     RECT  37.804 151.008 38.189 157.272 ;
     RECT  37.804 40.416 38.195 44.712 ;
     RECT  38.189 153.696 38.195 157.272 ;
     RECT  37.804 162.336 38.195 162.36 ;
     RECT  37.973 121.92 38.225 126.504 ;
     RECT  38.195 153.696 38.225 156.024 ;
     RECT  38.045 163.68 38.225 166.296 ;
     RECT  38.189 33.888 38.243 39.336 ;
     RECT  38.225 166.272 38.243 166.296 ;
     RECT  37.804 167.568 38.243 171.768 ;
     RECT  38.243 34.896 38.261 39.336 ;
     RECT  37.804 3.408 38.297 3.72 ;
     RECT  37.804 10.272 38.333 19.656 ;
     RECT  37.804 55.968 38.333 58.68 ;
     RECT  38.225 123.552 38.339 126.504 ;
     RECT  37.804 104.544 38.405 106.488 ;
     RECT  37.865 59.808 38.435 64.44 ;
     RECT  38.081 65.952 38.435 92.904 ;
     RECT  38.333 11.472 38.483 19.656 ;
     RECT  37.804 47.664 38.513 47.928 ;
     RECT  38.225 154.896 38.513 156.024 ;
     RECT  38.339 123.552 38.549 125.832 ;
     RECT  38.189 137.472 38.549 140.76 ;
     RECT  38.189 151.008 38.549 152.712 ;
     RECT  37.804 49.008 38.579 54.216 ;
     RECT  38.153 108.288 38.585 114.024 ;
     RECT  38.435 65.952 38.62 91.128 ;
     RECT  38.243 168.144 38.621 171.768 ;
     RECT  38.195 40.416 38.627 43.32 ;
     RECT  38.627 40.416 38.629 42.792 ;
     RECT  38.483 11.472 38.657 18.264 ;
     RECT  38.435 92.352 38.701 92.904 ;
     RECT  38.62 81.6 38.723 91.128 ;
     RECT  38.189 30.24 38.729 32.76 ;
     RECT  38.045 115.776 38.729 118.008 ;
     RECT  38.579 50.736 38.765 54.216 ;
     RECT  38.225 163.68 38.765 165.288 ;
     RECT  38.765 50.736 38.771 54.12 ;
     RECT  38.621 168.384 38.771 171.768 ;
     RECT  37.804 102.384 38.773 103.08 ;
     RECT  37.804 119.472 38.773 119.784 ;
     RECT  37.973 120.864 38.773 120.888 ;
     RECT  37.804 6 38.789 6.84 ;
     RECT  37.804 7.824 38.789 8.52 ;
     RECT  38.585 110.832 38.797 114.024 ;
     RECT  37.804 127.536 38.797 131.88 ;
     RECT  38.729 30.24 38.801 32.616 ;
     RECT  38.195 44.688 38.801 44.712 ;
     RECT  37.804 141.936 38.801 143.544 ;
     RECT  38.765 164.496 38.801 165.288 ;
     RECT  38.773 119.472 38.819 120.888 ;
     RECT  38.729 115.776 38.828 117.672 ;
     RECT  38.195 157.008 38.833 157.272 ;
     RECT  37.955 158.4 38.833 158.424 ;
     RECT  38.801 32.016 38.837 32.616 ;
     RECT  38.435 60.96 38.867 64.44 ;
     RECT  38.797 127.056 38.869 131.88 ;
     RECT  37.804 133.68 38.869 135.912 ;
     RECT  38.801 142.896 38.869 143.544 ;
     RECT  37.955 144.768 38.869 149.736 ;
     RECT  38.723 90.576 38.873 91.128 ;
     RECT  38.549 137.472 38.873 137.88 ;
     RECT  38.771 168.384 38.873 171.096 ;
     RECT  38.797 46.656 38.905 46.68 ;
     RECT  38.801 30.24 38.909 30.312 ;
     RECT  38.833 157.008 38.909 158.424 ;
     RECT  38.789 6 38.915 8.52 ;
     RECT  38.828 115.584 38.915 117.672 ;
     RECT  38.657 11.472 38.945 14.232 ;
     RECT  38.837 32.208 38.945 32.328 ;
     RECT  38.62 65.952 38.945 80.328 ;
     RECT  38.189 27.84 38.973 29.256 ;
     RECT  38.905 46.656 38.977 46.728 ;
     RECT  38.723 81.6 38.981 89.592 ;
     RECT  38.513 47.904 39.013 47.928 ;
     RECT  38.579 49.008 39.013 49.608 ;
     RECT  38.869 127.056 39.049 135.912 ;
     RECT  38.973 27.888 39.059 29.256 ;
     RECT  38.701 92.688 39.059 92.904 ;
     RECT  38.629 40.56 39.089 42.792 ;
     RECT  37.996 94.032 39.089 100.824 ;
     RECT  37.955 159.408 39.089 161.16 ;
     RECT  38.773 102.384 39.107 103.464 ;
     RECT  38.797 110.832 39.109 114.6 ;
     RECT  38.867 63.264 39.121 64.44 ;
     RECT  39.089 95.088 39.125 100.824 ;
     RECT  38.549 139.104 39.125 140.76 ;
     RECT  38.867 61.344 39.161 62.184 ;
     RECT  38.981 81.6 39.161 89.496 ;
     RECT  38.915 6 39.193 6.84 ;
     RECT  38.819 119.472 39.193 120.264 ;
     RECT  39.109 110.832 39.196 114.984 ;
     RECT  38.869 142.896 39.197 149.736 ;
     RECT  39.049 127.056 39.229 136.44 ;
     RECT  38.513 154.944 39.229 156.024 ;
     RECT  38.909 157.008 39.229 158.232 ;
     RECT  39.089 40.56 39.233 42.744 ;
     RECT  39.197 146.448 39.233 149.736 ;
     RECT  39.212 162.24 39.253 162.264 ;
     RECT  38.297 3.6 39.301 3.72 ;
     RECT  39.193 5.424 39.301 6.84 ;
     RECT  37.937 21.456 39.337 21.768 ;
     RECT  37.937 23.088 39.337 23.976 ;
     RECT  39.337 20.928 39.409 23.976 ;
     RECT  39.125 96.576 39.409 100.824 ;
     RECT  38.483 19.536 39.517 19.656 ;
     RECT  39.409 20.928 39.517 24.744 ;
     RECT  38.243 33.888 39.517 33.912 ;
     RECT  38.261 34.896 39.517 34.92 ;
     RECT  39.233 147.744 39.517 149.736 ;
     RECT  39.409 96.576 39.548 101.016 ;
     RECT  39.107 102.384 39.548 102.84 ;
     RECT  38.549 123.744 39.589 125.832 ;
     RECT  38.081 26.4 39.625 26.568 ;
     RECT  39.517 147.744 39.625 150.264 ;
     RECT  38.549 151.392 39.625 152.712 ;
     RECT  38.585 108.288 39.661 109.416 ;
     RECT  38.225 153.696 39.697 153.864 ;
     RECT  39.229 154.944 39.697 158.232 ;
     RECT  38.915 7.968 39.74 8.52 ;
     RECT  38.333 10.272 39.781 10.296 ;
     RECT  39.661 107.856 39.836 109.416 ;
     RECT  38.977 46.608 39.841 46.728 ;
     RECT  39.013 47.904 39.841 49.608 ;
     RECT  39.196 110.832 39.841 114.696 ;
     RECT  38.801 164.496 39.841 165.24 ;
     RECT  38.945 11.664 39.877 14.232 ;
     RECT  38.657 15.504 39.877 18.264 ;
     RECT  39.517 33.888 39.877 34.92 ;
     RECT  39.253 162.24 39.877 162.408 ;
     RECT  39.841 163.68 39.877 165.24 ;
     RECT  38.873 168.384 39.877 169.512 ;
     RECT  38.873 137.472 39.913 137.784 ;
     RECT  39.193 119.232 39.925 120.264 ;
     RECT  39.877 168.384 39.949 169.8 ;
     RECT  39.841 46.608 39.985 49.608 ;
     RECT  38.333 55.968 39.985 58.392 ;
     RECT  39.985 46.56 40.028 49.608 ;
     RECT  38.771 50.736 40.028 53.976 ;
     RECT  39.059 92.88 40.028 92.904 ;
     RECT  39.089 94.032 40.028 94.056 ;
     RECT  39.125 139.104 40.028 139.896 ;
     RECT  39.301 3.6 40.057 6.84 ;
     RECT  38.915 115.968 40.057 117.672 ;
     RECT  39.925 119.232 40.057 120.312 ;
     RECT  39.229 127.056 40.057 136.488 ;
     RECT  39.913 137.472 40.057 137.976 ;
     RECT  39.877 33.888 40.069 35.16 ;
     RECT  40.028 46.56 40.069 53.976 ;
     RECT  39.161 61.344 40.069 61.944 ;
     RECT  40.028 92.88 40.069 94.056 ;
     RECT  39.125 95.088 40.069 95.592 ;
     RECT  39.836 107.712 40.069 109.416 ;
     RECT  39.841 110.496 40.069 114.696 ;
     RECT  40.057 127.056 40.069 137.976 ;
     RECT  40.028 139.008 40.069 139.896 ;
     RECT  38.225 122.208 40.093 122.232 ;
     RECT  39.589 123.264 40.093 125.832 ;
     RECT  39.697 153.696 40.093 158.232 ;
     RECT  39.089 159.408 40.093 160.776 ;
     RECT  39.985 55.152 40.129 58.392 ;
     RECT  40.069 107.712 40.165 114.696 ;
     RECT  39.197 142.896 40.165 145.368 ;
     RECT  39.625 147.744 40.165 152.712 ;
     RECT  40.093 153.696 40.165 160.776 ;
     RECT  40.069 127.056 40.201 139.896 ;
     RECT  40.057 3.6 40.208 6.936 ;
     RECT  39.74 7.968 40.208 9.24 ;
     RECT  39.781 10.272 40.208 10.584 ;
     RECT  39.877 11.664 40.208 18.264 ;
     RECT  39.517 19.536 40.208 24.744 ;
     RECT  39.625 25.824 40.208 26.568 ;
     RECT  39.059 27.936 40.208 29.256 ;
     RECT  38.909 30.288 40.208 30.312 ;
     RECT  38.945 32.208 40.208 32.232 ;
     RECT  40.069 33.6 40.208 35.16 ;
     RECT  38.261 36.192 40.208 39.336 ;
     RECT  39.233 40.56 40.208 40.92 ;
     RECT  39.233 41.952 40.208 42.744 ;
     RECT  39.661 44.064 40.208 44.472 ;
     RECT  40.069 46.08 40.208 53.976 ;
     RECT  40.129 55.152 40.208 58.68 ;
     RECT  38.435 59.808 40.208 59.832 ;
     RECT  40.069 60.816 40.208 61.944 ;
     RECT  39.121 63.264 40.208 64.968 ;
     RECT  38.945 65.952 40.208 80.088 ;
     RECT  39.161 81.6 40.208 89.448 ;
     RECT  38.873 90.624 40.208 91.128 ;
     RECT  40.069 92.88 40.208 95.592 ;
     RECT  39.548 96.576 40.208 102.84 ;
     RECT  38.405 104.544 40.208 106.296 ;
     RECT  40.165 107.376 40.208 114.696 ;
     RECT  40.057 115.968 40.208 120.312 ;
     RECT  40.093 122.208 40.208 125.832 ;
     RECT  40.201 127.056 40.208 140.04 ;
     RECT  39.769 141.264 40.208 141.288 ;
     RECT  40.165 142.368 40.208 145.368 ;
     RECT  39.233 146.448 40.208 146.472 ;
     RECT  40.165 147.744 40.208 160.776 ;
     RECT  39.877 162.24 40.208 165.24 ;
     RECT  39.805 166.416 40.208 166.44 ;
     RECT  39.949 168.096 40.208 169.8 ;
     RECT  38.873 171.072 40.208 171.096 ;
     RECT  39.337 172.368 40.208 172.392 ;
     RECT  40.208 2.148 40.312 172.812 ;
     RECT  40.312 2.418 40.504 172.542 ;
     RECT  40.504 65.52 40.601 72.744 ;
     RECT  40.504 73.872 40.637 75 ;
     RECT  40.504 17.04 40.643 21.384 ;
     RECT  40.504 131.04 40.643 133.08 ;
     RECT  40.504 156.576 40.643 157.032 ;
     RECT  40.504 158.016 40.643 160.824 ;
     RECT  40.643 159.6 40.645 160.824 ;
     RECT  40.504 134.832 40.673 136.488 ;
     RECT  40.504 114.672 40.684 125.352 ;
     RECT  40.684 114.672 40.709 124.824 ;
     RECT  40.504 95.184 40.739 101.736 ;
     RECT  40.504 6.096 40.745 6.888 ;
     RECT  40.504 8.496 40.745 9 ;
     RECT  40.504 154.224 40.745 154.248 ;
     RECT  40.643 158.016 40.745 158.616 ;
     RECT  40.504 3.6 40.781 3.624 ;
     RECT  40.745 8.832 40.781 9 ;
     RECT  40.739 97.872 40.781 101.736 ;
     RECT  40.504 104.544 40.781 106.296 ;
     RECT  40.504 22.464 40.787 22.488 ;
     RECT  40.504 40.56 40.787 49.32 ;
     RECT  40.643 131.28 40.787 133.08 ;
     RECT  40.504 142.368 40.787 146.472 ;
     RECT  40.781 100.08 40.817 101.736 ;
     RECT  40.709 114.672 40.817 115.608 ;
     RECT  40.637 74.64 40.853 75 ;
     RECT  40.781 104.592 40.853 106.296 ;
     RECT  40.739 95.184 40.883 96.744 ;
     RECT  40.601 65.52 40.889 72.552 ;
     RECT  40.781 97.872 40.889 98.76 ;
     RECT  40.853 104.784 40.889 106.296 ;
     RECT  40.787 42.24 40.961 49.32 ;
     RECT  40.817 114.672 40.961 114.696 ;
     RECT  40.787 143.088 40.961 146.472 ;
     RECT  40.889 65.52 40.997 71.16 ;
     RECT  40.997 65.52 41.033 66.072 ;
     RECT  40.504 25.104 41.069 34.776 ;
     RECT  40.504 102.768 41.069 102.984 ;
     RECT  40.504 155.28 41.075 155.448 ;
     RECT  40.961 42.24 41.105 47.784 ;
     RECT  40.745 158.016 41.116 158.568 ;
     RECT  40.961 143.088 41.141 144.216 ;
     RECT  41.141 143.088 41.171 144.072 ;
     RECT  40.504 147.552 41.177 150.744 ;
     RECT  40.645 159.6 41.177 160.776 ;
     RECT  40.504 137.52 41.205 141.288 ;
     RECT  40.643 17.04 41.213 17.784 ;
     RECT  41.105 42.24 41.213 46.2 ;
     RECT  40.504 53.76 41.213 53.832 ;
     RECT  40.504 60.384 41.213 64.344 ;
     RECT  40.504 126.432 41.219 129.48 ;
     RECT  40.643 18.96 41.249 21.384 ;
     RECT  40.817 101.088 41.249 101.736 ;
     RECT  40.709 116.592 41.249 124.824 ;
     RECT  40.504 12.288 41.285 15.864 ;
     RECT  41.213 60.384 41.285 64.152 ;
     RECT  40.504 82.512 41.285 84.408 ;
     RECT  41.069 25.104 41.357 34.152 ;
     RECT  41.285 60.384 41.357 63.384 ;
     RECT  41.249 116.592 41.357 124.728 ;
     RECT  40.504 166.08 41.411 169.656 ;
     RECT  41.249 19.296 41.429 21.384 ;
     RECT  41.357 60.384 41.429 63.24 ;
     RECT  41.205 138.528 41.429 141.288 ;
     RECT  40.643 156.912 41.429 157.032 ;
     RECT  41.213 53.808 41.497 53.832 ;
     RECT  40.504 55.008 41.497 57.144 ;
     RECT  40.889 106.224 41.497 106.296 ;
     RECT  41.075 155.424 41.497 155.448 ;
     RECT  41.285 82.512 41.5 83.832 ;
     RECT  41.357 30.288 41.501 34.152 ;
     RECT  41.429 140.784 41.501 141.288 ;
     RECT  41.411 168.048 41.501 168.504 ;
     RECT  41.285 12.288 41.509 12.888 ;
     RECT  41.285 13.968 41.509 15.864 ;
     RECT  40.961 145.296 41.509 146.472 ;
     RECT  40.504 24.096 41.525 24.12 ;
     RECT  41.357 25.104 41.525 29.256 ;
     RECT  40.504 110.496 41.533 110.52 ;
     RECT  41.213 17.136 41.537 17.784 ;
     RECT  40.504 111.696 41.537 113.064 ;
     RECT  41.219 126.912 41.537 129.48 ;
     RECT  41.509 13.968 41.555 15.96 ;
     RECT  41.171 143.52 41.555 144.072 ;
     RECT  41.509 145.296 41.555 146.52 ;
     RECT  40.504 108.192 41.557 109.272 ;
     RECT  41.533 110.496 41.557 110.712 ;
     RECT  41.537 112.512 41.557 113.064 ;
     RECT  40.504 76.032 41.569 81 ;
     RECT  41.429 19.296 41.573 19.896 ;
     RECT  41.537 129.168 41.573 129.48 ;
     RECT  40.961 49.008 41.605 49.32 ;
     RECT  40.504 87.264 41.605 88.92 ;
     RECT  41.249 101.712 41.605 101.736 ;
     RECT  41.069 102.768 41.605 102.792 ;
     RECT  41.557 108.192 41.605 110.712 ;
     RECT  41.569 76.032 41.609 81.048 ;
     RECT  41.605 108.192 41.644 110.904 ;
     RECT  41.105 47.184 41.651 47.784 ;
     RECT  40.504 51.264 41.651 52.296 ;
     RECT  41.605 87.264 41.651 88.968 ;
     RECT  40.504 90.048 41.651 91.128 ;
     RECT  40.504 152.064 41.653 152.952 ;
     RECT  41.609 79.728 41.677 81.048 ;
     RECT  41.357 116.592 41.677 118.584 ;
     RECT  41.555 14.112 41.681 15.96 ;
     RECT  41.501 30.384 41.681 34.152 ;
     RECT  41.497 53.808 41.681 57.144 ;
     RECT  41.177 159.6 41.681 159.624 ;
     RECT  41.677 116.304 41.689 118.584 ;
     RECT  41.525 24.096 41.717 29.256 ;
     RECT  41.681 30.384 41.717 33.96 ;
     RECT  41.689 116.304 41.717 118.536 ;
     RECT  40.504 162.96 41.749 164.808 ;
     RECT  41.411 166.08 41.749 166.104 ;
     RECT  41.429 21.36 41.753 21.384 ;
     RECT  41.717 24.096 41.753 26.568 ;
     RECT  41.717 27.936 41.753 29.256 ;
     RECT  41.717 30.576 41.753 33.96 ;
     RECT  41.509 11.952 41.756 12.888 ;
     RECT  40.504 35.952 41.756 39.336 ;
     RECT  40.787 40.56 41.756 41.064 ;
     RECT  41.756 35.952 41.777 41.064 ;
     RECT  41.213 42.24 41.777 46.152 ;
     RECT  41.777 35.952 41.785 46.152 ;
     RECT  41.651 87.36 41.789 88.968 ;
     RECT  41.651 90.048 41.789 90.072 ;
     RECT  40.673 134.832 41.789 136.2 ;
     RECT  41.177 160.752 41.789 160.776 ;
     RECT  41.785 35.472 41.795 46.152 ;
     RECT  41.557 112.512 41.795 114.168 ;
     RECT  41.717 116.304 41.795 116.424 ;
     RECT  40.504 94.032 41.804 94.152 ;
     RECT  40.883 95.76 41.813 96.744 ;
     RECT  41.795 46.128 41.825 46.152 ;
     RECT  41.677 79.728 41.845 81.096 ;
     RECT  40.781 8.832 41.852 8.856 ;
     RECT  41.749 162.96 41.861 166.104 ;
     RECT  41.804 93.696 41.891 94.152 ;
     RECT  41.813 95.76 41.891 97.464 ;
     RECT  41.852 8.496 41.893 8.856 ;
     RECT  41.891 95.76 41.893 96.072 ;
     RECT  40.889 104.832 41.893 104.952 ;
     RECT  41.033 65.52 41.897 65.976 ;
     RECT  41.891 97.44 41.897 97.464 ;
     RECT  40.817 100.08 41.929 100.104 ;
     RECT  41.893 104.208 41.929 104.952 ;
     RECT  41.497 106.224 41.929 107.16 ;
     RECT  41.753 24.096 41.933 26.232 ;
     RECT  41.357 119.76 41.933 124.728 ;
     RECT  41.893 8.496 41.939 9.384 ;
     RECT  41.756 11.328 41.939 12.888 ;
     RECT  41.893 95.184 41.939 96.072 ;
     RECT  41.537 126.912 41.939 127.992 ;
     RECT  41.681 14.784 41.941 15.96 ;
     RECT  40.853 74.64 41.965 74.904 ;
     RECT  40.504 85.824 41.965 86.04 ;
     RECT  40.504 92.448 41.989 92.472 ;
     RECT  41.605 101.712 42.085 102.792 ;
     RECT  41.929 104.208 42.085 107.16 ;
     RECT  41.653 152.064 42.101 153.288 ;
     RECT  41.605 49.008 42.109 49.896 ;
     RECT  41.501 141.264 42.133 141.288 ;
     RECT  42.109 48.96 42.145 49.896 ;
     RECT  41.965 74.112 42.145 74.904 ;
     RECT  41.497 155.424 42.145 155.88 ;
     RECT  40.889 72.144 42.217 72.552 ;
     RECT  40.787 131.28 42.217 132.936 ;
     RECT  41.555 145.344 42.217 146.52 ;
     RECT  41.177 147.552 42.217 148.2 ;
     RECT  41.681 55.68 42.229 57.144 ;
     RECT  42.109 59.232 42.229 59.256 ;
     RECT  42.145 48.96 42.253 50.088 ;
     RECT  41.651 51.984 42.253 52.296 ;
     RECT  42.217 72.144 42.253 72.744 ;
     RECT  42.145 155.136 42.253 155.88 ;
     RECT  42.253 154.848 42.277 155.88 ;
     RECT  42.253 48.96 42.289 50.136 ;
     RECT  40.889 98.736 42.325 98.76 ;
     RECT  41.929 100.08 42.325 100.296 ;
     RECT  41.205 137.52 42.325 137.544 ;
     RECT  41.429 138.528 42.325 139.8 ;
     RECT  42.229 55.68 42.332 58.008 ;
     RECT  42.229 59.136 42.332 59.256 ;
     RECT  41.933 123.264 42.361 124.728 ;
     RECT  41.789 134.832 42.361 135.672 ;
     RECT  42.289 48.528 42.397 50.136 ;
     RECT  42.145 73.92 42.421 74.904 ;
     RECT  41.609 76.032 42.421 78.744 ;
     RECT  40.745 6.096 42.433 6.84 ;
     RECT  42.289 115.152 42.433 115.176 ;
     RECT  41.939 9.36 42.469 9.384 ;
     RECT  42.085 10.8 42.469 10.824 ;
     RECT  40.997 67.152 42.469 71.16 ;
     RECT  42.253 72.144 42.469 72.888 ;
     RECT  41.845 79.728 42.469 81.48 ;
     RECT  41.5 82.656 42.469 83.832 ;
     RECT  41.891 94.032 42.469 94.152 ;
     RECT  42.325 137.52 42.469 139.8 ;
     RECT  42.133 141.264 42.469 142.2 ;
     RECT  41.116 158.304 42.469 158.568 ;
     RECT  41.501 168.048 42.469 168.312 ;
     RECT  42.332 55.68 42.505 59.256 ;
     RECT  41.429 60.384 42.505 62.76 ;
     RECT  42.469 79.728 42.505 83.832 ;
     RECT  41.429 157.008 42.541 157.032 ;
     RECT  42.469 158.304 42.541 159.144 ;
     RECT  41.644 110.496 42.572 110.904 ;
     RECT  41.795 112.512 42.572 113.88 ;
     RECT  42.421 22.032 42.577 22.056 ;
     RECT  42.217 145.344 42.577 148.2 ;
     RECT  42.217 131.28 42.613 133.224 ;
     RECT  42.361 134.256 42.613 135.672 ;
     RECT  42.577 22.032 42.641 22.248 ;
     RECT  42.469 137.52 42.649 142.2 ;
     RECT  41.573 19.44 42.661 19.896 ;
     RECT  42.505 55.68 42.661 62.76 ;
     RECT  42.577 145.344 42.677 148.344 ;
     RECT  41.177 149.376 42.677 150.744 ;
     RECT  41.537 17.424 42.685 17.784 ;
     RECT  41.753 29.232 42.716 29.256 ;
     RECT  42.505 79.728 42.716 84.072 ;
     RECT  41.965 85.488 42.716 86.04 ;
     RECT  42.421 73.92 42.721 78.744 ;
     RECT  42.716 79.728 42.721 86.04 ;
     RECT  42.641 22.032 42.757 22.824 ;
     RECT  41.753 27.936 42.757 28.248 ;
     RECT  41.753 30.816 42.757 33.96 ;
     RECT  41.795 35.472 42.757 42.264 ;
     RECT  42.661 55.68 42.757 63.528 ;
     RECT  42.721 73.92 42.757 86.04 ;
     RECT  41.795 116.304 42.757 116.328 ;
     RECT  41.933 119.76 42.757 122.28 ;
     RECT  41.939 127.248 42.757 127.992 ;
     RECT  41.573 129.408 42.757 129.432 ;
     RECT  42.613 131.28 42.757 135.672 ;
     RECT  42.649 137.232 42.757 142.2 ;
     RECT  41.555 143.52 42.757 143.544 ;
     RECT  42.397 48.528 42.793 50.76 ;
     RECT  42.253 51.984 42.793 52.584 ;
     RECT  41.989 92.448 42.793 92.808 ;
     RECT  42.433 114.912 42.793 115.176 ;
     RECT  41.933 24.096 42.901 25.224 ;
     RECT  41.933 26.208 42.901 26.232 ;
     RECT  41.651 47.184 42.901 47.208 ;
     RECT  41.897 65.664 42.901 65.976 ;
     RECT  42.469 67.152 42.901 72.888 ;
     RECT  41.989 4.272 42.908 4.296 ;
     RECT  42.433 6.096 42.908 7.416 ;
     RECT  42.469 9.36 42.908 10.824 ;
     RECT  41.939 11.952 42.908 12.888 ;
     RECT  41.941 14.784 42.908 16.152 ;
     RECT  42.685 17.376 42.908 17.784 ;
     RECT  42.661 19.44 42.908 20.472 ;
     RECT  42.757 21.984 42.908 23.016 ;
     RECT  42.901 24.096 42.908 26.232 ;
     RECT  42.757 27.6 42.908 28.248 ;
     RECT  42.716 29.232 42.908 29.736 ;
     RECT  42.757 30.816 42.908 42.504 ;
     RECT  41.795 43.536 42.908 44.952 ;
     RECT  42.901 46.512 42.908 47.208 ;
     RECT  42.793 48.528 42.908 52.824 ;
     RECT  41.681 53.808 42.908 54.696 ;
     RECT  42.757 55.68 42.908 64.344 ;
     RECT  42.901 65.664 42.908 72.888 ;
     RECT  42.757 73.872 42.908 86.04 ;
     RECT  41.789 87.36 42.908 88.728 ;
     RECT  41.651 91.104 42.908 91.128 ;
     RECT  42.793 92.4 42.908 92.808 ;
     RECT  42.469 94.032 42.908 94.2 ;
     RECT  41.939 95.184 42.908 95.208 ;
     RECT  42.325 98.64 42.908 100.68 ;
     RECT  42.085 101.712 42.908 107.16 ;
     RECT  41.644 108.192 42.908 109.368 ;
     RECT  42.572 110.496 42.908 113.88 ;
     RECT  42.793 114.912 42.908 115.224 ;
     RECT  42.757 116.208 42.908 116.328 ;
     RECT  41.717 117.408 42.908 118.536 ;
     RECT  42.757 119.664 42.908 122.28 ;
     RECT  42.361 123.264 42.908 125.208 ;
     RECT  42.757 127.248 42.908 129.432 ;
     RECT  42.757 131.28 42.908 136.008 ;
     RECT  42.757 137.232 42.908 143.544 ;
     RECT  42.677 145.344 42.908 150.744 ;
     RECT  42.101 152.064 42.908 153.336 ;
     RECT  42.277 154.608 42.908 155.88 ;
     RECT  42.541 157.008 42.908 159.144 ;
     RECT  41.861 162.96 42.908 165.624 ;
     RECT  42.469 168.048 42.908 168.408 ;
     RECT  41.411 169.632 42.908 169.656 ;
     RECT  42.908 2.148 43.012 172.812 ;
     RECT  43.012 2.418 43.204 172.542 ;
     RECT  43.204 140.592 43.229 144.84 ;
     RECT  43.204 16.848 43.265 17.496 ;
     RECT  43.204 58.656 43.265 61.416 ;
     RECT  43.204 115.2 43.265 115.224 ;
     RECT  43.204 145.872 43.265 148.344 ;
     RECT  43.204 12 43.301 13.32 ;
     RECT  43.204 19.536 43.331 21.048 ;
     RECT  43.204 23.904 43.331 23.928 ;
     RECT  43.204 31.92 43.331 33.672 ;
     RECT  43.204 56.352 43.331 57.576 ;
     RECT  43.265 60.816 43.331 61.416 ;
     RECT  43.204 72.432 43.331 74.376 ;
     RECT  43.204 112.512 43.331 113.976 ;
     RECT  43.204 133.008 43.331 139.224 ;
     RECT  43.229 140.592 43.331 143.832 ;
     RECT  43.229 144.816 43.331 144.84 ;
     RECT  43.265 145.872 43.331 147.048 ;
     RECT  43.331 21.024 43.337 21.048 ;
     RECT  43.204 27.888 43.337 28.248 ;
     RECT  43.331 31.92 43.337 33.624 ;
     RECT  43.204 94.032 43.337 94.056 ;
     RECT  43.204 116.736 43.337 116.952 ;
     RECT  43.331 113.856 43.372 113.976 ;
     RECT  43.204 29.616 43.373 30.888 ;
     RECT  43.265 58.656 43.373 59.64 ;
     RECT  43.204 92.4 43.373 92.76 ;
     RECT  43.265 148.32 43.373 148.344 ;
     RECT  43.373 29.616 43.379 30.792 ;
     RECT  43.373 92.4 43.379 92.424 ;
     RECT  43.204 118.56 43.379 121.56 ;
     RECT  43.204 153.6 43.379 159.144 ;
     RECT  43.379 118.56 43.381 118.584 ;
     RECT  43.204 15.744 43.409 15.864 ;
     RECT  43.337 27.936 43.409 28.248 ;
     RECT  43.337 31.92 43.409 32.232 ;
     RECT  43.204 126.432 43.409 128.712 ;
     RECT  43.331 145.968 43.409 147.048 ;
     RECT  43.204 34.752 43.427 38.568 ;
     RECT  43.204 40.56 43.427 49.032 ;
     RECT  43.331 56.4 43.427 57.576 ;
     RECT  43.204 125.184 43.445 125.208 ;
     RECT  43.427 40.56 43.481 46.392 ;
     RECT  43.204 75.792 43.481 88.728 ;
     RECT  43.409 126.432 43.517 127.608 ;
     RECT  43.481 75.792 43.553 87.672 ;
     RECT  43.379 153.6 43.553 158.856 ;
     RECT  43.372 113.856 43.571 113.88 ;
     RECT  43.337 116.928 43.571 116.952 ;
     RECT  43.379 119.76 43.571 121.56 ;
     RECT  43.265 17.376 43.589 17.496 ;
     RECT  43.331 133.104 43.589 139.224 ;
     RECT  43.427 56.88 43.619 57.576 ;
     RECT  43.553 75.792 43.625 85.128 ;
     RECT  43.204 106.224 43.625 106.248 ;
     RECT  43.553 153.6 43.625 157.56 ;
     RECT  43.589 133.104 43.633 139.128 ;
     RECT  43.204 7.392 43.653 7.416 ;
     RECT  43.204 62.592 43.661 71.352 ;
     RECT  43.625 75.792 43.661 80.376 ;
     RECT  43.625 81.36 43.661 85.128 ;
     RECT  43.409 31.92 43.697 31.944 ;
     RECT  43.373 58.656 43.697 58.68 ;
     RECT  43.204 163.008 43.697 169.272 ;
     RECT  43.331 74.352 43.715 74.376 ;
     RECT  43.331 60.912 43.733 61.416 ;
     RECT  43.204 6.24 43.769 6.264 ;
     RECT  43.337 33.312 43.769 33.624 ;
     RECT  43.625 153.6 43.769 157.032 ;
     RECT  43.517 126.48 43.805 127.608 ;
     RECT  43.204 99.168 43.811 99.192 ;
     RECT  43.409 28.224 43.841 28.248 ;
     RECT  43.427 47.424 43.841 49.032 ;
     RECT  43.769 156.144 43.841 157.032 ;
     RECT  43.204 104.304 43.859 104.328 ;
     RECT  43.204 9.168 43.877 9.192 ;
     RECT  43.661 69.408 43.877 71.352 ;
     RECT  43.331 72.432 43.877 72.936 ;
     RECT  43.409 146.208 43.877 147.048 ;
     RECT  43.697 163.008 43.877 166.392 ;
     RECT  43.204 10.8 43.907 10.824 ;
     RECT  43.301 12.192 43.907 13.32 ;
     RECT  43.661 81.36 43.907 84.024 ;
     RECT  43.571 121.44 43.907 121.56 ;
     RECT  43.733 60.912 43.949 61.176 ;
     RECT  43.907 81.36 43.949 82.632 ;
     RECT  43.661 75.792 43.955 76.92 ;
     RECT  43.949 81.408 43.955 82.632 ;
     RECT  43.769 153.6 43.955 154.872 ;
     RECT  43.589 17.472 43.985 17.496 ;
     RECT  43.619 57.024 43.985 57.576 ;
     RECT  43.571 119.76 43.985 119.784 ;
     RECT  43.633 133.104 43.985 138.648 ;
     RECT  43.697 167.472 43.985 169.272 ;
     RECT  43.331 19.536 44.021 19.944 ;
     RECT  43.481 40.896 44.021 46.392 ;
     RECT  44.021 46.272 44.093 46.392 ;
     RECT  43.553 86.496 44.099 87.672 ;
     RECT  43.553 158.832 44.129 158.856 ;
     RECT  43.985 167.472 44.129 167.496 ;
     RECT  43.204 22.032 44.165 22.776 ;
     RECT  43.661 62.592 44.197 68.232 ;
     RECT  43.331 112.512 44.201 112.536 ;
     RECT  43.985 135.168 44.201 138.648 ;
     RECT  43.907 12.72 44.237 13.32 ;
     RECT  43.661 78.048 44.237 80.376 ;
     RECT  43.907 121.536 44.237 121.56 ;
     RECT  44.201 135.6 44.243 138.648 ;
     RECT  44.021 19.632 44.273 19.944 ;
     RECT  43.204 24.912 44.273 25.464 ;
     RECT  43.331 140.592 44.273 143.304 ;
     RECT  44.237 13.296 44.305 13.32 ;
     RECT  43.985 57.024 44.309 57.096 ;
     RECT  44.197 62.4 44.345 68.232 ;
     RECT  43.805 126.48 44.345 127.08 ;
     RECT  43.379 29.616 44.377 30.168 ;
     RECT  43.985 133.104 44.377 133.752 ;
     RECT  43.204 161.184 44.377 161.208 ;
     RECT  44.093 46.32 44.381 46.392 ;
     RECT  43.204 130.512 44.413 131.64 ;
     RECT  44.377 132.912 44.413 133.752 ;
     RECT  44.021 40.896 44.435 45.192 ;
     RECT  44.377 29.616 44.437 30.552 ;
     RECT  43.769 33.312 44.437 33.528 ;
     RECT  43.949 60.912 44.437 61.032 ;
     RECT  44.437 60.816 44.438 61.032 ;
     RECT  43.877 69.408 44.453 71.016 ;
     RECT  44.243 135.648 44.453 138.648 ;
     RECT  44.305 13.296 44.483 14.232 ;
     RECT  44.273 19.92 44.483 19.944 ;
     RECT  44.273 25.44 44.483 25.464 ;
     RECT  44.437 29.616 44.483 31.128 ;
     RECT  44.345 62.4 44.483 67.32 ;
     RECT  44.237 79.68 44.483 80.376 ;
     RECT  43.877 163.008 44.483 164.28 ;
     RECT  44.405 15.984 44.489 16.008 ;
     RECT  44.483 62.448 44.489 67.32 ;
     RECT  44.099 87.36 44.489 87.624 ;
     RECT  43.204 26.736 44.492 26.76 ;
     RECT  44.437 27.744 44.492 27.768 ;
     RECT  43.955 81.456 44.497 82.632 ;
     RECT  44.437 21.648 44.525 21.672 ;
     RECT  44.437 24.24 44.525 24.264 ;
     RECT  43.877 165.6 44.525 166.392 ;
     RECT  44.165 22.752 44.561 22.776 ;
     RECT  44.492 26.736 44.561 27.768 ;
     RECT  43.427 34.752 44.561 36.408 ;
     RECT  43.661 85.104 44.561 85.128 ;
     RECT  44.561 27.216 44.579 27.768 ;
     RECT  43.204 122.88 44.588 123.816 ;
     RECT  44.453 69.408 44.597 70.68 ;
     RECT  43.427 37.392 44.629 38.568 ;
     RECT  44.305 39.6 44.629 39.624 ;
     RECT  44.273 140.592 44.629 142.488 ;
     RECT  44.483 13.296 44.633 13.32 ;
     RECT  44.489 62.448 44.633 67.176 ;
     RECT  43.204 149.376 44.633 150.984 ;
     RECT  43.204 160.176 44.665 160.2 ;
     RECT  44.377 161.184 44.665 161.304 ;
     RECT  43.841 157.008 44.737 157.032 ;
     RECT  44.701 56.88 44.773 57 ;
     RECT  44.377 152.736 44.773 152.856 ;
     RECT  44.437 32.736 44.783 33.528 ;
     RECT  44.579 27.744 44.809 27.768 ;
     RECT  43.204 50.016 44.809 55.32 ;
     RECT  44.869 59.808 44.881 59.832 ;
     RECT  43.409 128.688 44.881 128.712 ;
     RECT  44.881 59.184 44.953 59.832 ;
     RECT  43.955 75.792 44.953 76.776 ;
     RECT  43.877 146.208 44.953 146.232 ;
     RECT  44.483 79.824 44.989 80.376 ;
     RECT  44.497 81.456 44.989 82.584 ;
     RECT  44.953 58.656 45.025 59.832 ;
     RECT  44.881 128.688 45.025 128.808 ;
     RECT  44.737 157.008 45.061 157.608 ;
     RECT  44.435 42.72 45.097 45.192 ;
     RECT  43.877 72.432 45.133 72.456 ;
     RECT  44.413 130.512 45.205 133.752 ;
     RECT  44.953 75.648 45.253 76.776 ;
     RECT  44.435 40.896 45.311 41.688 ;
     RECT  44.237 78.048 45.341 78.504 ;
     RECT  44.665 160.176 45.349 161.304 ;
     RECT  44.953 146.208 45.385 146.424 ;
     RECT  44.773 56.784 45.397 57 ;
     RECT  45.169 73.488 45.421 73.512 ;
     RECT  44.453 138.624 45.452 138.648 ;
     RECT  44.629 140.208 45.452 142.488 ;
     RECT  44.453 135.648 45.455 137.208 ;
     RECT  44.629 37.392 45.493 39.624 ;
     RECT  45.311 40.8 45.493 41.688 ;
     RECT  44.345 126.528 45.493 127.08 ;
     RECT  45.025 128.688 45.493 128.952 ;
     RECT  45.455 135.648 45.493 137.64 ;
     RECT  45.452 138.624 45.493 142.488 ;
     RECT  44.561 34.752 45.529 34.776 ;
     RECT  44.561 35.904 45.529 36.168 ;
     RECT  43.841 47.424 45.565 48.264 ;
     RECT  44.597 69.408 45.565 69.432 ;
     RECT  44.597 70.512 45.565 70.68 ;
     RECT  44.809 27.744 45.608 28.296 ;
     RECT  44.483 29.616 45.608 29.64 ;
     RECT  44.483 31.104 45.608 31.128 ;
     RECT  44.783 32.736 45.608 33.576 ;
     RECT  45.529 34.752 45.608 36.168 ;
     RECT  45.493 37.392 45.608 41.688 ;
     RECT  45.097 42.72 45.608 45.576 ;
     RECT  45.565 47.424 45.608 48.504 ;
     RECT  44.809 49.92 45.608 55.32 ;
     RECT  45.397 56.448 45.608 57 ;
     RECT  45.025 58.128 45.608 59.832 ;
     RECT  44.438 60.816 45.608 60.84 ;
     RECT  44.633 62.448 45.608 64.728 ;
     RECT  44.633 66.096 45.608 67.176 ;
     RECT  45.565 69.408 45.608 70.68 ;
     RECT  45.133 71.856 45.608 72.456 ;
     RECT  45.421 73.488 45.608 73.896 ;
     RECT  45.253 75.648 45.608 76.92 ;
     RECT  45.341 78.048 45.608 78.552 ;
     RECT  44.989 79.824 45.608 82.584 ;
     RECT  43.907 83.616 45.608 84.024 ;
     RECT  44.489 87.36 45.608 87.384 ;
     RECT  43.481 88.704 45.608 88.728 ;
     RECT  44.588 122.496 45.608 124.536 ;
     RECT  45.493 126.528 45.608 128.952 ;
     RECT  45.205 129.936 45.608 133.752 ;
     RECT  45.493 135.648 45.608 142.488 ;
     RECT  44.78 143.664 45.608 143.688 ;
     RECT  45.385 145.488 45.608 146.424 ;
     RECT  44.953 147.648 45.608 147.672 ;
     RECT  44.633 149.376 45.608 150.648 ;
     RECT  44.773 152.16 45.608 152.856 ;
     RECT  43.955 154.08 45.608 154.872 ;
     RECT  45.061 156.192 45.608 157.608 ;
     RECT  45.349 159.216 45.608 161.304 ;
     RECT  44.483 163.68 45.608 164.28 ;
     RECT  44.525 166.368 45.608 166.392 ;
     RECT  43.985 169.248 45.608 169.272 ;
     RECT  45.608 2.148 45.712 172.812 ;
     RECT  45.712 2.418 45.904 172.542 ;
     RECT  45.904 56.832 46.019 59.208 ;
     RECT  45.904 65.52 46.019 65.544 ;
     RECT  45.904 66.768 46.019 69.864 ;
     RECT  45.904 88.704 46.019 88.728 ;
     RECT  45.904 87.36 46.037 87.384 ;
     RECT  45.904 157.872 46.037 157.896 ;
     RECT  45.904 76.032 46.067 76.056 ;
     RECT  45.904 129.936 46.067 133.368 ;
     RECT  45.904 152.256 46.067 152.712 ;
     RECT  45.904 165.6 46.067 165.624 ;
     RECT  45.904 38.16 46.073 38.808 ;
     RECT  46.067 152.688 46.081 152.712 ;
     RECT  45.904 153.888 46.081 156.216 ;
     RECT  45.904 163.536 46.108 164.28 ;
     RECT  45.904 60.816 46.115 62.568 ;
     RECT  45.904 126.624 46.115 127.08 ;
     RECT  45.904 160.704 46.115 161.832 ;
     RECT  46.019 66.768 46.145 69 ;
     RECT  46.067 133.296 46.145 133.368 ;
     RECT  46.115 126.624 46.153 126.648 ;
     RECT  46.145 68.112 46.156 69 ;
     RECT  45.904 33.552 46.163 36.552 ;
     RECT  45.904 128.832 46.163 128.856 ;
     RECT  46.081 153.888 46.163 154.104 ;
     RECT  46.163 33.984 46.181 35.736 ;
     RECT  46.156 68.208 46.181 69 ;
     RECT  46.067 129.936 46.181 132.168 ;
     RECT  46.181 33.984 46.217 34.632 ;
     RECT  46.181 35.712 46.217 35.736 ;
     RECT  45.904 40.128 46.217 40.152 ;
     RECT  45.904 136.176 46.217 141.528 ;
     RECT  46.115 161.088 46.217 161.832 ;
     RECT  46.108 164.256 46.217 164.28 ;
     RECT  46.145 133.344 46.253 133.368 ;
     RECT  46.217 139.68 46.289 141.528 ;
     RECT  45.904 159.216 46.289 159.432 ;
     RECT  46.163 153.888 46.325 153.912 ;
     RECT  46.081 155.568 46.325 156.216 ;
     RECT  46.073 38.16 46.361 38.712 ;
     RECT  46.181 68.208 46.361 68.232 ;
     RECT  45.904 44.88 46.397 45.576 ;
     RECT  46.217 136.176 46.397 138.6 ;
     RECT  46.289 159.216 46.397 159.24 ;
     RECT  45.904 42.096 46.403 43.416 ;
     RECT  46.217 33.984 46.433 34.008 ;
     RECT  46.115 62.448 46.469 62.568 ;
     RECT  46.397 45.552 46.505 45.576 ;
     RECT  46.361 38.16 46.577 38.184 ;
     RECT  46.403 42.768 46.577 43.416 ;
     RECT  46.397 136.752 46.577 138.6 ;
     RECT  45.904 46.8 46.613 55.848 ;
     RECT  46.181 129.936 46.691 132.12 ;
     RECT  46.577 136.752 46.691 136.776 ;
     RECT  46.577 138.576 46.721 138.6 ;
     RECT  45.904 135.072 46.732 135.096 ;
     RECT  45.904 63.792 46.757 63.816 ;
     RECT  46.613 46.8 46.787 51.672 ;
     RECT  45.904 143.04 46.787 146.424 ;
     RECT  46.787 48.48 46.829 51.672 ;
     RECT  46.115 60.816 46.829 60.84 ;
     RECT  46.289 140.208 46.829 141.528 ;
     RECT  46.787 143.04 46.829 145.752 ;
     RECT  46.217 161.808 46.829 161.832 ;
     RECT  46.613 55.824 46.837 55.848 ;
     RECT  46.145 66.768 46.865 66.888 ;
     RECT  46.829 143.04 46.865 144.312 ;
     RECT  45.904 150.144 46.901 150.456 ;
     RECT  46.577 43.392 46.937 43.416 ;
     RECT  46.787 46.8 46.937 46.824 ;
     RECT  46.829 48.96 46.937 51.672 ;
     RECT  46.613 53.04 46.973 54.696 ;
     RECT  46.829 141.504 46.973 141.528 ;
     RECT  46.829 145.536 46.973 145.56 ;
     RECT  46.937 49.728 46.979 51.672 ;
     RECT  46.973 53.04 47.017 53.064 ;
     RECT  46.019 56.832 47.036 57.048 ;
     RECT  46.865 66.768 47.045 66.792 ;
     RECT  46.019 58.56 47.077 58.584 ;
     RECT  47.036 56.832 47.123 57.576 ;
     RECT  47.077 58.56 47.153 59.448 ;
     RECT  46.691 129.936 47.153 129.96 ;
     RECT  46.865 143.04 47.153 143.88 ;
     RECT  47.005 150.48 47.153 150.504 ;
     RECT  47.153 59.424 47.164 59.448 ;
     RECT  46.979 49.728 47.189 49.752 ;
     RECT  46.469 62.544 47.189 62.568 ;
     RECT  46.973 54.096 47.261 54.696 ;
     RECT  47.153 143.04 47.333 143.064 ;
     RECT  47.261 54.672 48.308 54.696 ;
     RECT  47.123 56.832 48.308 56.856 ;
     RECT  48.308 2.148 48.412 172.812 ;
     RECT  48.412 2.418 48.604 172.542 ;
     RECT  51.008 2.148 51.112 172.812 ;
     RECT  51.112 2.418 51.304 172.542 ;
     RECT  53.708 2.148 53.812 172.812 ;
     RECT  53.812 2.418 54.004 172.542 ;
     RECT  56.408 2.148 56.512 172.812 ;
     RECT  56.512 2.418 56.704 172.542 ;
     RECT  59.108 2.148 59.212 172.812 ;
     RECT  59.212 2.418 59.404 172.542 ;
     RECT  61.808 2.148 61.912 172.812 ;
     RECT  61.912 2.418 62.104 172.542 ;
     RECT  64.508 2.148 64.612 172.812 ;
     RECT  64.612 2.418 64.804 172.542 ;
     RECT  67.208 2.148 67.312 172.812 ;
     RECT  67.312 2.418 67.504 172.542 ;
     RECT  69.908 2.148 70.012 172.812 ;
     RECT  70.012 2.418 70.204 172.542 ;
     RECT  72.608 2.148 72.712 172.812 ;
     RECT  72.712 2.418 72.904 172.542 ;
     RECT  75.308 2.148 75.412 172.812 ;
     RECT  75.412 2.418 75.604 172.542 ;
     RECT  78.008 2.148 78.112 172.812 ;
     RECT  78.112 2.418 78.304 172.542 ;
     RECT  80.708 2.148 80.812 172.812 ;
     RECT  80.812 2.418 81.004 172.542 ;
     RECT  83.408 2.148 83.512 172.812 ;
     RECT  83.512 2.418 83.704 172.542 ;
     RECT  86.108 2.148 86.212 172.812 ;
     RECT  86.212 2.418 86.404 172.542 ;
     RECT  88.808 2.148 88.912 172.812 ;
     RECT  88.912 2.418 89.104 172.542 ;
     RECT  91.508 2.148 91.612 172.812 ;
     RECT  91.612 2.418 91.804 172.542 ;
     RECT  94.208 2.148 94.312 172.812 ;
     RECT  94.312 2.418 94.504 172.542 ;
     RECT  42.073 0.048 94.789 0.072 ;
     RECT  94.789 0.048 94.835 0.216 ;
     RECT  94.835 0.192 95.075 0.216 ;
     RECT  96.908 2.148 97.012 172.812 ;
     RECT  97.012 2.418 97.204 172.542 ;
     RECT  99.608 2.148 99.712 172.812 ;
     RECT  99.712 2.418 99.904 172.542 ;
     RECT  102.308 2.148 102.412 172.812 ;
     RECT  102.412 2.418 102.604 172.542 ;
     RECT  105.008 2.148 105.112 172.812 ;
     RECT  105.112 2.418 105.304 172.542 ;
     RECT  107.708 2.148 107.812 172.812 ;
     RECT  107.812 2.418 108.004 172.542 ;
     RECT  110.408 2.148 110.512 172.812 ;
     RECT  110.512 2.418 110.704 172.542 ;
     RECT  113.108 2.148 113.212 172.812 ;
     RECT  113.212 2.418 113.404 172.542 ;
     RECT  115.808 2.148 115.912 172.812 ;
     RECT  115.912 2.418 116.104 172.542 ;
     RECT  118.508 2.148 118.612 172.812 ;
     RECT  118.612 2.418 118.804 172.542 ;
     RECT  121.208 2.148 121.312 172.812 ;
     RECT  121.312 2.418 121.504 172.542 ;
     RECT  123.908 2.148 124.012 172.812 ;
     RECT  124.012 2.418 124.204 172.542 ;
     RECT  126.608 2.148 126.712 172.812 ;
     RECT  126.712 2.418 126.904 172.542 ;
    LAYER M5 ;
     RECT  94.8 0.037 94.824 0.144 ;
     RECT  24.768 0.181 24.792 2.137 ;
     RECT  2.4 2.137 2.52 2.151 ;
     RECT  5.1 2.137 5.22 2.151 ;
     RECT  7.8 2.137 7.92 2.151 ;
     RECT  10.5 2.137 10.62 2.151 ;
     RECT  13.2 2.137 13.32 2.151 ;
     RECT  15.9 2.137 16.02 2.151 ;
     RECT  18.6 2.137 18.72 2.151 ;
     RECT  21.3 2.137 21.42 2.151 ;
     RECT  26.7 2.137 26.82 2.151 ;
     RECT  29.4 2.137 29.52 2.151 ;
     RECT  32.1 2.137 32.22 2.151 ;
     RECT  34.8 2.137 34.92 2.151 ;
     RECT  37.5 2.137 37.62 2.151 ;
     RECT  40.2 2.137 40.32 2.151 ;
     RECT  42.9 2.137 43.02 2.151 ;
     RECT  45.6 2.137 45.72 2.151 ;
     RECT  48.3 2.137 48.42 2.151 ;
     RECT  51 2.137 51.12 2.151 ;
     RECT  53.7 2.137 53.82 2.151 ;
     RECT  56.4 2.137 56.52 2.151 ;
     RECT  59.1 2.137 59.22 2.151 ;
     RECT  61.8 2.137 61.92 2.151 ;
     RECT  64.5 2.137 64.62 2.151 ;
     RECT  67.2 2.137 67.32 2.151 ;
     RECT  69.9 2.137 70.02 2.151 ;
     RECT  72.6 2.137 72.72 2.151 ;
     RECT  75.3 2.137 75.42 2.151 ;
     RECT  78 2.137 78.12 2.151 ;
     RECT  80.7 2.137 80.82 2.151 ;
     RECT  83.4 2.137 83.52 2.151 ;
     RECT  86.1 2.137 86.22 2.151 ;
     RECT  88.8 2.137 88.92 2.151 ;
     RECT  91.5 2.137 91.62 2.151 ;
     RECT  94.2 2.137 94.32 2.151 ;
     RECT  96.9 2.137 97.02 2.151 ;
     RECT  99.6 2.137 99.72 2.151 ;
     RECT  102.3 2.137 102.42 2.151 ;
     RECT  105 2.137 105.12 2.151 ;
     RECT  107.7 2.137 107.82 2.151 ;
     RECT  110.4 2.137 110.52 2.151 ;
     RECT  113.1 2.137 113.22 2.151 ;
     RECT  115.8 2.137 115.92 2.151 ;
     RECT  118.5 2.137 118.62 2.151 ;
     RECT  121.2 2.137 121.32 2.151 ;
     RECT  123.9 2.137 124.02 2.151 ;
     RECT  126.6 2.137 126.72 2.151 ;
     RECT  7.8 2.151 8.112 2.245 ;
     RECT  24 2.137 24.792 2.245 ;
     RECT  32.1 2.151 32.412 2.245 ;
     RECT  34.8 2.151 35.112 2.245 ;
     RECT  24 2.245 25.176 2.677 ;
     RECT  7.8 2.245 8.28 2.725 ;
     RECT  5.1 2.151 5.412 2.821 ;
     RECT  26.7 2.151 27.012 2.821 ;
     RECT  33.936 2.245 35.112 2.821 ;
     RECT  2.4 2.151 2.712 2.869 ;
     RECT  5.1 2.821 5.592 3.299 ;
     RECT  18.6 2.151 18.912 3.349 ;
     RECT  15.9 2.151 16.212 3.397 ;
     RECT  21.3 2.151 21.612 3.397 ;
     RECT  13.2 2.151 13.512 3.445 ;
     RECT  29.4 2.151 29.712 3.589 ;
     RECT  40.2 2.151 40.512 3.685 ;
     RECT  14.688 3.157 14.712 3.925 ;
     RECT  15.9 3.397 16.344 4.117 ;
     RECT  42.9 2.151 43.212 4.261 ;
     RECT  15.9 4.117 16.44 4.405 ;
     RECT  14.688 3.925 14.904 4.595 ;
     RECT  24 2.677 25.656 4.595 ;
     RECT  33.936 2.821 35.592 4.595 ;
     RECT  7.8 2.725 8.904 4.645 ;
     RECT  18.6 3.349 19.416 4.691 ;
     RECT  37.5 2.151 37.812 4.741 ;
     RECT  29.184 3.589 29.712 5.077 ;
     RECT  2.4 2.869 3.288 5.171 ;
     RECT  26.7 2.821 27.912 5.171 ;
     RECT  34.8 4.595 35.592 5.171 ;
     RECT  21.072 3.397 21.612 5.365 ;
     RECT  6.96 4.645 8.904 5.459 ;
     RECT  14.88 4.595 14.904 5.605 ;
     RECT  15.9 4.405 16.968 5.605 ;
     RECT  13.008 3.445 13.512 5.651 ;
     RECT  7.8 5.459 8.904 5.747 ;
     RECT  20.88 5.365 21.612 5.845 ;
     RECT  39.312 3.685 40.512 5.989 ;
     RECT  10.5 2.151 10.812 6.085 ;
     RECT  38.832 5.989 40.512 6.085 ;
     RECT  42 4.261 43.212 6.229 ;
     RECT  38.832 6.085 40.728 6.275 ;
     RECT  31.872 2.245 32.412 6.323 ;
     RECT  5.1 3.299 5.412 6.709 ;
     RECT  7.8 5.747 8.112 6.805 ;
     RECT  18.6 4.691 18.912 6.805 ;
     RECT  29.184 5.077 30.264 6.899 ;
     RECT  40.2 6.275 40.728 6.899 ;
     RECT  13.2 5.651 13.512 6.949 ;
     RECT  24 4.595 24.792 7.189 ;
     RECT  20.88 5.845 21.72 7.237 ;
     RECT  14.88 5.605 16.968 7.475 ;
     RECT  38.832 6.275 38.856 7.475 ;
     RECT  15.9 7.475 16.968 7.765 ;
     RECT  33.408 7.717 33.432 7.765 ;
     RECT  13.104 6.949 13.512 7.909 ;
     RECT  29.184 6.899 29.712 7.909 ;
     RECT  24 7.189 25.656 8.003 ;
     RECT  27.984 6.229 28.008 8.389 ;
     RECT  29.184 7.909 30.648 8.389 ;
     RECT  38.88 7.765 38.904 8.437 ;
     RECT  40.2 6.899 40.512 8.437 ;
     RECT  20.448 7.237 21.72 8.483 ;
     RECT  34.8 5.171 35.112 8.485 ;
     RECT  42 6.229 43.608 8.485 ;
     RECT  7.8 6.805 8.376 8.723 ;
     RECT  18.6 6.805 19.08 8.771 ;
     RECT  5.1 6.709 5.544 8.963 ;
     RECT  34.8 8.485 35.208 8.965 ;
     RECT  10.272 6.085 10.812 9.061 ;
     RECT  41.904 8.485 43.608 9.203 ;
     RECT  27.984 8.389 30.648 9.251 ;
     RECT  22.752 8.677 22.776 9.491 ;
     RECT  33.408 7.765 33.816 9.637 ;
     RECT  34.8 8.965 35.88 9.637 ;
     RECT  20.448 8.483 21.612 9.779 ;
     RECT  18.6 8.771 18.912 9.781 ;
     RECT  5.1 8.963 5.412 9.877 ;
     RECT  15.9 7.765 17.064 10.453 ;
     RECT  18.192 9.781 18.912 10.453 ;
     RECT  38.88 8.437 40.512 10.595 ;
     RECT  27.984 9.251 29.712 10.643 ;
     RECT  24 8.003 25.608 10.741 ;
     RECT  26.7 5.171 27.012 10.741 ;
     RECT  4.992 9.877 5.412 10.789 ;
     RECT  21.3 9.779 21.612 10.789 ;
     RECT  41.904 9.203 43.212 10.789 ;
     RECT  14.88 7.475 14.904 10.837 ;
     RECT  15.9 10.453 18.912 10.837 ;
     RECT  13.056 7.909 13.512 11.221 ;
     RECT  41.904 10.789 43.896 11.317 ;
     RECT  6.72 10.885 6.744 11.509 ;
     RECT  33.408 9.637 35.88 11.651 ;
     RECT  2.4 5.171 2.712 11.701 ;
     RECT  12.72 11.221 13.512 11.893 ;
     RECT  37.152 4.741 37.812 11.941 ;
     RECT  38.88 10.595 38.904 11.941 ;
     RECT  41.808 11.317 43.896 11.941 ;
     RECT  7.8 8.723 8.112 11.989 ;
     RECT  9.552 9.061 10.812 11.989 ;
     RECT  33.408 11.651 35.352 12.035 ;
     RECT  22.896 10.501 22.92 12.227 ;
     RECT  32.1 6.323 32.412 12.229 ;
     RECT  33.408 12.035 33.432 12.229 ;
     RECT  32.1 12.229 33.432 12.275 ;
     RECT  4.512 10.789 5.412 12.515 ;
     RECT  24 10.741 27.012 12.563 ;
     RECT  34.8 12.035 35.352 12.563 ;
     RECT  41.52 11.941 43.896 12.755 ;
     RECT  6.528 11.509 6.744 12.851 ;
     RECT  12.528 11.893 13.512 12.901 ;
     RECT  40.2 10.595 40.512 12.997 ;
     RECT  41.52 12.755 43.212 12.997 ;
     RECT  37.152 11.941 38.904 13.043 ;
     RECT  32.1 12.275 33.096 13.333 ;
     RECT  12.288 12.901 13.512 13.573 ;
     RECT  21.12 10.789 21.612 13.573 ;
     RECT  38.88 13.043 38.904 13.621 ;
     RECT  40.2 12.997 43.212 13.621 ;
     RECT  5.1 12.515 5.412 13.669 ;
     RECT  38.88 13.621 43.212 13.715 ;
     RECT  34.8 12.563 35.112 13.813 ;
     RECT  7.8 11.989 10.812 13.861 ;
     RECT  5.1 13.669 5.544 13.957 ;
     RECT  7.8 13.861 10.92 14.003 ;
     RECT  4.224 13.957 5.544 14.197 ;
     RECT  39.216 13.715 43.212 14.243 ;
     RECT  28.464 10.643 29.712 14.245 ;
     RECT  21.12 13.573 22.296 14.291 ;
     RECT  3.936 14.197 5.544 14.531 ;
     RECT  34.8 13.813 35.448 14.581 ;
     RECT  24 12.563 25.656 14.627 ;
     RECT  1.68 11.701 2.712 14.629 ;
     RECT  32.1 13.333 33.288 14.915 ;
     RECT  1.104 14.629 2.712 15.061 ;
     RECT  3.936 14.531 3.96 15.061 ;
     RECT  12.24 13.573 13.512 15.157 ;
     RECT  9.552 14.003 10.92 15.349 ;
     RECT  12.24 15.157 13.608 15.349 ;
     RECT  9.552 15.349 13.608 15.395 ;
     RECT  28.464 14.245 30.504 15.731 ;
     RECT  26.7 12.563 27.012 15.877 ;
     RECT  28.464 15.731 29.712 15.877 ;
     RECT  44.448 14.197 44.472 16.019 ;
     RECT  1.104 15.061 3.96 16.309 ;
     RECT  7.8 14.003 8.112 16.309 ;
     RECT  21.12 14.291 21.612 16.595 ;
     RECT  9.552 15.395 13.512 16.789 ;
     RECT  9.12 16.789 13.512 16.835 ;
     RECT  37.152 13.043 37.812 16.885 ;
     RECT  7.584 16.309 8.112 16.981 ;
     RECT  9.12 16.835 9.144 16.981 ;
     RECT  1.056 16.309 3.96 17.075 ;
     RECT  34.8 14.581 35.592 17.075 ;
     RECT  34.8 17.075 35.112 17.077 ;
     RECT  7.584 16.981 9.144 17.171 ;
     RECT  32.1 14.915 33.096 17.413 ;
     RECT  31.296 17.413 33.096 17.509 ;
     RECT  39.312 14.243 43.212 17.605 ;
     RECT  34.32 17.077 35.112 17.651 ;
     RECT  6.528 12.851 6.552 17.699 ;
     RECT  9.12 17.171 9.144 17.699 ;
     RECT  10.5 16.835 13.512 17.699 ;
     RECT  1.056 17.075 3.48 17.891 ;
     RECT  5.1 14.531 5.544 17.989 ;
     RECT  14.88 10.837 18.912 18.229 ;
     RECT  10.5 17.699 11.448 18.275 ;
     RECT  37.152 16.885 38.232 18.757 ;
     RECT  39.216 17.605 43.212 18.757 ;
     RECT  12.528 17.699 13.512 18.851 ;
     RECT  34.704 17.651 35.112 18.851 ;
     RECT  26.7 15.877 29.712 18.995 ;
     RECT  30.768 17.509 33.096 18.995 ;
     RECT  7.584 17.171 8.112 19.333 ;
     RECT  14.88 18.229 19.512 19.333 ;
     RECT  14.832 19.333 19.512 19.621 ;
     RECT  10.5 18.275 10.812 19.813 ;
     RECT  24 14.627 25.608 19.813 ;
     RECT  26.7 18.995 27.012 19.813 ;
     RECT  1.056 17.891 3.24 19.861 ;
     RECT  4.752 17.989 5.544 19.861 ;
     RECT  14.688 19.621 19.512 19.909 ;
     RECT  37.152 18.757 43.212 19.909 ;
     RECT  32.1 18.995 33.096 19.957 ;
     RECT  21.3 16.595 21.612 20.341 ;
     RECT  28.08 18.995 29.712 20.437 ;
     RECT  30.768 18.995 31.032 20.437 ;
     RECT  28.08 20.437 31.032 20.579 ;
     RECT  1.056 19.861 5.544 20.725 ;
     RECT  28.08 20.579 28.296 20.867 ;
     RECT  32.1 19.957 33.576 20.869 ;
     RECT  34.8 18.851 35.112 20.869 ;
     RECT  37.056 19.909 43.212 20.869 ;
     RECT  1.056 20.725 5.64 20.917 ;
     RECT  6.672 19.333 8.112 20.917 ;
     RECT  12.624 18.851 13.512 21.013 ;
     RECT  37.056 20.869 43.32 21.059 ;
     RECT  14.688 19.909 19.56 21.107 ;
     RECT  12.624 21.013 13.608 21.155 ;
     RECT  20.88 20.341 21.612 21.155 ;
     RECT  32.1 20.869 35.112 21.493 ;
     RECT  32.1 21.493 35.352 21.539 ;
     RECT  1.056 20.917 8.112 21.541 ;
     RECT  10.368 19.813 10.812 21.637 ;
     RECT  9.264 20.197 9.288 21.781 ;
     RECT  10.272 21.637 10.812 21.781 ;
     RECT  14.88 21.107 19.56 22.259 ;
     RECT  29.4 20.579 31.032 22.259 ;
     RECT  1.056 21.541 8.232 22.549 ;
     RECT  9.264 21.781 10.812 22.549 ;
     RECT  28.128 20.867 28.296 22.741 ;
     RECT  44.448 19.909 44.472 22.787 ;
     RECT  28.128 22.741 28.392 22.835 ;
     RECT  22.992 15.013 23.016 22.981 ;
     RECT  1.056 22.549 10.812 23.125 ;
     RECT  12.624 21.155 13.512 23.125 ;
     RECT  1.056 23.125 13.512 23.315 ;
     RECT  21.3 21.155 21.612 23.317 ;
     RECT  22.704 22.981 23.016 23.317 ;
     RECT  29.4 22.259 29.832 23.411 ;
     RECT  1.056 23.315 9.288 23.555 ;
     RECT  10.272 23.315 13.512 23.603 ;
     RECT  32.1 21.539 33.576 23.699 ;
     RECT  10.5 23.603 13.512 23.893 ;
     RECT  14.88 22.259 18.912 23.893 ;
     RECT  34.8 21.539 35.352 23.893 ;
     RECT  37.056 21.059 43.212 23.893 ;
     RECT  37.056 23.893 43.32 23.941 ;
     RECT  37.008 23.941 43.32 23.987 ;
     RECT  31.008 22.259 31.032 24.373 ;
     RECT  32.1 23.699 32.412 24.373 ;
     RECT  34.8 23.893 35.928 24.563 ;
     RECT  33.552 23.699 33.576 24.709 ;
     RECT  6.432 23.555 9.288 24.805 ;
     RECT  10.5 23.893 18.912 24.805 ;
     RECT  21.3 23.317 23.016 24.949 ;
     RECT  31.008 24.373 32.412 25.091 ;
     RECT  28.176 22.835 28.392 25.093 ;
     RECT  29.4 23.411 29.712 25.093 ;
     RECT  20.832 24.949 23.016 25.139 ;
     RECT  44.448 24.229 44.472 25.475 ;
     RECT  37.008 23.987 37.812 25.477 ;
     RECT  6.432 24.805 18.912 25.525 ;
     RECT  6.432 25.525 19.128 25.669 ;
     RECT  6.432 25.669 19.272 25.715 ;
     RECT  20.832 25.139 21.72 25.715 ;
     RECT  34.8 24.563 35.112 26.101 ;
     RECT  36.336 25.477 37.812 26.101 ;
     RECT  24 19.813 27.012 26.725 ;
     RECT  31.344 25.091 32.412 26.773 ;
     RECT  33.408 24.709 33.576 26.773 ;
     RECT  28.176 25.093 29.712 27.301 ;
     RECT  22.704 25.139 23.016 27.445 ;
     RECT  24 26.725 27.144 27.445 ;
     RECT  44.544 27.205 44.568 27.733 ;
     RECT  34.8 26.101 37.812 27.877 ;
     RECT  39.216 23.987 43.32 27.877 ;
     RECT  22.704 27.445 27.144 28.117 ;
     RECT  28.176 27.301 30.264 28.117 ;
     RECT  6.432 25.715 13.656 28.163 ;
     RECT  20.832 25.715 21.612 28.165 ;
     RECT  22.704 28.117 30.264 28.165 ;
     RECT  14.88 25.715 19.272 28.405 ;
     RECT  14.88 28.405 19.656 28.547 ;
     RECT  14.88 28.547 17.16 28.643 ;
     RECT  1.056 23.555 5.412 28.933 ;
     RECT  6.432 28.163 13.512 28.933 ;
     RECT  39.024 27.877 43.32 28.979 ;
     RECT  14.88 28.643 17.112 29.171 ;
     RECT  31.344 26.773 33.576 29.651 ;
     RECT  44.448 27.733 44.568 29.651 ;
     RECT  14.88 29.171 16.968 29.797 ;
     RECT  39.216 28.979 43.32 30.757 ;
     RECT  34.8 27.877 37.944 30.899 ;
     RECT  31.584 29.651 33.576 30.949 ;
     RECT  14.832 29.797 16.968 31.091 ;
     RECT  18.6 28.547 19.656 31.189 ;
     RECT  20.832 28.165 30.264 31.189 ;
     RECT  18.6 31.189 30.264 31.379 ;
     RECT  20.496 31.379 30.264 31.859 ;
     RECT  31.584 30.949 33.672 31.955 ;
     RECT  34.8 30.899 37.812 31.955 ;
     RECT  20.496 31.859 29.712 32.195 ;
     RECT  18.6 31.379 19.128 32.437 ;
     RECT  44.448 29.651 44.472 32.725 ;
     RECT  45.6 2.151 45.912 32.725 ;
     RECT  44.448 32.725 45.912 32.771 ;
     RECT  29.4 32.195 29.712 33.013 ;
     RECT  18.24 32.437 19.128 33.059 ;
     RECT  20.496 32.195 28.344 33.061 ;
     RECT  31.584 31.955 33.576 33.203 ;
     RECT  14.88 31.091 16.968 33.349 ;
     RECT  34.8 31.955 35.112 33.445 ;
     RECT  36.24 31.955 37.812 33.445 ;
     RECT  44.832 32.771 45.912 33.541 ;
     RECT  44.832 33.541 46.152 33.587 ;
     RECT  20.4 33.061 28.344 33.635 ;
     RECT  18.6 33.059 19.128 34.165 ;
     RECT  20.4 33.635 27.012 34.165 ;
     RECT  31.584 33.203 32.412 34.211 ;
     RECT  34.8 33.445 37.812 34.355 ;
     RECT  28.176 33.635 28.344 34.693 ;
     RECT  29.4 33.013 30.264 34.693 ;
     RECT  36.24 34.355 37.812 34.741 ;
     RECT  28.176 34.693 30.264 34.789 ;
     RECT  28.08 34.789 30.264 34.931 ;
     RECT  33.552 33.203 33.576 35.077 ;
     RECT  34.8 34.355 35.112 35.077 ;
     RECT  18.432 34.165 27.012 35.123 ;
     RECT  39.216 30.757 43.368 35.317 ;
     RECT  36.24 34.741 38.232 35.363 ;
     RECT  28.08 34.931 28.248 35.797 ;
     RECT  31.872 34.211 32.412 35.843 ;
     RECT  18.6 35.123 27.012 36.325 ;
     RECT  29.4 34.931 30.264 36.515 ;
     RECT  45.6 33.587 46.152 36.563 ;
     RECT  39.216 35.317 43.416 36.659 ;
     RECT  36.24 35.363 37.812 37.139 ;
     RECT  28.032 35.797 28.248 37.669 ;
     RECT  29.4 36.515 29.712 37.669 ;
     RECT  28.032 37.669 29.712 37.907 ;
     RECT  29.4 37.907 29.712 37.957 ;
     RECT  28.032 37.907 28.248 38.099 ;
     RECT  33.552 35.077 35.112 38.149 ;
     RECT  1.056 28.933 13.512 38.197 ;
     RECT  33.552 38.149 35.88 38.485 ;
     RECT  37.152 37.139 37.812 38.581 ;
     RECT  39.216 36.659 43.368 38.581 ;
     RECT  18.48 36.325 27.012 38.677 ;
     RECT  28.032 38.099 28.2 38.677 ;
     RECT  29.4 37.957 29.832 38.771 ;
     RECT  33.504 38.485 35.88 38.819 ;
     RECT  18.384 38.677 28.2 39.059 ;
     RECT  1.056 38.197 13.608 39.061 ;
     RECT  14.88 33.349 17.256 39.061 ;
     RECT  31.968 35.843 32.412 39.493 ;
     RECT  45.6 36.563 45.912 39.589 ;
     RECT  18.384 39.059 28.104 39.635 ;
     RECT  29.4 38.771 29.712 39.781 ;
     RECT  37.152 38.581 43.368 39.973 ;
     RECT  31.92 39.493 32.412 40.163 ;
     RECT  28.032 39.635 28.104 40.499 ;
     RECT  1.056 39.061 17.256 40.549 ;
     RECT  18.384 39.635 27.012 40.549 ;
     RECT  31.968 40.163 32.412 40.549 ;
     RECT  31.968 40.549 32.52 40.595 ;
     RECT  29.4 39.781 30.216 40.693 ;
     RECT  29.4 40.693 30.888 40.739 ;
     RECT  37.056 39.973 43.368 40.789 ;
     RECT  45.504 39.589 45.912 40.789 ;
     RECT  1.056 40.549 27.012 41.171 ;
     RECT  32.1 40.595 32.52 41.651 ;
     RECT  45.36 40.789 45.912 41.699 ;
     RECT  1.056 41.171 13.8 41.747 ;
     RECT  45.6 41.699 45.912 42.085 ;
     RECT  14.88 41.171 27.012 42.227 ;
     RECT  28.08 40.499 28.104 42.709 ;
     RECT  29.4 40.739 29.712 42.709 ;
     RECT  36.48 40.789 43.368 42.709 ;
     RECT  44.4 42.085 44.424 42.709 ;
     RECT  45.6 42.085 46.392 42.803 ;
     RECT  28.08 42.709 29.712 42.851 ;
     RECT  36.48 42.709 44.424 42.995 ;
     RECT  18.384 42.227 27.012 43.285 ;
     RECT  28.08 42.851 28.104 43.285 ;
     RECT  29.4 42.851 29.712 43.285 ;
     RECT  30.864 40.739 30.888 43.571 ;
     RECT  1.056 41.747 13.608 43.907 ;
     RECT  37.152 42.995 44.424 43.907 ;
     RECT  18.384 43.285 28.104 44.099 ;
     RECT  45.6 42.803 46.344 44.915 ;
     RECT  32.1 41.651 32.412 44.917 ;
     RECT  33.504 38.819 35.112 44.917 ;
     RECT  28.08 44.099 28.104 44.965 ;
     RECT  29.4 43.285 29.832 44.965 ;
     RECT  28.08 44.965 29.832 45.059 ;
     RECT  18.384 44.099 27.012 45.541 ;
     RECT  28.08 45.059 29.712 45.541 ;
     RECT  32.1 44.917 35.112 45.541 ;
     RECT  37.152 43.907 43.848 45.541 ;
     RECT  18.384 45.541 29.712 46.211 ;
     RECT  27.984 46.211 29.712 46.787 ;
     RECT  45.6 44.915 46.008 46.789 ;
     RECT  18.384 46.211 27.012 46.835 ;
     RECT  26.016 46.835 27.012 47.845 ;
     RECT  28.08 46.787 29.712 47.845 ;
     RECT  18.384 46.835 24.792 48.757 ;
     RECT  26.016 47.845 29.712 48.757 ;
     RECT  31.872 45.541 35.112 48.805 ;
     RECT  45.6 46.789 46.776 48.949 ;
     RECT  18.384 48.757 29.712 49.043 ;
     RECT  1.056 43.907 13.512 49.237 ;
     RECT  0.528 49.237 13.512 49.525 ;
     RECT  31.872 48.805 35.208 49.571 ;
     RECT  33.504 49.571 35.208 49.765 ;
     RECT  36.432 45.541 43.848 49.765 ;
     RECT  45.6 48.949 46.92 49.909 ;
     RECT  44.88 49.909 46.92 50.389 ;
     RECT  31.872 49.571 32.412 50.533 ;
     RECT  33.504 49.765 43.848 50.533 ;
     RECT  0.48 49.525 13.512 51.205 ;
     RECT  44.88 50.389 46.968 51.299 ;
     RECT  26.016 49.043 29.712 51.637 ;
     RECT  44.976 51.299 46.968 51.923 ;
     RECT  26.016 51.637 29.832 52.261 ;
     RECT  30.816 50.005 30.84 52.261 ;
     RECT  26.016 52.261 30.84 52.357 ;
     RECT  31.872 50.533 43.848 52.357 ;
     RECT  0.48 51.205 13.704 52.693 ;
     RECT  14.88 42.227 17.256 52.693 ;
     RECT  0.48 52.693 17.256 52.835 ;
     RECT  45.504 51.923 46.968 53.075 ;
     RECT  18.384 49.043 24.792 53.413 ;
     RECT  45.504 53.075 46.776 53.797 ;
     RECT  26.016 52.357 43.848 54.085 ;
     RECT  18.336 53.413 24.792 54.227 ;
     RECT  0.48 52.835 13.512 54.469 ;
     RECT  14.88 52.835 17.256 54.469 ;
     RECT  45.408 53.797 46.776 54.707 ;
     RECT  18.384 54.227 24.792 55.189 ;
     RECT  26.016 54.085 44.04 55.189 ;
     RECT  18.384 55.189 44.04 55.331 ;
     RECT  18.384 55.331 43.848 55.813 ;
     RECT  45.408 54.707 46.104 55.813 ;
     RECT  18.24 55.813 43.848 55.907 ;
     RECT  45.408 55.813 46.824 56.821 ;
     RECT  45.312 56.821 46.824 57.011 ;
     RECT  45.456 57.011 46.824 57.059 ;
     RECT  18.24 55.907 27.96 57.443 ;
     RECT  47.088 57.541 47.112 59.459 ;
     RECT  45.456 57.059 46.104 59.797 ;
     RECT  29.088 55.907 43.848 60.277 ;
     RECT  28.992 60.277 43.848 60.805 ;
     RECT  44.88 59.797 46.104 60.805 ;
     RECT  28.992 60.805 46.104 60.851 ;
     RECT  45.456 60.851 46.104 61.619 ;
     RECT  0.48 54.469 17.256 62.197 ;
     RECT  28.992 60.851 44.472 62.435 ;
     RECT  0.288 62.197 17.256 62.677 ;
     RECT  18.384 57.443 27.96 62.677 ;
     RECT  0.192 62.677 28.008 62.819 ;
     RECT  0.48 62.819 28.008 63.685 ;
     RECT  28.992 62.435 43.848 63.685 ;
     RECT  0.48 63.685 43.848 63.829 ;
     RECT  0.48 63.829 43.944 64.309 ;
     RECT  0.48 64.309 44.136 64.451 ;
     RECT  45.456 61.619 45.912 65.509 ;
     RECT  0.48 64.451 30.36 65.555 ;
     RECT  14.88 65.555 30.36 65.941 ;
     RECT  31.392 64.451 44.136 65.941 ;
     RECT  14.88 65.941 44.136 66.083 ;
     RECT  31.488 66.083 44.136 66.131 ;
     RECT  14.88 66.083 30.36 66.179 ;
     RECT  45.456 65.509 46.008 66.709 ;
     RECT  0.48 65.555 13.512 67.189 ;
     RECT  14.88 66.179 28.296 67.189 ;
     RECT  0.48 67.189 28.296 67.237 ;
     RECT  29.28 66.179 30.36 67.237 ;
     RECT  0.48 67.237 30.36 67.669 ;
     RECT  31.488 66.131 43.848 67.669 ;
     RECT  44.832 66.709 46.008 68.101 ;
     RECT  0.48 67.669 43.848 68.197 ;
     RECT  44.832 68.101 46.104 68.197 ;
     RECT  0.48 68.197 46.104 69.011 ;
     RECT  0.48 69.011 46.008 69.443 ;
     RECT  45.6 69.443 46.008 69.875 ;
     RECT  0.48 69.443 44.472 70.261 ;
     RECT  0.288 70.261 44.472 71.845 ;
     RECT  45.6 69.875 45.912 71.845 ;
     RECT  0.288 71.845 45.912 72.467 ;
     RECT  0.288 72.467 43.992 74.147 ;
     RECT  0.336 74.147 43.992 74.339 ;
     RECT  0.48 74.339 43.992 75.781 ;
     RECT  45.264 72.467 45.912 75.781 ;
     RECT  0.48 75.781 45.912 76.021 ;
     RECT  0.48 76.021 46.056 76.117 ;
     RECT  0.192 76.117 46.056 76.547 ;
     RECT  0.48 76.547 46.056 76.931 ;
     RECT  0.48 76.931 44.52 78.419 ;
     RECT  45.6 76.931 46.056 78.517 ;
     RECT  0.48 78.419 44.136 79.669 ;
     RECT  45.36 78.517 46.056 79.669 ;
     RECT  0.48 79.669 46.056 80.963 ;
     RECT  0.48 80.963 44.472 83.651 ;
     RECT  0.48 83.651 44.136 85.429 ;
     RECT  0.288 85.429 44.136 85.667 ;
     RECT  0.48 85.667 44.136 87.397 ;
     RECT  0.288 87.397 44.136 87.587 ;
     RECT  0.288 87.587 44.088 87.683 ;
     RECT  0.288 87.683 43.848 87.973 ;
     RECT  0.192 87.973 43.848 88.259 ;
     RECT  0.48 88.259 43.848 90.659 ;
     RECT  0.48 90.659 39 92.677 ;
     RECT  0.48 92.677 39.048 95.557 ;
     RECT  40.032 90.659 43.848 95.557 ;
     RECT  0.48 95.557 43.848 96.277 ;
     RECT  0.288 96.277 43.848 97.043 ;
     RECT  0.528 97.043 43.848 98.435 ;
     RECT  0.528 98.435 0.552 102.757 ;
     RECT  0.192 102.757 0.552 104.003 ;
     RECT  1.68 98.435 43.848 104.339 ;
     RECT  0.288 104.003 0.552 104.867 ;
     RECT  0.528 104.867 0.552 106.453 ;
     RECT  0.288 106.453 0.552 106.595 ;
     RECT  0.528 106.595 0.552 110.099 ;
     RECT  1.68 104.339 43.212 113.461 ;
     RECT  1.68 113.461 43.32 113.845 ;
     RECT  1.68 113.845 43.56 118.019 ;
     RECT  41.616 118.019 43.56 118.595 ;
     RECT  41.664 118.595 43.56 119.749 ;
     RECT  1.68 118.019 40.632 120.085 ;
     RECT  41.664 119.749 43.896 120.085 ;
     RECT  1.68 120.085 43.896 120.515 ;
     RECT  41.568 120.515 43.896 121.475 ;
     RECT  1.68 120.515 40.512 122.483 ;
     RECT  41.568 121.475 43.8 122.485 ;
     RECT  45.6 80.963 46.056 122.485 ;
     RECT  1.68 122.483 35.496 122.579 ;
     RECT  36.48 122.483 40.512 122.773 ;
     RECT  41.568 122.485 46.056 122.773 ;
     RECT  36.48 122.773 46.056 122.915 ;
     RECT  1.68 122.579 12.168 123.733 ;
     RECT  13.2 122.579 35.496 123.733 ;
     RECT  1.68 123.733 35.496 123.875 ;
     RECT  44.64 122.915 46.056 124.547 ;
     RECT  13.2 123.875 35.496 124.979 ;
     RECT  36.48 122.915 43.32 125.363 ;
     RECT  17.232 124.979 35.496 125.411 ;
     RECT  1.68 123.875 12.168 125.461 ;
     RECT  13.2 124.979 16.212 125.461 ;
     RECT  1.68 125.461 16.212 126.133 ;
     RECT  17.232 125.411 22.152 126.133 ;
     RECT  36.48 125.363 40.512 126.421 ;
     RECT  41.568 125.363 43.32 126.421 ;
     RECT  23.232 125.411 35.496 126.517 ;
     RECT  36.48 126.421 43.32 126.517 ;
     RECT  1.68 126.133 22.152 126.563 ;
     RECT  45.504 124.547 46.056 126.613 ;
     RECT  23.232 126.517 43.32 126.755 ;
     RECT  45.504 126.613 46.104 127.091 ;
     RECT  1.68 126.563 12.168 127.235 ;
     RECT  13.2 126.563 21.612 127.619 ;
     RECT  23.232 126.755 43.212 127.667 ;
     RECT  1.68 127.235 12.024 128.291 ;
     RECT  15.12 127.619 21.612 128.291 ;
     RECT  21.072 128.291 21.612 128.341 ;
     RECT  23.232 127.667 40.512 128.341 ;
     RECT  13.2 127.619 13.944 128.387 ;
     RECT  45.504 127.091 46.056 128.821 ;
     RECT  1.68 128.291 11.784 128.963 ;
     RECT  13.2 128.387 13.512 129.349 ;
     RECT  21.072 128.341 40.512 129.443 ;
     RECT  23.232 129.443 40.512 129.539 ;
     RECT  45.504 128.821 46.152 129.925 ;
     RECT  13.104 129.349 13.512 130.453 ;
     RECT  13.104 130.453 13.608 130.499 ;
     RECT  41.664 127.667 43.212 130.501 ;
     RECT  21.072 129.443 22.248 130.547 ;
     RECT  26.208 129.539 40.512 130.595 ;
     RECT  23.232 129.539 25.176 130.645 ;
     RECT  26.208 130.595 39 130.645 ;
     RECT  15.216 128.291 19.752 130.981 ;
     RECT  40.2 130.595 40.512 131.029 ;
     RECT  41.664 130.501 43.512 131.557 ;
     RECT  40.2 131.029 40.632 131.605 ;
     RECT  13.2 130.499 13.608 131.795 ;
     RECT  45.504 129.925 46.68 132.131 ;
     RECT  23.232 130.645 39 132.805 ;
     RECT  14.64 130.981 19.752 132.947 ;
     RECT  23.136 132.805 39 132.995 ;
     RECT  41.664 131.557 44.232 133.043 ;
     RECT  40.032 131.605 40.632 133.045 ;
     RECT  41.664 133.043 43.212 133.045 ;
     RECT  45.504 132.131 46.2 133.379 ;
     RECT  26.304 132.995 39 133.427 ;
     RECT  45.504 133.379 46.152 133.717 ;
     RECT  21.072 130.547 21.612 133.813 ;
     RECT  23.136 132.995 25.176 134.771 ;
     RECT  45.456 133.717 46.152 135.061 ;
     RECT  1.68 128.963 11.544 135.155 ;
     RECT  26.304 133.427 38.952 135.155 ;
     RECT  21.072 133.813 21.72 135.203 ;
     RECT  15.9 132.947 19.752 135.589 ;
     RECT  40.032 133.045 43.212 135.589 ;
     RECT  44.208 133.043 44.232 135.589 ;
     RECT  40.032 135.589 44.232 136.021 ;
     RECT  45.456 135.061 46.68 136.021 ;
     RECT  1.68 135.155 11.448 136.165 ;
     RECT  13.2 131.795 13.512 136.165 ;
     RECT  23.232 134.771 25.176 136.741 ;
     RECT  40.032 136.021 46.68 136.787 ;
     RECT  21.072 135.203 21.612 137.029 ;
     RECT  40.032 136.787 46.248 137.219 ;
     RECT  20.832 137.029 21.612 137.651 ;
     RECT  23.232 136.741 25.32 137.651 ;
     RECT  40.032 137.219 44.088 137.987 ;
     RECT  15.552 135.589 19.752 138.325 ;
     RECT  26.304 135.155 35.256 138.515 ;
     RECT  21.072 137.651 21.612 138.659 ;
     RECT  1.68 136.165 13.512 138.803 ;
     RECT  36.48 135.155 38.952 139.187 ;
     RECT  15.36 138.325 19.752 139.237 ;
     RECT  36.48 139.187 38.712 139.523 ;
     RECT  12.864 138.803 13.512 139.715 ;
     RECT  15.36 139.237 20.184 139.715 ;
     RECT  26.304 138.515 35.208 139.763 ;
     RECT  40.08 137.987 44.088 139.811 ;
     RECT  21.3 138.659 21.612 140.005 ;
     RECT  23.232 137.651 25.176 140.005 ;
     RECT  37.5 139.523 38.712 140.197 ;
     RECT  1.68 138.803 11.448 140.243 ;
     RECT  15.36 139.715 19.128 140.437 ;
     RECT  14.784 140.437 19.128 140.483 ;
     RECT  45.456 137.219 46.248 140.533 ;
     RECT  26.304 139.763 35.112 140.725 ;
     RECT  36.48 139.523 36.504 140.725 ;
     RECT  37.5 140.197 38.76 140.725 ;
     RECT  40.2 139.811 44.088 140.773 ;
     RECT  45.456 140.533 46.776 140.773 ;
     RECT  40.2 140.773 46.776 140.915 ;
     RECT  4.896 140.243 11.448 141.059 ;
     RECT  21.3 140.005 25.176 141.299 ;
     RECT  5.1 141.059 11.448 141.301 ;
     RECT  26.208 140.725 35.112 141.539 ;
     RECT  26.304 141.539 35.112 141.877 ;
     RECT  1.68 140.243 3.768 141.971 ;
     RECT  14.784 140.483 14.808 142.453 ;
     RECT  15.9 140.483 19.128 142.453 ;
     RECT  40.2 140.915 44.088 142.453 ;
     RECT  45.456 140.915 46.776 142.453 ;
     RECT  14.784 142.453 19.128 142.499 ;
     RECT  5.1 141.301 11.544 142.789 ;
     RECT  26.304 141.877 35.208 143.029 ;
     RECT  36.48 140.725 38.76 143.029 ;
     RECT  40.2 142.453 46.776 143.075 ;
     RECT  20.16 139.715 20.184 143.123 ;
     RECT  26.304 143.029 38.76 143.411 ;
     RECT  21.3 141.299 21.612 143.557 ;
     RECT  23.232 141.299 25.176 143.557 ;
     RECT  40.2 143.075 46.248 143.699 ;
     RECT  37.5 143.411 38.76 143.989 ;
     RECT  15.456 142.499 19.128 144.133 ;
     RECT  14.784 144.133 19.128 144.179 ;
     RECT  26.304 143.411 36.504 144.517 ;
     RECT  37.5 143.989 39.048 144.517 ;
     RECT  5.1 142.789 11.688 144.563 ;
     RECT  26.304 144.517 39.048 144.709 ;
     RECT  45.6 143.699 46.248 144.709 ;
     RECT  1.68 141.971 3.672 144.851 ;
     RECT  5.1 144.563 11.544 145.283 ;
     RECT  14.784 144.179 14.808 145.331 ;
     RECT  21.3 143.557 25.176 145.429 ;
     RECT  13.2 139.715 13.512 146.293 ;
     RECT  1.68 144.851 3.432 146.435 ;
     RECT  45.6 144.709 46.776 146.435 ;
     RECT  12.576 146.293 13.512 146.437 ;
     RECT  5.1 145.283 10.812 147.107 ;
     RECT  20.688 145.429 25.176 147.107 ;
     RECT  12.576 146.437 14.472 147.635 ;
     RECT  26.208 144.709 39.048 147.733 ;
     RECT  40.2 143.699 44.088 147.733 ;
     RECT  26.208 147.733 44.088 148.259 ;
     RECT  5.1 147.107 6.312 148.547 ;
     RECT  15.9 144.179 19.128 148.741 ;
     RECT  12.576 147.635 13.512 148.787 ;
     RECT  26.256 148.259 44.088 148.835 ;
     RECT  26.496 148.835 44.088 149.171 ;
     RECT  15.9 148.741 19.272 149.363 ;
     RECT  7.44 147.107 10.812 149.411 ;
     RECT  36.384 149.171 44.088 149.603 ;
     RECT  15.9 149.363 19.128 149.653 ;
     RECT  15.648 149.653 19.128 149.699 ;
     RECT  36.384 149.603 38.04 149.747 ;
     RECT  13.104 148.787 13.512 149.845 ;
     RECT  1.68 146.435 3.336 149.893 ;
     RECT  23.232 147.107 25.176 149.939 ;
     RECT  39.264 149.603 44.088 150.179 ;
     RECT  20.688 147.107 21.612 150.277 ;
     RECT  20.688 150.277 22.248 150.323 ;
     RECT  5.1 148.547 6.264 150.421 ;
     RECT  7.632 149.411 10.812 150.421 ;
     RECT  1.68 149.893 4.008 150.467 ;
     RECT  39.264 150.179 43.944 150.467 ;
     RECT  1.68 150.467 3.336 150.707 ;
     RECT  12.192 149.845 13.512 150.755 ;
     RECT  15.648 149.699 16.344 150.755 ;
     RECT  39.264 150.467 43.212 150.755 ;
     RECT  13.2 150.755 13.512 151.189 ;
     RECT  5.1 150.421 6.312 151.235 ;
     RECT  5.1 151.235 6.264 151.285 ;
     RECT  20.928 150.323 22.248 151.381 ;
     RECT  13.2 151.189 13.608 151.571 ;
     RECT  26.496 149.171 35.112 151.573 ;
     RECT  12.192 150.755 12.216 151.667 ;
     RECT  17.376 149.699 19.128 152.149 ;
     RECT  20.784 151.381 22.248 152.149 ;
     RECT  4.416 151.285 6.264 152.195 ;
     RECT  17.376 152.149 22.248 152.243 ;
     RECT  45.6 146.435 46.008 152.245 ;
     RECT  7.392 150.421 10.812 152.387 ;
     RECT  39.264 150.755 41.688 152.629 ;
     RECT  42.9 150.755 43.212 152.629 ;
     RECT  45.6 152.245 46.056 152.723 ;
     RECT  20.928 152.243 22.248 152.915 ;
     RECT  36.48 149.747 38.04 153.299 ;
     RECT  39.264 152.629 43.212 153.299 ;
     RECT  42.144 153.299 43.212 153.589 ;
     RECT  13.2 151.571 13.512 153.733 ;
     RECT  23.856 149.939 25.176 153.781 ;
     RECT  17.376 152.243 19.944 153.923 ;
     RECT  45.6 152.723 46.008 154.069 ;
     RECT  7.632 152.387 10.812 154.405 ;
     RECT  13.2 153.733 13.992 154.405 ;
     RECT  26.496 151.573 35.352 154.451 ;
     RECT  42.144 153.589 43.944 154.499 ;
     RECT  36.48 153.299 37.944 154.787 ;
     RECT  1.68 150.707 3.192 154.981 ;
     RECT  7.632 154.405 11.4 155.075 ;
     RECT  7.632 155.075 10.812 155.171 ;
     RECT  17.376 153.923 19.128 155.171 ;
     RECT  20.928 152.915 21.612 155.507 ;
     RECT  12.624 154.405 13.992 155.555 ;
     RECT  26.496 154.451 30.072 155.557 ;
     RECT  31.344 154.451 35.352 155.557 ;
     RECT  45.6 154.069 46.152 155.603 ;
     RECT  1.68 154.981 3.432 155.651 ;
     RECT  45.6 155.603 46.056 155.651 ;
     RECT  26.496 155.557 35.352 155.843 ;
     RECT  42.144 154.499 43.212 155.845 ;
     RECT  42.144 155.845 43.368 155.891 ;
     RECT  17.472 155.171 19.128 155.989 ;
     RECT  26.496 155.843 35.112 156.131 ;
     RECT  17.472 155.989 20.04 156.227 ;
     RECT  39.264 153.299 41.064 156.227 ;
     RECT  23.04 153.781 25.176 156.371 ;
     RECT  26.496 156.131 30.072 156.371 ;
     RECT  12.624 155.555 13.512 156.419 ;
     RECT  5.1 152.195 6.264 156.421 ;
     RECT  7.8 155.171 10.812 156.565 ;
     RECT  37.5 154.787 37.944 156.709 ;
     RECT  42.9 155.891 43.368 156.997 ;
     RECT  37.5 156.709 38.184 157.043 ;
     RECT  7.8 156.565 11.352 157.237 ;
     RECT  15.648 150.755 16.212 157.285 ;
     RECT  42.9 156.997 43.8 157.477 ;
     RECT  4.08 156.709 4.104 157.667 ;
     RECT  15.12 157.285 16.344 157.763 ;
     RECT  23.856 156.371 25.176 157.861 ;
     RECT  13.2 156.419 13.512 157.909 ;
     RECT  26.544 156.371 30.072 158.005 ;
     RECT  31.344 156.131 35.112 158.005 ;
     RECT  39.36 156.227 41.064 158.051 ;
     RECT  17.712 156.227 20.04 158.149 ;
     RECT  17.28 158.149 20.04 158.195 ;
     RECT  13.2 157.909 13.704 158.389 ;
     RECT  26.544 158.005 35.112 158.389 ;
     RECT  40.2 158.051 41.064 158.389 ;
     RECT  26.544 158.389 35.352 158.483 ;
     RECT  42.768 157.477 43.8 158.531 ;
     RECT  0.192 158.437 0.216 158.579 ;
     RECT  37.5 157.043 37.812 158.965 ;
     RECT  29.088 158.483 35.352 159.059 ;
     RECT  7.632 157.237 11.352 159.061 ;
     RECT  23.808 157.861 25.56 159.109 ;
     RECT  45.6 155.651 46.008 159.205 ;
     RECT  23.376 159.109 25.56 159.395 ;
     RECT  15.12 157.763 16.212 159.397 ;
     RECT  17.28 158.195 19.128 159.397 ;
     RECT  5.1 156.421 6.312 159.589 ;
     RECT  7.392 159.061 11.352 159.589 ;
     RECT  5.1 159.589 11.352 159.635 ;
     RECT  40.2 158.389 41.112 159.635 ;
     RECT  5.1 159.635 5.412 159.733 ;
     RECT  37.5 158.965 37.944 159.779 ;
     RECT  13.056 158.389 13.704 159.973 ;
     RECT  6.816 159.635 11.352 160.163 ;
     RECT  14.832 159.397 19.128 160.211 ;
     RECT  29.088 159.059 35.256 160.549 ;
     RECT  36.48 154.787 36.504 160.549 ;
     RECT  21.12 155.507 21.612 160.595 ;
     RECT  13.056 159.973 13.752 160.643 ;
     RECT  13.056 160.643 13.512 160.645 ;
     RECT  17.28 160.211 19.128 160.739 ;
     RECT  40.2 159.635 40.632 160.835 ;
     RECT  4.704 159.733 5.412 160.979 ;
     RECT  45.6 159.205 46.104 161.123 ;
     RECT  37.5 159.779 37.812 161.125 ;
     RECT  14.832 160.211 16.212 161.411 ;
     RECT  23.376 159.395 25.176 161.507 ;
     RECT  18.6 160.739 19.128 161.797 ;
     RECT  17.28 160.739 17.304 162.083 ;
     RECT  40.2 160.835 40.512 162.229 ;
     RECT  37.5 161.125 38.184 162.371 ;
     RECT  39.264 162.229 40.512 162.419 ;
     RECT  23.616 161.507 25.176 162.421 ;
     RECT  26.544 158.483 28.104 162.421 ;
     RECT  5.1 160.979 5.412 162.853 ;
     RECT  6.816 160.163 10.812 162.853 ;
     RECT  1.68 155.651 2.712 162.997 ;
     RECT  42.9 158.531 43.8 162.997 ;
     RECT  12.528 160.645 13.512 163.043 ;
     RECT  18.6 161.797 19.992 163.093 ;
     RECT  21.3 160.595 21.612 163.093 ;
     RECT  29.088 160.549 36.504 163.139 ;
     RECT  18.6 163.093 21.612 163.187 ;
     RECT  15.648 161.411 16.212 163.285 ;
     RECT  23.616 162.421 25.224 163.285 ;
     RECT  20.832 163.187 21.612 163.429 ;
     RECT  18.6 163.187 19.464 163.619 ;
     RECT  23.376 163.285 25.224 163.619 ;
     RECT  1.68 162.997 2.952 163.667 ;
     RECT  26.496 162.421 28.104 163.715 ;
     RECT  29.28 163.139 36.504 163.811 ;
     RECT  40.08 162.419 40.512 163.811 ;
     RECT  42.144 162.997 44.472 163.811 ;
     RECT  23.376 163.619 25.176 163.955 ;
     RECT  34.128 163.811 36.504 163.955 ;
     RECT  29.28 163.811 32.664 164.101 ;
     RECT  13.2 163.043 13.512 164.149 ;
     RECT  5.1 162.853 10.812 164.245 ;
     RECT  42.9 163.811 44.472 164.291 ;
     RECT  42.9 164.291 43.8 164.387 ;
     RECT  37.5 162.371 37.944 164.485 ;
     RECT  20.832 163.429 21.768 164.675 ;
     RECT  28.8 164.101 32.664 164.771 ;
     RECT  23.376 163.955 24.408 164.819 ;
     RECT  1.68 163.667 2.712 164.917 ;
     RECT  15.648 163.285 16.584 165.011 ;
     RECT  1.68 164.917 2.808 165.059 ;
     RECT  26.496 163.715 27.816 165.347 ;
     RECT  36.48 163.955 36.504 165.395 ;
     RECT  34.128 163.955 35.304 165.587 ;
     RECT  45.6 161.123 46.056 165.635 ;
     RECT  4.512 164.245 10.812 165.827 ;
     RECT  42.9 164.387 43.212 165.829 ;
     RECT  23.76 164.819 24.408 165.923 ;
     RECT  40.2 163.811 40.512 166.069 ;
     RECT  41.664 164.677 41.688 166.069 ;
     RECT  40.2 166.069 41.688 166.115 ;
     RECT  5.1 165.827 10.812 166.163 ;
     RECT  20.832 164.675 21.612 166.213 ;
     RECT  23.76 165.923 24.312 166.259 ;
     RECT  34.8 165.587 35.304 166.453 ;
     RECT  3.936 166.357 3.96 166.499 ;
     RECT  28.8 164.771 30.504 166.979 ;
     RECT  26.7 165.347 27.816 166.981 ;
     RECT  5.1 166.163 6.36 167.075 ;
     RECT  29.4 166.979 30.504 167.365 ;
     RECT  42.9 165.829 43.608 167.507 ;
     RECT  15.648 165.011 16.212 167.603 ;
     RECT  31.92 164.771 32.568 167.603 ;
     RECT  37.5 164.485 38.232 167.603 ;
     RECT  5.1 167.075 5.784 167.699 ;
     RECT  26.064 166.981 27.816 167.747 ;
     RECT  34.8 166.453 35.352 167.747 ;
     RECT  18.6 163.619 18.912 167.749 ;
     RECT  20.256 166.213 21.612 167.749 ;
     RECT  20.208 167.749 21.612 167.795 ;
     RECT  20.208 167.795 20.28 167.987 ;
     RECT  37.5 167.603 37.944 168.179 ;
     RECT  31.92 167.603 32.412 168.275 ;
     RECT  13.104 164.149 13.512 168.419 ;
     RECT  21.3 167.795 21.612 168.469 ;
     RECT  15.9 167.603 16.212 168.661 ;
     RECT  40.2 166.115 41.4 168.707 ;
     RECT  34.8 167.747 35.208 168.851 ;
     RECT  18.48 167.749 18.912 169.189 ;
     RECT  26.7 167.747 27.816 169.189 ;
     RECT  32.1 168.275 32.412 169.189 ;
     RECT  37.5 168.179 37.812 169.237 ;
     RECT  26.592 169.189 27.816 169.379 ;
     RECT  21.3 168.469 21.768 169.525 ;
     RECT  40.2 168.707 40.776 169.667 ;
     RECT  1.68 165.059 2.712 169.715 ;
     RECT  40.2 169.667 40.512 169.765 ;
     RECT  13.2 168.419 13.512 169.861 ;
     RECT  13.104 169.861 13.512 170.291 ;
     RECT  34.8 168.851 35.112 170.389 ;
     RECT  32.1 169.189 32.568 170.483 ;
     RECT  7.8 166.163 10.812 170.579 ;
     RECT  21.3 169.525 22.488 170.867 ;
     RECT  26.592 169.379 27.012 170.867 ;
     RECT  9.6 170.579 10.812 170.915 ;
     RECT  20.208 167.987 20.232 171.059 ;
     RECT  10.368 170.915 10.812 171.539 ;
     RECT  13.2 170.291 13.512 171.541 ;
     RECT  21.3 170.867 22.248 171.635 ;
     RECT  7.8 170.579 8.232 171.779 ;
     RECT  15.9 168.661 16.344 171.779 ;
     RECT  29.4 167.365 30.6 171.779 ;
     RECT  37.5 169.237 38.76 171.779 ;
     RECT  33.936 170.389 35.112 172.067 ;
     RECT  18.432 169.189 18.912 172.163 ;
     RECT  12.576 171.541 13.512 172.355 ;
     RECT  39.888 169.765 40.512 172.403 ;
     RECT  2.4 169.715 2.712 172.809 ;
     RECT  5.1 167.699 5.412 172.809 ;
     RECT  7.8 171.779 8.112 172.809 ;
     RECT  10.5 171.539 10.812 172.809 ;
     RECT  13.2 172.355 13.512 172.809 ;
     RECT  15.9 171.779 16.212 172.809 ;
     RECT  18.6 172.163 18.912 172.809 ;
     RECT  21.3 171.635 21.612 172.809 ;
     RECT  24 166.259 24.312 172.809 ;
     RECT  26.7 170.867 27.012 172.809 ;
     RECT  29.4 171.779 29.712 172.809 ;
     RECT  32.1 170.483 32.412 172.809 ;
     RECT  34.8 172.067 35.112 172.809 ;
     RECT  37.5 171.779 37.812 172.809 ;
     RECT  40.2 172.403 40.512 172.809 ;
     RECT  42.9 167.507 43.212 172.809 ;
     RECT  45.6 165.635 45.912 172.809 ;
     RECT  48.3 2.151 48.612 172.809 ;
     RECT  51 2.151 51.312 172.809 ;
     RECT  53.7 2.151 54.012 172.809 ;
     RECT  56.4 2.151 56.712 172.809 ;
     RECT  59.1 2.151 59.412 172.809 ;
     RECT  61.8 2.151 62.112 172.809 ;
     RECT  64.5 2.151 64.812 172.809 ;
     RECT  67.2 2.151 67.512 172.809 ;
     RECT  69.9 2.151 70.212 172.809 ;
     RECT  72.6 2.151 72.912 172.809 ;
     RECT  75.3 2.151 75.612 172.809 ;
     RECT  78 2.151 78.312 172.809 ;
     RECT  80.7 2.151 81.012 172.809 ;
     RECT  83.4 2.151 83.712 172.809 ;
     RECT  86.1 2.151 86.412 172.809 ;
     RECT  88.8 2.151 89.112 172.809 ;
     RECT  91.5 2.151 91.812 172.809 ;
     RECT  94.2 2.151 94.512 172.809 ;
     RECT  96.9 2.151 97.212 172.809 ;
     RECT  99.6 2.151 99.912 172.809 ;
     RECT  102.3 2.151 102.612 172.809 ;
     RECT  105 2.151 105.312 172.809 ;
     RECT  107.7 2.151 108.012 172.809 ;
     RECT  110.4 2.151 110.712 172.809 ;
     RECT  113.1 2.151 113.412 172.809 ;
     RECT  115.8 2.151 116.112 172.809 ;
     RECT  118.5 2.151 118.812 172.809 ;
     RECT  121.2 2.151 121.512 172.809 ;
     RECT  123.9 2.151 124.212 172.809 ;
     RECT  126.6 2.151 126.912 172.809 ;
     RECT  2.4 172.809 2.52 172.823 ;
     RECT  5.1 172.809 5.22 172.823 ;
     RECT  7.8 172.809 7.92 172.823 ;
     RECT  10.5 172.809 10.62 172.823 ;
     RECT  13.2 172.809 13.32 172.823 ;
     RECT  15.9 172.809 16.02 172.823 ;
     RECT  18.6 172.809 18.72 172.823 ;
     RECT  21.3 172.809 21.42 172.823 ;
     RECT  24 172.809 24.12 172.823 ;
     RECT  26.7 172.809 26.82 172.823 ;
     RECT  29.4 172.809 29.52 172.823 ;
     RECT  32.1 172.809 32.22 172.823 ;
     RECT  34.8 172.809 34.92 172.823 ;
     RECT  37.5 172.809 37.62 172.823 ;
     RECT  40.2 172.809 40.32 172.823 ;
     RECT  42.9 172.809 43.02 172.823 ;
     RECT  45.6 172.809 45.72 172.823 ;
     RECT  48.3 172.809 48.42 172.823 ;
     RECT  51 172.809 51.12 172.823 ;
     RECT  53.7 172.809 53.82 172.823 ;
     RECT  56.4 172.809 56.52 172.823 ;
     RECT  59.1 172.809 59.22 172.823 ;
     RECT  61.8 172.809 61.92 172.823 ;
     RECT  64.5 172.809 64.62 172.823 ;
     RECT  67.2 172.809 67.32 172.823 ;
     RECT  69.9 172.809 70.02 172.823 ;
     RECT  72.6 172.809 72.72 172.823 ;
     RECT  75.3 172.809 75.42 172.823 ;
     RECT  78 172.809 78.12 172.823 ;
     RECT  80.7 172.809 80.82 172.823 ;
     RECT  83.4 172.809 83.52 172.823 ;
     RECT  86.1 172.809 86.22 172.823 ;
     RECT  88.8 172.809 88.92 172.823 ;
     RECT  91.5 172.809 91.62 172.823 ;
     RECT  94.2 172.809 94.32 172.823 ;
     RECT  96.9 172.809 97.02 172.823 ;
     RECT  99.6 172.809 99.72 172.823 ;
     RECT  102.3 172.809 102.42 172.823 ;
     RECT  105 172.809 105.12 172.823 ;
     RECT  107.7 172.809 107.82 172.823 ;
     RECT  110.4 172.809 110.52 172.823 ;
     RECT  113.1 172.809 113.22 172.823 ;
     RECT  115.8 172.809 115.92 172.823 ;
     RECT  118.5 172.809 118.62 172.823 ;
     RECT  121.2 172.809 121.32 172.823 ;
     RECT  123.9 172.809 124.02 172.823 ;
     RECT  126.6 172.809 126.72 172.823 ;
     RECT  25.176 2.245 26.7 2.677 ;
     RECT  32.412 2.245 33.936 4.595 ;
     RECT  25.656 2.677 26.7 4.595 ;
     RECT  27.912 2.821 29.4 3.589 ;
     RECT  13.512 3.157 14.688 4.595 ;
     RECT  14.712 3.157 15.9 3.925 ;
     RECT  27.912 3.589 29.184 5.171 ;
     RECT  37.812 3.685 39.312 5.989 ;
     RECT  14.904 3.925 15.9 5.605 ;
     RECT  40.512 4.261 42 6.085 ;
     RECT  13.512 4.595 14.88 15.157 ;
     RECT  27.012 5.171 29.184 6.229 ;
     RECT  13.104 5.651 13.2 6.949 ;
     RECT  8.112 5.747 8.376 6.805 ;
     RECT  37.812 5.989 38.832 7.475 ;
     RECT  40.728 6.085 42 6.899 ;
     RECT  27.012 6.229 27.984 10.643 ;
     RECT  28.008 6.229 29.184 8.389 ;
     RECT  38.856 6.275 40.2 7.475 ;
     RECT  29.712 6.899 30.264 7.909 ;
     RECT  40.512 6.899 42 8.485 ;
     RECT  25.656 7.189 26.7 8.003 ;
     RECT  19.08 7.237 20.448 8.771 ;
     RECT  14.904 7.475 15.9 10.837 ;
     RECT  37.812 7.475 40.2 7.765 ;
     RECT  32.412 7.717 33.408 12.229 ;
     RECT  33.432 7.717 34.8 7.765 ;
     RECT  33.816 7.765 34.8 9.637 ;
     RECT  37.812 7.765 38.88 11.941 ;
     RECT  38.904 7.765 40.2 8.437 ;
     RECT  30.648 7.909 32.1 9.251 ;
     RECT  25.608 8.003 26.7 10.741 ;
     RECT  21.612 8.483 21.72 8.677 ;
     RECT  40.512 8.485 41.904 11.317 ;
     RECT  21.612 8.677 22.752 9.491 ;
     RECT  22.776 8.677 24 9.491 ;
     RECT  8.112 8.723 8.376 9.061 ;
     RECT  35.88 8.965 37.152 11.651 ;
     RECT  8.112 9.061 9.552 11.989 ;
     RECT  21.612 9.491 24 10.501 ;
     RECT  21.12 9.779 21.3 10.789 ;
     RECT  17.064 9.781 18.192 10.453 ;
     RECT  21.612 10.501 22.896 12.227 ;
     RECT  22.92 10.501 24 12.227 ;
     RECT  38.904 10.595 40.2 13.621 ;
     RECT  27.012 10.643 28.464 15.877 ;
     RECT  5.412 10.885 6.72 11.509 ;
     RECT  6.744 10.885 7.8 12.851 ;
     RECT  40.512 11.317 41.808 11.941 ;
     RECT  5.412 11.509 6.528 13.669 ;
     RECT  40.512 11.941 41.52 12.997 ;
     RECT  33.432 12.035 34.8 12.275 ;
     RECT  21.612 12.227 22.296 13.573 ;
     RECT  33.096 12.275 34.8 13.333 ;
     RECT  4.512 12.515 5.1 13.957 ;
     RECT  25.656 12.563 26.7 14.627 ;
     RECT  35.112 12.563 35.352 13.813 ;
     RECT  43.212 12.755 43.896 14.197 ;
     RECT  6.552 12.851 7.8 16.309 ;
     RECT  10.812 12.901 12.288 13.573 ;
     RECT  37.812 13.043 38.88 13.715 ;
     RECT  33.288 13.333 34.8 14.915 ;
     RECT  10.812 13.573 12.24 13.861 ;
     RECT  5.544 13.669 6.528 17.699 ;
     RECT  37.812 13.715 39.216 14.243 ;
     RECT  10.92 13.861 12.24 15.349 ;
     RECT  2.712 13.957 4.224 14.197 ;
     RECT  8.112 14.003 9.552 16.789 ;
     RECT  2.712 14.197 3.936 15.061 ;
     RECT  43.212 14.197 44.448 16.019 ;
     RECT  44.472 14.197 45.6 16.019 ;
     RECT  37.812 14.243 39.312 16.885 ;
     RECT  21.612 14.291 22.296 15.013 ;
     RECT  3.96 14.531 5.1 17.075 ;
     RECT  25.608 14.627 26.7 19.813 ;
     RECT  21.612 15.013 22.992 22.981 ;
     RECT  23.016 15.013 24 27.445 ;
     RECT  13.608 15.157 14.88 15.395 ;
     RECT  13.512 15.395 14.88 19.333 ;
     RECT  6.552 16.309 7.584 17.699 ;
     RECT  8.112 16.789 9.12 16.981 ;
     RECT  9.144 16.835 10.5 17.699 ;
     RECT  38.232 16.885 39.312 17.605 ;
     RECT  3.48 17.075 5.1 17.891 ;
     RECT  33.096 17.077 34.32 17.651 ;
     RECT  8.112 17.171 9.12 17.699 ;
     RECT  29.712 17.509 30.768 20.437 ;
     RECT  38.232 17.605 39.216 18.757 ;
     RECT  11.448 17.699 12.528 18.275 ;
     RECT  3.24 17.891 5.1 17.989 ;
     RECT  3.24 17.989 4.752 19.861 ;
     RECT  34.704 18.851 34.8 19.957 ;
     RECT  27.012 18.995 28.08 20.867 ;
     RECT  31.032 18.995 32.1 24.373 ;
     RECT  5.544 19.333 6.672 20.725 ;
     RECT  13.512 19.333 14.832 19.621 ;
     RECT  13.512 19.621 14.688 21.013 ;
     RECT  43.212 19.909 44.448 20.869 ;
     RECT  44.472 19.909 45.6 22.787 ;
     RECT  33.576 19.957 34.8 20.869 ;
     RECT  8.112 20.197 9.264 21.541 ;
     RECT  9.288 20.197 10.368 21.637 ;
     RECT  19.56 20.341 20.88 21.155 ;
     RECT  28.296 20.579 29.4 22.741 ;
     RECT  5.64 20.725 6.672 20.917 ;
     RECT  27.012 20.867 28.128 22.835 ;
     RECT  43.32 20.869 44.448 21.059 ;
     RECT  13.608 21.013 14.688 21.107 ;
     RECT  43.212 21.059 44.448 22.787 ;
     RECT  13.608 21.107 14.88 21.155 ;
     RECT  13.512 21.155 14.88 23.893 ;
     RECT  33.576 21.539 34.8 30.949 ;
     RECT  8.232 21.541 9.264 22.549 ;
     RECT  9.288 21.637 10.272 21.781 ;
     RECT  29.832 22.259 31.008 23.411 ;
     RECT  28.392 22.741 29.4 25.093 ;
     RECT  43.212 22.787 45.6 23.893 ;
     RECT  27.012 22.835 28.176 26.725 ;
     RECT  21.612 22.981 22.704 23.317 ;
     RECT  9.288 23.315 10.272 23.603 ;
     RECT  29.712 23.411 31.008 25.091 ;
     RECT  5.412 23.555 6.432 28.933 ;
     RECT  9.288 23.603 10.5 24.805 ;
     RECT  32.412 23.699 33.552 24.709 ;
     RECT  35.928 23.893 37.056 23.941 ;
     RECT  43.32 23.893 45.6 24.229 ;
     RECT  35.928 23.941 37.008 24.563 ;
     RECT  37.812 23.987 39.216 27.877 ;
     RECT  43.32 24.229 44.448 25.475 ;
     RECT  44.472 24.229 45.6 25.475 ;
     RECT  35.112 24.563 37.008 25.477 ;
     RECT  32.412 24.709 33.408 26.773 ;
     RECT  21.72 25.139 22.704 25.715 ;
     RECT  35.112 25.477 36.336 26.101 ;
     RECT  13.656 25.715 14.88 28.163 ;
     RECT  21.612 25.715 22.704 28.165 ;
     RECT  27.144 26.725 28.176 28.117 ;
     RECT  43.32 27.205 44.544 27.733 ;
     RECT  44.568 27.205 45.6 29.651 ;
     RECT  30.264 27.301 31.344 29.651 ;
     RECT  43.32 27.733 44.448 30.757 ;
     RECT  37.944 27.877 39.024 28.979 ;
     RECT  13.512 28.163 14.88 29.797 ;
     RECT  19.656 28.405 20.832 31.189 ;
     RECT  17.16 28.547 18.6 28.643 ;
     RECT  17.112 28.643 18.6 29.171 ;
     RECT  37.944 28.979 39.216 30.899 ;
     RECT  30.264 29.651 31.584 31.859 ;
     RECT  44.472 29.651 45.6 32.725 ;
     RECT  13.512 29.797 14.832 31.091 ;
     RECT  43.368 30.757 44.448 32.771 ;
     RECT  37.812 30.899 39.216 34.741 ;
     RECT  33.672 30.949 34.8 31.955 ;
     RECT  13.512 31.091 14.88 38.197 ;
     RECT  19.128 31.379 20.496 33.061 ;
     RECT  29.712 31.859 31.584 33.013 ;
     RECT  33.576 31.955 34.8 35.077 ;
     RECT  35.112 31.955 36.24 33.445 ;
     RECT  28.344 32.195 29.4 34.693 ;
     RECT  16.968 32.437 18.24 33.059 ;
     RECT  43.368 32.771 44.832 33.587 ;
     RECT  30.264 33.013 31.584 34.211 ;
     RECT  16.968 33.059 18.6 33.349 ;
     RECT  19.128 33.061 20.4 34.165 ;
     RECT  32.412 33.203 33.552 38.485 ;
     RECT  17.256 33.349 18.6 34.165 ;
     RECT  27.012 33.635 28.176 34.789 ;
     RECT  17.256 34.165 18.432 35.123 ;
     RECT  35.112 34.355 36.24 37.139 ;
     RECT  38.232 34.741 39.216 35.363 ;
     RECT  27.012 34.789 28.08 35.797 ;
     RECT  28.248 34.931 29.4 37.669 ;
     RECT  17.256 35.123 18.6 36.325 ;
     RECT  37.812 35.363 39.216 38.581 ;
     RECT  27.012 35.797 28.032 38.677 ;
     RECT  17.256 36.325 18.48 38.677 ;
     RECT  29.712 36.515 29.832 37.957 ;
     RECT  35.112 37.139 37.152 38.149 ;
     RECT  28.248 37.907 29.4 38.099 ;
     RECT  28.2 38.099 29.4 39.059 ;
     RECT  35.88 38.149 37.152 38.819 ;
     RECT  13.608 38.197 14.88 39.061 ;
     RECT  32.412 38.485 33.504 40.549 ;
     RECT  17.256 38.677 18.384 40.549 ;
     RECT  29.712 38.771 29.832 39.781 ;
     RECT  37.056 38.819 37.152 39.973 ;
     RECT  28.104 39.059 29.4 42.709 ;
     RECT  27.012 39.635 28.032 40.499 ;
     RECT  31.92 40.163 31.968 40.595 ;
     RECT  27.012 40.499 28.08 43.285 ;
     RECT  32.52 40.549 33.504 41.651 ;
     RECT  31.92 40.595 32.1 40.693 ;
     RECT  30.888 40.693 32.1 43.571 ;
     RECT  29.712 40.739 30.864 43.285 ;
     RECT  35.112 40.789 36.48 42.995 ;
     RECT  13.8 41.171 14.88 41.747 ;
     RECT  32.412 41.651 33.504 44.917 ;
     RECT  45.36 41.699 45.6 42.085 ;
     RECT  13.608 41.747 14.88 43.907 ;
     RECT  43.368 42.085 44.4 42.709 ;
     RECT  44.424 42.085 45.6 43.907 ;
     RECT  17.256 42.227 18.384 53.413 ;
     RECT  28.104 42.851 29.4 44.965 ;
     RECT  29.832 43.285 30.864 43.571 ;
     RECT  13.512 43.907 14.88 51.205 ;
     RECT  27.012 44.099 28.08 45.541 ;
     RECT  35.112 45.541 36.432 48.805 ;
     RECT  27.012 46.211 27.984 46.787 ;
     RECT  27.012 46.787 28.08 47.845 ;
     RECT  46.776 46.789 48.3 48.949 ;
     RECT  24.792 46.835 26.016 48.757 ;
     RECT  35.208 48.805 36.432 49.765 ;
     RECT  46.92 48.949 48.3 50.389 ;
     RECT  24.792 49.043 26.016 55.189 ;
     RECT  32.412 49.571 33.504 50.533 ;
     RECT  43.848 49.909 44.88 51.299 ;
     RECT  29.712 50.005 30.816 51.637 ;
     RECT  30.84 50.005 31.872 52.357 ;
     RECT  46.968 50.389 48.3 53.075 ;
     RECT  13.704 51.205 14.88 52.693 ;
     RECT  43.848 51.299 44.976 51.923 ;
     RECT  29.832 51.637 30.816 52.261 ;
     RECT  13.512 52.835 14.88 54.469 ;
     RECT  46.776 53.075 48.3 54.707 ;
     RECT  17.256 53.413 18.336 54.227 ;
     RECT  44.04 54.085 45.408 55.331 ;
     RECT  17.256 54.227 18.384 55.813 ;
     RECT  46.104 54.707 48.3 55.813 ;
     RECT  43.848 55.331 45.408 56.821 ;
     RECT  17.256 55.813 18.24 57.443 ;
     RECT  46.824 55.813 48.3 57.059 ;
     RECT  27.96 55.907 29.088 60.277 ;
     RECT  43.848 56.821 45.312 57.011 ;
     RECT  46.104 57.059 48.3 57.541 ;
     RECT  17.256 57.443 18.384 62.677 ;
     RECT  46.104 57.541 47.088 59.459 ;
     RECT  47.112 57.541 48.3 59.459 ;
     RECT  43.848 59.797 44.88 60.805 ;
     RECT  27.96 60.277 28.992 62.677 ;
     RECT  44.472 60.851 45.456 62.435 ;
     RECT  43.848 62.435 45.456 63.829 ;
     RECT  28.008 62.677 28.992 63.685 ;
     RECT  43.944 63.829 45.456 64.309 ;
     RECT  44.136 64.309 45.456 66.131 ;
     RECT  30.36 64.451 31.392 65.941 ;
     RECT  13.512 65.555 14.88 67.189 ;
     RECT  30.36 66.083 31.488 67.669 ;
     RECT  43.848 66.131 45.456 66.709 ;
     RECT  28.296 66.179 29.28 67.237 ;
     RECT  43.848 66.709 44.832 68.197 ;
     RECT  44.472 69.443 45.6 71.845 ;
     RECT  43.992 72.467 45.264 75.781 ;
     RECT  44.52 76.931 45.6 78.419 ;
     RECT  44.136 78.419 45.6 78.517 ;
     RECT  44.136 78.517 45.36 79.669 ;
     RECT  44.472 80.963 45.6 83.651 ;
     RECT  44.136 83.651 45.6 87.587 ;
     RECT  44.088 87.587 45.6 87.683 ;
     RECT  39 90.659 40.032 92.677 ;
     RECT  39.048 92.677 40.032 95.557 ;
     RECT  0.552 98.435 1.68 110.099 ;
     RECT  40.632 118.019 41.616 118.595 ;
     RECT  40.632 118.595 41.664 120.085 ;
     RECT  40.512 120.515 41.568 122.773 ;
     RECT  43.8 121.475 43.896 122.485 ;
     RECT  35.496 122.483 36.48 126.517 ;
     RECT  12.168 122.579 13.2 123.733 ;
     RECT  43.32 122.915 44.64 124.547 ;
     RECT  12.168 123.875 13.2 125.461 ;
     RECT  16.212 124.979 17.232 126.133 ;
     RECT  40.512 125.363 41.568 126.421 ;
     RECT  22.152 125.411 23.232 126.563 ;
     RECT  12.168 126.563 13.2 127.235 ;
     RECT  12.024 127.235 13.2 128.291 ;
     RECT  13.944 127.619 15.12 128.291 ;
     RECT  40.512 127.667 41.664 131.029 ;
     RECT  11.784 128.291 13.2 128.963 ;
     RECT  13.944 128.291 15.216 128.387 ;
     RECT  19.752 128.291 21.072 137.029 ;
     RECT  13.104 128.963 13.2 129.349 ;
     RECT  22.248 129.443 23.232 130.547 ;
     RECT  25.176 129.539 26.208 130.645 ;
     RECT  39 130.595 40.2 131.605 ;
     RECT  13.608 130.981 14.64 131.795 ;
     RECT  40.632 131.029 41.664 133.045 ;
     RECT  44.232 131.557 45.504 133.717 ;
     RECT  39 131.605 40.032 133.427 ;
     RECT  13.512 131.795 14.64 132.947 ;
     RECT  21.612 132.805 23.136 133.813 ;
     RECT  25.176 132.995 26.304 136.741 ;
     RECT  43.212 133.043 44.208 135.589 ;
     RECT  38.952 133.427 40.032 137.987 ;
     RECT  44.232 133.717 45.456 136.021 ;
     RECT  21.72 133.813 23.136 134.771 ;
     RECT  21.72 134.771 23.232 135.203 ;
     RECT  11.448 135.155 11.544 136.165 ;
     RECT  35.256 135.155 36.48 138.515 ;
     RECT  25.32 136.741 26.304 137.651 ;
     RECT  19.752 137.029 20.832 137.651 ;
     RECT  44.088 137.219 45.456 140.773 ;
     RECT  19.752 137.651 21.072 138.659 ;
     RECT  25.176 137.651 26.304 140.725 ;
     RECT  38.952 137.987 40.08 139.187 ;
     RECT  35.208 138.515 36.48 139.763 ;
     RECT  19.752 138.659 21.3 139.237 ;
     RECT  11.448 138.803 12.864 139.715 ;
     RECT  38.712 139.187 40.08 139.811 ;
     RECT  20.184 139.237 21.3 143.123 ;
     RECT  36.504 139.523 37.5 140.725 ;
     RECT  19.128 139.715 20.16 143.123 ;
     RECT  35.112 139.763 36.48 141.877 ;
     RECT  38.712 139.811 40.2 140.197 ;
     RECT  38.76 140.197 40.2 143.989 ;
     RECT  3.768 140.243 4.896 141.059 ;
     RECT  13.512 140.437 14.784 142.499 ;
     RECT  14.808 140.483 15.9 142.453 ;
     RECT  46.776 140.533 48.3 143.075 ;
     RECT  25.176 140.725 26.208 141.539 ;
     RECT  44.088 140.915 45.456 142.453 ;
     RECT  3.768 141.059 5.1 141.971 ;
     RECT  25.176 141.539 26.304 144.709 ;
     RECT  35.208 141.877 36.48 143.029 ;
     RECT  3.672 141.971 5.1 144.851 ;
     RECT  11.688 142.789 13.2 144.563 ;
     RECT  36.504 143.411 37.5 144.517 ;
     RECT  44.088 143.699 45.6 150.179 ;
     RECT  39.048 143.989 40.2 147.733 ;
     RECT  13.512 144.133 14.784 145.331 ;
     RECT  14.808 144.179 15.9 145.331 ;
     RECT  25.176 144.709 26.208 148.259 ;
     RECT  46.776 144.709 48.3 146.435 ;
     RECT  13.512 145.331 15.9 146.437 ;
     RECT  14.472 146.437 15.9 147.635 ;
     RECT  6.312 147.107 7.44 148.547 ;
     RECT  25.176 148.259 26.256 148.835 ;
     RECT  6.264 148.547 7.44 149.411 ;
     RECT  19.272 148.741 20.688 149.363 ;
     RECT  12.576 148.787 13.104 149.845 ;
     RECT  25.176 148.835 26.496 156.371 ;
     RECT  35.112 149.171 36.384 149.747 ;
     RECT  6.264 149.411 7.632 150.421 ;
     RECT  38.04 149.603 39.264 153.299 ;
     RECT  16.344 149.699 17.376 150.755 ;
     RECT  35.112 149.747 36.48 151.573 ;
     RECT  10.812 149.845 12.192 151.667 ;
     RECT  4.008 149.893 5.1 150.467 ;
     RECT  20.784 150.323 20.928 151.381 ;
     RECT  6.312 150.421 7.392 151.235 ;
     RECT  3.336 150.467 5.1 150.707 ;
     RECT  3.192 150.707 5.1 151.285 ;
     RECT  12.216 150.755 13.2 151.667 ;
     RECT  16.212 150.755 17.376 155.171 ;
     RECT  41.688 150.755 42.9 152.629 ;
     RECT  6.264 151.235 7.392 152.387 ;
     RECT  3.192 151.285 4.416 152.195 ;
     RECT  35.352 151.573 36.48 155.843 ;
     RECT  19.944 152.243 20.928 153.923 ;
     RECT  6.264 152.387 7.632 155.171 ;
     RECT  46.008 152.723 46.056 154.069 ;
     RECT  21.612 152.915 22.248 153.781 ;
     RECT  37.944 153.299 39.264 156.227 ;
     RECT  41.064 153.299 42.144 155.891 ;
     RECT  21.612 153.781 23.04 156.371 ;
     RECT  11.4 154.405 12.624 155.075 ;
     RECT  30.072 154.451 31.344 155.557 ;
     RECT  43.212 154.499 43.368 155.845 ;
     RECT  36.504 154.787 37.5 165.395 ;
     RECT  10.812 155.075 12.624 156.419 ;
     RECT  6.264 155.171 7.8 156.421 ;
     RECT  16.212 155.171 17.472 156.227 ;
     RECT  20.928 155.507 21.12 155.989 ;
     RECT  2.712 155.651 3.432 156.709 ;
     RECT  35.112 155.843 36.48 158.389 ;
     RECT  20.04 155.989 21.12 158.195 ;
     RECT  30.072 156.131 31.344 158.005 ;
     RECT  16.212 156.227 17.712 157.285 ;
     RECT  37.944 156.227 39.36 156.709 ;
     RECT  23.808 156.371 23.856 157.861 ;
     RECT  25.176 156.371 26.544 157.861 ;
     RECT  10.812 156.419 11.352 156.565 ;
     RECT  6.312 156.421 7.8 157.237 ;
     RECT  2.712 156.709 4.08 157.667 ;
     RECT  4.104 156.709 5.1 157.667 ;
     RECT  38.184 156.709 39.36 157.043 ;
     RECT  6.312 157.237 7.632 159.061 ;
     RECT  16.344 157.285 17.712 157.763 ;
     RECT  16.212 157.763 17.712 158.149 ;
     RECT  25.56 157.861 26.544 159.395 ;
     RECT  13.704 157.909 15.12 159.397 ;
     RECT  16.212 158.149 17.28 159.397 ;
     RECT  35.352 158.389 36.48 159.059 ;
     RECT  0.24 158.437 1.68 158.52 ;
     RECT  28.104 158.483 29.088 163.139 ;
     RECT  0.216 158.52 1.68 158.579 ;
     RECT  35.256 159.059 36.48 160.549 ;
     RECT  6.312 159.061 7.392 159.589 ;
     RECT  25.176 159.395 26.544 162.421 ;
     RECT  13.704 159.397 14.832 159.973 ;
     RECT  5.412 159.635 6.816 162.853 ;
     RECT  37.812 159.779 37.944 161.125 ;
     RECT  13.752 159.973 14.832 160.643 ;
     RECT  16.212 160.211 17.28 162.083 ;
     RECT  21.12 160.595 21.3 161.797 ;
     RECT  13.512 160.643 14.832 161.411 ;
     RECT  17.304 160.739 18.6 162.083 ;
     RECT  19.992 161.797 21.3 163.093 ;
     RECT  16.212 162.083 16.584 163.285 ;
     RECT  38.184 162.229 39.264 162.371 ;
     RECT  37.944 162.371 39.264 162.419 ;
     RECT  25.224 162.421 26.496 163.619 ;
     RECT  44.472 162.997 45.6 164.291 ;
     RECT  13.104 163.043 13.2 164.149 ;
     RECT  28.104 163.139 29.28 163.715 ;
     RECT  19.464 163.187 20.832 163.619 ;
     RECT  25.176 163.619 26.496 163.955 ;
     RECT  2.712 163.667 2.808 164.917 ;
     RECT  27.816 163.715 29.28 164.101 ;
     RECT  32.664 163.811 34.128 164.771 ;
     RECT  42.144 163.811 42.9 164.677 ;
     RECT  35.304 163.955 36.48 165.395 ;
     RECT  27.816 164.101 28.8 166.979 ;
     RECT  43.212 164.387 43.608 165.829 ;
     RECT  40.512 164.677 41.664 166.069 ;
     RECT  41.688 164.677 42.9 166.115 ;
     RECT  30.504 164.771 31.92 167.365 ;
     RECT  2.712 165.059 2.808 166.357 ;
     RECT  35.304 165.395 35.352 166.453 ;
     RECT  4.512 165.827 5.1 166.357 ;
     RECT  41.4 166.115 42.9 168.707 ;
     RECT  6.36 166.163 7.8 167.075 ;
     RECT  18.912 166.213 20.256 167.749 ;
     RECT  2.712 166.357 3.936 166.499 ;
     RECT  3.96 166.357 5.1 166.499 ;
     RECT  30.6 167.365 31.92 168.275 ;
     RECT  26.592 167.747 26.7 169.189 ;
     RECT  18.912 167.749 20.208 171.059 ;
     RECT  20.28 167.795 21.3 167.987 ;
     RECT  20.232 167.987 21.3 171.059 ;
     RECT  37.812 168.179 37.944 169.237 ;
     RECT  30.6 168.275 32.1 171.779 ;
     RECT  13.104 168.419 13.2 169.861 ;
     RECT  38.76 169.237 40.2 169.765 ;
     RECT  22.488 169.525 24 170.867 ;
     RECT  38.76 169.765 39.888 171.779 ;
     RECT  13.104 170.291 13.2 171.541 ;
     RECT  32.568 170.389 33.936 170.483 ;
     RECT  32.412 170.483 33.936 172.067 ;
     RECT  8.232 170.579 9.6 170.915 ;
  END
END dsfd_m2l_vr_512x1__hix_SW
END LIBRARY
